VERSION 5.8 ;
BUSBITCHARS "[]" ;
DIVIDERCHAR "/" ;
UNITS
    DATABASE MICRONS 1000 ;
END UNITS

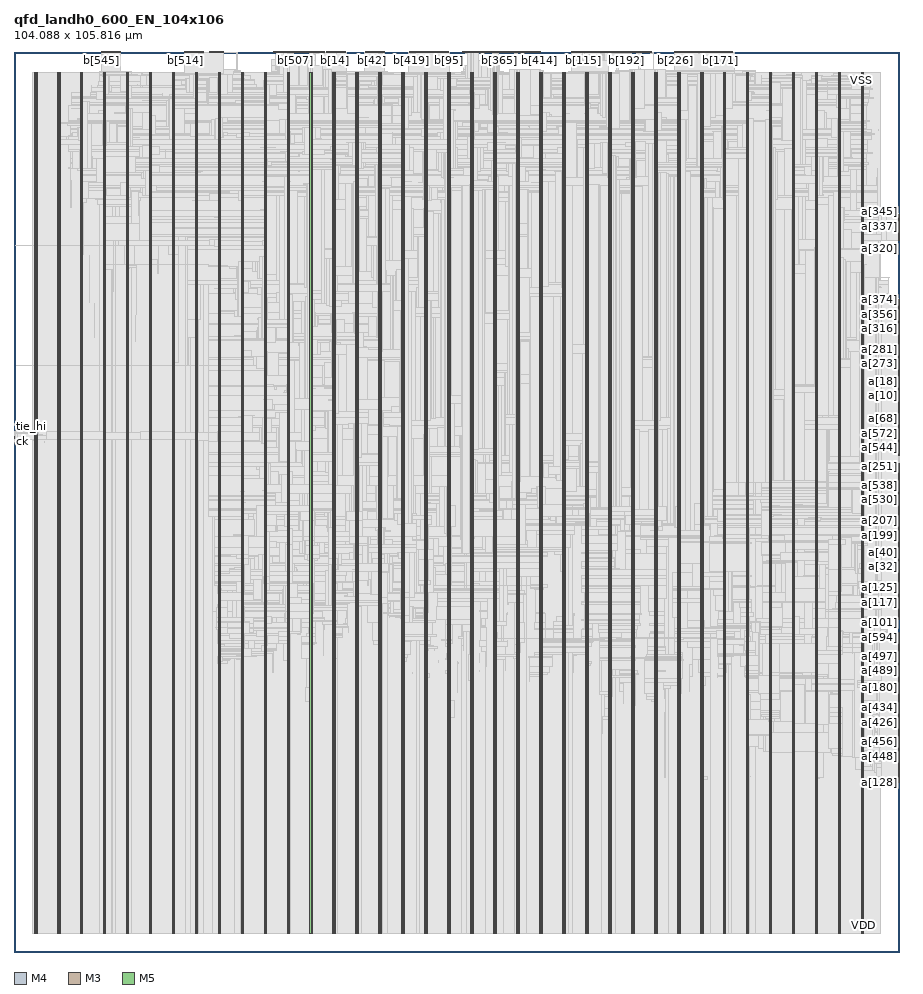
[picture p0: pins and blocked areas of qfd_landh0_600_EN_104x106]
MACRO qfd_landh0_600_EN_104x106
  FOREIGN qfd_landh0_600_EN_104x106 0 0 ;
  CLASS BLOCK ;
  SIZE 104.088 BY 105.816 ;
  PIN a[0]
    DIRECTION INPUT ;
    USE SIGNAL ;
    PORT
      LAYER M4 ;
        RECT  104.004 64.464 104.088 64.488 ;
    END
  END a[0]
  PIN a[100]
    DIRECTION INPUT ;
    USE SIGNAL ;
    PORT
      LAYER M4 ;
        RECT  104.004 39.504 104.088 39.528 ;
    END
  END a[100]
  PIN a[101]
    DIRECTION INPUT ;
    USE SIGNAL ;
    PORT
      LAYER M4 ;
        RECT  104.004 39.6 104.088 39.624 ;
    END
  END a[101]
  PIN a[102]
    DIRECTION INPUT ;
    USE SIGNAL ;
    PORT
      LAYER M4 ;
        RECT  104.004 39.696 104.088 39.72 ;
    END
  END a[102]
  PIN a[103]
    DIRECTION INPUT ;
    USE SIGNAL ;
    PORT
      LAYER M4 ;
        RECT  104.004 39.792 104.088 39.816 ;
    END
  END a[103]
  PIN a[104]
    DIRECTION INPUT ;
    USE SIGNAL ;
    PORT
      LAYER M4 ;
        RECT  104.004 39.888 104.088 39.912 ;
    END
  END a[104]
  PIN a[105]
    DIRECTION INPUT ;
    USE SIGNAL ;
    PORT
      LAYER M4 ;
        RECT  104.004 39.984 104.088 40.008 ;
    END
  END a[105]
  PIN a[106]
    DIRECTION INPUT ;
    USE SIGNAL ;
    PORT
      LAYER M4 ;
        RECT  104.004 40.08 104.088 40.104 ;
    END
  END a[106]
  PIN a[107]
    DIRECTION INPUT ;
    USE SIGNAL ;
    PORT
      LAYER M4 ;
        RECT  104.004 40.176 104.088 40.2 ;
    END
  END a[107]
  PIN a[108]
    DIRECTION INPUT ;
    USE SIGNAL ;
    PORT
      LAYER M4 ;
        RECT  104.004 40.272 104.088 40.296 ;
    END
  END a[108]
  PIN a[109]
    DIRECTION INPUT ;
    USE SIGNAL ;
    PORT
      LAYER M4 ;
        RECT  104.004 40.368 104.088 40.392 ;
    END
  END a[109]
  PIN a[10]
    DIRECTION INPUT ;
    USE SIGNAL ;
    PORT
      LAYER M4 ;
        RECT  104.004 65.424 104.088 65.448 ;
    END
  END a[10]
  PIN a[110]
    DIRECTION INPUT ;
    USE SIGNAL ;
    PORT
      LAYER M4 ;
        RECT  104.004 40.464 104.088 40.488 ;
    END
  END a[110]
  PIN a[111]
    DIRECTION INPUT ;
    USE SIGNAL ;
    PORT
      LAYER M4 ;
        RECT  104.004 40.56 104.088 40.584 ;
    END
  END a[111]
  PIN a[112]
    DIRECTION INPUT ;
    USE SIGNAL ;
    PORT
      LAYER M4 ;
        RECT  104.004 40.656 104.088 40.68 ;
    END
  END a[112]
  PIN a[113]
    DIRECTION INPUT ;
    USE SIGNAL ;
    PORT
      LAYER M4 ;
        RECT  104.004 40.752 104.088 40.776 ;
    END
  END a[113]
  PIN a[114]
    DIRECTION INPUT ;
    USE SIGNAL ;
    PORT
      LAYER M4 ;
        RECT  104.004 40.848 104.088 40.872 ;
    END
  END a[114]
  PIN a[115]
    DIRECTION INPUT ;
    USE SIGNAL ;
    PORT
      LAYER M4 ;
        RECT  104.004 40.944 104.088 40.968 ;
    END
  END a[115]
  PIN a[116]
    DIRECTION INPUT ;
    USE SIGNAL ;
    PORT
      LAYER M4 ;
        RECT  104.004 41.04 104.088 41.064 ;
    END
  END a[116]
  PIN a[117]
    DIRECTION INPUT ;
    USE SIGNAL ;
    PORT
      LAYER M4 ;
        RECT  104.004 41.136 104.088 41.16 ;
    END
  END a[117]
  PIN a[118]
    DIRECTION INPUT ;
    USE SIGNAL ;
    PORT
      LAYER M4 ;
        RECT  104.004 41.232 104.088 41.256 ;
    END
  END a[118]
  PIN a[119]
    DIRECTION INPUT ;
    USE SIGNAL ;
    PORT
      LAYER M4 ;
        RECT  104.004 41.328 104.088 41.352 ;
    END
  END a[119]
  PIN a[11]
    DIRECTION INPUT ;
    USE SIGNAL ;
    PORT
      LAYER M4 ;
        RECT  104.004 65.52 104.088 65.544 ;
    END
  END a[11]
  PIN a[120]
    DIRECTION INPUT ;
    USE SIGNAL ;
    PORT
      LAYER M4 ;
        RECT  104.004 41.424 104.088 41.448 ;
    END
  END a[120]
  PIN a[121]
    DIRECTION INPUT ;
    USE SIGNAL ;
    PORT
      LAYER M4 ;
        RECT  104.004 41.52 104.088 41.544 ;
    END
  END a[121]
  PIN a[122]
    DIRECTION INPUT ;
    USE SIGNAL ;
    PORT
      LAYER M4 ;
        RECT  104.004 41.616 104.088 41.64 ;
    END
  END a[122]
  PIN a[123]
    DIRECTION INPUT ;
    USE SIGNAL ;
    PORT
      LAYER M4 ;
        RECT  104.004 41.712 104.088 41.736 ;
    END
  END a[123]
  PIN a[124]
    DIRECTION INPUT ;
    USE SIGNAL ;
    PORT
      LAYER M4 ;
        RECT  104.004 41.808 104.088 41.832 ;
    END
  END a[124]
  PIN a[125]
    DIRECTION INPUT ;
    USE SIGNAL ;
    PORT
      LAYER M4 ;
        RECT  104.004 41.904 104.088 41.928 ;
    END
  END a[125]
  PIN a[126]
    DIRECTION INPUT ;
    USE SIGNAL ;
    PORT
      LAYER M4 ;
        RECT  104.004 42 104.088 42.024 ;
    END
  END a[126]
  PIN a[127]
    DIRECTION INPUT ;
    USE SIGNAL ;
    PORT
      LAYER M4 ;
        RECT  104.004 42.096 104.088 42.12 ;
    END
  END a[127]
  PIN a[128]
    DIRECTION INPUT ;
    USE SIGNAL ;
    PORT
      LAYER M4 ;
        RECT  104.004 19.92 104.088 19.944 ;
    END
  END a[128]
  PIN a[129]
    DIRECTION INPUT ;
    USE SIGNAL ;
    PORT
      LAYER M4 ;
        RECT  104.004 20.016 104.088 20.04 ;
    END
  END a[129]
  PIN a[12]
    DIRECTION INPUT ;
    USE SIGNAL ;
    PORT
      LAYER M4 ;
        RECT  104.004 65.616 104.088 65.64 ;
    END
  END a[12]
  PIN a[130]
    DIRECTION INPUT ;
    USE SIGNAL ;
    PORT
      LAYER M4 ;
        RECT  104.004 20.112 104.088 20.136 ;
    END
  END a[130]
  PIN a[131]
    DIRECTION INPUT ;
    USE SIGNAL ;
    PORT
      LAYER M4 ;
        RECT  104.004 20.208 104.088 20.232 ;
    END
  END a[131]
  PIN a[132]
    DIRECTION INPUT ;
    USE SIGNAL ;
    PORT
      LAYER M4 ;
        RECT  104.004 20.304 104.088 20.328 ;
    END
  END a[132]
  PIN a[133]
    DIRECTION INPUT ;
    USE SIGNAL ;
    PORT
      LAYER M4 ;
        RECT  104.004 20.4 104.088 20.424 ;
    END
  END a[133]
  PIN a[134]
    DIRECTION INPUT ;
    USE SIGNAL ;
    PORT
      LAYER M4 ;
        RECT  104.004 20.496 104.088 20.52 ;
    END
  END a[134]
  PIN a[135]
    DIRECTION INPUT ;
    USE SIGNAL ;
    PORT
      LAYER M4 ;
        RECT  104.004 20.592 104.088 20.616 ;
    END
  END a[135]
  PIN a[136]
    DIRECTION INPUT ;
    USE SIGNAL ;
    PORT
      LAYER M4 ;
        RECT  104.004 20.688 104.088 20.712 ;
    END
  END a[136]
  PIN a[137]
    DIRECTION INPUT ;
    USE SIGNAL ;
    PORT
      LAYER M4 ;
        RECT  104.004 20.784 104.088 20.808 ;
    END
  END a[137]
  PIN a[138]
    DIRECTION INPUT ;
    USE SIGNAL ;
    PORT
      LAYER M4 ;
        RECT  104.004 20.88 104.088 20.904 ;
    END
  END a[138]
  PIN a[139]
    DIRECTION INPUT ;
    USE SIGNAL ;
    PORT
      LAYER M4 ;
        RECT  104.004 20.976 104.088 21 ;
    END
  END a[139]
  PIN a[13]
    DIRECTION INPUT ;
    USE SIGNAL ;
    PORT
      LAYER M4 ;
        RECT  104.004 65.712 104.088 65.736 ;
    END
  END a[13]
  PIN a[140]
    DIRECTION INPUT ;
    USE SIGNAL ;
    PORT
      LAYER M4 ;
        RECT  104.004 21.072 104.088 21.096 ;
    END
  END a[140]
  PIN a[141]
    DIRECTION INPUT ;
    USE SIGNAL ;
    PORT
      LAYER M4 ;
        RECT  104.004 21.168 104.088 21.192 ;
    END
  END a[141]
  PIN a[142]
    DIRECTION INPUT ;
    USE SIGNAL ;
    PORT
      LAYER M4 ;
        RECT  104.004 21.264 104.088 21.288 ;
    END
  END a[142]
  PIN a[143]
    DIRECTION INPUT ;
    USE SIGNAL ;
    PORT
      LAYER M4 ;
        RECT  104.004 21.36 104.088 21.384 ;
    END
  END a[143]
  PIN a[144]
    DIRECTION INPUT ;
    USE SIGNAL ;
    PORT
      LAYER M4 ;
        RECT  104.004 21.456 104.088 21.48 ;
    END
  END a[144]
  PIN a[145]
    DIRECTION INPUT ;
    USE SIGNAL ;
    PORT
      LAYER M4 ;
        RECT  104.004 21.552 104.088 21.576 ;
    END
  END a[145]
  PIN a[146]
    DIRECTION INPUT ;
    USE SIGNAL ;
    PORT
      LAYER M4 ;
        RECT  104.004 21.648 104.088 21.672 ;
    END
  END a[146]
  PIN a[147]
    DIRECTION INPUT ;
    USE SIGNAL ;
    PORT
      LAYER M4 ;
        RECT  104.004 21.744 104.088 21.768 ;
    END
  END a[147]
  PIN a[148]
    DIRECTION INPUT ;
    USE SIGNAL ;
    PORT
      LAYER M4 ;
        RECT  104.004 21.84 104.088 21.864 ;
    END
  END a[148]
  PIN a[149]
    DIRECTION INPUT ;
    USE SIGNAL ;
    PORT
      LAYER M4 ;
        RECT  104.004 21.936 104.088 21.96 ;
    END
  END a[149]
  PIN a[14]
    DIRECTION INPUT ;
    USE SIGNAL ;
    PORT
      LAYER M4 ;
        RECT  104.004 65.808 104.088 65.832 ;
    END
  END a[14]
  PIN a[150]
    DIRECTION INPUT ;
    USE SIGNAL ;
    PORT
      LAYER M4 ;
        RECT  104.004 22.032 104.088 22.056 ;
    END
  END a[150]
  PIN a[151]
    DIRECTION INPUT ;
    USE SIGNAL ;
    PORT
      LAYER M4 ;
        RECT  104.004 22.128 104.088 22.152 ;
    END
  END a[151]
  PIN a[152]
    DIRECTION INPUT ;
    USE SIGNAL ;
    PORT
      LAYER M4 ;
        RECT  104.004 22.224 104.088 22.248 ;
    END
  END a[152]
  PIN a[153]
    DIRECTION INPUT ;
    USE SIGNAL ;
    PORT
      LAYER M4 ;
        RECT  104.004 22.32 104.088 22.344 ;
    END
  END a[153]
  PIN a[154]
    DIRECTION INPUT ;
    USE SIGNAL ;
    PORT
      LAYER M4 ;
        RECT  104.004 22.416 104.088 22.44 ;
    END
  END a[154]
  PIN a[155]
    DIRECTION INPUT ;
    USE SIGNAL ;
    PORT
      LAYER M4 ;
        RECT  104.004 22.512 104.088 22.536 ;
    END
  END a[155]
  PIN a[156]
    DIRECTION INPUT ;
    USE SIGNAL ;
    PORT
      LAYER M4 ;
        RECT  104.004 22.608 104.088 22.632 ;
    END
  END a[156]
  PIN a[157]
    DIRECTION INPUT ;
    USE SIGNAL ;
    PORT
      LAYER M4 ;
        RECT  104.004 22.704 104.088 22.728 ;
    END
  END a[157]
  PIN a[158]
    DIRECTION INPUT ;
    USE SIGNAL ;
    PORT
      LAYER M4 ;
        RECT  104.004 22.8 104.088 22.824 ;
    END
  END a[158]
  PIN a[159]
    DIRECTION INPUT ;
    USE SIGNAL ;
    PORT
      LAYER M4 ;
        RECT  104.004 22.896 104.088 22.92 ;
    END
  END a[159]
  PIN a[15]
    DIRECTION INPUT ;
    USE SIGNAL ;
    PORT
      LAYER M4 ;
        RECT  104.004 65.904 104.088 65.928 ;
    END
  END a[15]
  PIN a[160]
    DIRECTION INPUT ;
    USE SIGNAL ;
    PORT
      LAYER M4 ;
        RECT  104.004 29.136 104.088 29.16 ;
    END
  END a[160]
  PIN a[161]
    DIRECTION INPUT ;
    USE SIGNAL ;
    PORT
      LAYER M4 ;
        RECT  104.004 29.232 104.088 29.256 ;
    END
  END a[161]
  PIN a[162]
    DIRECTION INPUT ;
    USE SIGNAL ;
    PORT
      LAYER M4 ;
        RECT  104.004 29.328 104.088 29.352 ;
    END
  END a[162]
  PIN a[163]
    DIRECTION INPUT ;
    USE SIGNAL ;
    PORT
      LAYER M4 ;
        RECT  104.004 29.424 104.088 29.448 ;
    END
  END a[163]
  PIN a[164]
    DIRECTION INPUT ;
    USE SIGNAL ;
    PORT
      LAYER M4 ;
        RECT  104.004 29.52 104.088 29.544 ;
    END
  END a[164]
  PIN a[165]
    DIRECTION INPUT ;
    USE SIGNAL ;
    PORT
      LAYER M4 ;
        RECT  104.004 29.616 104.088 29.64 ;
    END
  END a[165]
  PIN a[166]
    DIRECTION INPUT ;
    USE SIGNAL ;
    PORT
      LAYER M4 ;
        RECT  104.004 29.712 104.088 29.736 ;
    END
  END a[166]
  PIN a[167]
    DIRECTION INPUT ;
    USE SIGNAL ;
    PORT
      LAYER M4 ;
        RECT  104.004 29.808 104.088 29.832 ;
    END
  END a[167]
  PIN a[168]
    DIRECTION INPUT ;
    USE SIGNAL ;
    PORT
      LAYER M4 ;
        RECT  104.004 29.904 104.088 29.928 ;
    END
  END a[168]
  PIN a[169]
    DIRECTION INPUT ;
    USE SIGNAL ;
    PORT
      LAYER M4 ;
        RECT  104.004 30 104.088 30.024 ;
    END
  END a[169]
  PIN a[16]
    DIRECTION INPUT ;
    USE SIGNAL ;
    PORT
      LAYER M4 ;
        RECT  104.004 66 104.088 66.024 ;
    END
  END a[16]
  PIN a[170]
    DIRECTION INPUT ;
    USE SIGNAL ;
    PORT
      LAYER M4 ;
        RECT  104.004 30.096 104.088 30.12 ;
    END
  END a[170]
  PIN a[171]
    DIRECTION INPUT ;
    USE SIGNAL ;
    PORT
      LAYER M4 ;
        RECT  104.004 30.192 104.088 30.216 ;
    END
  END a[171]
  PIN a[172]
    DIRECTION INPUT ;
    USE SIGNAL ;
    PORT
      LAYER M4 ;
        RECT  104.004 30.288 104.088 30.312 ;
    END
  END a[172]
  PIN a[173]
    DIRECTION INPUT ;
    USE SIGNAL ;
    PORT
      LAYER M4 ;
        RECT  104.004 30.384 104.088 30.408 ;
    END
  END a[173]
  PIN a[174]
    DIRECTION INPUT ;
    USE SIGNAL ;
    PORT
      LAYER M4 ;
        RECT  104.004 30.48 104.088 30.504 ;
    END
  END a[174]
  PIN a[175]
    DIRECTION INPUT ;
    USE SIGNAL ;
    PORT
      LAYER M4 ;
        RECT  104.004 30.576 104.088 30.6 ;
    END
  END a[175]
  PIN a[176]
    DIRECTION INPUT ;
    USE SIGNAL ;
    PORT
      LAYER M4 ;
        RECT  104.004 30.672 104.088 30.696 ;
    END
  END a[176]
  PIN a[177]
    DIRECTION INPUT ;
    USE SIGNAL ;
    PORT
      LAYER M4 ;
        RECT  104.004 30.768 104.088 30.792 ;
    END
  END a[177]
  PIN a[178]
    DIRECTION INPUT ;
    USE SIGNAL ;
    PORT
      LAYER M4 ;
        RECT  104.004 30.864 104.088 30.888 ;
    END
  END a[178]
  PIN a[179]
    DIRECTION INPUT ;
    USE SIGNAL ;
    PORT
      LAYER M4 ;
        RECT  104.004 30.96 104.088 30.984 ;
    END
  END a[179]
  PIN a[17]
    DIRECTION INPUT ;
    USE SIGNAL ;
    PORT
      LAYER M4 ;
        RECT  104.004 66.096 104.088 66.12 ;
    END
  END a[17]
  PIN a[180]
    DIRECTION INPUT ;
    USE SIGNAL ;
    PORT
      LAYER M4 ;
        RECT  104.004 31.056 104.088 31.08 ;
    END
  END a[180]
  PIN a[181]
    DIRECTION INPUT ;
    USE SIGNAL ;
    PORT
      LAYER M4 ;
        RECT  104.004 31.152 104.088 31.176 ;
    END
  END a[181]
  PIN a[182]
    DIRECTION INPUT ;
    USE SIGNAL ;
    PORT
      LAYER M4 ;
        RECT  104.004 31.248 104.088 31.272 ;
    END
  END a[182]
  PIN a[183]
    DIRECTION INPUT ;
    USE SIGNAL ;
    PORT
      LAYER M4 ;
        RECT  104.004 31.344 104.088 31.368 ;
    END
  END a[183]
  PIN a[184]
    DIRECTION INPUT ;
    USE SIGNAL ;
    PORT
      LAYER M4 ;
        RECT  104.004 31.44 104.088 31.464 ;
    END
  END a[184]
  PIN a[185]
    DIRECTION INPUT ;
    USE SIGNAL ;
    PORT
      LAYER M4 ;
        RECT  104.004 31.536 104.088 31.56 ;
    END
  END a[185]
  PIN a[186]
    DIRECTION INPUT ;
    USE SIGNAL ;
    PORT
      LAYER M4 ;
        RECT  104.004 31.632 104.088 31.656 ;
    END
  END a[186]
  PIN a[187]
    DIRECTION INPUT ;
    USE SIGNAL ;
    PORT
      LAYER M4 ;
        RECT  104.004 31.728 104.088 31.752 ;
    END
  END a[187]
  PIN a[188]
    DIRECTION INPUT ;
    USE SIGNAL ;
    PORT
      LAYER M4 ;
        RECT  104.004 31.824 104.088 31.848 ;
    END
  END a[188]
  PIN a[189]
    DIRECTION INPUT ;
    USE SIGNAL ;
    PORT
      LAYER M4 ;
        RECT  104.004 31.92 104.088 31.944 ;
    END
  END a[189]
  PIN a[18]
    DIRECTION INPUT ;
    USE SIGNAL ;
    PORT
      LAYER M4 ;
        RECT  104.004 66.192 104.088 66.216 ;
    END
  END a[18]
  PIN a[190]
    DIRECTION INPUT ;
    USE SIGNAL ;
    PORT
      LAYER M4 ;
        RECT  104.004 32.016 104.088 32.04 ;
    END
  END a[190]
  PIN a[191]
    DIRECTION INPUT ;
    USE SIGNAL ;
    PORT
      LAYER M4 ;
        RECT  104.004 32.112 104.088 32.136 ;
    END
  END a[191]
  PIN a[192]
    DIRECTION INPUT ;
    USE SIGNAL ;
    PORT
      LAYER M4 ;
        RECT  104.004 48.336 104.088 48.36 ;
    END
  END a[192]
  PIN a[193]
    DIRECTION INPUT ;
    USE SIGNAL ;
    PORT
      LAYER M4 ;
        RECT  104.004 48.432 104.088 48.456 ;
    END
  END a[193]
  PIN a[194]
    DIRECTION INPUT ;
    USE SIGNAL ;
    PORT
      LAYER M4 ;
        RECT  104.004 48.528 104.088 48.552 ;
    END
  END a[194]
  PIN a[195]
    DIRECTION INPUT ;
    USE SIGNAL ;
    PORT
      LAYER M4 ;
        RECT  104.004 48.624 104.088 48.648 ;
    END
  END a[195]
  PIN a[196]
    DIRECTION INPUT ;
    USE SIGNAL ;
    PORT
      LAYER M4 ;
        RECT  104.004 48.72 104.088 48.744 ;
    END
  END a[196]
  PIN a[197]
    DIRECTION INPUT ;
    USE SIGNAL ;
    PORT
      LAYER M4 ;
        RECT  104.004 48.816 104.088 48.84 ;
    END
  END a[197]
  PIN a[198]
    DIRECTION INPUT ;
    USE SIGNAL ;
    PORT
      LAYER M4 ;
        RECT  104.004 48.912 104.088 48.936 ;
    END
  END a[198]
  PIN a[199]
    DIRECTION INPUT ;
    USE SIGNAL ;
    PORT
      LAYER M4 ;
        RECT  104.004 49.008 104.088 49.032 ;
    END
  END a[199]
  PIN a[19]
    DIRECTION INPUT ;
    USE SIGNAL ;
    PORT
      LAYER M4 ;
        RECT  104.004 66.288 104.088 66.312 ;
    END
  END a[19]
  PIN a[1]
    DIRECTION INPUT ;
    USE SIGNAL ;
    PORT
      LAYER M4 ;
        RECT  104.004 64.56 104.088 64.584 ;
    END
  END a[1]
  PIN a[200]
    DIRECTION INPUT ;
    USE SIGNAL ;
    PORT
      LAYER M4 ;
        RECT  104.004 49.104 104.088 49.128 ;
    END
  END a[200]
  PIN a[201]
    DIRECTION INPUT ;
    USE SIGNAL ;
    PORT
      LAYER M4 ;
        RECT  104.004 49.2 104.088 49.224 ;
    END
  END a[201]
  PIN a[202]
    DIRECTION INPUT ;
    USE SIGNAL ;
    PORT
      LAYER M4 ;
        RECT  104.004 49.296 104.088 49.32 ;
    END
  END a[202]
  PIN a[203]
    DIRECTION INPUT ;
    USE SIGNAL ;
    PORT
      LAYER M4 ;
        RECT  104.004 49.392 104.088 49.416 ;
    END
  END a[203]
  PIN a[204]
    DIRECTION INPUT ;
    USE SIGNAL ;
    PORT
      LAYER M4 ;
        RECT  104.004 49.488 104.088 49.512 ;
    END
  END a[204]
  PIN a[205]
    DIRECTION INPUT ;
    USE SIGNAL ;
    PORT
      LAYER M4 ;
        RECT  104.004 49.584 104.088 49.608 ;
    END
  END a[205]
  PIN a[206]
    DIRECTION INPUT ;
    USE SIGNAL ;
    PORT
      LAYER M4 ;
        RECT  104.004 49.68 104.088 49.704 ;
    END
  END a[206]
  PIN a[207]
    DIRECTION INPUT ;
    USE SIGNAL ;
    PORT
      LAYER M4 ;
        RECT  104.004 49.776 104.088 49.8 ;
    END
  END a[207]
  PIN a[208]
    DIRECTION INPUT ;
    USE SIGNAL ;
    PORT
      LAYER M4 ;
        RECT  104.004 49.872 104.088 49.896 ;
    END
  END a[208]
  PIN a[209]
    DIRECTION INPUT ;
    USE SIGNAL ;
    PORT
      LAYER M4 ;
        RECT  104.004 49.968 104.088 49.992 ;
    END
  END a[209]
  PIN a[20]
    DIRECTION INPUT ;
    USE SIGNAL ;
    PORT
      LAYER M4 ;
        RECT  104.004 66.384 104.088 66.408 ;
    END
  END a[20]
  PIN a[210]
    DIRECTION INPUT ;
    USE SIGNAL ;
    PORT
      LAYER M4 ;
        RECT  104.004 50.064 104.088 50.088 ;
    END
  END a[210]
  PIN a[211]
    DIRECTION INPUT ;
    USE SIGNAL ;
    PORT
      LAYER M4 ;
        RECT  104.004 50.16 104.088 50.184 ;
    END
  END a[211]
  PIN a[212]
    DIRECTION INPUT ;
    USE SIGNAL ;
    PORT
      LAYER M4 ;
        RECT  104.004 50.256 104.088 50.28 ;
    END
  END a[212]
  PIN a[213]
    DIRECTION INPUT ;
    USE SIGNAL ;
    PORT
      LAYER M4 ;
        RECT  104.004 50.352 104.088 50.376 ;
    END
  END a[213]
  PIN a[214]
    DIRECTION INPUT ;
    USE SIGNAL ;
    PORT
      LAYER M4 ;
        RECT  104.004 50.448 104.088 50.472 ;
    END
  END a[214]
  PIN a[215]
    DIRECTION INPUT ;
    USE SIGNAL ;
    PORT
      LAYER M4 ;
        RECT  104.004 50.544 104.088 50.568 ;
    END
  END a[215]
  PIN a[216]
    DIRECTION INPUT ;
    USE SIGNAL ;
    PORT
      LAYER M4 ;
        RECT  104.004 50.64 104.088 50.664 ;
    END
  END a[216]
  PIN a[217]
    DIRECTION INPUT ;
    USE SIGNAL ;
    PORT
      LAYER M4 ;
        RECT  104.004 50.736 104.088 50.76 ;
    END
  END a[217]
  PIN a[218]
    DIRECTION INPUT ;
    USE SIGNAL ;
    PORT
      LAYER M4 ;
        RECT  104.004 50.832 104.088 50.856 ;
    END
  END a[218]
  PIN a[219]
    DIRECTION INPUT ;
    USE SIGNAL ;
    PORT
      LAYER M4 ;
        RECT  104.004 50.928 104.088 50.952 ;
    END
  END a[219]
  PIN a[21]
    DIRECTION INPUT ;
    USE SIGNAL ;
    PORT
      LAYER M4 ;
        RECT  104.004 66.48 104.088 66.504 ;
    END
  END a[21]
  PIN a[220]
    DIRECTION INPUT ;
    USE SIGNAL ;
    PORT
      LAYER M4 ;
        RECT  104.004 51.024 104.088 51.048 ;
    END
  END a[220]
  PIN a[221]
    DIRECTION INPUT ;
    USE SIGNAL ;
    PORT
      LAYER M4 ;
        RECT  104.004 51.12 104.088 51.144 ;
    END
  END a[221]
  PIN a[222]
    DIRECTION INPUT ;
    USE SIGNAL ;
    PORT
      LAYER M4 ;
        RECT  104.004 51.216 104.088 51.24 ;
    END
  END a[222]
  PIN a[223]
    DIRECTION INPUT ;
    USE SIGNAL ;
    PORT
      LAYER M4 ;
        RECT  104.004 51.312 104.088 51.336 ;
    END
  END a[223]
  PIN a[224]
    DIRECTION INPUT ;
    USE SIGNAL ;
    PORT
      LAYER M4 ;
        RECT  104.004 54.48 104.088 54.504 ;
    END
  END a[224]
  PIN a[225]
    DIRECTION INPUT ;
    USE SIGNAL ;
    PORT
      LAYER M4 ;
        RECT  104.004 54.576 104.088 54.6 ;
    END
  END a[225]
  PIN a[226]
    DIRECTION INPUT ;
    USE SIGNAL ;
    PORT
      LAYER M4 ;
        RECT  104.004 54.672 104.088 54.696 ;
    END
  END a[226]
  PIN a[227]
    DIRECTION INPUT ;
    USE SIGNAL ;
    PORT
      LAYER M4 ;
        RECT  104.004 54.768 104.088 54.792 ;
    END
  END a[227]
  PIN a[228]
    DIRECTION INPUT ;
    USE SIGNAL ;
    PORT
      LAYER M4 ;
        RECT  104.004 54.864 104.088 54.888 ;
    END
  END a[228]
  PIN a[229]
    DIRECTION INPUT ;
    USE SIGNAL ;
    PORT
      LAYER M4 ;
        RECT  104.004 54.96 104.088 54.984 ;
    END
  END a[229]
  PIN a[22]
    DIRECTION INPUT ;
    USE SIGNAL ;
    PORT
      LAYER M4 ;
        RECT  104.004 66.576 104.088 66.6 ;
    END
  END a[22]
  PIN a[230]
    DIRECTION INPUT ;
    USE SIGNAL ;
    PORT
      LAYER M4 ;
        RECT  104.004 55.056 104.088 55.08 ;
    END
  END a[230]
  PIN a[231]
    DIRECTION INPUT ;
    USE SIGNAL ;
    PORT
      LAYER M4 ;
        RECT  104.004 55.152 104.088 55.176 ;
    END
  END a[231]
  PIN a[232]
    DIRECTION INPUT ;
    USE SIGNAL ;
    PORT
      LAYER M4 ;
        RECT  104.004 55.248 104.088 55.272 ;
    END
  END a[232]
  PIN a[233]
    DIRECTION INPUT ;
    USE SIGNAL ;
    PORT
      LAYER M4 ;
        RECT  104.004 55.344 104.088 55.368 ;
    END
  END a[233]
  PIN a[234]
    DIRECTION INPUT ;
    USE SIGNAL ;
    PORT
      LAYER M4 ;
        RECT  104.004 55.44 104.088 55.464 ;
    END
  END a[234]
  PIN a[235]
    DIRECTION INPUT ;
    USE SIGNAL ;
    PORT
      LAYER M4 ;
        RECT  104.004 55.536 104.088 55.56 ;
    END
  END a[235]
  PIN a[236]
    DIRECTION INPUT ;
    USE SIGNAL ;
    PORT
      LAYER M4 ;
        RECT  104.004 55.632 104.088 55.656 ;
    END
  END a[236]
  PIN a[237]
    DIRECTION INPUT ;
    USE SIGNAL ;
    PORT
      LAYER M4 ;
        RECT  104.004 55.728 104.088 55.752 ;
    END
  END a[237]
  PIN a[238]
    DIRECTION INPUT ;
    USE SIGNAL ;
    PORT
      LAYER M4 ;
        RECT  104.004 55.824 104.088 55.848 ;
    END
  END a[238]
  PIN a[239]
    DIRECTION INPUT ;
    USE SIGNAL ;
    PORT
      LAYER M4 ;
        RECT  104.004 55.92 104.088 55.944 ;
    END
  END a[239]
  PIN a[23]
    DIRECTION INPUT ;
    USE SIGNAL ;
    PORT
      LAYER M4 ;
        RECT  104.004 66.672 104.088 66.696 ;
    END
  END a[23]
  PIN a[240]
    DIRECTION INPUT ;
    USE SIGNAL ;
    PORT
      LAYER M4 ;
        RECT  104.004 56.016 104.088 56.04 ;
    END
  END a[240]
  PIN a[241]
    DIRECTION INPUT ;
    USE SIGNAL ;
    PORT
      LAYER M4 ;
        RECT  104.004 56.112 104.088 56.136 ;
    END
  END a[241]
  PIN a[242]
    DIRECTION INPUT ;
    USE SIGNAL ;
    PORT
      LAYER M4 ;
        RECT  104.004 56.208 104.088 56.232 ;
    END
  END a[242]
  PIN a[243]
    DIRECTION INPUT ;
    USE SIGNAL ;
    PORT
      LAYER M4 ;
        RECT  104.004 56.304 104.088 56.328 ;
    END
  END a[243]
  PIN a[244]
    DIRECTION INPUT ;
    USE SIGNAL ;
    PORT
      LAYER M4 ;
        RECT  104.004 56.4 104.088 56.424 ;
    END
  END a[244]
  PIN a[245]
    DIRECTION INPUT ;
    USE SIGNAL ;
    PORT
      LAYER M4 ;
        RECT  104.004 56.496 104.088 56.52 ;
    END
  END a[245]
  PIN a[246]
    DIRECTION INPUT ;
    USE SIGNAL ;
    PORT
      LAYER M4 ;
        RECT  104.004 56.592 104.088 56.616 ;
    END
  END a[246]
  PIN a[247]
    DIRECTION INPUT ;
    USE SIGNAL ;
    PORT
      LAYER M4 ;
        RECT  104.004 56.688 104.088 56.712 ;
    END
  END a[247]
  PIN a[248]
    DIRECTION INPUT ;
    USE SIGNAL ;
    PORT
      LAYER M4 ;
        RECT  104.004 56.784 104.088 56.808 ;
    END
  END a[248]
  PIN a[249]
    DIRECTION INPUT ;
    USE SIGNAL ;
    PORT
      LAYER M4 ;
        RECT  104.004 56.88 104.088 56.904 ;
    END
  END a[249]
  PIN a[24]
    DIRECTION INPUT ;
    USE SIGNAL ;
    PORT
      LAYER M4 ;
        RECT  104.004 66.768 104.088 66.792 ;
    END
  END a[24]
  PIN a[250]
    DIRECTION INPUT ;
    USE SIGNAL ;
    PORT
      LAYER M4 ;
        RECT  104.004 56.976 104.088 57 ;
    END
  END a[250]
  PIN a[251]
    DIRECTION INPUT ;
    USE SIGNAL ;
    PORT
      LAYER M4 ;
        RECT  104.004 57.072 104.088 57.096 ;
    END
  END a[251]
  PIN a[252]
    DIRECTION INPUT ;
    USE SIGNAL ;
    PORT
      LAYER M4 ;
        RECT  104.004 57.168 104.088 57.192 ;
    END
  END a[252]
  PIN a[253]
    DIRECTION INPUT ;
    USE SIGNAL ;
    PORT
      LAYER M4 ;
        RECT  104.004 57.264 104.088 57.288 ;
    END
  END a[253]
  PIN a[254]
    DIRECTION INPUT ;
    USE SIGNAL ;
    PORT
      LAYER M4 ;
        RECT  104.004 57.36 104.088 57.384 ;
    END
  END a[254]
  PIN a[255]
    DIRECTION INPUT ;
    USE SIGNAL ;
    PORT
      LAYER M4 ;
        RECT  104.004 57.456 104.088 57.48 ;
    END
  END a[255]
  PIN a[256]
    DIRECTION INPUT ;
    USE SIGNAL ;
    PORT
      LAYER M4 ;
        RECT  104.004 67.536 104.088 67.56 ;
    END
  END a[256]
  PIN a[257]
    DIRECTION INPUT ;
    USE SIGNAL ;
    PORT
      LAYER M4 ;
        RECT  104.004 67.632 104.088 67.656 ;
    END
  END a[257]
  PIN a[258]
    DIRECTION INPUT ;
    USE SIGNAL ;
    PORT
      LAYER M4 ;
        RECT  104.004 67.728 104.088 67.752 ;
    END
  END a[258]
  PIN a[259]
    DIRECTION INPUT ;
    USE SIGNAL ;
    PORT
      LAYER M4 ;
        RECT  104.004 67.824 104.088 67.848 ;
    END
  END a[259]
  PIN a[25]
    DIRECTION INPUT ;
    USE SIGNAL ;
    PORT
      LAYER M4 ;
        RECT  104.004 66.864 104.088 66.888 ;
    END
  END a[25]
  PIN a[260]
    DIRECTION INPUT ;
    USE SIGNAL ;
    PORT
      LAYER M4 ;
        RECT  104.004 67.92 104.088 67.944 ;
    END
  END a[260]
  PIN a[261]
    DIRECTION INPUT ;
    USE SIGNAL ;
    PORT
      LAYER M4 ;
        RECT  104.004 68.016 104.088 68.04 ;
    END
  END a[261]
  PIN a[262]
    DIRECTION INPUT ;
    USE SIGNAL ;
    PORT
      LAYER M4 ;
        RECT  104.004 68.112 104.088 68.136 ;
    END
  END a[262]
  PIN a[263]
    DIRECTION INPUT ;
    USE SIGNAL ;
    PORT
      LAYER M4 ;
        RECT  104.004 68.208 104.088 68.232 ;
    END
  END a[263]
  PIN a[264]
    DIRECTION INPUT ;
    USE SIGNAL ;
    PORT
      LAYER M4 ;
        RECT  104.004 68.304 104.088 68.328 ;
    END
  END a[264]
  PIN a[265]
    DIRECTION INPUT ;
    USE SIGNAL ;
    PORT
      LAYER M4 ;
        RECT  104.004 68.4 104.088 68.424 ;
    END
  END a[265]
  PIN a[266]
    DIRECTION INPUT ;
    USE SIGNAL ;
    PORT
      LAYER M4 ;
        RECT  104.004 68.496 104.088 68.52 ;
    END
  END a[266]
  PIN a[267]
    DIRECTION INPUT ;
    USE SIGNAL ;
    PORT
      LAYER M4 ;
        RECT  104.004 68.592 104.088 68.616 ;
    END
  END a[267]
  PIN a[268]
    DIRECTION INPUT ;
    USE SIGNAL ;
    PORT
      LAYER M4 ;
        RECT  104.004 68.688 104.088 68.712 ;
    END
  END a[268]
  PIN a[269]
    DIRECTION INPUT ;
    USE SIGNAL ;
    PORT
      LAYER M4 ;
        RECT  104.004 68.784 104.088 68.808 ;
    END
  END a[269]
  PIN a[26]
    DIRECTION INPUT ;
    USE SIGNAL ;
    PORT
      LAYER M4 ;
        RECT  104.004 66.96 104.088 66.984 ;
    END
  END a[26]
  PIN a[270]
    DIRECTION INPUT ;
    USE SIGNAL ;
    PORT
      LAYER M4 ;
        RECT  104.004 68.88 104.088 68.904 ;
    END
  END a[270]
  PIN a[271]
    DIRECTION INPUT ;
    USE SIGNAL ;
    PORT
      LAYER M4 ;
        RECT  104.004 68.976 104.088 69 ;
    END
  END a[271]
  PIN a[272]
    DIRECTION INPUT ;
    USE SIGNAL ;
    PORT
      LAYER M4 ;
        RECT  104.004 69.072 104.088 69.096 ;
    END
  END a[272]
  PIN a[273]
    DIRECTION INPUT ;
    USE SIGNAL ;
    PORT
      LAYER M4 ;
        RECT  104.004 69.168 104.088 69.192 ;
    END
  END a[273]
  PIN a[274]
    DIRECTION INPUT ;
    USE SIGNAL ;
    PORT
      LAYER M4 ;
        RECT  104.004 69.264 104.088 69.288 ;
    END
  END a[274]
  PIN a[275]
    DIRECTION INPUT ;
    USE SIGNAL ;
    PORT
      LAYER M4 ;
        RECT  104.004 69.36 104.088 69.384 ;
    END
  END a[275]
  PIN a[276]
    DIRECTION INPUT ;
    USE SIGNAL ;
    PORT
      LAYER M4 ;
        RECT  104.004 69.456 104.088 69.48 ;
    END
  END a[276]
  PIN a[277]
    DIRECTION INPUT ;
    USE SIGNAL ;
    PORT
      LAYER M4 ;
        RECT  104.004 69.552 104.088 69.576 ;
    END
  END a[277]
  PIN a[278]
    DIRECTION INPUT ;
    USE SIGNAL ;
    PORT
      LAYER M4 ;
        RECT  104.004 69.648 104.088 69.672 ;
    END
  END a[278]
  PIN a[279]
    DIRECTION INPUT ;
    USE SIGNAL ;
    PORT
      LAYER M4 ;
        RECT  104.004 69.744 104.088 69.768 ;
    END
  END a[279]
  PIN a[27]
    DIRECTION INPUT ;
    USE SIGNAL ;
    PORT
      LAYER M4 ;
        RECT  104.004 67.056 104.088 67.08 ;
    END
  END a[27]
  PIN a[280]
    DIRECTION INPUT ;
    USE SIGNAL ;
    PORT
      LAYER M4 ;
        RECT  104.004 69.84 104.088 69.864 ;
    END
  END a[280]
  PIN a[281]
    DIRECTION INPUT ;
    USE SIGNAL ;
    PORT
      LAYER M4 ;
        RECT  104.004 69.936 104.088 69.96 ;
    END
  END a[281]
  PIN a[282]
    DIRECTION INPUT ;
    USE SIGNAL ;
    PORT
      LAYER M4 ;
        RECT  104.004 70.032 104.088 70.056 ;
    END
  END a[282]
  PIN a[283]
    DIRECTION INPUT ;
    USE SIGNAL ;
    PORT
      LAYER M4 ;
        RECT  104.004 70.128 104.088 70.152 ;
    END
  END a[283]
  PIN a[284]
    DIRECTION INPUT ;
    USE SIGNAL ;
    PORT
      LAYER M4 ;
        RECT  104.004 70.224 104.088 70.248 ;
    END
  END a[284]
  PIN a[285]
    DIRECTION INPUT ;
    USE SIGNAL ;
    PORT
      LAYER M4 ;
        RECT  104.004 70.32 104.088 70.344 ;
    END
  END a[285]
  PIN a[286]
    DIRECTION INPUT ;
    USE SIGNAL ;
    PORT
      LAYER M4 ;
        RECT  104.004 70.416 104.088 70.44 ;
    END
  END a[286]
  PIN a[287]
    DIRECTION INPUT ;
    USE SIGNAL ;
    PORT
      LAYER M4 ;
        RECT  104.004 70.512 104.088 70.536 ;
    END
  END a[287]
  PIN a[288]
    DIRECTION INPUT ;
    USE SIGNAL ;
    PORT
      LAYER M4 ;
        RECT  104.004 70.608 104.088 70.632 ;
    END
  END a[288]
  PIN a[289]
    DIRECTION INPUT ;
    USE SIGNAL ;
    PORT
      LAYER M4 ;
        RECT  104.004 70.704 104.088 70.728 ;
    END
  END a[289]
  PIN a[28]
    DIRECTION INPUT ;
    USE SIGNAL ;
    PORT
      LAYER M4 ;
        RECT  104.004 67.152 104.088 67.176 ;
    END
  END a[28]
  PIN a[290]
    DIRECTION INPUT ;
    USE SIGNAL ;
    PORT
      LAYER M4 ;
        RECT  104.004 70.8 104.088 70.824 ;
    END
  END a[290]
  PIN a[291]
    DIRECTION INPUT ;
    USE SIGNAL ;
    PORT
      LAYER M4 ;
        RECT  104.004 70.896 104.088 70.92 ;
    END
  END a[291]
  PIN a[292]
    DIRECTION INPUT ;
    USE SIGNAL ;
    PORT
      LAYER M4 ;
        RECT  104.004 70.992 104.088 71.016 ;
    END
  END a[292]
  PIN a[293]
    DIRECTION INPUT ;
    USE SIGNAL ;
    PORT
      LAYER M4 ;
        RECT  104.004 71.088 104.088 71.112 ;
    END
  END a[293]
  PIN a[294]
    DIRECTION INPUT ;
    USE SIGNAL ;
    PORT
      LAYER M4 ;
        RECT  104.004 71.184 104.088 71.208 ;
    END
  END a[294]
  PIN a[295]
    DIRECTION INPUT ;
    USE SIGNAL ;
    PORT
      LAYER M4 ;
        RECT  104.004 71.28 104.088 71.304 ;
    END
  END a[295]
  PIN a[296]
    DIRECTION INPUT ;
    USE SIGNAL ;
    PORT
      LAYER M4 ;
        RECT  104.004 71.376 104.088 71.4 ;
    END
  END a[296]
  PIN a[297]
    DIRECTION INPUT ;
    USE SIGNAL ;
    PORT
      LAYER M4 ;
        RECT  104.004 71.472 104.088 71.496 ;
    END
  END a[297]
  PIN a[298]
    DIRECTION INPUT ;
    USE SIGNAL ;
    PORT
      LAYER M4 ;
        RECT  104.004 71.568 104.088 71.592 ;
    END
  END a[298]
  PIN a[299]
    DIRECTION INPUT ;
    USE SIGNAL ;
    PORT
      LAYER M4 ;
        RECT  104.004 71.664 104.088 71.688 ;
    END
  END a[299]
  PIN a[29]
    DIRECTION INPUT ;
    USE SIGNAL ;
    PORT
      LAYER M4 ;
        RECT  104.004 67.248 104.088 67.272 ;
    END
  END a[29]
  PIN a[2]
    DIRECTION INPUT ;
    USE SIGNAL ;
    PORT
      LAYER M4 ;
        RECT  104.004 64.656 104.088 64.68 ;
    END
  END a[2]
  PIN a[300]
    DIRECTION INPUT ;
    USE SIGNAL ;
    PORT
      LAYER M4 ;
        RECT  104.004 71.76 104.088 71.784 ;
    END
  END a[300]
  PIN a[301]
    DIRECTION INPUT ;
    USE SIGNAL ;
    PORT
      LAYER M4 ;
        RECT  104.004 71.856 104.088 71.88 ;
    END
  END a[301]
  PIN a[302]
    DIRECTION INPUT ;
    USE SIGNAL ;
    PORT
      LAYER M4 ;
        RECT  104.004 71.952 104.088 71.976 ;
    END
  END a[302]
  PIN a[303]
    DIRECTION INPUT ;
    USE SIGNAL ;
    PORT
      LAYER M4 ;
        RECT  104.004 72.048 104.088 72.072 ;
    END
  END a[303]
  PIN a[304]
    DIRECTION INPUT ;
    USE SIGNAL ;
    PORT
      LAYER M4 ;
        RECT  104.004 72.144 104.088 72.168 ;
    END
  END a[304]
  PIN a[305]
    DIRECTION INPUT ;
    USE SIGNAL ;
    PORT
      LAYER M4 ;
        RECT  104.004 72.24 104.088 72.264 ;
    END
  END a[305]
  PIN a[306]
    DIRECTION INPUT ;
    USE SIGNAL ;
    PORT
      LAYER M4 ;
        RECT  104.004 72.336 104.088 72.36 ;
    END
  END a[306]
  PIN a[307]
    DIRECTION INPUT ;
    USE SIGNAL ;
    PORT
      LAYER M4 ;
        RECT  104.004 72.432 104.088 72.456 ;
    END
  END a[307]
  PIN a[308]
    DIRECTION INPUT ;
    USE SIGNAL ;
    PORT
      LAYER M4 ;
        RECT  104.004 72.528 104.088 72.552 ;
    END
  END a[308]
  PIN a[309]
    DIRECTION INPUT ;
    USE SIGNAL ;
    PORT
      LAYER M4 ;
        RECT  104.004 72.624 104.088 72.648 ;
    END
  END a[309]
  PIN a[30]
    DIRECTION INPUT ;
    USE SIGNAL ;
    PORT
      LAYER M4 ;
        RECT  104.004 67.344 104.088 67.368 ;
    END
  END a[30]
  PIN a[310]
    DIRECTION INPUT ;
    USE SIGNAL ;
    PORT
      LAYER M4 ;
        RECT  104.004 72.72 104.088 72.744 ;
    END
  END a[310]
  PIN a[311]
    DIRECTION INPUT ;
    USE SIGNAL ;
    PORT
      LAYER M4 ;
        RECT  104.004 72.816 104.088 72.84 ;
    END
  END a[311]
  PIN a[312]
    DIRECTION INPUT ;
    USE SIGNAL ;
    PORT
      LAYER M4 ;
        RECT  104.004 72.912 104.088 72.936 ;
    END
  END a[312]
  PIN a[313]
    DIRECTION INPUT ;
    USE SIGNAL ;
    PORT
      LAYER M4 ;
        RECT  104.004 73.008 104.088 73.032 ;
    END
  END a[313]
  PIN a[314]
    DIRECTION INPUT ;
    USE SIGNAL ;
    PORT
      LAYER M4 ;
        RECT  104.004 73.104 104.088 73.128 ;
    END
  END a[314]
  PIN a[315]
    DIRECTION INPUT ;
    USE SIGNAL ;
    PORT
      LAYER M4 ;
        RECT  104.004 73.2 104.088 73.224 ;
    END
  END a[315]
  PIN a[316]
    DIRECTION INPUT ;
    USE SIGNAL ;
    PORT
      LAYER M4 ;
        RECT  104.004 73.296 104.088 73.32 ;
    END
  END a[316]
  PIN a[317]
    DIRECTION INPUT ;
    USE SIGNAL ;
    PORT
      LAYER M4 ;
        RECT  104.004 73.392 104.088 73.416 ;
    END
  END a[317]
  PIN a[318]
    DIRECTION INPUT ;
    USE SIGNAL ;
    PORT
      LAYER M4 ;
        RECT  104.004 73.488 104.088 73.512 ;
    END
  END a[318]
  PIN a[319]
    DIRECTION INPUT ;
    USE SIGNAL ;
    PORT
      LAYER M4 ;
        RECT  104.004 73.584 104.088 73.608 ;
    END
  END a[319]
  PIN a[31]
    DIRECTION INPUT ;
    USE SIGNAL ;
    PORT
      LAYER M4 ;
        RECT  104.004 67.44 104.088 67.464 ;
    END
  END a[31]
  PIN a[320]
    DIRECTION INPUT ;
    USE SIGNAL ;
    PORT
      LAYER M4 ;
        RECT  104.004 83.664 104.088 83.688 ;
    END
  END a[320]
  PIN a[321]
    DIRECTION INPUT ;
    USE SIGNAL ;
    PORT
      LAYER M4 ;
        RECT  104.004 83.76 104.088 83.784 ;
    END
  END a[321]
  PIN a[322]
    DIRECTION INPUT ;
    USE SIGNAL ;
    PORT
      LAYER M4 ;
        RECT  104.004 83.856 104.088 83.88 ;
    END
  END a[322]
  PIN a[323]
    DIRECTION INPUT ;
    USE SIGNAL ;
    PORT
      LAYER M4 ;
        RECT  104.004 83.952 104.088 83.976 ;
    END
  END a[323]
  PIN a[324]
    DIRECTION INPUT ;
    USE SIGNAL ;
    PORT
      LAYER M4 ;
        RECT  104.004 84.048 104.088 84.072 ;
    END
  END a[324]
  PIN a[325]
    DIRECTION INPUT ;
    USE SIGNAL ;
    PORT
      LAYER M4 ;
        RECT  104.004 84.144 104.088 84.168 ;
    END
  END a[325]
  PIN a[326]
    DIRECTION INPUT ;
    USE SIGNAL ;
    PORT
      LAYER M4 ;
        RECT  104.004 84.24 104.088 84.264 ;
    END
  END a[326]
  PIN a[327]
    DIRECTION INPUT ;
    USE SIGNAL ;
    PORT
      LAYER M4 ;
        RECT  104.004 84.336 104.088 84.36 ;
    END
  END a[327]
  PIN a[328]
    DIRECTION INPUT ;
    USE SIGNAL ;
    PORT
      LAYER M4 ;
        RECT  104.004 84.432 104.088 84.456 ;
    END
  END a[328]
  PIN a[329]
    DIRECTION INPUT ;
    USE SIGNAL ;
    PORT
      LAYER M4 ;
        RECT  104.004 84.528 104.088 84.552 ;
    END
  END a[329]
  PIN a[32]
    DIRECTION INPUT ;
    USE SIGNAL ;
    PORT
      LAYER M4 ;
        RECT  104.004 45.264 104.088 45.288 ;
    END
  END a[32]
  PIN a[330]
    DIRECTION INPUT ;
    USE SIGNAL ;
    PORT
      LAYER M4 ;
        RECT  104.004 84.624 104.088 84.648 ;
    END
  END a[330]
  PIN a[331]
    DIRECTION INPUT ;
    USE SIGNAL ;
    PORT
      LAYER M4 ;
        RECT  104.004 84.72 104.088 84.744 ;
    END
  END a[331]
  PIN a[332]
    DIRECTION INPUT ;
    USE SIGNAL ;
    PORT
      LAYER M4 ;
        RECT  104.004 84.816 104.088 84.84 ;
    END
  END a[332]
  PIN a[333]
    DIRECTION INPUT ;
    USE SIGNAL ;
    PORT
      LAYER M4 ;
        RECT  104.004 84.912 104.088 84.936 ;
    END
  END a[333]
  PIN a[334]
    DIRECTION INPUT ;
    USE SIGNAL ;
    PORT
      LAYER M4 ;
        RECT  104.004 85.008 104.088 85.032 ;
    END
  END a[334]
  PIN a[335]
    DIRECTION INPUT ;
    USE SIGNAL ;
    PORT
      LAYER M4 ;
        RECT  104.004 85.104 104.088 85.128 ;
    END
  END a[335]
  PIN a[336]
    DIRECTION INPUT ;
    USE SIGNAL ;
    PORT
      LAYER M4 ;
        RECT  104.004 85.2 104.088 85.224 ;
    END
  END a[336]
  PIN a[337]
    DIRECTION INPUT ;
    USE SIGNAL ;
    PORT
      LAYER M4 ;
        RECT  104.004 85.296 104.088 85.32 ;
    END
  END a[337]
  PIN a[338]
    DIRECTION INPUT ;
    USE SIGNAL ;
    PORT
      LAYER M4 ;
        RECT  104.004 85.392 104.088 85.416 ;
    END
  END a[338]
  PIN a[339]
    DIRECTION INPUT ;
    USE SIGNAL ;
    PORT
      LAYER M4 ;
        RECT  104.004 85.488 104.088 85.512 ;
    END
  END a[339]
  PIN a[33]
    DIRECTION INPUT ;
    USE SIGNAL ;
    PORT
      LAYER M4 ;
        RECT  104.004 45.36 104.088 45.384 ;
    END
  END a[33]
  PIN a[340]
    DIRECTION INPUT ;
    USE SIGNAL ;
    PORT
      LAYER M4 ;
        RECT  104.004 85.584 104.088 85.608 ;
    END
  END a[340]
  PIN a[341]
    DIRECTION INPUT ;
    USE SIGNAL ;
    PORT
      LAYER M4 ;
        RECT  104.004 85.68 104.088 85.704 ;
    END
  END a[341]
  PIN a[342]
    DIRECTION INPUT ;
    USE SIGNAL ;
    PORT
      LAYER M4 ;
        RECT  104.004 85.776 104.088 85.8 ;
    END
  END a[342]
  PIN a[343]
    DIRECTION INPUT ;
    USE SIGNAL ;
    PORT
      LAYER M4 ;
        RECT  104.004 85.872 104.088 85.896 ;
    END
  END a[343]
  PIN a[344]
    DIRECTION INPUT ;
    USE SIGNAL ;
    PORT
      LAYER M4 ;
        RECT  104.004 85.968 104.088 85.992 ;
    END
  END a[344]
  PIN a[345]
    DIRECTION INPUT ;
    USE SIGNAL ;
    PORT
      LAYER M4 ;
        RECT  104.004 86.064 104.088 86.088 ;
    END
  END a[345]
  PIN a[346]
    DIRECTION INPUT ;
    USE SIGNAL ;
    PORT
      LAYER M4 ;
        RECT  104.004 86.16 104.088 86.184 ;
    END
  END a[346]
  PIN a[347]
    DIRECTION INPUT ;
    USE SIGNAL ;
    PORT
      LAYER M4 ;
        RECT  104.004 86.256 104.088 86.28 ;
    END
  END a[347]
  PIN a[348]
    DIRECTION INPUT ;
    USE SIGNAL ;
    PORT
      LAYER M4 ;
        RECT  104.004 86.352 104.088 86.376 ;
    END
  END a[348]
  PIN a[349]
    DIRECTION INPUT ;
    USE SIGNAL ;
    PORT
      LAYER M4 ;
        RECT  104.004 86.448 104.088 86.472 ;
    END
  END a[349]
  PIN a[34]
    DIRECTION INPUT ;
    USE SIGNAL ;
    PORT
      LAYER M4 ;
        RECT  104.004 45.456 104.088 45.48 ;
    END
  END a[34]
  PIN a[350]
    DIRECTION INPUT ;
    USE SIGNAL ;
    PORT
      LAYER M4 ;
        RECT  104.004 86.544 104.088 86.568 ;
    END
  END a[350]
  PIN a[351]
    DIRECTION INPUT ;
    USE SIGNAL ;
    PORT
      LAYER M4 ;
        RECT  104.004 86.64 104.088 86.664 ;
    END
  END a[351]
  PIN a[352]
    DIRECTION INPUT ;
    USE SIGNAL ;
    PORT
      LAYER M4 ;
        RECT  104.004 73.68 104.088 73.704 ;
    END
  END a[352]
  PIN a[353]
    DIRECTION INPUT ;
    USE SIGNAL ;
    PORT
      LAYER M4 ;
        RECT  104.004 73.776 104.088 73.8 ;
    END
  END a[353]
  PIN a[354]
    DIRECTION INPUT ;
    USE SIGNAL ;
    PORT
      LAYER M4 ;
        RECT  104.004 73.872 104.088 73.896 ;
    END
  END a[354]
  PIN a[355]
    DIRECTION INPUT ;
    USE SIGNAL ;
    PORT
      LAYER M4 ;
        RECT  104.004 73.968 104.088 73.992 ;
    END
  END a[355]
  PIN a[356]
    DIRECTION INPUT ;
    USE SIGNAL ;
    PORT
      LAYER M4 ;
        RECT  104.004 74.064 104.088 74.088 ;
    END
  END a[356]
  PIN a[357]
    DIRECTION INPUT ;
    USE SIGNAL ;
    PORT
      LAYER M4 ;
        RECT  104.004 74.16 104.088 74.184 ;
    END
  END a[357]
  PIN a[358]
    DIRECTION INPUT ;
    USE SIGNAL ;
    PORT
      LAYER M4 ;
        RECT  104.004 74.256 104.088 74.28 ;
    END
  END a[358]
  PIN a[359]
    DIRECTION INPUT ;
    USE SIGNAL ;
    PORT
      LAYER M4 ;
        RECT  104.004 74.352 104.088 74.376 ;
    END
  END a[359]
  PIN a[35]
    DIRECTION INPUT ;
    USE SIGNAL ;
    PORT
      LAYER M4 ;
        RECT  104.004 45.552 104.088 45.576 ;
    END
  END a[35]
  PIN a[360]
    DIRECTION INPUT ;
    USE SIGNAL ;
    PORT
      LAYER M4 ;
        RECT  104.004 74.448 104.088 74.472 ;
    END
  END a[360]
  PIN a[361]
    DIRECTION INPUT ;
    USE SIGNAL ;
    PORT
      LAYER M4 ;
        RECT  104.004 74.544 104.088 74.568 ;
    END
  END a[361]
  PIN a[362]
    DIRECTION INPUT ;
    USE SIGNAL ;
    PORT
      LAYER M4 ;
        RECT  104.004 74.64 104.088 74.664 ;
    END
  END a[362]
  PIN a[363]
    DIRECTION INPUT ;
    USE SIGNAL ;
    PORT
      LAYER M4 ;
        RECT  104.004 74.736 104.088 74.76 ;
    END
  END a[363]
  PIN a[364]
    DIRECTION INPUT ;
    USE SIGNAL ;
    PORT
      LAYER M4 ;
        RECT  104.004 74.832 104.088 74.856 ;
    END
  END a[364]
  PIN a[365]
    DIRECTION INPUT ;
    USE SIGNAL ;
    PORT
      LAYER M4 ;
        RECT  104.004 74.928 104.088 74.952 ;
    END
  END a[365]
  PIN a[366]
    DIRECTION INPUT ;
    USE SIGNAL ;
    PORT
      LAYER M4 ;
        RECT  104.004 75.024 104.088 75.048 ;
    END
  END a[366]
  PIN a[367]
    DIRECTION INPUT ;
    USE SIGNAL ;
    PORT
      LAYER M4 ;
        RECT  104.004 75.12 104.088 75.144 ;
    END
  END a[367]
  PIN a[368]
    DIRECTION INPUT ;
    USE SIGNAL ;
    PORT
      LAYER M4 ;
        RECT  104.004 75.216 104.088 75.24 ;
    END
  END a[368]
  PIN a[369]
    DIRECTION INPUT ;
    USE SIGNAL ;
    PORT
      LAYER M4 ;
        RECT  104.004 75.312 104.088 75.336 ;
    END
  END a[369]
  PIN a[36]
    DIRECTION INPUT ;
    USE SIGNAL ;
    PORT
      LAYER M4 ;
        RECT  104.004 45.648 104.088 45.672 ;
    END
  END a[36]
  PIN a[370]
    DIRECTION INPUT ;
    USE SIGNAL ;
    PORT
      LAYER M4 ;
        RECT  104.004 75.408 104.088 75.432 ;
    END
  END a[370]
  PIN a[371]
    DIRECTION INPUT ;
    USE SIGNAL ;
    PORT
      LAYER M4 ;
        RECT  104.004 75.504 104.088 75.528 ;
    END
  END a[371]
  PIN a[372]
    DIRECTION INPUT ;
    USE SIGNAL ;
    PORT
      LAYER M4 ;
        RECT  104.004 75.6 104.088 75.624 ;
    END
  END a[372]
  PIN a[373]
    DIRECTION INPUT ;
    USE SIGNAL ;
    PORT
      LAYER M4 ;
        RECT  104.004 75.696 104.088 75.72 ;
    END
  END a[373]
  PIN a[374]
    DIRECTION INPUT ;
    USE SIGNAL ;
    PORT
      LAYER M4 ;
        RECT  104.004 75.792 104.088 75.816 ;
    END
  END a[374]
  PIN a[375]
    DIRECTION INPUT ;
    USE SIGNAL ;
    PORT
      LAYER M4 ;
        RECT  104.004 75.888 104.088 75.912 ;
    END
  END a[375]
  PIN a[376]
    DIRECTION INPUT ;
    USE SIGNAL ;
    PORT
      LAYER M4 ;
        RECT  104.004 75.984 104.088 76.008 ;
    END
  END a[376]
  PIN a[377]
    DIRECTION INPUT ;
    USE SIGNAL ;
    PORT
      LAYER M4 ;
        RECT  104.004 76.08 104.088 76.104 ;
    END
  END a[377]
  PIN a[378]
    DIRECTION INPUT ;
    USE SIGNAL ;
    PORT
      LAYER M4 ;
        RECT  104.004 76.176 104.088 76.2 ;
    END
  END a[378]
  PIN a[379]
    DIRECTION INPUT ;
    USE SIGNAL ;
    PORT
      LAYER M4 ;
        RECT  104.004 76.272 104.088 76.296 ;
    END
  END a[379]
  PIN a[37]
    DIRECTION INPUT ;
    USE SIGNAL ;
    PORT
      LAYER M4 ;
        RECT  104.004 45.744 104.088 45.768 ;
    END
  END a[37]
  PIN a[380]
    DIRECTION INPUT ;
    USE SIGNAL ;
    PORT
      LAYER M4 ;
        RECT  104.004 76.368 104.088 76.392 ;
    END
  END a[380]
  PIN a[381]
    DIRECTION INPUT ;
    USE SIGNAL ;
    PORT
      LAYER M4 ;
        RECT  104.004 76.464 104.088 76.488 ;
    END
  END a[381]
  PIN a[382]
    DIRECTION INPUT ;
    USE SIGNAL ;
    PORT
      LAYER M4 ;
        RECT  104.004 76.56 104.088 76.584 ;
    END
  END a[382]
  PIN a[383]
    DIRECTION INPUT ;
    USE SIGNAL ;
    PORT
      LAYER M4 ;
        RECT  104.004 76.656 104.088 76.68 ;
    END
  END a[383]
  PIN a[384]
    DIRECTION INPUT ;
    USE SIGNAL ;
    PORT
      LAYER M4 ;
        RECT  104.004 42.192 104.088 42.216 ;
    END
  END a[384]
  PIN a[385]
    DIRECTION INPUT ;
    USE SIGNAL ;
    PORT
      LAYER M4 ;
        RECT  104.004 42.288 104.088 42.312 ;
    END
  END a[385]
  PIN a[386]
    DIRECTION INPUT ;
    USE SIGNAL ;
    PORT
      LAYER M4 ;
        RECT  104.004 42.384 104.088 42.408 ;
    END
  END a[386]
  PIN a[387]
    DIRECTION INPUT ;
    USE SIGNAL ;
    PORT
      LAYER M4 ;
        RECT  104.004 42.48 104.088 42.504 ;
    END
  END a[387]
  PIN a[388]
    DIRECTION INPUT ;
    USE SIGNAL ;
    PORT
      LAYER M4 ;
        RECT  104.004 42.576 104.088 42.6 ;
    END
  END a[388]
  PIN a[389]
    DIRECTION INPUT ;
    USE SIGNAL ;
    PORT
      LAYER M4 ;
        RECT  104.004 42.672 104.088 42.696 ;
    END
  END a[389]
  PIN a[38]
    DIRECTION INPUT ;
    USE SIGNAL ;
    PORT
      LAYER M4 ;
        RECT  104.004 45.84 104.088 45.864 ;
    END
  END a[38]
  PIN a[390]
    DIRECTION INPUT ;
    USE SIGNAL ;
    PORT
      LAYER M4 ;
        RECT  104.004 42.768 104.088 42.792 ;
    END
  END a[390]
  PIN a[391]
    DIRECTION INPUT ;
    USE SIGNAL ;
    PORT
      LAYER M4 ;
        RECT  104.004 42.864 104.088 42.888 ;
    END
  END a[391]
  PIN a[392]
    DIRECTION INPUT ;
    USE SIGNAL ;
    PORT
      LAYER M4 ;
        RECT  104.004 42.96 104.088 42.984 ;
    END
  END a[392]
  PIN a[393]
    DIRECTION INPUT ;
    USE SIGNAL ;
    PORT
      LAYER M4 ;
        RECT  104.004 43.056 104.088 43.08 ;
    END
  END a[393]
  PIN a[394]
    DIRECTION INPUT ;
    USE SIGNAL ;
    PORT
      LAYER M4 ;
        RECT  104.004 43.152 104.088 43.176 ;
    END
  END a[394]
  PIN a[395]
    DIRECTION INPUT ;
    USE SIGNAL ;
    PORT
      LAYER M4 ;
        RECT  104.004 43.248 104.088 43.272 ;
    END
  END a[395]
  PIN a[396]
    DIRECTION INPUT ;
    USE SIGNAL ;
    PORT
      LAYER M4 ;
        RECT  104.004 43.344 104.088 43.368 ;
    END
  END a[396]
  PIN a[397]
    DIRECTION INPUT ;
    USE SIGNAL ;
    PORT
      LAYER M4 ;
        RECT  104.004 43.44 104.088 43.464 ;
    END
  END a[397]
  PIN a[398]
    DIRECTION INPUT ;
    USE SIGNAL ;
    PORT
      LAYER M4 ;
        RECT  104.004 43.536 104.088 43.56 ;
    END
  END a[398]
  PIN a[399]
    DIRECTION INPUT ;
    USE SIGNAL ;
    PORT
      LAYER M4 ;
        RECT  104.004 43.632 104.088 43.656 ;
    END
  END a[399]
  PIN a[39]
    DIRECTION INPUT ;
    USE SIGNAL ;
    PORT
      LAYER M4 ;
        RECT  104.004 45.936 104.088 45.96 ;
    END
  END a[39]
  PIN a[3]
    DIRECTION INPUT ;
    USE SIGNAL ;
    PORT
      LAYER M4 ;
        RECT  104.004 64.752 104.088 64.776 ;
    END
  END a[3]
  PIN a[400]
    DIRECTION INPUT ;
    USE SIGNAL ;
    PORT
      LAYER M4 ;
        RECT  104.004 43.728 104.088 43.752 ;
    END
  END a[400]
  PIN a[401]
    DIRECTION INPUT ;
    USE SIGNAL ;
    PORT
      LAYER M4 ;
        RECT  104.004 43.824 104.088 43.848 ;
    END
  END a[401]
  PIN a[402]
    DIRECTION INPUT ;
    USE SIGNAL ;
    PORT
      LAYER M4 ;
        RECT  104.004 43.92 104.088 43.944 ;
    END
  END a[402]
  PIN a[403]
    DIRECTION INPUT ;
    USE SIGNAL ;
    PORT
      LAYER M4 ;
        RECT  104.004 44.016 104.088 44.04 ;
    END
  END a[403]
  PIN a[404]
    DIRECTION INPUT ;
    USE SIGNAL ;
    PORT
      LAYER M4 ;
        RECT  104.004 44.112 104.088 44.136 ;
    END
  END a[404]
  PIN a[405]
    DIRECTION INPUT ;
    USE SIGNAL ;
    PORT
      LAYER M4 ;
        RECT  104.004 44.208 104.088 44.232 ;
    END
  END a[405]
  PIN a[406]
    DIRECTION INPUT ;
    USE SIGNAL ;
    PORT
      LAYER M4 ;
        RECT  104.004 44.304 104.088 44.328 ;
    END
  END a[406]
  PIN a[407]
    DIRECTION INPUT ;
    USE SIGNAL ;
    PORT
      LAYER M4 ;
        RECT  104.004 44.4 104.088 44.424 ;
    END
  END a[407]
  PIN a[408]
    DIRECTION INPUT ;
    USE SIGNAL ;
    PORT
      LAYER M4 ;
        RECT  104.004 44.496 104.088 44.52 ;
    END
  END a[408]
  PIN a[409]
    DIRECTION INPUT ;
    USE SIGNAL ;
    PORT
      LAYER M4 ;
        RECT  104.004 44.592 104.088 44.616 ;
    END
  END a[409]
  PIN a[40]
    DIRECTION INPUT ;
    USE SIGNAL ;
    PORT
      LAYER M4 ;
        RECT  104.004 46.032 104.088 46.056 ;
    END
  END a[40]
  PIN a[410]
    DIRECTION INPUT ;
    USE SIGNAL ;
    PORT
      LAYER M4 ;
        RECT  104.004 44.688 104.088 44.712 ;
    END
  END a[410]
  PIN a[411]
    DIRECTION INPUT ;
    USE SIGNAL ;
    PORT
      LAYER M4 ;
        RECT  104.004 44.784 104.088 44.808 ;
    END
  END a[411]
  PIN a[412]
    DIRECTION INPUT ;
    USE SIGNAL ;
    PORT
      LAYER M4 ;
        RECT  104.004 44.88 104.088 44.904 ;
    END
  END a[412]
  PIN a[413]
    DIRECTION INPUT ;
    USE SIGNAL ;
    PORT
      LAYER M4 ;
        RECT  104.004 44.976 104.088 45 ;
    END
  END a[413]
  PIN a[414]
    DIRECTION INPUT ;
    USE SIGNAL ;
    PORT
      LAYER M4 ;
        RECT  104.004 45.072 104.088 45.096 ;
    END
  END a[414]
  PIN a[415]
    DIRECTION INPUT ;
    USE SIGNAL ;
    PORT
      LAYER M4 ;
        RECT  104.004 45.168 104.088 45.192 ;
    END
  END a[415]
  PIN a[416]
    DIRECTION INPUT ;
    USE SIGNAL ;
    PORT
      LAYER M4 ;
        RECT  104.004 26.064 104.088 26.088 ;
    END
  END a[416]
  PIN a[417]
    DIRECTION INPUT ;
    USE SIGNAL ;
    PORT
      LAYER M4 ;
        RECT  104.004 26.16 104.088 26.184 ;
    END
  END a[417]
  PIN a[418]
    DIRECTION INPUT ;
    USE SIGNAL ;
    PORT
      LAYER M4 ;
        RECT  104.004 26.256 104.088 26.28 ;
    END
  END a[418]
  PIN a[419]
    DIRECTION INPUT ;
    USE SIGNAL ;
    PORT
      LAYER M4 ;
        RECT  104.004 26.352 104.088 26.376 ;
    END
  END a[419]
  PIN a[41]
    DIRECTION INPUT ;
    USE SIGNAL ;
    PORT
      LAYER M4 ;
        RECT  104.004 46.128 104.088 46.152 ;
    END
  END a[41]
  PIN a[420]
    DIRECTION INPUT ;
    USE SIGNAL ;
    PORT
      LAYER M4 ;
        RECT  104.004 26.448 104.088 26.472 ;
    END
  END a[420]
  PIN a[421]
    DIRECTION INPUT ;
    USE SIGNAL ;
    PORT
      LAYER M4 ;
        RECT  104.004 26.544 104.088 26.568 ;
    END
  END a[421]
  PIN a[422]
    DIRECTION INPUT ;
    USE SIGNAL ;
    PORT
      LAYER M4 ;
        RECT  104.004 26.64 104.088 26.664 ;
    END
  END a[422]
  PIN a[423]
    DIRECTION INPUT ;
    USE SIGNAL ;
    PORT
      LAYER M4 ;
        RECT  104.004 26.736 104.088 26.76 ;
    END
  END a[423]
  PIN a[424]
    DIRECTION INPUT ;
    USE SIGNAL ;
    PORT
      LAYER M4 ;
        RECT  104.004 26.832 104.088 26.856 ;
    END
  END a[424]
  PIN a[425]
    DIRECTION INPUT ;
    USE SIGNAL ;
    PORT
      LAYER M4 ;
        RECT  104.004 26.928 104.088 26.952 ;
    END
  END a[425]
  PIN a[426]
    DIRECTION INPUT ;
    USE SIGNAL ;
    PORT
      LAYER M4 ;
        RECT  104.004 27.024 104.088 27.048 ;
    END
  END a[426]
  PIN a[427]
    DIRECTION INPUT ;
    USE SIGNAL ;
    PORT
      LAYER M4 ;
        RECT  104.004 27.12 104.088 27.144 ;
    END
  END a[427]
  PIN a[428]
    DIRECTION INPUT ;
    USE SIGNAL ;
    PORT
      LAYER M4 ;
        RECT  104.004 27.216 104.088 27.24 ;
    END
  END a[428]
  PIN a[429]
    DIRECTION INPUT ;
    USE SIGNAL ;
    PORT
      LAYER M4 ;
        RECT  104.004 27.312 104.088 27.336 ;
    END
  END a[429]
  PIN a[42]
    DIRECTION INPUT ;
    USE SIGNAL ;
    PORT
      LAYER M4 ;
        RECT  104.004 46.224 104.088 46.248 ;
    END
  END a[42]
  PIN a[430]
    DIRECTION INPUT ;
    USE SIGNAL ;
    PORT
      LAYER M4 ;
        RECT  104.004 27.408 104.088 27.432 ;
    END
  END a[430]
  PIN a[431]
    DIRECTION INPUT ;
    USE SIGNAL ;
    PORT
      LAYER M4 ;
        RECT  104.004 27.504 104.088 27.528 ;
    END
  END a[431]
  PIN a[432]
    DIRECTION INPUT ;
    USE SIGNAL ;
    PORT
      LAYER M4 ;
        RECT  104.004 27.6 104.088 27.624 ;
    END
  END a[432]
  PIN a[433]
    DIRECTION INPUT ;
    USE SIGNAL ;
    PORT
      LAYER M4 ;
        RECT  104.004 27.696 104.088 27.72 ;
    END
  END a[433]
  PIN a[434]
    DIRECTION INPUT ;
    USE SIGNAL ;
    PORT
      LAYER M4 ;
        RECT  104.004 27.792 104.088 27.816 ;
    END
  END a[434]
  PIN a[435]
    DIRECTION INPUT ;
    USE SIGNAL ;
    PORT
      LAYER M4 ;
        RECT  104.004 27.888 104.088 27.912 ;
    END
  END a[435]
  PIN a[436]
    DIRECTION INPUT ;
    USE SIGNAL ;
    PORT
      LAYER M4 ;
        RECT  104.004 27.984 104.088 28.008 ;
    END
  END a[436]
  PIN a[437]
    DIRECTION INPUT ;
    USE SIGNAL ;
    PORT
      LAYER M4 ;
        RECT  104.004 28.08 104.088 28.104 ;
    END
  END a[437]
  PIN a[438]
    DIRECTION INPUT ;
    USE SIGNAL ;
    PORT
      LAYER M4 ;
        RECT  104.004 28.176 104.088 28.2 ;
    END
  END a[438]
  PIN a[439]
    DIRECTION INPUT ;
    USE SIGNAL ;
    PORT
      LAYER M4 ;
        RECT  104.004 28.272 104.088 28.296 ;
    END
  END a[439]
  PIN a[43]
    DIRECTION INPUT ;
    USE SIGNAL ;
    PORT
      LAYER M4 ;
        RECT  104.004 46.32 104.088 46.344 ;
    END
  END a[43]
  PIN a[440]
    DIRECTION INPUT ;
    USE SIGNAL ;
    PORT
      LAYER M4 ;
        RECT  104.004 28.368 104.088 28.392 ;
    END
  END a[440]
  PIN a[441]
    DIRECTION INPUT ;
    USE SIGNAL ;
    PORT
      LAYER M4 ;
        RECT  104.004 28.464 104.088 28.488 ;
    END
  END a[441]
  PIN a[442]
    DIRECTION INPUT ;
    USE SIGNAL ;
    PORT
      LAYER M4 ;
        RECT  104.004 28.56 104.088 28.584 ;
    END
  END a[442]
  PIN a[443]
    DIRECTION INPUT ;
    USE SIGNAL ;
    PORT
      LAYER M4 ;
        RECT  104.004 28.656 104.088 28.68 ;
    END
  END a[443]
  PIN a[444]
    DIRECTION INPUT ;
    USE SIGNAL ;
    PORT
      LAYER M4 ;
        RECT  104.004 28.752 104.088 28.776 ;
    END
  END a[444]
  PIN a[445]
    DIRECTION INPUT ;
    USE SIGNAL ;
    PORT
      LAYER M4 ;
        RECT  104.004 28.848 104.088 28.872 ;
    END
  END a[445]
  PIN a[446]
    DIRECTION INPUT ;
    USE SIGNAL ;
    PORT
      LAYER M4 ;
        RECT  104.004 28.944 104.088 28.968 ;
    END
  END a[446]
  PIN a[447]
    DIRECTION INPUT ;
    USE SIGNAL ;
    PORT
      LAYER M4 ;
        RECT  104.004 29.04 104.088 29.064 ;
    END
  END a[447]
  PIN a[448]
    DIRECTION INPUT ;
    USE SIGNAL ;
    PORT
      LAYER M4 ;
        RECT  104.004 22.992 104.088 23.016 ;
    END
  END a[448]
  PIN a[449]
    DIRECTION INPUT ;
    USE SIGNAL ;
    PORT
      LAYER M4 ;
        RECT  104.004 23.088 104.088 23.112 ;
    END
  END a[449]
  PIN a[44]
    DIRECTION INPUT ;
    USE SIGNAL ;
    PORT
      LAYER M4 ;
        RECT  104.004 46.416 104.088 46.44 ;
    END
  END a[44]
  PIN a[450]
    DIRECTION INPUT ;
    USE SIGNAL ;
    PORT
      LAYER M4 ;
        RECT  104.004 23.184 104.088 23.208 ;
    END
  END a[450]
  PIN a[451]
    DIRECTION INPUT ;
    USE SIGNAL ;
    PORT
      LAYER M4 ;
        RECT  104.004 23.28 104.088 23.304 ;
    END
  END a[451]
  PIN a[452]
    DIRECTION INPUT ;
    USE SIGNAL ;
    PORT
      LAYER M4 ;
        RECT  104.004 23.376 104.088 23.4 ;
    END
  END a[452]
  PIN a[453]
    DIRECTION INPUT ;
    USE SIGNAL ;
    PORT
      LAYER M4 ;
        RECT  104.004 23.472 104.088 23.496 ;
    END
  END a[453]
  PIN a[454]
    DIRECTION INPUT ;
    USE SIGNAL ;
    PORT
      LAYER M4 ;
        RECT  104.004 23.568 104.088 23.592 ;
    END
  END a[454]
  PIN a[455]
    DIRECTION INPUT ;
    USE SIGNAL ;
    PORT
      LAYER M4 ;
        RECT  104.004 23.664 104.088 23.688 ;
    END
  END a[455]
  PIN a[456]
    DIRECTION INPUT ;
    USE SIGNAL ;
    PORT
      LAYER M4 ;
        RECT  104.004 23.76 104.088 23.784 ;
    END
  END a[456]
  PIN a[457]
    DIRECTION INPUT ;
    USE SIGNAL ;
    PORT
      LAYER M4 ;
        RECT  104.004 23.856 104.088 23.88 ;
    END
  END a[457]
  PIN a[458]
    DIRECTION INPUT ;
    USE SIGNAL ;
    PORT
      LAYER M4 ;
        RECT  104.004 23.952 104.088 23.976 ;
    END
  END a[458]
  PIN a[459]
    DIRECTION INPUT ;
    USE SIGNAL ;
    PORT
      LAYER M4 ;
        RECT  104.004 24.048 104.088 24.072 ;
    END
  END a[459]
  PIN a[45]
    DIRECTION INPUT ;
    USE SIGNAL ;
    PORT
      LAYER M4 ;
        RECT  104.004 46.512 104.088 46.536 ;
    END
  END a[45]
  PIN a[460]
    DIRECTION INPUT ;
    USE SIGNAL ;
    PORT
      LAYER M4 ;
        RECT  104.004 24.144 104.088 24.168 ;
    END
  END a[460]
  PIN a[461]
    DIRECTION INPUT ;
    USE SIGNAL ;
    PORT
      LAYER M4 ;
        RECT  104.004 24.24 104.088 24.264 ;
    END
  END a[461]
  PIN a[462]
    DIRECTION INPUT ;
    USE SIGNAL ;
    PORT
      LAYER M4 ;
        RECT  104.004 24.336 104.088 24.36 ;
    END
  END a[462]
  PIN a[463]
    DIRECTION INPUT ;
    USE SIGNAL ;
    PORT
      LAYER M4 ;
        RECT  104.004 24.432 104.088 24.456 ;
    END
  END a[463]
  PIN a[464]
    DIRECTION INPUT ;
    USE SIGNAL ;
    PORT
      LAYER M4 ;
        RECT  104.004 24.528 104.088 24.552 ;
    END
  END a[464]
  PIN a[465]
    DIRECTION INPUT ;
    USE SIGNAL ;
    PORT
      LAYER M4 ;
        RECT  104.004 24.624 104.088 24.648 ;
    END
  END a[465]
  PIN a[466]
    DIRECTION INPUT ;
    USE SIGNAL ;
    PORT
      LAYER M4 ;
        RECT  104.004 24.72 104.088 24.744 ;
    END
  END a[466]
  PIN a[467]
    DIRECTION INPUT ;
    USE SIGNAL ;
    PORT
      LAYER M4 ;
        RECT  104.004 24.816 104.088 24.84 ;
    END
  END a[467]
  PIN a[468]
    DIRECTION INPUT ;
    USE SIGNAL ;
    PORT
      LAYER M4 ;
        RECT  104.004 24.912 104.088 24.936 ;
    END
  END a[468]
  PIN a[469]
    DIRECTION INPUT ;
    USE SIGNAL ;
    PORT
      LAYER M4 ;
        RECT  104.004 25.008 104.088 25.032 ;
    END
  END a[469]
  PIN a[46]
    DIRECTION INPUT ;
    USE SIGNAL ;
    PORT
      LAYER M4 ;
        RECT  104.004 46.608 104.088 46.632 ;
    END
  END a[46]
  PIN a[470]
    DIRECTION INPUT ;
    USE SIGNAL ;
    PORT
      LAYER M4 ;
        RECT  104.004 25.104 104.088 25.128 ;
    END
  END a[470]
  PIN a[471]
    DIRECTION INPUT ;
    USE SIGNAL ;
    PORT
      LAYER M4 ;
        RECT  104.004 25.2 104.088 25.224 ;
    END
  END a[471]
  PIN a[472]
    DIRECTION INPUT ;
    USE SIGNAL ;
    PORT
      LAYER M4 ;
        RECT  104.004 25.296 104.088 25.32 ;
    END
  END a[472]
  PIN a[473]
    DIRECTION INPUT ;
    USE SIGNAL ;
    PORT
      LAYER M4 ;
        RECT  104.004 25.392 104.088 25.416 ;
    END
  END a[473]
  PIN a[474]
    DIRECTION INPUT ;
    USE SIGNAL ;
    PORT
      LAYER M4 ;
        RECT  104.004 25.488 104.088 25.512 ;
    END
  END a[474]
  PIN a[475]
    DIRECTION INPUT ;
    USE SIGNAL ;
    PORT
      LAYER M4 ;
        RECT  104.004 25.584 104.088 25.608 ;
    END
  END a[475]
  PIN a[476]
    DIRECTION INPUT ;
    USE SIGNAL ;
    PORT
      LAYER M4 ;
        RECT  104.004 25.68 104.088 25.704 ;
    END
  END a[476]
  PIN a[477]
    DIRECTION INPUT ;
    USE SIGNAL ;
    PORT
      LAYER M4 ;
        RECT  104.004 25.776 104.088 25.8 ;
    END
  END a[477]
  PIN a[478]
    DIRECTION INPUT ;
    USE SIGNAL ;
    PORT
      LAYER M4 ;
        RECT  104.004 25.872 104.088 25.896 ;
    END
  END a[478]
  PIN a[479]
    DIRECTION INPUT ;
    USE SIGNAL ;
    PORT
      LAYER M4 ;
        RECT  104.004 25.968 104.088 25.992 ;
    END
  END a[479]
  PIN a[47]
    DIRECTION INPUT ;
    USE SIGNAL ;
    PORT
      LAYER M4 ;
        RECT  104.004 46.704 104.088 46.728 ;
    END
  END a[47]
  PIN a[480]
    DIRECTION INPUT ;
    USE SIGNAL ;
    PORT
      LAYER M4 ;
        RECT  104.004 32.208 104.088 32.232 ;
    END
  END a[480]
  PIN a[481]
    DIRECTION INPUT ;
    USE SIGNAL ;
    PORT
      LAYER M4 ;
        RECT  104.004 32.304 104.088 32.328 ;
    END
  END a[481]
  PIN a[482]
    DIRECTION INPUT ;
    USE SIGNAL ;
    PORT
      LAYER M4 ;
        RECT  104.004 32.4 104.088 32.424 ;
    END
  END a[482]
  PIN a[483]
    DIRECTION INPUT ;
    USE SIGNAL ;
    PORT
      LAYER M4 ;
        RECT  104.004 32.496 104.088 32.52 ;
    END
  END a[483]
  PIN a[484]
    DIRECTION INPUT ;
    USE SIGNAL ;
    PORT
      LAYER M4 ;
        RECT  104.004 32.592 104.088 32.616 ;
    END
  END a[484]
  PIN a[485]
    DIRECTION INPUT ;
    USE SIGNAL ;
    PORT
      LAYER M4 ;
        RECT  104.004 32.688 104.088 32.712 ;
    END
  END a[485]
  PIN a[486]
    DIRECTION INPUT ;
    USE SIGNAL ;
    PORT
      LAYER M4 ;
        RECT  104.004 32.784 104.088 32.808 ;
    END
  END a[486]
  PIN a[487]
    DIRECTION INPUT ;
    USE SIGNAL ;
    PORT
      LAYER M4 ;
        RECT  104.004 32.88 104.088 32.904 ;
    END
  END a[487]
  PIN a[488]
    DIRECTION INPUT ;
    USE SIGNAL ;
    PORT
      LAYER M4 ;
        RECT  104.004 32.976 104.088 33 ;
    END
  END a[488]
  PIN a[489]
    DIRECTION INPUT ;
    USE SIGNAL ;
    PORT
      LAYER M4 ;
        RECT  104.004 33.072 104.088 33.096 ;
    END
  END a[489]
  PIN a[48]
    DIRECTION INPUT ;
    USE SIGNAL ;
    PORT
      LAYER M4 ;
        RECT  104.004 46.8 104.088 46.824 ;
    END
  END a[48]
  PIN a[490]
    DIRECTION INPUT ;
    USE SIGNAL ;
    PORT
      LAYER M4 ;
        RECT  104.004 33.168 104.088 33.192 ;
    END
  END a[490]
  PIN a[491]
    DIRECTION INPUT ;
    USE SIGNAL ;
    PORT
      LAYER M4 ;
        RECT  104.004 33.264 104.088 33.288 ;
    END
  END a[491]
  PIN a[492]
    DIRECTION INPUT ;
    USE SIGNAL ;
    PORT
      LAYER M4 ;
        RECT  104.004 33.36 104.088 33.384 ;
    END
  END a[492]
  PIN a[493]
    DIRECTION INPUT ;
    USE SIGNAL ;
    PORT
      LAYER M4 ;
        RECT  104.004 33.456 104.088 33.48 ;
    END
  END a[493]
  PIN a[494]
    DIRECTION INPUT ;
    USE SIGNAL ;
    PORT
      LAYER M4 ;
        RECT  104.004 33.552 104.088 33.576 ;
    END
  END a[494]
  PIN a[495]
    DIRECTION INPUT ;
    USE SIGNAL ;
    PORT
      LAYER M4 ;
        RECT  104.004 33.648 104.088 33.672 ;
    END
  END a[495]
  PIN a[496]
    DIRECTION INPUT ;
    USE SIGNAL ;
    PORT
      LAYER M4 ;
        RECT  104.004 33.744 104.088 33.768 ;
    END
  END a[496]
  PIN a[497]
    DIRECTION INPUT ;
    USE SIGNAL ;
    PORT
      LAYER M4 ;
        RECT  104.004 33.84 104.088 33.864 ;
    END
  END a[497]
  PIN a[498]
    DIRECTION INPUT ;
    USE SIGNAL ;
    PORT
      LAYER M4 ;
        RECT  104.004 33.936 104.088 33.96 ;
    END
  END a[498]
  PIN a[499]
    DIRECTION INPUT ;
    USE SIGNAL ;
    PORT
      LAYER M4 ;
        RECT  104.004 34.032 104.088 34.056 ;
    END
  END a[499]
  PIN a[49]
    DIRECTION INPUT ;
    USE SIGNAL ;
    PORT
      LAYER M4 ;
        RECT  104.004 46.896 104.088 46.92 ;
    END
  END a[49]
  PIN a[4]
    DIRECTION INPUT ;
    USE SIGNAL ;
    PORT
      LAYER M4 ;
        RECT  104.004 64.848 104.088 64.872 ;
    END
  END a[4]
  PIN a[500]
    DIRECTION INPUT ;
    USE SIGNAL ;
    PORT
      LAYER M4 ;
        RECT  104.004 34.128 104.088 34.152 ;
    END
  END a[500]
  PIN a[501]
    DIRECTION INPUT ;
    USE SIGNAL ;
    PORT
      LAYER M4 ;
        RECT  104.004 34.224 104.088 34.248 ;
    END
  END a[501]
  PIN a[502]
    DIRECTION INPUT ;
    USE SIGNAL ;
    PORT
      LAYER M4 ;
        RECT  104.004 34.32 104.088 34.344 ;
    END
  END a[502]
  PIN a[503]
    DIRECTION INPUT ;
    USE SIGNAL ;
    PORT
      LAYER M4 ;
        RECT  104.004 34.416 104.088 34.44 ;
    END
  END a[503]
  PIN a[504]
    DIRECTION INPUT ;
    USE SIGNAL ;
    PORT
      LAYER M4 ;
        RECT  104.004 34.512 104.088 34.536 ;
    END
  END a[504]
  PIN a[505]
    DIRECTION INPUT ;
    USE SIGNAL ;
    PORT
      LAYER M4 ;
        RECT  104.004 34.608 104.088 34.632 ;
    END
  END a[505]
  PIN a[506]
    DIRECTION INPUT ;
    USE SIGNAL ;
    PORT
      LAYER M4 ;
        RECT  104.004 34.704 104.088 34.728 ;
    END
  END a[506]
  PIN a[507]
    DIRECTION INPUT ;
    USE SIGNAL ;
    PORT
      LAYER M4 ;
        RECT  104.004 34.8 104.088 34.824 ;
    END
  END a[507]
  PIN a[508]
    DIRECTION INPUT ;
    USE SIGNAL ;
    PORT
      LAYER M4 ;
        RECT  104.004 34.896 104.088 34.92 ;
    END
  END a[508]
  PIN a[509]
    DIRECTION INPUT ;
    USE SIGNAL ;
    PORT
      LAYER M4 ;
        RECT  104.004 34.992 104.088 35.016 ;
    END
  END a[509]
  PIN a[50]
    DIRECTION INPUT ;
    USE SIGNAL ;
    PORT
      LAYER M4 ;
        RECT  104.004 46.992 104.088 47.016 ;
    END
  END a[50]
  PIN a[510]
    DIRECTION INPUT ;
    USE SIGNAL ;
    PORT
      LAYER M4 ;
        RECT  104.004 35.088 104.088 35.112 ;
    END
  END a[510]
  PIN a[511]
    DIRECTION INPUT ;
    USE SIGNAL ;
    PORT
      LAYER M4 ;
        RECT  104.004 35.184 104.088 35.208 ;
    END
  END a[511]
  PIN a[512]
    DIRECTION INPUT ;
    USE SIGNAL ;
    PORT
      LAYER M4 ;
        RECT  104.004 51.408 104.088 51.432 ;
    END
  END a[512]
  PIN a[513]
    DIRECTION INPUT ;
    USE SIGNAL ;
    PORT
      LAYER M4 ;
        RECT  104.004 51.504 104.088 51.528 ;
    END
  END a[513]
  PIN a[514]
    DIRECTION INPUT ;
    USE SIGNAL ;
    PORT
      LAYER M4 ;
        RECT  104.004 51.6 104.088 51.624 ;
    END
  END a[514]
  PIN a[515]
    DIRECTION INPUT ;
    USE SIGNAL ;
    PORT
      LAYER M4 ;
        RECT  104.004 51.696 104.088 51.72 ;
    END
  END a[515]
  PIN a[516]
    DIRECTION INPUT ;
    USE SIGNAL ;
    PORT
      LAYER M4 ;
        RECT  104.004 51.792 104.088 51.816 ;
    END
  END a[516]
  PIN a[517]
    DIRECTION INPUT ;
    USE SIGNAL ;
    PORT
      LAYER M4 ;
        RECT  104.004 51.888 104.088 51.912 ;
    END
  END a[517]
  PIN a[518]
    DIRECTION INPUT ;
    USE SIGNAL ;
    PORT
      LAYER M4 ;
        RECT  104.004 51.984 104.088 52.008 ;
    END
  END a[518]
  PIN a[519]
    DIRECTION INPUT ;
    USE SIGNAL ;
    PORT
      LAYER M4 ;
        RECT  104.004 52.08 104.088 52.104 ;
    END
  END a[519]
  PIN a[51]
    DIRECTION INPUT ;
    USE SIGNAL ;
    PORT
      LAYER M4 ;
        RECT  104.004 47.088 104.088 47.112 ;
    END
  END a[51]
  PIN a[520]
    DIRECTION INPUT ;
    USE SIGNAL ;
    PORT
      LAYER M4 ;
        RECT  104.004 52.176 104.088 52.2 ;
    END
  END a[520]
  PIN a[521]
    DIRECTION INPUT ;
    USE SIGNAL ;
    PORT
      LAYER M4 ;
        RECT  104.004 52.272 104.088 52.296 ;
    END
  END a[521]
  PIN a[522]
    DIRECTION INPUT ;
    USE SIGNAL ;
    PORT
      LAYER M4 ;
        RECT  104.004 52.368 104.088 52.392 ;
    END
  END a[522]
  PIN a[523]
    DIRECTION INPUT ;
    USE SIGNAL ;
    PORT
      LAYER M4 ;
        RECT  104.004 52.464 104.088 52.488 ;
    END
  END a[523]
  PIN a[524]
    DIRECTION INPUT ;
    USE SIGNAL ;
    PORT
      LAYER M4 ;
        RECT  104.004 52.56 104.088 52.584 ;
    END
  END a[524]
  PIN a[525]
    DIRECTION INPUT ;
    USE SIGNAL ;
    PORT
      LAYER M4 ;
        RECT  104.004 52.656 104.088 52.68 ;
    END
  END a[525]
  PIN a[526]
    DIRECTION INPUT ;
    USE SIGNAL ;
    PORT
      LAYER M4 ;
        RECT  104.004 52.752 104.088 52.776 ;
    END
  END a[526]
  PIN a[527]
    DIRECTION INPUT ;
    USE SIGNAL ;
    PORT
      LAYER M4 ;
        RECT  104.004 52.848 104.088 52.872 ;
    END
  END a[527]
  PIN a[528]
    DIRECTION INPUT ;
    USE SIGNAL ;
    PORT
      LAYER M4 ;
        RECT  104.004 52.944 104.088 52.968 ;
    END
  END a[528]
  PIN a[529]
    DIRECTION INPUT ;
    USE SIGNAL ;
    PORT
      LAYER M4 ;
        RECT  104.004 53.04 104.088 53.064 ;
    END
  END a[529]
  PIN a[52]
    DIRECTION INPUT ;
    USE SIGNAL ;
    PORT
      LAYER M4 ;
        RECT  104.004 47.184 104.088 47.208 ;
    END
  END a[52]
  PIN a[530]
    DIRECTION INPUT ;
    USE SIGNAL ;
    PORT
      LAYER M4 ;
        RECT  104.004 53.136 104.088 53.16 ;
    END
  END a[530]
  PIN a[531]
    DIRECTION INPUT ;
    USE SIGNAL ;
    PORT
      LAYER M4 ;
        RECT  104.004 53.232 104.088 53.256 ;
    END
  END a[531]
  PIN a[532]
    DIRECTION INPUT ;
    USE SIGNAL ;
    PORT
      LAYER M4 ;
        RECT  104.004 53.328 104.088 53.352 ;
    END
  END a[532]
  PIN a[533]
    DIRECTION INPUT ;
    USE SIGNAL ;
    PORT
      LAYER M4 ;
        RECT  104.004 53.424 104.088 53.448 ;
    END
  END a[533]
  PIN a[534]
    DIRECTION INPUT ;
    USE SIGNAL ;
    PORT
      LAYER M4 ;
        RECT  104.004 53.52 104.088 53.544 ;
    END
  END a[534]
  PIN a[535]
    DIRECTION INPUT ;
    USE SIGNAL ;
    PORT
      LAYER M4 ;
        RECT  104.004 53.616 104.088 53.64 ;
    END
  END a[535]
  PIN a[536]
    DIRECTION INPUT ;
    USE SIGNAL ;
    PORT
      LAYER M4 ;
        RECT  104.004 53.712 104.088 53.736 ;
    END
  END a[536]
  PIN a[537]
    DIRECTION INPUT ;
    USE SIGNAL ;
    PORT
      LAYER M4 ;
        RECT  104.004 53.808 104.088 53.832 ;
    END
  END a[537]
  PIN a[538]
    DIRECTION INPUT ;
    USE SIGNAL ;
    PORT
      LAYER M4 ;
        RECT  104.004 53.904 104.088 53.928 ;
    END
  END a[538]
  PIN a[539]
    DIRECTION INPUT ;
    USE SIGNAL ;
    PORT
      LAYER M4 ;
        RECT  104.004 54 104.088 54.024 ;
    END
  END a[539]
  PIN a[53]
    DIRECTION INPUT ;
    USE SIGNAL ;
    PORT
      LAYER M4 ;
        RECT  104.004 47.28 104.088 47.304 ;
    END
  END a[53]
  PIN a[540]
    DIRECTION INPUT ;
    USE SIGNAL ;
    PORT
      LAYER M4 ;
        RECT  104.004 54.096 104.088 54.12 ;
    END
  END a[540]
  PIN a[541]
    DIRECTION INPUT ;
    USE SIGNAL ;
    PORT
      LAYER M4 ;
        RECT  104.004 54.192 104.088 54.216 ;
    END
  END a[541]
  PIN a[542]
    DIRECTION INPUT ;
    USE SIGNAL ;
    PORT
      LAYER M4 ;
        RECT  104.004 54.288 104.088 54.312 ;
    END
  END a[542]
  PIN a[543]
    DIRECTION INPUT ;
    USE SIGNAL ;
    PORT
      LAYER M4 ;
        RECT  104.004 54.384 104.088 54.408 ;
    END
  END a[543]
  PIN a[544]
    DIRECTION INPUT ;
    USE SIGNAL ;
    PORT
      LAYER M4 ;
        RECT  104.004 58.32 104.088 58.344 ;
    END
  END a[544]
  PIN a[545]
    DIRECTION INPUT ;
    USE SIGNAL ;
    PORT
      LAYER M4 ;
        RECT  104.004 58.416 104.088 58.44 ;
    END
  END a[545]
  PIN a[546]
    DIRECTION INPUT ;
    USE SIGNAL ;
    PORT
      LAYER M4 ;
        RECT  104.004 58.512 104.088 58.536 ;
    END
  END a[546]
  PIN a[547]
    DIRECTION INPUT ;
    USE SIGNAL ;
    PORT
      LAYER M4 ;
        RECT  104.004 58.608 104.088 58.632 ;
    END
  END a[547]
  PIN a[548]
    DIRECTION INPUT ;
    USE SIGNAL ;
    PORT
      LAYER M4 ;
        RECT  104.004 58.704 104.088 58.728 ;
    END
  END a[548]
  PIN a[549]
    DIRECTION INPUT ;
    USE SIGNAL ;
    PORT
      LAYER M4 ;
        RECT  104.004 58.8 104.088 58.824 ;
    END
  END a[549]
  PIN a[54]
    DIRECTION INPUT ;
    USE SIGNAL ;
    PORT
      LAYER M4 ;
        RECT  104.004 47.376 104.088 47.4 ;
    END
  END a[54]
  PIN a[550]
    DIRECTION INPUT ;
    USE SIGNAL ;
    PORT
      LAYER M4 ;
        RECT  104.004 58.896 104.088 58.92 ;
    END
  END a[550]
  PIN a[551]
    DIRECTION INPUT ;
    USE SIGNAL ;
    PORT
      LAYER M4 ;
        RECT  104.004 58.992 104.088 59.016 ;
    END
  END a[551]
  PIN a[552]
    DIRECTION INPUT ;
    USE SIGNAL ;
    PORT
      LAYER M4 ;
        RECT  104.004 59.088 104.088 59.112 ;
    END
  END a[552]
  PIN a[553]
    DIRECTION INPUT ;
    USE SIGNAL ;
    PORT
      LAYER M4 ;
        RECT  104.004 59.184 104.088 59.208 ;
    END
  END a[553]
  PIN a[554]
    DIRECTION INPUT ;
    USE SIGNAL ;
    PORT
      LAYER M4 ;
        RECT  104.004 59.28 104.088 59.304 ;
    END
  END a[554]
  PIN a[555]
    DIRECTION INPUT ;
    USE SIGNAL ;
    PORT
      LAYER M4 ;
        RECT  104.004 59.376 104.088 59.4 ;
    END
  END a[555]
  PIN a[556]
    DIRECTION INPUT ;
    USE SIGNAL ;
    PORT
      LAYER M4 ;
        RECT  104.004 59.472 104.088 59.496 ;
    END
  END a[556]
  PIN a[557]
    DIRECTION INPUT ;
    USE SIGNAL ;
    PORT
      LAYER M4 ;
        RECT  104.004 59.568 104.088 59.592 ;
    END
  END a[557]
  PIN a[558]
    DIRECTION INPUT ;
    USE SIGNAL ;
    PORT
      LAYER M4 ;
        RECT  104.004 59.664 104.088 59.688 ;
    END
  END a[558]
  PIN a[559]
    DIRECTION INPUT ;
    USE SIGNAL ;
    PORT
      LAYER M4 ;
        RECT  104.004 59.76 104.088 59.784 ;
    END
  END a[559]
  PIN a[55]
    DIRECTION INPUT ;
    USE SIGNAL ;
    PORT
      LAYER M4 ;
        RECT  104.004 47.472 104.088 47.496 ;
    END
  END a[55]
  PIN a[560]
    DIRECTION INPUT ;
    USE SIGNAL ;
    PORT
      LAYER M4 ;
        RECT  104.004 59.856 104.088 59.88 ;
    END
  END a[560]
  PIN a[561]
    DIRECTION INPUT ;
    USE SIGNAL ;
    PORT
      LAYER M4 ;
        RECT  104.004 59.952 104.088 59.976 ;
    END
  END a[561]
  PIN a[562]
    DIRECTION INPUT ;
    USE SIGNAL ;
    PORT
      LAYER M4 ;
        RECT  104.004 60.048 104.088 60.072 ;
    END
  END a[562]
  PIN a[563]
    DIRECTION INPUT ;
    USE SIGNAL ;
    PORT
      LAYER M4 ;
        RECT  104.004 60.144 104.088 60.168 ;
    END
  END a[563]
  PIN a[564]
    DIRECTION INPUT ;
    USE SIGNAL ;
    PORT
      LAYER M4 ;
        RECT  104.004 60.24 104.088 60.264 ;
    END
  END a[564]
  PIN a[565]
    DIRECTION INPUT ;
    USE SIGNAL ;
    PORT
      LAYER M4 ;
        RECT  104.004 60.336 104.088 60.36 ;
    END
  END a[565]
  PIN a[566]
    DIRECTION INPUT ;
    USE SIGNAL ;
    PORT
      LAYER M4 ;
        RECT  104.004 60.432 104.088 60.456 ;
    END
  END a[566]
  PIN a[567]
    DIRECTION INPUT ;
    USE SIGNAL ;
    PORT
      LAYER M4 ;
        RECT  104.004 60.528 104.088 60.552 ;
    END
  END a[567]
  PIN a[568]
    DIRECTION INPUT ;
    USE SIGNAL ;
    PORT
      LAYER M4 ;
        RECT  104.004 60.624 104.088 60.648 ;
    END
  END a[568]
  PIN a[569]
    DIRECTION INPUT ;
    USE SIGNAL ;
    PORT
      LAYER M4 ;
        RECT  104.004 60.72 104.088 60.744 ;
    END
  END a[569]
  PIN a[56]
    DIRECTION INPUT ;
    USE SIGNAL ;
    PORT
      LAYER M4 ;
        RECT  104.004 47.568 104.088 47.592 ;
    END
  END a[56]
  PIN a[570]
    DIRECTION INPUT ;
    USE SIGNAL ;
    PORT
      LAYER M4 ;
        RECT  104.004 60.816 104.088 60.84 ;
    END
  END a[570]
  PIN a[571]
    DIRECTION INPUT ;
    USE SIGNAL ;
    PORT
      LAYER M4 ;
        RECT  104.004 60.912 104.088 60.936 ;
    END
  END a[571]
  PIN a[572]
    DIRECTION INPUT ;
    USE SIGNAL ;
    PORT
      LAYER M4 ;
        RECT  104.004 61.008 104.088 61.032 ;
    END
  END a[572]
  PIN a[573]
    DIRECTION INPUT ;
    USE SIGNAL ;
    PORT
      LAYER M4 ;
        RECT  104.004 61.104 104.088 61.128 ;
    END
  END a[573]
  PIN a[574]
    DIRECTION INPUT ;
    USE SIGNAL ;
    PORT
      LAYER M4 ;
        RECT  104.004 61.2 104.088 61.224 ;
    END
  END a[574]
  PIN a[575]
    DIRECTION INPUT ;
    USE SIGNAL ;
    PORT
      LAYER M4 ;
        RECT  104.004 61.296 104.088 61.32 ;
    END
  END a[575]
  PIN a[576]
    DIRECTION INPUT ;
    USE SIGNAL ;
    PORT
      LAYER M4 ;
        RECT  104.004 35.28 104.088 35.304 ;
    END
  END a[576]
  PIN a[577]
    DIRECTION INPUT ;
    USE SIGNAL ;
    PORT
      LAYER M4 ;
        RECT  104.004 35.376 104.088 35.4 ;
    END
  END a[577]
  PIN a[578]
    DIRECTION INPUT ;
    USE SIGNAL ;
    PORT
      LAYER M4 ;
        RECT  104.004 35.472 104.088 35.496 ;
    END
  END a[578]
  PIN a[579]
    DIRECTION INPUT ;
    USE SIGNAL ;
    PORT
      LAYER M4 ;
        RECT  104.004 35.568 104.088 35.592 ;
    END
  END a[579]
  PIN a[57]
    DIRECTION INPUT ;
    USE SIGNAL ;
    PORT
      LAYER M4 ;
        RECT  104.004 47.664 104.088 47.688 ;
    END
  END a[57]
  PIN a[580]
    DIRECTION INPUT ;
    USE SIGNAL ;
    PORT
      LAYER M4 ;
        RECT  104.004 35.664 104.088 35.688 ;
    END
  END a[580]
  PIN a[581]
    DIRECTION INPUT ;
    USE SIGNAL ;
    PORT
      LAYER M4 ;
        RECT  104.004 35.76 104.088 35.784 ;
    END
  END a[581]
  PIN a[582]
    DIRECTION INPUT ;
    USE SIGNAL ;
    PORT
      LAYER M4 ;
        RECT  104.004 35.856 104.088 35.88 ;
    END
  END a[582]
  PIN a[583]
    DIRECTION INPUT ;
    USE SIGNAL ;
    PORT
      LAYER M4 ;
        RECT  104.004 35.952 104.088 35.976 ;
    END
  END a[583]
  PIN a[584]
    DIRECTION INPUT ;
    USE SIGNAL ;
    PORT
      LAYER M4 ;
        RECT  104.004 36.048 104.088 36.072 ;
    END
  END a[584]
  PIN a[585]
    DIRECTION INPUT ;
    USE SIGNAL ;
    PORT
      LAYER M4 ;
        RECT  104.004 36.144 104.088 36.168 ;
    END
  END a[585]
  PIN a[586]
    DIRECTION INPUT ;
    USE SIGNAL ;
    PORT
      LAYER M4 ;
        RECT  104.004 36.24 104.088 36.264 ;
    END
  END a[586]
  PIN a[587]
    DIRECTION INPUT ;
    USE SIGNAL ;
    PORT
      LAYER M4 ;
        RECT  104.004 36.336 104.088 36.36 ;
    END
  END a[587]
  PIN a[588]
    DIRECTION INPUT ;
    USE SIGNAL ;
    PORT
      LAYER M4 ;
        RECT  104.004 36.432 104.088 36.456 ;
    END
  END a[588]
  PIN a[589]
    DIRECTION INPUT ;
    USE SIGNAL ;
    PORT
      LAYER M4 ;
        RECT  104.004 36.528 104.088 36.552 ;
    END
  END a[589]
  PIN a[58]
    DIRECTION INPUT ;
    USE SIGNAL ;
    PORT
      LAYER M4 ;
        RECT  104.004 47.76 104.088 47.784 ;
    END
  END a[58]
  PIN a[590]
    DIRECTION INPUT ;
    USE SIGNAL ;
    PORT
      LAYER M4 ;
        RECT  104.004 36.624 104.088 36.648 ;
    END
  END a[590]
  PIN a[591]
    DIRECTION INPUT ;
    USE SIGNAL ;
    PORT
      LAYER M4 ;
        RECT  104.004 36.72 104.088 36.744 ;
    END
  END a[591]
  PIN a[592]
    DIRECTION INPUT ;
    USE SIGNAL ;
    PORT
      LAYER M4 ;
        RECT  104.004 36.816 104.088 36.84 ;
    END
  END a[592]
  PIN a[593]
    DIRECTION INPUT ;
    USE SIGNAL ;
    PORT
      LAYER M4 ;
        RECT  104.004 36.912 104.088 36.936 ;
    END
  END a[593]
  PIN a[594]
    DIRECTION INPUT ;
    USE SIGNAL ;
    PORT
      LAYER M4 ;
        RECT  104.004 37.008 104.088 37.032 ;
    END
  END a[594]
  PIN a[595]
    DIRECTION INPUT ;
    USE SIGNAL ;
    PORT
      LAYER M4 ;
        RECT  104.004 37.104 104.088 37.128 ;
    END
  END a[595]
  PIN a[596]
    DIRECTION INPUT ;
    USE SIGNAL ;
    PORT
      LAYER M4 ;
        RECT  104.004 37.2 104.088 37.224 ;
    END
  END a[596]
  PIN a[597]
    DIRECTION INPUT ;
    USE SIGNAL ;
    PORT
      LAYER M4 ;
        RECT  104.004 37.296 104.088 37.32 ;
    END
  END a[597]
  PIN a[598]
    DIRECTION INPUT ;
    USE SIGNAL ;
    PORT
      LAYER M4 ;
        RECT  104.004 37.392 104.088 37.416 ;
    END
  END a[598]
  PIN a[599]
    DIRECTION INPUT ;
    USE SIGNAL ;
    PORT
      LAYER M4 ;
        RECT  104.004 37.488 104.088 37.512 ;
    END
  END a[599]
  PIN a[59]
    DIRECTION INPUT ;
    USE SIGNAL ;
    PORT
      LAYER M4 ;
        RECT  104.004 47.856 104.088 47.88 ;
    END
  END a[59]
  PIN a[5]
    DIRECTION INPUT ;
    USE SIGNAL ;
    PORT
      LAYER M4 ;
        RECT  104.004 64.944 104.088 64.968 ;
    END
  END a[5]
  PIN a[60]
    DIRECTION INPUT ;
    USE SIGNAL ;
    PORT
      LAYER M4 ;
        RECT  104.004 47.952 104.088 47.976 ;
    END
  END a[60]
  PIN a[61]
    DIRECTION INPUT ;
    USE SIGNAL ;
    PORT
      LAYER M4 ;
        RECT  104.004 48.048 104.088 48.072 ;
    END
  END a[61]
  PIN a[62]
    DIRECTION INPUT ;
    USE SIGNAL ;
    PORT
      LAYER M4 ;
        RECT  104.004 48.144 104.088 48.168 ;
    END
  END a[62]
  PIN a[63]
    DIRECTION INPUT ;
    USE SIGNAL ;
    PORT
      LAYER M4 ;
        RECT  104.004 48.24 104.088 48.264 ;
    END
  END a[63]
  PIN a[64]
    DIRECTION INPUT ;
    USE SIGNAL ;
    PORT
      LAYER M4 ;
        RECT  104.004 61.392 104.088 61.416 ;
    END
  END a[64]
  PIN a[65]
    DIRECTION INPUT ;
    USE SIGNAL ;
    PORT
      LAYER M4 ;
        RECT  104.004 61.488 104.088 61.512 ;
    END
  END a[65]
  PIN a[66]
    DIRECTION INPUT ;
    USE SIGNAL ;
    PORT
      LAYER M4 ;
        RECT  104.004 61.584 104.088 61.608 ;
    END
  END a[66]
  PIN a[67]
    DIRECTION INPUT ;
    USE SIGNAL ;
    PORT
      LAYER M4 ;
        RECT  104.004 61.68 104.088 61.704 ;
    END
  END a[67]
  PIN a[68]
    DIRECTION INPUT ;
    USE SIGNAL ;
    PORT
      LAYER M4 ;
        RECT  104.004 61.776 104.088 61.8 ;
    END
  END a[68]
  PIN a[69]
    DIRECTION INPUT ;
    USE SIGNAL ;
    PORT
      LAYER M4 ;
        RECT  104.004 61.872 104.088 61.896 ;
    END
  END a[69]
  PIN a[6]
    DIRECTION INPUT ;
    USE SIGNAL ;
    PORT
      LAYER M4 ;
        RECT  104.004 65.04 104.088 65.064 ;
    END
  END a[6]
  PIN a[70]
    DIRECTION INPUT ;
    USE SIGNAL ;
    PORT
      LAYER M4 ;
        RECT  104.004 61.968 104.088 61.992 ;
    END
  END a[70]
  PIN a[71]
    DIRECTION INPUT ;
    USE SIGNAL ;
    PORT
      LAYER M4 ;
        RECT  104.004 62.064 104.088 62.088 ;
    END
  END a[71]
  PIN a[72]
    DIRECTION INPUT ;
    USE SIGNAL ;
    PORT
      LAYER M4 ;
        RECT  104.004 62.16 104.088 62.184 ;
    END
  END a[72]
  PIN a[73]
    DIRECTION INPUT ;
    USE SIGNAL ;
    PORT
      LAYER M4 ;
        RECT  104.004 62.256 104.088 62.28 ;
    END
  END a[73]
  PIN a[74]
    DIRECTION INPUT ;
    USE SIGNAL ;
    PORT
      LAYER M4 ;
        RECT  104.004 62.352 104.088 62.376 ;
    END
  END a[74]
  PIN a[75]
    DIRECTION INPUT ;
    USE SIGNAL ;
    PORT
      LAYER M4 ;
        RECT  104.004 62.448 104.088 62.472 ;
    END
  END a[75]
  PIN a[76]
    DIRECTION INPUT ;
    USE SIGNAL ;
    PORT
      LAYER M4 ;
        RECT  104.004 62.544 104.088 62.568 ;
    END
  END a[76]
  PIN a[77]
    DIRECTION INPUT ;
    USE SIGNAL ;
    PORT
      LAYER M4 ;
        RECT  104.004 62.64 104.088 62.664 ;
    END
  END a[77]
  PIN a[78]
    DIRECTION INPUT ;
    USE SIGNAL ;
    PORT
      LAYER M4 ;
        RECT  104.004 62.736 104.088 62.76 ;
    END
  END a[78]
  PIN a[79]
    DIRECTION INPUT ;
    USE SIGNAL ;
    PORT
      LAYER M4 ;
        RECT  104.004 62.832 104.088 62.856 ;
    END
  END a[79]
  PIN a[7]
    DIRECTION INPUT ;
    USE SIGNAL ;
    PORT
      LAYER M4 ;
        RECT  104.004 65.136 104.088 65.16 ;
    END
  END a[7]
  PIN a[80]
    DIRECTION INPUT ;
    USE SIGNAL ;
    PORT
      LAYER M4 ;
        RECT  104.004 62.928 104.088 62.952 ;
    END
  END a[80]
  PIN a[81]
    DIRECTION INPUT ;
    USE SIGNAL ;
    PORT
      LAYER M4 ;
        RECT  104.004 63.024 104.088 63.048 ;
    END
  END a[81]
  PIN a[82]
    DIRECTION INPUT ;
    USE SIGNAL ;
    PORT
      LAYER M4 ;
        RECT  104.004 63.12 104.088 63.144 ;
    END
  END a[82]
  PIN a[83]
    DIRECTION INPUT ;
    USE SIGNAL ;
    PORT
      LAYER M4 ;
        RECT  104.004 63.216 104.088 63.24 ;
    END
  END a[83]
  PIN a[84]
    DIRECTION INPUT ;
    USE SIGNAL ;
    PORT
      LAYER M4 ;
        RECT  104.004 63.312 104.088 63.336 ;
    END
  END a[84]
  PIN a[85]
    DIRECTION INPUT ;
    USE SIGNAL ;
    PORT
      LAYER M4 ;
        RECT  104.004 63.408 104.088 63.432 ;
    END
  END a[85]
  PIN a[86]
    DIRECTION INPUT ;
    USE SIGNAL ;
    PORT
      LAYER M4 ;
        RECT  104.004 63.504 104.088 63.528 ;
    END
  END a[86]
  PIN a[87]
    DIRECTION INPUT ;
    USE SIGNAL ;
    PORT
      LAYER M4 ;
        RECT  104.004 63.6 104.088 63.624 ;
    END
  END a[87]
  PIN a[88]
    DIRECTION INPUT ;
    USE SIGNAL ;
    PORT
      LAYER M4 ;
        RECT  104.004 63.696 104.088 63.72 ;
    END
  END a[88]
  PIN a[89]
    DIRECTION INPUT ;
    USE SIGNAL ;
    PORT
      LAYER M4 ;
        RECT  104.004 63.792 104.088 63.816 ;
    END
  END a[89]
  PIN a[8]
    DIRECTION INPUT ;
    USE SIGNAL ;
    PORT
      LAYER M4 ;
        RECT  104.004 65.232 104.088 65.256 ;
    END
  END a[8]
  PIN a[90]
    DIRECTION INPUT ;
    USE SIGNAL ;
    PORT
      LAYER M4 ;
        RECT  104.004 63.888 104.088 63.912 ;
    END
  END a[90]
  PIN a[91]
    DIRECTION INPUT ;
    USE SIGNAL ;
    PORT
      LAYER M4 ;
        RECT  104.004 63.984 104.088 64.008 ;
    END
  END a[91]
  PIN a[92]
    DIRECTION INPUT ;
    USE SIGNAL ;
    PORT
      LAYER M4 ;
        RECT  104.004 64.08 104.088 64.104 ;
    END
  END a[92]
  PIN a[93]
    DIRECTION INPUT ;
    USE SIGNAL ;
    PORT
      LAYER M4 ;
        RECT  104.004 64.176 104.088 64.2 ;
    END
  END a[93]
  PIN a[94]
    DIRECTION INPUT ;
    USE SIGNAL ;
    PORT
      LAYER M4 ;
        RECT  104.004 64.272 104.088 64.296 ;
    END
  END a[94]
  PIN a[95]
    DIRECTION INPUT ;
    USE SIGNAL ;
    PORT
      LAYER M4 ;
        RECT  104.004 64.368 104.088 64.392 ;
    END
  END a[95]
  PIN a[96]
    DIRECTION INPUT ;
    USE SIGNAL ;
    PORT
      LAYER M4 ;
        RECT  104.004 39.12 104.088 39.144 ;
    END
  END a[96]
  PIN a[97]
    DIRECTION INPUT ;
    USE SIGNAL ;
    PORT
      LAYER M4 ;
        RECT  104.004 39.216 104.088 39.24 ;
    END
  END a[97]
  PIN a[98]
    DIRECTION INPUT ;
    USE SIGNAL ;
    PORT
      LAYER M4 ;
        RECT  104.004 39.312 104.088 39.336 ;
    END
  END a[98]
  PIN a[99]
    DIRECTION INPUT ;
    USE SIGNAL ;
    PORT
      LAYER M4 ;
        RECT  104.004 39.408 104.088 39.432 ;
    END
  END a[99]
  PIN a[9]
    DIRECTION INPUT ;
    USE SIGNAL ;
    PORT
      LAYER M4 ;
        RECT  104.004 65.328 104.088 65.352 ;
    END
  END a[9]
  PIN b[0]
    DIRECTION OUTPUT ;
    USE SIGNAL ;
    PORT
      LAYER M3 ;
        RECT  36.756 105.779 36.774 105.816 ;
    END
  END b[0]
  PIN b[100]
    DIRECTION OUTPUT ;
    USE SIGNAL ;
    PORT
      LAYER M3 ;
        RECT  65.844 105.779 65.862 105.816 ;
    END
  END b[100]
  PIN b[101]
    DIRECTION OUTPUT ;
    USE SIGNAL ;
    PORT
      LAYER M3 ;
        RECT  65.916 105.779 65.934 105.816 ;
    END
  END b[101]
  PIN b[102]
    DIRECTION OUTPUT ;
    USE SIGNAL ;
    PORT
      LAYER M3 ;
        RECT  65.988 105.779 66.006 105.816 ;
    END
  END b[102]
  PIN b[103]
    DIRECTION OUTPUT ;
    USE SIGNAL ;
    PORT
      LAYER M3 ;
        RECT  66.06 105.779 66.078 105.816 ;
    END
  END b[103]
  PIN b[104]
    DIRECTION OUTPUT ;
    USE SIGNAL ;
    PORT
      LAYER M3 ;
        RECT  66.132 105.779 66.15 105.816 ;
    END
  END b[104]
  PIN b[105]
    DIRECTION OUTPUT ;
    USE SIGNAL ;
    PORT
      LAYER M3 ;
        RECT  66.204 105.779 66.222 105.816 ;
    END
  END b[105]
  PIN b[106]
    DIRECTION OUTPUT ;
    USE SIGNAL ;
    PORT
      LAYER M3 ;
        RECT  66.276 105.779 66.294 105.816 ;
    END
  END b[106]
  PIN b[107]
    DIRECTION OUTPUT ;
    USE SIGNAL ;
    PORT
      LAYER M3 ;
        RECT  66.348 105.779 66.366 105.816 ;
    END
  END b[107]
  PIN b[108]
    DIRECTION OUTPUT ;
    USE SIGNAL ;
    PORT
      LAYER M3 ;
        RECT  66.42 105.779 66.438 105.816 ;
    END
  END b[108]
  PIN b[109]
    DIRECTION OUTPUT ;
    USE SIGNAL ;
    PORT
      LAYER M3 ;
        RECT  66.492 105.779 66.51 105.816 ;
    END
  END b[109]
  PIN b[10]
    DIRECTION OUTPUT ;
    USE SIGNAL ;
    PORT
      LAYER M3 ;
        RECT  37.476 105.779 37.494 105.816 ;
    END
  END b[10]
  PIN b[110]
    DIRECTION OUTPUT ;
    USE SIGNAL ;
    PORT
      LAYER M3 ;
        RECT  66.564 105.779 66.582 105.816 ;
    END
  END b[110]
  PIN b[111]
    DIRECTION OUTPUT ;
    USE SIGNAL ;
    PORT
      LAYER M3 ;
        RECT  66.636 105.779 66.654 105.816 ;
    END
  END b[111]
  PIN b[112]
    DIRECTION OUTPUT ;
    USE SIGNAL ;
    PORT
      LAYER M3 ;
        RECT  66.708 105.779 66.726 105.816 ;
    END
  END b[112]
  PIN b[113]
    DIRECTION OUTPUT ;
    USE SIGNAL ;
    PORT
      LAYER M3 ;
        RECT  66.78 105.779 66.798 105.816 ;
    END
  END b[113]
  PIN b[114]
    DIRECTION OUTPUT ;
    USE SIGNAL ;
    PORT
      LAYER M3 ;
        RECT  66.852 105.779 66.87 105.816 ;
    END
  END b[114]
  PIN b[115]
    DIRECTION OUTPUT ;
    USE SIGNAL ;
    PORT
      LAYER M3 ;
        RECT  66.924 105.779 66.942 105.816 ;
    END
  END b[115]
  PIN b[116]
    DIRECTION OUTPUT ;
    USE SIGNAL ;
    PORT
      LAYER M3 ;
        RECT  66.996 105.779 67.014 105.816 ;
    END
  END b[116]
  PIN b[117]
    DIRECTION OUTPUT ;
    USE SIGNAL ;
    PORT
      LAYER M3 ;
        RECT  67.068 105.779 67.086 105.816 ;
    END
  END b[117]
  PIN b[118]
    DIRECTION OUTPUT ;
    USE SIGNAL ;
    PORT
      LAYER M3 ;
        RECT  67.14 105.779 67.158 105.816 ;
    END
  END b[118]
  PIN b[119]
    DIRECTION OUTPUT ;
    USE SIGNAL ;
    PORT
      LAYER M3 ;
        RECT  67.212 105.779 67.23 105.816 ;
    END
  END b[119]
  PIN b[11]
    DIRECTION OUTPUT ;
    USE SIGNAL ;
    PORT
      LAYER M3 ;
        RECT  37.548 105.779 37.566 105.816 ;
    END
  END b[11]
  PIN b[120]
    DIRECTION OUTPUT ;
    USE SIGNAL ;
    PORT
      LAYER M3 ;
        RECT  67.284 105.779 67.302 105.816 ;
    END
  END b[120]
  PIN b[121]
    DIRECTION OUTPUT ;
    USE SIGNAL ;
    PORT
      LAYER M3 ;
        RECT  67.356 105.779 67.374 105.816 ;
    END
  END b[121]
  PIN b[122]
    DIRECTION OUTPUT ;
    USE SIGNAL ;
    PORT
      LAYER M3 ;
        RECT  67.428 105.779 67.446 105.816 ;
    END
  END b[122]
  PIN b[123]
    DIRECTION OUTPUT ;
    USE SIGNAL ;
    PORT
      LAYER M3 ;
        RECT  67.5 105.779 67.518 105.816 ;
    END
  END b[123]
  PIN b[124]
    DIRECTION OUTPUT ;
    USE SIGNAL ;
    PORT
      LAYER M3 ;
        RECT  67.572 105.779 67.59 105.816 ;
    END
  END b[124]
  PIN b[125]
    DIRECTION OUTPUT ;
    USE SIGNAL ;
    PORT
      LAYER M3 ;
        RECT  67.644 105.779 67.662 105.816 ;
    END
  END b[125]
  PIN b[126]
    DIRECTION OUTPUT ;
    USE SIGNAL ;
    PORT
      LAYER M3 ;
        RECT  67.716 105.779 67.734 105.816 ;
    END
  END b[126]
  PIN b[127]
    DIRECTION OUTPUT ;
    USE SIGNAL ;
    PORT
      LAYER M3 ;
        RECT  67.788 105.779 67.806 105.816 ;
    END
  END b[127]
  PIN b[128]
    DIRECTION OUTPUT ;
    USE SIGNAL ;
    PORT
      LAYER M3 ;
        RECT  67.86 105.779 67.878 105.816 ;
    END
  END b[128]
  PIN b[129]
    DIRECTION OUTPUT ;
    USE SIGNAL ;
    PORT
      LAYER M3 ;
        RECT  67.932 105.779 67.95 105.816 ;
    END
  END b[129]
  PIN b[12]
    DIRECTION OUTPUT ;
    USE SIGNAL ;
    PORT
      LAYER M3 ;
        RECT  37.62 105.779 37.638 105.816 ;
    END
  END b[12]
  PIN b[130]
    DIRECTION OUTPUT ;
    USE SIGNAL ;
    PORT
      LAYER M3 ;
        RECT  68.004 105.779 68.022 105.816 ;
    END
  END b[130]
  PIN b[131]
    DIRECTION OUTPUT ;
    USE SIGNAL ;
    PORT
      LAYER M3 ;
        RECT  68.076 105.779 68.094 105.816 ;
    END
  END b[131]
  PIN b[132]
    DIRECTION OUTPUT ;
    USE SIGNAL ;
    PORT
      LAYER M3 ;
        RECT  68.148 105.779 68.166 105.816 ;
    END
  END b[132]
  PIN b[133]
    DIRECTION OUTPUT ;
    USE SIGNAL ;
    PORT
      LAYER M3 ;
        RECT  68.22 105.779 68.238 105.816 ;
    END
  END b[133]
  PIN b[134]
    DIRECTION OUTPUT ;
    USE SIGNAL ;
    PORT
      LAYER M3 ;
        RECT  68.292 105.779 68.31 105.816 ;
    END
  END b[134]
  PIN b[135]
    DIRECTION OUTPUT ;
    USE SIGNAL ;
    PORT
      LAYER M3 ;
        RECT  68.364 105.779 68.382 105.816 ;
    END
  END b[135]
  PIN b[136]
    DIRECTION OUTPUT ;
    USE SIGNAL ;
    PORT
      LAYER M3 ;
        RECT  68.436 105.779 68.454 105.816 ;
    END
  END b[136]
  PIN b[137]
    DIRECTION OUTPUT ;
    USE SIGNAL ;
    PORT
      LAYER M3 ;
        RECT  68.508 105.779 68.526 105.816 ;
    END
  END b[137]
  PIN b[138]
    DIRECTION OUTPUT ;
    USE SIGNAL ;
    PORT
      LAYER M3 ;
        RECT  68.58 105.779 68.598 105.816 ;
    END
  END b[138]
  PIN b[139]
    DIRECTION OUTPUT ;
    USE SIGNAL ;
    PORT
      LAYER M3 ;
        RECT  68.652 105.779 68.67 105.816 ;
    END
  END b[139]
  PIN b[13]
    DIRECTION OUTPUT ;
    USE SIGNAL ;
    PORT
      LAYER M3 ;
        RECT  37.692 105.779 37.71 105.816 ;
    END
  END b[13]
  PIN b[140]
    DIRECTION OUTPUT ;
    USE SIGNAL ;
    PORT
      LAYER M3 ;
        RECT  68.724 105.779 68.742 105.816 ;
    END
  END b[140]
  PIN b[141]
    DIRECTION OUTPUT ;
    USE SIGNAL ;
    PORT
      LAYER M3 ;
        RECT  68.796 105.779 68.814 105.816 ;
    END
  END b[141]
  PIN b[142]
    DIRECTION OUTPUT ;
    USE SIGNAL ;
    PORT
      LAYER M3 ;
        RECT  68.868 105.779 68.886 105.816 ;
    END
  END b[142]
  PIN b[143]
    DIRECTION OUTPUT ;
    USE SIGNAL ;
    PORT
      LAYER M3 ;
        RECT  68.94 105.779 68.958 105.816 ;
    END
  END b[143]
  PIN b[144]
    DIRECTION OUTPUT ;
    USE SIGNAL ;
    PORT
      LAYER M3 ;
        RECT  69.012 105.779 69.03 105.816 ;
    END
  END b[144]
  PIN b[145]
    DIRECTION OUTPUT ;
    USE SIGNAL ;
    PORT
      LAYER M3 ;
        RECT  69.084 105.779 69.102 105.816 ;
    END
  END b[145]
  PIN b[146]
    DIRECTION OUTPUT ;
    USE SIGNAL ;
    PORT
      LAYER M3 ;
        RECT  69.156 105.779 69.174 105.816 ;
    END
  END b[146]
  PIN b[147]
    DIRECTION OUTPUT ;
    USE SIGNAL ;
    PORT
      LAYER M3 ;
        RECT  69.228 105.779 69.246 105.816 ;
    END
  END b[147]
  PIN b[148]
    DIRECTION OUTPUT ;
    USE SIGNAL ;
    PORT
      LAYER M3 ;
        RECT  69.3 105.779 69.318 105.816 ;
    END
  END b[148]
  PIN b[149]
    DIRECTION OUTPUT ;
    USE SIGNAL ;
    PORT
      LAYER M3 ;
        RECT  69.372 105.779 69.39 105.816 ;
    END
  END b[149]
  PIN b[14]
    DIRECTION OUTPUT ;
    USE SIGNAL ;
    PORT
      LAYER M3 ;
        RECT  37.764 105.779 37.782 105.816 ;
    END
  END b[14]
  PIN b[150]
    DIRECTION OUTPUT ;
    USE SIGNAL ;
    PORT
      LAYER M3 ;
        RECT  69.444 105.779 69.462 105.816 ;
    END
  END b[150]
  PIN b[151]
    DIRECTION OUTPUT ;
    USE SIGNAL ;
    PORT
      LAYER M3 ;
        RECT  69.516 105.779 69.534 105.816 ;
    END
  END b[151]
  PIN b[152]
    DIRECTION OUTPUT ;
    USE SIGNAL ;
    PORT
      LAYER M3 ;
        RECT  69.588 105.779 69.606 105.816 ;
    END
  END b[152]
  PIN b[153]
    DIRECTION OUTPUT ;
    USE SIGNAL ;
    PORT
      LAYER M3 ;
        RECT  69.66 105.779 69.678 105.816 ;
    END
  END b[153]
  PIN b[154]
    DIRECTION OUTPUT ;
    USE SIGNAL ;
    PORT
      LAYER M3 ;
        RECT  69.732 105.779 69.75 105.816 ;
    END
  END b[154]
  PIN b[155]
    DIRECTION OUTPUT ;
    USE SIGNAL ;
    PORT
      LAYER M3 ;
        RECT  69.804 105.779 69.822 105.816 ;
    END
  END b[155]
  PIN b[156]
    DIRECTION OUTPUT ;
    USE SIGNAL ;
    PORT
      LAYER M3 ;
        RECT  69.876 105.779 69.894 105.816 ;
    END
  END b[156]
  PIN b[157]
    DIRECTION OUTPUT ;
    USE SIGNAL ;
    PORT
      LAYER M3 ;
        RECT  69.948 105.779 69.966 105.816 ;
    END
  END b[157]
  PIN b[158]
    DIRECTION OUTPUT ;
    USE SIGNAL ;
    PORT
      LAYER M3 ;
        RECT  70.02 105.779 70.038 105.816 ;
    END
  END b[158]
  PIN b[159]
    DIRECTION OUTPUT ;
    USE SIGNAL ;
    PORT
      LAYER M3 ;
        RECT  70.092 105.779 70.11 105.816 ;
    END
  END b[159]
  PIN b[15]
    DIRECTION OUTPUT ;
    USE SIGNAL ;
    PORT
      LAYER M3 ;
        RECT  37.836 105.779 37.854 105.816 ;
    END
  END b[15]
  PIN b[160]
    DIRECTION OUTPUT ;
    USE SIGNAL ;
    PORT
      LAYER M3 ;
        RECT  82.26 105.779 82.278 105.816 ;
    END
  END b[160]
  PIN b[161]
    DIRECTION OUTPUT ;
    USE SIGNAL ;
    PORT
      LAYER M3 ;
        RECT  82.332 105.779 82.35 105.816 ;
    END
  END b[161]
  PIN b[162]
    DIRECTION OUTPUT ;
    USE SIGNAL ;
    PORT
      LAYER M3 ;
        RECT  82.404 105.779 82.422 105.816 ;
    END
  END b[162]
  PIN b[163]
    DIRECTION OUTPUT ;
    USE SIGNAL ;
    PORT
      LAYER M3 ;
        RECT  82.476 105.779 82.494 105.816 ;
    END
  END b[163]
  PIN b[164]
    DIRECTION OUTPUT ;
    USE SIGNAL ;
    PORT
      LAYER M3 ;
        RECT  82.548 105.779 82.566 105.816 ;
    END
  END b[164]
  PIN b[165]
    DIRECTION OUTPUT ;
    USE SIGNAL ;
    PORT
      LAYER M3 ;
        RECT  82.62 105.779 82.638 105.816 ;
    END
  END b[165]
  PIN b[166]
    DIRECTION OUTPUT ;
    USE SIGNAL ;
    PORT
      LAYER M3 ;
        RECT  82.692 105.779 82.71 105.816 ;
    END
  END b[166]
  PIN b[167]
    DIRECTION OUTPUT ;
    USE SIGNAL ;
    PORT
      LAYER M3 ;
        RECT  82.764 105.779 82.782 105.816 ;
    END
  END b[167]
  PIN b[168]
    DIRECTION OUTPUT ;
    USE SIGNAL ;
    PORT
      LAYER M3 ;
        RECT  82.836 105.779 82.854 105.816 ;
    END
  END b[168]
  PIN b[169]
    DIRECTION OUTPUT ;
    USE SIGNAL ;
    PORT
      LAYER M3 ;
        RECT  82.908 105.779 82.926 105.816 ;
    END
  END b[169]
  PIN b[16]
    DIRECTION OUTPUT ;
    USE SIGNAL ;
    PORT
      LAYER M3 ;
        RECT  37.908 105.779 37.926 105.816 ;
    END
  END b[16]
  PIN b[170]
    DIRECTION OUTPUT ;
    USE SIGNAL ;
    PORT
      LAYER M3 ;
        RECT  82.98 105.779 82.998 105.816 ;
    END
  END b[170]
  PIN b[171]
    DIRECTION OUTPUT ;
    USE SIGNAL ;
    PORT
      LAYER M3 ;
        RECT  83.052 105.779 83.07 105.816 ;
    END
  END b[171]
  PIN b[172]
    DIRECTION OUTPUT ;
    USE SIGNAL ;
    PORT
      LAYER M3 ;
        RECT  83.124 105.779 83.142 105.816 ;
    END
  END b[172]
  PIN b[173]
    DIRECTION OUTPUT ;
    USE SIGNAL ;
    PORT
      LAYER M3 ;
        RECT  83.196 105.779 83.214 105.816 ;
    END
  END b[173]
  PIN b[174]
    DIRECTION OUTPUT ;
    USE SIGNAL ;
    PORT
      LAYER M3 ;
        RECT  83.268 105.779 83.286 105.816 ;
    END
  END b[174]
  PIN b[175]
    DIRECTION OUTPUT ;
    USE SIGNAL ;
    PORT
      LAYER M3 ;
        RECT  83.34 105.779 83.358 105.816 ;
    END
  END b[175]
  PIN b[176]
    DIRECTION OUTPUT ;
    USE SIGNAL ;
    PORT
      LAYER M3 ;
        RECT  83.412 105.779 83.43 105.816 ;
    END
  END b[176]
  PIN b[177]
    DIRECTION OUTPUT ;
    USE SIGNAL ;
    PORT
      LAYER M3 ;
        RECT  83.484 105.779 83.502 105.816 ;
    END
  END b[177]
  PIN b[178]
    DIRECTION OUTPUT ;
    USE SIGNAL ;
    PORT
      LAYER M3 ;
        RECT  83.556 105.779 83.574 105.816 ;
    END
  END b[178]
  PIN b[179]
    DIRECTION OUTPUT ;
    USE SIGNAL ;
    PORT
      LAYER M3 ;
        RECT  83.628 105.779 83.646 105.816 ;
    END
  END b[179]
  PIN b[17]
    DIRECTION OUTPUT ;
    USE SIGNAL ;
    PORT
      LAYER M3 ;
        RECT  37.98 105.779 37.998 105.816 ;
    END
  END b[17]
  PIN b[180]
    DIRECTION OUTPUT ;
    USE SIGNAL ;
    PORT
      LAYER M3 ;
        RECT  83.7 105.779 83.718 105.816 ;
    END
  END b[180]
  PIN b[181]
    DIRECTION OUTPUT ;
    USE SIGNAL ;
    PORT
      LAYER M3 ;
        RECT  83.772 105.779 83.79 105.816 ;
    END
  END b[181]
  PIN b[182]
    DIRECTION OUTPUT ;
    USE SIGNAL ;
    PORT
      LAYER M3 ;
        RECT  83.844 105.779 83.862 105.816 ;
    END
  END b[182]
  PIN b[183]
    DIRECTION OUTPUT ;
    USE SIGNAL ;
    PORT
      LAYER M3 ;
        RECT  83.916 105.779 83.934 105.816 ;
    END
  END b[183]
  PIN b[184]
    DIRECTION OUTPUT ;
    USE SIGNAL ;
    PORT
      LAYER M3 ;
        RECT  83.988 105.779 84.006 105.816 ;
    END
  END b[184]
  PIN b[185]
    DIRECTION OUTPUT ;
    USE SIGNAL ;
    PORT
      LAYER M3 ;
        RECT  84.06 105.779 84.078 105.816 ;
    END
  END b[185]
  PIN b[186]
    DIRECTION OUTPUT ;
    USE SIGNAL ;
    PORT
      LAYER M3 ;
        RECT  84.132 105.779 84.15 105.816 ;
    END
  END b[186]
  PIN b[187]
    DIRECTION OUTPUT ;
    USE SIGNAL ;
    PORT
      LAYER M3 ;
        RECT  84.204 105.779 84.222 105.816 ;
    END
  END b[187]
  PIN b[188]
    DIRECTION OUTPUT ;
    USE SIGNAL ;
    PORT
      LAYER M3 ;
        RECT  84.276 105.779 84.294 105.816 ;
    END
  END b[188]
  PIN b[189]
    DIRECTION OUTPUT ;
    USE SIGNAL ;
    PORT
      LAYER M3 ;
        RECT  84.348 105.779 84.366 105.816 ;
    END
  END b[189]
  PIN b[18]
    DIRECTION OUTPUT ;
    USE SIGNAL ;
    PORT
      LAYER M3 ;
        RECT  38.052 105.779 38.07 105.816 ;
    END
  END b[18]
  PIN b[190]
    DIRECTION OUTPUT ;
    USE SIGNAL ;
    PORT
      LAYER M3 ;
        RECT  84.42 105.779 84.438 105.816 ;
    END
  END b[190]
  PIN b[191]
    DIRECTION OUTPUT ;
    USE SIGNAL ;
    PORT
      LAYER M3 ;
        RECT  84.492 105.779 84.51 105.816 ;
    END
  END b[191]
  PIN b[192]
    DIRECTION OUTPUT ;
    USE SIGNAL ;
    PORT
      LAYER M5 ;
        RECT  71.952 105.732 71.976 105.816 ;
    END
  END b[192]
  PIN b[193]
    DIRECTION OUTPUT ;
    USE SIGNAL ;
    PORT
      LAYER M5 ;
        RECT  72.048 105.732 72.072 105.816 ;
    END
  END b[193]
  PIN b[194]
    DIRECTION OUTPUT ;
    USE SIGNAL ;
    PORT
      LAYER M5 ;
        RECT  72.144 105.732 72.168 105.816 ;
    END
  END b[194]
  PIN b[195]
    DIRECTION OUTPUT ;
    USE SIGNAL ;
    PORT
      LAYER M5 ;
        RECT  72.24 105.732 72.264 105.816 ;
    END
  END b[195]
  PIN b[196]
    DIRECTION OUTPUT ;
    USE SIGNAL ;
    PORT
      LAYER M5 ;
        RECT  72.336 105.732 72.36 105.816 ;
    END
  END b[196]
  PIN b[197]
    DIRECTION OUTPUT ;
    USE SIGNAL ;
    PORT
      LAYER M5 ;
        RECT  72.432 105.732 72.456 105.816 ;
    END
  END b[197]
  PIN b[198]
    DIRECTION OUTPUT ;
    USE SIGNAL ;
    PORT
      LAYER M5 ;
        RECT  72.528 105.732 72.552 105.816 ;
    END
  END b[198]
  PIN b[199]
    DIRECTION OUTPUT ;
    USE SIGNAL ;
    PORT
      LAYER M5 ;
        RECT  72.624 105.732 72.648 105.816 ;
    END
  END b[199]
  PIN b[19]
    DIRECTION OUTPUT ;
    USE SIGNAL ;
    PORT
      LAYER M3 ;
        RECT  38.124 105.779 38.142 105.816 ;
    END
  END b[19]
  PIN b[1]
    DIRECTION OUTPUT ;
    USE SIGNAL ;
    PORT
      LAYER M3 ;
        RECT  36.828 105.779 36.846 105.816 ;
    END
  END b[1]
  PIN b[200]
    DIRECTION OUTPUT ;
    USE SIGNAL ;
    PORT
      LAYER M5 ;
        RECT  72.72 105.732 72.744 105.816 ;
    END
  END b[200]
  PIN b[201]
    DIRECTION OUTPUT ;
    USE SIGNAL ;
    PORT
      LAYER M5 ;
        RECT  72.816 105.732 72.84 105.816 ;
    END
  END b[201]
  PIN b[202]
    DIRECTION OUTPUT ;
    USE SIGNAL ;
    PORT
      LAYER M5 ;
        RECT  72.912 105.732 72.936 105.816 ;
    END
  END b[202]
  PIN b[203]
    DIRECTION OUTPUT ;
    USE SIGNAL ;
    PORT
      LAYER M5 ;
        RECT  73.008 105.732 73.032 105.816 ;
    END
  END b[203]
  PIN b[204]
    DIRECTION OUTPUT ;
    USE SIGNAL ;
    PORT
      LAYER M5 ;
        RECT  73.104 105.732 73.128 105.816 ;
    END
  END b[204]
  PIN b[205]
    DIRECTION OUTPUT ;
    USE SIGNAL ;
    PORT
      LAYER M5 ;
        RECT  73.2 105.732 73.224 105.816 ;
    END
  END b[205]
  PIN b[206]
    DIRECTION OUTPUT ;
    USE SIGNAL ;
    PORT
      LAYER M5 ;
        RECT  73.296 105.732 73.32 105.816 ;
    END
  END b[206]
  PIN b[207]
    DIRECTION OUTPUT ;
    USE SIGNAL ;
    PORT
      LAYER M5 ;
        RECT  73.392 105.732 73.416 105.816 ;
    END
  END b[207]
  PIN b[208]
    DIRECTION OUTPUT ;
    USE SIGNAL ;
    PORT
      LAYER M5 ;
        RECT  73.488 105.732 73.512 105.816 ;
    END
  END b[208]
  PIN b[209]
    DIRECTION OUTPUT ;
    USE SIGNAL ;
    PORT
      LAYER M5 ;
        RECT  73.584 105.732 73.608 105.816 ;
    END
  END b[209]
  PIN b[20]
    DIRECTION OUTPUT ;
    USE SIGNAL ;
    PORT
      LAYER M3 ;
        RECT  38.196 105.779 38.214 105.816 ;
    END
  END b[20]
  PIN b[210]
    DIRECTION OUTPUT ;
    USE SIGNAL ;
    PORT
      LAYER M5 ;
        RECT  73.68 105.732 73.704 105.816 ;
    END
  END b[210]
  PIN b[211]
    DIRECTION OUTPUT ;
    USE SIGNAL ;
    PORT
      LAYER M5 ;
        RECT  73.776 105.732 73.8 105.816 ;
    END
  END b[211]
  PIN b[212]
    DIRECTION OUTPUT ;
    USE SIGNAL ;
    PORT
      LAYER M5 ;
        RECT  73.872 105.732 73.896 105.816 ;
    END
  END b[212]
  PIN b[213]
    DIRECTION OUTPUT ;
    USE SIGNAL ;
    PORT
      LAYER M5 ;
        RECT  73.968 105.732 73.992 105.816 ;
    END
  END b[213]
  PIN b[214]
    DIRECTION OUTPUT ;
    USE SIGNAL ;
    PORT
      LAYER M5 ;
        RECT  74.064 105.732 74.088 105.816 ;
    END
  END b[214]
  PIN b[215]
    DIRECTION OUTPUT ;
    USE SIGNAL ;
    PORT
      LAYER M5 ;
        RECT  74.16 105.732 74.184 105.816 ;
    END
  END b[215]
  PIN b[216]
    DIRECTION OUTPUT ;
    USE SIGNAL ;
    PORT
      LAYER M5 ;
        RECT  74.256 105.732 74.28 105.816 ;
    END
  END b[216]
  PIN b[217]
    DIRECTION OUTPUT ;
    USE SIGNAL ;
    PORT
      LAYER M5 ;
        RECT  74.352 105.732 74.376 105.816 ;
    END
  END b[217]
  PIN b[218]
    DIRECTION OUTPUT ;
    USE SIGNAL ;
    PORT
      LAYER M5 ;
        RECT  74.448 105.732 74.472 105.816 ;
    END
  END b[218]
  PIN b[219]
    DIRECTION OUTPUT ;
    USE SIGNAL ;
    PORT
      LAYER M5 ;
        RECT  74.544 105.732 74.568 105.816 ;
    END
  END b[219]
  PIN b[21]
    DIRECTION OUTPUT ;
    USE SIGNAL ;
    PORT
      LAYER M3 ;
        RECT  38.268 105.779 38.286 105.816 ;
    END
  END b[21]
  PIN b[220]
    DIRECTION OUTPUT ;
    USE SIGNAL ;
    PORT
      LAYER M5 ;
        RECT  74.64 105.732 74.664 105.816 ;
    END
  END b[220]
  PIN b[221]
    DIRECTION OUTPUT ;
    USE SIGNAL ;
    PORT
      LAYER M5 ;
        RECT  74.736 105.732 74.76 105.816 ;
    END
  END b[221]
  PIN b[222]
    DIRECTION OUTPUT ;
    USE SIGNAL ;
    PORT
      LAYER M5 ;
        RECT  74.832 105.732 74.856 105.816 ;
    END
  END b[222]
  PIN b[223]
    DIRECTION OUTPUT ;
    USE SIGNAL ;
    PORT
      LAYER M5 ;
        RECT  74.928 105.732 74.952 105.816 ;
    END
  END b[223]
  PIN b[224]
    DIRECTION OUTPUT ;
    USE SIGNAL ;
    PORT
      LAYER M3 ;
        RECT  77.652 105.779 77.67 105.816 ;
    END
  END b[224]
  PIN b[225]
    DIRECTION OUTPUT ;
    USE SIGNAL ;
    PORT
      LAYER M3 ;
        RECT  77.724 105.779 77.742 105.816 ;
    END
  END b[225]
  PIN b[226]
    DIRECTION OUTPUT ;
    USE SIGNAL ;
    PORT
      LAYER M3 ;
        RECT  77.796 105.779 77.814 105.816 ;
    END
  END b[226]
  PIN b[227]
    DIRECTION OUTPUT ;
    USE SIGNAL ;
    PORT
      LAYER M3 ;
        RECT  77.868 105.779 77.886 105.816 ;
    END
  END b[227]
  PIN b[228]
    DIRECTION OUTPUT ;
    USE SIGNAL ;
    PORT
      LAYER M3 ;
        RECT  77.94 105.779 77.958 105.816 ;
    END
  END b[228]
  PIN b[229]
    DIRECTION OUTPUT ;
    USE SIGNAL ;
    PORT
      LAYER M3 ;
        RECT  78.012 105.779 78.03 105.816 ;
    END
  END b[229]
  PIN b[22]
    DIRECTION OUTPUT ;
    USE SIGNAL ;
    PORT
      LAYER M3 ;
        RECT  38.34 105.779 38.358 105.816 ;
    END
  END b[22]
  PIN b[230]
    DIRECTION OUTPUT ;
    USE SIGNAL ;
    PORT
      LAYER M3 ;
        RECT  78.084 105.779 78.102 105.816 ;
    END
  END b[230]
  PIN b[231]
    DIRECTION OUTPUT ;
    USE SIGNAL ;
    PORT
      LAYER M3 ;
        RECT  78.156 105.779 78.174 105.816 ;
    END
  END b[231]
  PIN b[232]
    DIRECTION OUTPUT ;
    USE SIGNAL ;
    PORT
      LAYER M3 ;
        RECT  78.228 105.779 78.246 105.816 ;
    END
  END b[232]
  PIN b[233]
    DIRECTION OUTPUT ;
    USE SIGNAL ;
    PORT
      LAYER M3 ;
        RECT  78.3 105.779 78.318 105.816 ;
    END
  END b[233]
  PIN b[234]
    DIRECTION OUTPUT ;
    USE SIGNAL ;
    PORT
      LAYER M3 ;
        RECT  78.372 105.779 78.39 105.816 ;
    END
  END b[234]
  PIN b[235]
    DIRECTION OUTPUT ;
    USE SIGNAL ;
    PORT
      LAYER M3 ;
        RECT  78.444 105.779 78.462 105.816 ;
    END
  END b[235]
  PIN b[236]
    DIRECTION OUTPUT ;
    USE SIGNAL ;
    PORT
      LAYER M3 ;
        RECT  78.516 105.779 78.534 105.816 ;
    END
  END b[236]
  PIN b[237]
    DIRECTION OUTPUT ;
    USE SIGNAL ;
    PORT
      LAYER M3 ;
        RECT  78.588 105.779 78.606 105.816 ;
    END
  END b[237]
  PIN b[238]
    DIRECTION OUTPUT ;
    USE SIGNAL ;
    PORT
      LAYER M3 ;
        RECT  78.66 105.779 78.678 105.816 ;
    END
  END b[238]
  PIN b[239]
    DIRECTION OUTPUT ;
    USE SIGNAL ;
    PORT
      LAYER M3 ;
        RECT  78.732 105.779 78.75 105.816 ;
    END
  END b[239]
  PIN b[23]
    DIRECTION OUTPUT ;
    USE SIGNAL ;
    PORT
      LAYER M3 ;
        RECT  38.412 105.779 38.43 105.816 ;
    END
  END b[23]
  PIN b[240]
    DIRECTION OUTPUT ;
    USE SIGNAL ;
    PORT
      LAYER M3 ;
        RECT  78.804 105.779 78.822 105.816 ;
    END
  END b[240]
  PIN b[241]
    DIRECTION OUTPUT ;
    USE SIGNAL ;
    PORT
      LAYER M3 ;
        RECT  78.876 105.779 78.894 105.816 ;
    END
  END b[241]
  PIN b[242]
    DIRECTION OUTPUT ;
    USE SIGNAL ;
    PORT
      LAYER M3 ;
        RECT  78.948 105.779 78.966 105.816 ;
    END
  END b[242]
  PIN b[243]
    DIRECTION OUTPUT ;
    USE SIGNAL ;
    PORT
      LAYER M3 ;
        RECT  79.02 105.779 79.038 105.816 ;
    END
  END b[243]
  PIN b[244]
    DIRECTION OUTPUT ;
    USE SIGNAL ;
    PORT
      LAYER M3 ;
        RECT  79.092 105.779 79.11 105.816 ;
    END
  END b[244]
  PIN b[245]
    DIRECTION OUTPUT ;
    USE SIGNAL ;
    PORT
      LAYER M3 ;
        RECT  79.164 105.779 79.182 105.816 ;
    END
  END b[245]
  PIN b[246]
    DIRECTION OUTPUT ;
    USE SIGNAL ;
    PORT
      LAYER M3 ;
        RECT  79.236 105.779 79.254 105.816 ;
    END
  END b[246]
  PIN b[247]
    DIRECTION OUTPUT ;
    USE SIGNAL ;
    PORT
      LAYER M3 ;
        RECT  79.308 105.779 79.326 105.816 ;
    END
  END b[247]
  PIN b[248]
    DIRECTION OUTPUT ;
    USE SIGNAL ;
    PORT
      LAYER M3 ;
        RECT  79.38 105.779 79.398 105.816 ;
    END
  END b[248]
  PIN b[249]
    DIRECTION OUTPUT ;
    USE SIGNAL ;
    PORT
      LAYER M3 ;
        RECT  79.452 105.779 79.47 105.816 ;
    END
  END b[249]
  PIN b[24]
    DIRECTION OUTPUT ;
    USE SIGNAL ;
    PORT
      LAYER M3 ;
        RECT  38.484 105.779 38.502 105.816 ;
    END
  END b[24]
  PIN b[250]
    DIRECTION OUTPUT ;
    USE SIGNAL ;
    PORT
      LAYER M3 ;
        RECT  79.524 105.779 79.542 105.816 ;
    END
  END b[250]
  PIN b[251]
    DIRECTION OUTPUT ;
    USE SIGNAL ;
    PORT
      LAYER M3 ;
        RECT  79.596 105.779 79.614 105.816 ;
    END
  END b[251]
  PIN b[252]
    DIRECTION OUTPUT ;
    USE SIGNAL ;
    PORT
      LAYER M3 ;
        RECT  79.668 105.779 79.686 105.816 ;
    END
  END b[252]
  PIN b[253]
    DIRECTION OUTPUT ;
    USE SIGNAL ;
    PORT
      LAYER M3 ;
        RECT  79.74 105.779 79.758 105.816 ;
    END
  END b[253]
  PIN b[254]
    DIRECTION OUTPUT ;
    USE SIGNAL ;
    PORT
      LAYER M3 ;
        RECT  79.812 105.779 79.83 105.816 ;
    END
  END b[254]
  PIN b[255]
    DIRECTION OUTPUT ;
    USE SIGNAL ;
    PORT
      LAYER M3 ;
        RECT  79.884 105.779 79.902 105.816 ;
    END
  END b[255]
  PIN b[256]
    DIRECTION OUTPUT ;
    USE SIGNAL ;
    PORT
      LAYER M3 ;
        RECT  79.956 105.779 79.974 105.816 ;
    END
  END b[256]
  PIN b[257]
    DIRECTION OUTPUT ;
    USE SIGNAL ;
    PORT
      LAYER M3 ;
        RECT  80.028 105.779 80.046 105.816 ;
    END
  END b[257]
  PIN b[258]
    DIRECTION OUTPUT ;
    USE SIGNAL ;
    PORT
      LAYER M3 ;
        RECT  80.1 105.779 80.118 105.816 ;
    END
  END b[258]
  PIN b[259]
    DIRECTION OUTPUT ;
    USE SIGNAL ;
    PORT
      LAYER M3 ;
        RECT  80.172 105.779 80.19 105.816 ;
    END
  END b[259]
  PIN b[25]
    DIRECTION OUTPUT ;
    USE SIGNAL ;
    PORT
      LAYER M3 ;
        RECT  38.556 105.779 38.574 105.816 ;
    END
  END b[25]
  PIN b[260]
    DIRECTION OUTPUT ;
    USE SIGNAL ;
    PORT
      LAYER M3 ;
        RECT  80.244 105.779 80.262 105.816 ;
    END
  END b[260]
  PIN b[261]
    DIRECTION OUTPUT ;
    USE SIGNAL ;
    PORT
      LAYER M3 ;
        RECT  80.316 105.779 80.334 105.816 ;
    END
  END b[261]
  PIN b[262]
    DIRECTION OUTPUT ;
    USE SIGNAL ;
    PORT
      LAYER M3 ;
        RECT  80.388 105.779 80.406 105.816 ;
    END
  END b[262]
  PIN b[263]
    DIRECTION OUTPUT ;
    USE SIGNAL ;
    PORT
      LAYER M3 ;
        RECT  80.46 105.779 80.478 105.816 ;
    END
  END b[263]
  PIN b[264]
    DIRECTION OUTPUT ;
    USE SIGNAL ;
    PORT
      LAYER M3 ;
        RECT  80.532 105.779 80.55 105.816 ;
    END
  END b[264]
  PIN b[265]
    DIRECTION OUTPUT ;
    USE SIGNAL ;
    PORT
      LAYER M3 ;
        RECT  80.604 105.779 80.622 105.816 ;
    END
  END b[265]
  PIN b[266]
    DIRECTION OUTPUT ;
    USE SIGNAL ;
    PORT
      LAYER M3 ;
        RECT  80.676 105.779 80.694 105.816 ;
    END
  END b[266]
  PIN b[267]
    DIRECTION OUTPUT ;
    USE SIGNAL ;
    PORT
      LAYER M3 ;
        RECT  80.748 105.779 80.766 105.816 ;
    END
  END b[267]
  PIN b[268]
    DIRECTION OUTPUT ;
    USE SIGNAL ;
    PORT
      LAYER M3 ;
        RECT  80.82 105.779 80.838 105.816 ;
    END
  END b[268]
  PIN b[269]
    DIRECTION OUTPUT ;
    USE SIGNAL ;
    PORT
      LAYER M3 ;
        RECT  80.892 105.779 80.91 105.816 ;
    END
  END b[269]
  PIN b[26]
    DIRECTION OUTPUT ;
    USE SIGNAL ;
    PORT
      LAYER M3 ;
        RECT  38.628 105.779 38.646 105.816 ;
    END
  END b[26]
  PIN b[270]
    DIRECTION OUTPUT ;
    USE SIGNAL ;
    PORT
      LAYER M3 ;
        RECT  80.964 105.779 80.982 105.816 ;
    END
  END b[270]
  PIN b[271]
    DIRECTION OUTPUT ;
    USE SIGNAL ;
    PORT
      LAYER M3 ;
        RECT  81.036 105.779 81.054 105.816 ;
    END
  END b[271]
  PIN b[272]
    DIRECTION OUTPUT ;
    USE SIGNAL ;
    PORT
      LAYER M3 ;
        RECT  81.108 105.779 81.126 105.816 ;
    END
  END b[272]
  PIN b[273]
    DIRECTION OUTPUT ;
    USE SIGNAL ;
    PORT
      LAYER M3 ;
        RECT  81.18 105.779 81.198 105.816 ;
    END
  END b[273]
  PIN b[274]
    DIRECTION OUTPUT ;
    USE SIGNAL ;
    PORT
      LAYER M3 ;
        RECT  81.252 105.779 81.27 105.816 ;
    END
  END b[274]
  PIN b[275]
    DIRECTION OUTPUT ;
    USE SIGNAL ;
    PORT
      LAYER M3 ;
        RECT  81.324 105.779 81.342 105.816 ;
    END
  END b[275]
  PIN b[276]
    DIRECTION OUTPUT ;
    USE SIGNAL ;
    PORT
      LAYER M3 ;
        RECT  81.396 105.779 81.414 105.816 ;
    END
  END b[276]
  PIN b[277]
    DIRECTION OUTPUT ;
    USE SIGNAL ;
    PORT
      LAYER M3 ;
        RECT  81.468 105.779 81.486 105.816 ;
    END
  END b[277]
  PIN b[278]
    DIRECTION OUTPUT ;
    USE SIGNAL ;
    PORT
      LAYER M3 ;
        RECT  81.54 105.779 81.558 105.816 ;
    END
  END b[278]
  PIN b[279]
    DIRECTION OUTPUT ;
    USE SIGNAL ;
    PORT
      LAYER M3 ;
        RECT  81.612 105.779 81.63 105.816 ;
    END
  END b[279]
  PIN b[27]
    DIRECTION OUTPUT ;
    USE SIGNAL ;
    PORT
      LAYER M3 ;
        RECT  38.7 105.779 38.718 105.816 ;
    END
  END b[27]
  PIN b[280]
    DIRECTION OUTPUT ;
    USE SIGNAL ;
    PORT
      LAYER M3 ;
        RECT  81.684 105.779 81.702 105.816 ;
    END
  END b[280]
  PIN b[281]
    DIRECTION OUTPUT ;
    USE SIGNAL ;
    PORT
      LAYER M3 ;
        RECT  81.756 105.779 81.774 105.816 ;
    END
  END b[281]
  PIN b[282]
    DIRECTION OUTPUT ;
    USE SIGNAL ;
    PORT
      LAYER M3 ;
        RECT  81.828 105.779 81.846 105.816 ;
    END
  END b[282]
  PIN b[283]
    DIRECTION OUTPUT ;
    USE SIGNAL ;
    PORT
      LAYER M3 ;
        RECT  81.9 105.779 81.918 105.816 ;
    END
  END b[283]
  PIN b[284]
    DIRECTION OUTPUT ;
    USE SIGNAL ;
    PORT
      LAYER M3 ;
        RECT  81.972 105.779 81.99 105.816 ;
    END
  END b[284]
  PIN b[285]
    DIRECTION OUTPUT ;
    USE SIGNAL ;
    PORT
      LAYER M3 ;
        RECT  82.044 105.779 82.062 105.816 ;
    END
  END b[285]
  PIN b[286]
    DIRECTION OUTPUT ;
    USE SIGNAL ;
    PORT
      LAYER M3 ;
        RECT  82.116 105.779 82.134 105.816 ;
    END
  END b[286]
  PIN b[287]
    DIRECTION OUTPUT ;
    USE SIGNAL ;
    PORT
      LAYER M3 ;
        RECT  82.188 105.779 82.206 105.816 ;
    END
  END b[287]
  PIN b[288]
    DIRECTION OUTPUT ;
    USE SIGNAL ;
    PORT
      LAYER M5 ;
        RECT  68.88 105.732 68.904 105.816 ;
    END
  END b[288]
  PIN b[289]
    DIRECTION OUTPUT ;
    USE SIGNAL ;
    PORT
      LAYER M5 ;
        RECT  68.976 105.732 69 105.816 ;
    END
  END b[289]
  PIN b[28]
    DIRECTION OUTPUT ;
    USE SIGNAL ;
    PORT
      LAYER M3 ;
        RECT  38.772 105.779 38.79 105.816 ;
    END
  END b[28]
  PIN b[290]
    DIRECTION OUTPUT ;
    USE SIGNAL ;
    PORT
      LAYER M5 ;
        RECT  69.072 105.732 69.096 105.816 ;
    END
  END b[290]
  PIN b[291]
    DIRECTION OUTPUT ;
    USE SIGNAL ;
    PORT
      LAYER M5 ;
        RECT  69.168 105.732 69.192 105.816 ;
    END
  END b[291]
  PIN b[292]
    DIRECTION OUTPUT ;
    USE SIGNAL ;
    PORT
      LAYER M5 ;
        RECT  69.264 105.732 69.288 105.816 ;
    END
  END b[292]
  PIN b[293]
    DIRECTION OUTPUT ;
    USE SIGNAL ;
    PORT
      LAYER M5 ;
        RECT  69.36 105.732 69.384 105.816 ;
    END
  END b[293]
  PIN b[294]
    DIRECTION OUTPUT ;
    USE SIGNAL ;
    PORT
      LAYER M5 ;
        RECT  69.456 105.732 69.48 105.816 ;
    END
  END b[294]
  PIN b[295]
    DIRECTION OUTPUT ;
    USE SIGNAL ;
    PORT
      LAYER M5 ;
        RECT  69.552 105.732 69.576 105.816 ;
    END
  END b[295]
  PIN b[296]
    DIRECTION OUTPUT ;
    USE SIGNAL ;
    PORT
      LAYER M5 ;
        RECT  69.648 105.732 69.672 105.816 ;
    END
  END b[296]
  PIN b[297]
    DIRECTION OUTPUT ;
    USE SIGNAL ;
    PORT
      LAYER M5 ;
        RECT  69.744 105.732 69.768 105.816 ;
    END
  END b[297]
  PIN b[298]
    DIRECTION OUTPUT ;
    USE SIGNAL ;
    PORT
      LAYER M5 ;
        RECT  69.84 105.732 69.864 105.816 ;
    END
  END b[298]
  PIN b[299]
    DIRECTION OUTPUT ;
    USE SIGNAL ;
    PORT
      LAYER M5 ;
        RECT  69.936 105.732 69.96 105.816 ;
    END
  END b[299]
  PIN b[29]
    DIRECTION OUTPUT ;
    USE SIGNAL ;
    PORT
      LAYER M3 ;
        RECT  38.844 105.779 38.862 105.816 ;
    END
  END b[29]
  PIN b[2]
    DIRECTION OUTPUT ;
    USE SIGNAL ;
    PORT
      LAYER M3 ;
        RECT  36.9 105.779 36.918 105.816 ;
    END
  END b[2]
  PIN b[300]
    DIRECTION OUTPUT ;
    USE SIGNAL ;
    PORT
      LAYER M5 ;
        RECT  70.032 105.732 70.056 105.816 ;
    END
  END b[300]
  PIN b[301]
    DIRECTION OUTPUT ;
    USE SIGNAL ;
    PORT
      LAYER M5 ;
        RECT  70.128 105.732 70.152 105.816 ;
    END
  END b[301]
  PIN b[302]
    DIRECTION OUTPUT ;
    USE SIGNAL ;
    PORT
      LAYER M5 ;
        RECT  70.224 105.732 70.248 105.816 ;
    END
  END b[302]
  PIN b[303]
    DIRECTION OUTPUT ;
    USE SIGNAL ;
    PORT
      LAYER M5 ;
        RECT  70.32 105.732 70.344 105.816 ;
    END
  END b[303]
  PIN b[304]
    DIRECTION OUTPUT ;
    USE SIGNAL ;
    PORT
      LAYER M5 ;
        RECT  70.416 105.732 70.44 105.816 ;
    END
  END b[304]
  PIN b[305]
    DIRECTION OUTPUT ;
    USE SIGNAL ;
    PORT
      LAYER M5 ;
        RECT  70.512 105.732 70.536 105.816 ;
    END
  END b[305]
  PIN b[306]
    DIRECTION OUTPUT ;
    USE SIGNAL ;
    PORT
      LAYER M5 ;
        RECT  70.608 105.732 70.632 105.816 ;
    END
  END b[306]
  PIN b[307]
    DIRECTION OUTPUT ;
    USE SIGNAL ;
    PORT
      LAYER M5 ;
        RECT  70.704 105.732 70.728 105.816 ;
    END
  END b[307]
  PIN b[308]
    DIRECTION OUTPUT ;
    USE SIGNAL ;
    PORT
      LAYER M5 ;
        RECT  70.8 105.732 70.824 105.816 ;
    END
  END b[308]
  PIN b[309]
    DIRECTION OUTPUT ;
    USE SIGNAL ;
    PORT
      LAYER M5 ;
        RECT  70.896 105.732 70.92 105.816 ;
    END
  END b[309]
  PIN b[30]
    DIRECTION OUTPUT ;
    USE SIGNAL ;
    PORT
      LAYER M3 ;
        RECT  38.916 105.779 38.934 105.816 ;
    END
  END b[30]
  PIN b[310]
    DIRECTION OUTPUT ;
    USE SIGNAL ;
    PORT
      LAYER M5 ;
        RECT  70.992 105.732 71.016 105.816 ;
    END
  END b[310]
  PIN b[311]
    DIRECTION OUTPUT ;
    USE SIGNAL ;
    PORT
      LAYER M5 ;
        RECT  71.088 105.732 71.112 105.816 ;
    END
  END b[311]
  PIN b[312]
    DIRECTION OUTPUT ;
    USE SIGNAL ;
    PORT
      LAYER M5 ;
        RECT  71.184 105.732 71.208 105.816 ;
    END
  END b[312]
  PIN b[313]
    DIRECTION OUTPUT ;
    USE SIGNAL ;
    PORT
      LAYER M5 ;
        RECT  71.28 105.732 71.304 105.816 ;
    END
  END b[313]
  PIN b[314]
    DIRECTION OUTPUT ;
    USE SIGNAL ;
    PORT
      LAYER M5 ;
        RECT  71.376 105.732 71.4 105.816 ;
    END
  END b[314]
  PIN b[315]
    DIRECTION OUTPUT ;
    USE SIGNAL ;
    PORT
      LAYER M5 ;
        RECT  71.472 105.732 71.496 105.816 ;
    END
  END b[315]
  PIN b[316]
    DIRECTION OUTPUT ;
    USE SIGNAL ;
    PORT
      LAYER M5 ;
        RECT  71.568 105.732 71.592 105.816 ;
    END
  END b[316]
  PIN b[317]
    DIRECTION OUTPUT ;
    USE SIGNAL ;
    PORT
      LAYER M5 ;
        RECT  71.664 105.732 71.688 105.816 ;
    END
  END b[317]
  PIN b[318]
    DIRECTION OUTPUT ;
    USE SIGNAL ;
    PORT
      LAYER M5 ;
        RECT  71.76 105.732 71.784 105.816 ;
    END
  END b[318]
  PIN b[319]
    DIRECTION OUTPUT ;
    USE SIGNAL ;
    PORT
      LAYER M5 ;
        RECT  71.856 105.732 71.88 105.816 ;
    END
  END b[319]
  PIN b[31]
    DIRECTION OUTPUT ;
    USE SIGNAL ;
    PORT
      LAYER M3 ;
        RECT  38.988 105.779 39.006 105.816 ;
    END
  END b[31]
  PIN b[320]
    DIRECTION OUTPUT ;
    USE SIGNAL ;
    PORT
      LAYER M5 ;
        RECT  52.752 105.732 52.776 105.816 ;
    END
  END b[320]
  PIN b[321]
    DIRECTION OUTPUT ;
    USE SIGNAL ;
    PORT
      LAYER M5 ;
        RECT  52.848 105.732 52.872 105.816 ;
    END
  END b[321]
  PIN b[322]
    DIRECTION OUTPUT ;
    USE SIGNAL ;
    PORT
      LAYER M5 ;
        RECT  52.944 105.732 52.968 105.816 ;
    END
  END b[322]
  PIN b[323]
    DIRECTION OUTPUT ;
    USE SIGNAL ;
    PORT
      LAYER M5 ;
        RECT  53.04 105.732 53.064 105.816 ;
    END
  END b[323]
  PIN b[324]
    DIRECTION OUTPUT ;
    USE SIGNAL ;
    PORT
      LAYER M5 ;
        RECT  53.136 105.732 53.16 105.816 ;
    END
  END b[324]
  PIN b[325]
    DIRECTION OUTPUT ;
    USE SIGNAL ;
    PORT
      LAYER M5 ;
        RECT  53.232 105.732 53.256 105.816 ;
    END
  END b[325]
  PIN b[326]
    DIRECTION OUTPUT ;
    USE SIGNAL ;
    PORT
      LAYER M5 ;
        RECT  53.328 105.732 53.352 105.816 ;
    END
  END b[326]
  PIN b[327]
    DIRECTION OUTPUT ;
    USE SIGNAL ;
    PORT
      LAYER M5 ;
        RECT  53.424 105.732 53.448 105.816 ;
    END
  END b[327]
  PIN b[328]
    DIRECTION OUTPUT ;
    USE SIGNAL ;
    PORT
      LAYER M5 ;
        RECT  53.52 105.732 53.544 105.816 ;
    END
  END b[328]
  PIN b[329]
    DIRECTION OUTPUT ;
    USE SIGNAL ;
    PORT
      LAYER M5 ;
        RECT  53.616 105.732 53.64 105.816 ;
    END
  END b[329]
  PIN b[32]
    DIRECTION OUTPUT ;
    USE SIGNAL ;
    PORT
      LAYER M3 ;
        RECT  41.364 105.779 41.382 105.816 ;
    END
  END b[32]
  PIN b[330]
    DIRECTION OUTPUT ;
    USE SIGNAL ;
    PORT
      LAYER M5 ;
        RECT  53.712 105.732 53.736 105.816 ;
    END
  END b[330]
  PIN b[331]
    DIRECTION OUTPUT ;
    USE SIGNAL ;
    PORT
      LAYER M5 ;
        RECT  53.808 105.732 53.832 105.816 ;
    END
  END b[331]
  PIN b[332]
    DIRECTION OUTPUT ;
    USE SIGNAL ;
    PORT
      LAYER M5 ;
        RECT  53.904 105.732 53.928 105.816 ;
    END
  END b[332]
  PIN b[333]
    DIRECTION OUTPUT ;
    USE SIGNAL ;
    PORT
      LAYER M5 ;
        RECT  54 105.732 54.024 105.816 ;
    END
  END b[333]
  PIN b[334]
    DIRECTION OUTPUT ;
    USE SIGNAL ;
    PORT
      LAYER M5 ;
        RECT  54.096 105.732 54.12 105.816 ;
    END
  END b[334]
  PIN b[335]
    DIRECTION OUTPUT ;
    USE SIGNAL ;
    PORT
      LAYER M5 ;
        RECT  54.192 105.732 54.216 105.816 ;
    END
  END b[335]
  PIN b[336]
    DIRECTION OUTPUT ;
    USE SIGNAL ;
    PORT
      LAYER M5 ;
        RECT  54.288 105.732 54.312 105.816 ;
    END
  END b[336]
  PIN b[337]
    DIRECTION OUTPUT ;
    USE SIGNAL ;
    PORT
      LAYER M5 ;
        RECT  54.384 105.732 54.408 105.816 ;
    END
  END b[337]
  PIN b[338]
    DIRECTION OUTPUT ;
    USE SIGNAL ;
    PORT
      LAYER M5 ;
        RECT  54.48 105.732 54.504 105.816 ;
    END
  END b[338]
  PIN b[339]
    DIRECTION OUTPUT ;
    USE SIGNAL ;
    PORT
      LAYER M5 ;
        RECT  54.576 105.732 54.6 105.816 ;
    END
  END b[339]
  PIN b[33]
    DIRECTION OUTPUT ;
    USE SIGNAL ;
    PORT
      LAYER M3 ;
        RECT  41.436 105.779 41.454 105.816 ;
    END
  END b[33]
  PIN b[340]
    DIRECTION OUTPUT ;
    USE SIGNAL ;
    PORT
      LAYER M5 ;
        RECT  54.672 105.732 54.696 105.816 ;
    END
  END b[340]
  PIN b[341]
    DIRECTION OUTPUT ;
    USE SIGNAL ;
    PORT
      LAYER M5 ;
        RECT  54.768 105.732 54.792 105.816 ;
    END
  END b[341]
  PIN b[342]
    DIRECTION OUTPUT ;
    USE SIGNAL ;
    PORT
      LAYER M5 ;
        RECT  54.864 105.732 54.888 105.816 ;
    END
  END b[342]
  PIN b[343]
    DIRECTION OUTPUT ;
    USE SIGNAL ;
    PORT
      LAYER M5 ;
        RECT  54.96 105.732 54.984 105.816 ;
    END
  END b[343]
  PIN b[344]
    DIRECTION OUTPUT ;
    USE SIGNAL ;
    PORT
      LAYER M5 ;
        RECT  55.056 105.732 55.08 105.816 ;
    END
  END b[344]
  PIN b[345]
    DIRECTION OUTPUT ;
    USE SIGNAL ;
    PORT
      LAYER M5 ;
        RECT  55.152 105.732 55.176 105.816 ;
    END
  END b[345]
  PIN b[346]
    DIRECTION OUTPUT ;
    USE SIGNAL ;
    PORT
      LAYER M5 ;
        RECT  55.248 105.732 55.272 105.816 ;
    END
  END b[346]
  PIN b[347]
    DIRECTION OUTPUT ;
    USE SIGNAL ;
    PORT
      LAYER M5 ;
        RECT  55.344 105.732 55.368 105.816 ;
    END
  END b[347]
  PIN b[348]
    DIRECTION OUTPUT ;
    USE SIGNAL ;
    PORT
      LAYER M5 ;
        RECT  55.44 105.732 55.464 105.816 ;
    END
  END b[348]
  PIN b[349]
    DIRECTION OUTPUT ;
    USE SIGNAL ;
    PORT
      LAYER M5 ;
        RECT  55.536 105.732 55.56 105.816 ;
    END
  END b[349]
  PIN b[34]
    DIRECTION OUTPUT ;
    USE SIGNAL ;
    PORT
      LAYER M3 ;
        RECT  41.508 105.779 41.526 105.816 ;
    END
  END b[34]
  PIN b[350]
    DIRECTION OUTPUT ;
    USE SIGNAL ;
    PORT
      LAYER M5 ;
        RECT  55.632 105.732 55.656 105.816 ;
    END
  END b[350]
  PIN b[351]
    DIRECTION OUTPUT ;
    USE SIGNAL ;
    PORT
      LAYER M5 ;
        RECT  55.728 105.732 55.752 105.816 ;
    END
  END b[351]
  PIN b[352]
    DIRECTION OUTPUT ;
    USE SIGNAL ;
    PORT
      LAYER M5 ;
        RECT  55.824 105.732 55.848 105.816 ;
    END
  END b[352]
  PIN b[353]
    DIRECTION OUTPUT ;
    USE SIGNAL ;
    PORT
      LAYER M5 ;
        RECT  55.92 105.732 55.944 105.816 ;
    END
  END b[353]
  PIN b[354]
    DIRECTION OUTPUT ;
    USE SIGNAL ;
    PORT
      LAYER M5 ;
        RECT  56.016 105.732 56.04 105.816 ;
    END
  END b[354]
  PIN b[355]
    DIRECTION OUTPUT ;
    USE SIGNAL ;
    PORT
      LAYER M5 ;
        RECT  56.112 105.732 56.136 105.816 ;
    END
  END b[355]
  PIN b[356]
    DIRECTION OUTPUT ;
    USE SIGNAL ;
    PORT
      LAYER M5 ;
        RECT  56.208 105.732 56.232 105.816 ;
    END
  END b[356]
  PIN b[357]
    DIRECTION OUTPUT ;
    USE SIGNAL ;
    PORT
      LAYER M5 ;
        RECT  56.304 105.732 56.328 105.816 ;
    END
  END b[357]
  PIN b[358]
    DIRECTION OUTPUT ;
    USE SIGNAL ;
    PORT
      LAYER M5 ;
        RECT  56.4 105.732 56.424 105.816 ;
    END
  END b[358]
  PIN b[359]
    DIRECTION OUTPUT ;
    USE SIGNAL ;
    PORT
      LAYER M5 ;
        RECT  56.496 105.732 56.52 105.816 ;
    END
  END b[359]
  PIN b[35]
    DIRECTION OUTPUT ;
    USE SIGNAL ;
    PORT
      LAYER M3 ;
        RECT  41.58 105.779 41.598 105.816 ;
    END
  END b[35]
  PIN b[360]
    DIRECTION OUTPUT ;
    USE SIGNAL ;
    PORT
      LAYER M5 ;
        RECT  56.592 105.732 56.616 105.816 ;
    END
  END b[360]
  PIN b[361]
    DIRECTION OUTPUT ;
    USE SIGNAL ;
    PORT
      LAYER M5 ;
        RECT  56.688 105.732 56.712 105.816 ;
    END
  END b[361]
  PIN b[362]
    DIRECTION OUTPUT ;
    USE SIGNAL ;
    PORT
      LAYER M5 ;
        RECT  56.784 105.732 56.808 105.816 ;
    END
  END b[362]
  PIN b[363]
    DIRECTION OUTPUT ;
    USE SIGNAL ;
    PORT
      LAYER M5 ;
        RECT  56.88 105.732 56.904 105.816 ;
    END
  END b[363]
  PIN b[364]
    DIRECTION OUTPUT ;
    USE SIGNAL ;
    PORT
      LAYER M5 ;
        RECT  56.976 105.732 57 105.816 ;
    END
  END b[364]
  PIN b[365]
    DIRECTION OUTPUT ;
    USE SIGNAL ;
    PORT
      LAYER M5 ;
        RECT  57.072 105.732 57.096 105.816 ;
    END
  END b[365]
  PIN b[366]
    DIRECTION OUTPUT ;
    USE SIGNAL ;
    PORT
      LAYER M5 ;
        RECT  57.168 105.732 57.192 105.816 ;
    END
  END b[366]
  PIN b[367]
    DIRECTION OUTPUT ;
    USE SIGNAL ;
    PORT
      LAYER M5 ;
        RECT  57.264 105.732 57.288 105.816 ;
    END
  END b[367]
  PIN b[368]
    DIRECTION OUTPUT ;
    USE SIGNAL ;
    PORT
      LAYER M5 ;
        RECT  57.36 105.732 57.384 105.816 ;
    END
  END b[368]
  PIN b[369]
    DIRECTION OUTPUT ;
    USE SIGNAL ;
    PORT
      LAYER M5 ;
        RECT  57.456 105.732 57.48 105.816 ;
    END
  END b[369]
  PIN b[36]
    DIRECTION OUTPUT ;
    USE SIGNAL ;
    PORT
      LAYER M3 ;
        RECT  41.652 105.779 41.67 105.816 ;
    END
  END b[36]
  PIN b[370]
    DIRECTION OUTPUT ;
    USE SIGNAL ;
    PORT
      LAYER M5 ;
        RECT  57.552 105.732 57.576 105.816 ;
    END
  END b[370]
  PIN b[371]
    DIRECTION OUTPUT ;
    USE SIGNAL ;
    PORT
      LAYER M5 ;
        RECT  57.648 105.732 57.672 105.816 ;
    END
  END b[371]
  PIN b[372]
    DIRECTION OUTPUT ;
    USE SIGNAL ;
    PORT
      LAYER M5 ;
        RECT  57.744 105.732 57.768 105.816 ;
    END
  END b[372]
  PIN b[373]
    DIRECTION OUTPUT ;
    USE SIGNAL ;
    PORT
      LAYER M5 ;
        RECT  57.84 105.732 57.864 105.816 ;
    END
  END b[373]
  PIN b[374]
    DIRECTION OUTPUT ;
    USE SIGNAL ;
    PORT
      LAYER M5 ;
        RECT  57.936 105.732 57.96 105.816 ;
    END
  END b[374]
  PIN b[375]
    DIRECTION OUTPUT ;
    USE SIGNAL ;
    PORT
      LAYER M5 ;
        RECT  58.032 105.732 58.056 105.816 ;
    END
  END b[375]
  PIN b[376]
    DIRECTION OUTPUT ;
    USE SIGNAL ;
    PORT
      LAYER M5 ;
        RECT  58.128 105.732 58.152 105.816 ;
    END
  END b[376]
  PIN b[377]
    DIRECTION OUTPUT ;
    USE SIGNAL ;
    PORT
      LAYER M5 ;
        RECT  58.224 105.732 58.248 105.816 ;
    END
  END b[377]
  PIN b[378]
    DIRECTION OUTPUT ;
    USE SIGNAL ;
    PORT
      LAYER M5 ;
        RECT  58.32 105.732 58.344 105.816 ;
    END
  END b[378]
  PIN b[379]
    DIRECTION OUTPUT ;
    USE SIGNAL ;
    PORT
      LAYER M5 ;
        RECT  58.416 105.732 58.44 105.816 ;
    END
  END b[379]
  PIN b[37]
    DIRECTION OUTPUT ;
    USE SIGNAL ;
    PORT
      LAYER M3 ;
        RECT  41.724 105.779 41.742 105.816 ;
    END
  END b[37]
  PIN b[380]
    DIRECTION OUTPUT ;
    USE SIGNAL ;
    PORT
      LAYER M5 ;
        RECT  58.512 105.732 58.536 105.816 ;
    END
  END b[380]
  PIN b[381]
    DIRECTION OUTPUT ;
    USE SIGNAL ;
    PORT
      LAYER M5 ;
        RECT  58.608 105.732 58.632 105.816 ;
    END
  END b[381]
  PIN b[382]
    DIRECTION OUTPUT ;
    USE SIGNAL ;
    PORT
      LAYER M5 ;
        RECT  58.704 105.732 58.728 105.816 ;
    END
  END b[382]
  PIN b[383]
    DIRECTION OUTPUT ;
    USE SIGNAL ;
    PORT
      LAYER M5 ;
        RECT  58.8 105.732 58.824 105.816 ;
    END
  END b[383]
  PIN b[384]
    DIRECTION OUTPUT ;
    USE SIGNAL ;
    PORT
      LAYER M5 ;
        RECT  58.896 105.732 58.92 105.816 ;
    END
  END b[384]
  PIN b[385]
    DIRECTION OUTPUT ;
    USE SIGNAL ;
    PORT
      LAYER M5 ;
        RECT  58.992 105.732 59.016 105.816 ;
    END
  END b[385]
  PIN b[386]
    DIRECTION OUTPUT ;
    USE SIGNAL ;
    PORT
      LAYER M5 ;
        RECT  59.088 105.732 59.112 105.816 ;
    END
  END b[386]
  PIN b[387]
    DIRECTION OUTPUT ;
    USE SIGNAL ;
    PORT
      LAYER M5 ;
        RECT  59.184 105.732 59.208 105.816 ;
    END
  END b[387]
  PIN b[388]
    DIRECTION OUTPUT ;
    USE SIGNAL ;
    PORT
      LAYER M5 ;
        RECT  59.28 105.732 59.304 105.816 ;
    END
  END b[388]
  PIN b[389]
    DIRECTION OUTPUT ;
    USE SIGNAL ;
    PORT
      LAYER M5 ;
        RECT  59.376 105.732 59.4 105.816 ;
    END
  END b[389]
  PIN b[38]
    DIRECTION OUTPUT ;
    USE SIGNAL ;
    PORT
      LAYER M3 ;
        RECT  41.796 105.779 41.814 105.816 ;
    END
  END b[38]
  PIN b[390]
    DIRECTION OUTPUT ;
    USE SIGNAL ;
    PORT
      LAYER M5 ;
        RECT  59.472 105.732 59.496 105.816 ;
    END
  END b[390]
  PIN b[391]
    DIRECTION OUTPUT ;
    USE SIGNAL ;
    PORT
      LAYER M5 ;
        RECT  59.568 105.732 59.592 105.816 ;
    END
  END b[391]
  PIN b[392]
    DIRECTION OUTPUT ;
    USE SIGNAL ;
    PORT
      LAYER M5 ;
        RECT  59.664 105.732 59.688 105.816 ;
    END
  END b[392]
  PIN b[393]
    DIRECTION OUTPUT ;
    USE SIGNAL ;
    PORT
      LAYER M5 ;
        RECT  59.76 105.732 59.784 105.816 ;
    END
  END b[393]
  PIN b[394]
    DIRECTION OUTPUT ;
    USE SIGNAL ;
    PORT
      LAYER M5 ;
        RECT  59.856 105.732 59.88 105.816 ;
    END
  END b[394]
  PIN b[395]
    DIRECTION OUTPUT ;
    USE SIGNAL ;
    PORT
      LAYER M5 ;
        RECT  59.952 105.732 59.976 105.816 ;
    END
  END b[395]
  PIN b[396]
    DIRECTION OUTPUT ;
    USE SIGNAL ;
    PORT
      LAYER M5 ;
        RECT  60.048 105.732 60.072 105.816 ;
    END
  END b[396]
  PIN b[397]
    DIRECTION OUTPUT ;
    USE SIGNAL ;
    PORT
      LAYER M5 ;
        RECT  60.144 105.732 60.168 105.816 ;
    END
  END b[397]
  PIN b[398]
    DIRECTION OUTPUT ;
    USE SIGNAL ;
    PORT
      LAYER M5 ;
        RECT  60.24 105.732 60.264 105.816 ;
    END
  END b[398]
  PIN b[399]
    DIRECTION OUTPUT ;
    USE SIGNAL ;
    PORT
      LAYER M5 ;
        RECT  60.336 105.732 60.36 105.816 ;
    END
  END b[399]
  PIN b[39]
    DIRECTION OUTPUT ;
    USE SIGNAL ;
    PORT
      LAYER M3 ;
        RECT  41.868 105.779 41.886 105.816 ;
    END
  END b[39]
  PIN b[3]
    DIRECTION OUTPUT ;
    USE SIGNAL ;
    PORT
      LAYER M3 ;
        RECT  36.972 105.779 36.99 105.816 ;
    END
  END b[3]
  PIN b[400]
    DIRECTION OUTPUT ;
    USE SIGNAL ;
    PORT
      LAYER M5 ;
        RECT  60.432 105.732 60.456 105.816 ;
    END
  END b[400]
  PIN b[401]
    DIRECTION OUTPUT ;
    USE SIGNAL ;
    PORT
      LAYER M5 ;
        RECT  60.528 105.732 60.552 105.816 ;
    END
  END b[401]
  PIN b[402]
    DIRECTION OUTPUT ;
    USE SIGNAL ;
    PORT
      LAYER M5 ;
        RECT  60.624 105.732 60.648 105.816 ;
    END
  END b[402]
  PIN b[403]
    DIRECTION OUTPUT ;
    USE SIGNAL ;
    PORT
      LAYER M5 ;
        RECT  60.72 105.732 60.744 105.816 ;
    END
  END b[403]
  PIN b[404]
    DIRECTION OUTPUT ;
    USE SIGNAL ;
    PORT
      LAYER M5 ;
        RECT  60.816 105.732 60.84 105.816 ;
    END
  END b[404]
  PIN b[405]
    DIRECTION OUTPUT ;
    USE SIGNAL ;
    PORT
      LAYER M5 ;
        RECT  60.912 105.732 60.936 105.816 ;
    END
  END b[405]
  PIN b[406]
    DIRECTION OUTPUT ;
    USE SIGNAL ;
    PORT
      LAYER M5 ;
        RECT  61.008 105.732 61.032 105.816 ;
    END
  END b[406]
  PIN b[407]
    DIRECTION OUTPUT ;
    USE SIGNAL ;
    PORT
      LAYER M5 ;
        RECT  61.104 105.732 61.128 105.816 ;
    END
  END b[407]
  PIN b[408]
    DIRECTION OUTPUT ;
    USE SIGNAL ;
    PORT
      LAYER M5 ;
        RECT  61.2 105.732 61.224 105.816 ;
    END
  END b[408]
  PIN b[409]
    DIRECTION OUTPUT ;
    USE SIGNAL ;
    PORT
      LAYER M5 ;
        RECT  61.296 105.732 61.32 105.816 ;
    END
  END b[409]
  PIN b[40]
    DIRECTION OUTPUT ;
    USE SIGNAL ;
    PORT
      LAYER M3 ;
        RECT  41.94 105.779 41.958 105.816 ;
    END
  END b[40]
  PIN b[410]
    DIRECTION OUTPUT ;
    USE SIGNAL ;
    PORT
      LAYER M5 ;
        RECT  61.392 105.732 61.416 105.816 ;
    END
  END b[410]
  PIN b[411]
    DIRECTION OUTPUT ;
    USE SIGNAL ;
    PORT
      LAYER M5 ;
        RECT  61.488 105.732 61.512 105.816 ;
    END
  END b[411]
  PIN b[412]
    DIRECTION OUTPUT ;
    USE SIGNAL ;
    PORT
      LAYER M5 ;
        RECT  61.584 105.732 61.608 105.816 ;
    END
  END b[412]
  PIN b[413]
    DIRECTION OUTPUT ;
    USE SIGNAL ;
    PORT
      LAYER M5 ;
        RECT  61.68 105.732 61.704 105.816 ;
    END
  END b[413]
  PIN b[414]
    DIRECTION OUTPUT ;
    USE SIGNAL ;
    PORT
      LAYER M5 ;
        RECT  61.776 105.732 61.8 105.816 ;
    END
  END b[414]
  PIN b[415]
    DIRECTION OUTPUT ;
    USE SIGNAL ;
    PORT
      LAYER M5 ;
        RECT  61.872 105.732 61.896 105.816 ;
    END
  END b[415]
  PIN b[416]
    DIRECTION OUTPUT ;
    USE SIGNAL ;
    PORT
      LAYER M3 ;
        RECT  46.548 105.779 46.566 105.816 ;
    END
  END b[416]
  PIN b[417]
    DIRECTION OUTPUT ;
    USE SIGNAL ;
    PORT
      LAYER M3 ;
        RECT  46.62 105.779 46.638 105.816 ;
    END
  END b[417]
  PIN b[418]
    DIRECTION OUTPUT ;
    USE SIGNAL ;
    PORT
      LAYER M3 ;
        RECT  46.692 105.779 46.71 105.816 ;
    END
  END b[418]
  PIN b[419]
    DIRECTION OUTPUT ;
    USE SIGNAL ;
    PORT
      LAYER M3 ;
        RECT  46.764 105.779 46.782 105.816 ;
    END
  END b[419]
  PIN b[41]
    DIRECTION OUTPUT ;
    USE SIGNAL ;
    PORT
      LAYER M3 ;
        RECT  42.012 105.779 42.03 105.816 ;
    END
  END b[41]
  PIN b[420]
    DIRECTION OUTPUT ;
    USE SIGNAL ;
    PORT
      LAYER M3 ;
        RECT  46.836 105.779 46.854 105.816 ;
    END
  END b[420]
  PIN b[421]
    DIRECTION OUTPUT ;
    USE SIGNAL ;
    PORT
      LAYER M3 ;
        RECT  46.908 105.779 46.926 105.816 ;
    END
  END b[421]
  PIN b[422]
    DIRECTION OUTPUT ;
    USE SIGNAL ;
    PORT
      LAYER M3 ;
        RECT  46.98 105.779 46.998 105.816 ;
    END
  END b[422]
  PIN b[423]
    DIRECTION OUTPUT ;
    USE SIGNAL ;
    PORT
      LAYER M3 ;
        RECT  47.052 105.779 47.07 105.816 ;
    END
  END b[423]
  PIN b[424]
    DIRECTION OUTPUT ;
    USE SIGNAL ;
    PORT
      LAYER M3 ;
        RECT  47.124 105.779 47.142 105.816 ;
    END
  END b[424]
  PIN b[425]
    DIRECTION OUTPUT ;
    USE SIGNAL ;
    PORT
      LAYER M3 ;
        RECT  47.196 105.779 47.214 105.816 ;
    END
  END b[425]
  PIN b[426]
    DIRECTION OUTPUT ;
    USE SIGNAL ;
    PORT
      LAYER M3 ;
        RECT  47.268 105.779 47.286 105.816 ;
    END
  END b[426]
  PIN b[427]
    DIRECTION OUTPUT ;
    USE SIGNAL ;
    PORT
      LAYER M3 ;
        RECT  47.34 105.779 47.358 105.816 ;
    END
  END b[427]
  PIN b[428]
    DIRECTION OUTPUT ;
    USE SIGNAL ;
    PORT
      LAYER M3 ;
        RECT  47.412 105.779 47.43 105.816 ;
    END
  END b[428]
  PIN b[429]
    DIRECTION OUTPUT ;
    USE SIGNAL ;
    PORT
      LAYER M3 ;
        RECT  47.484 105.779 47.502 105.816 ;
    END
  END b[429]
  PIN b[42]
    DIRECTION OUTPUT ;
    USE SIGNAL ;
    PORT
      LAYER M3 ;
        RECT  42.084 105.779 42.102 105.816 ;
    END
  END b[42]
  PIN b[430]
    DIRECTION OUTPUT ;
    USE SIGNAL ;
    PORT
      LAYER M3 ;
        RECT  47.556 105.779 47.574 105.816 ;
    END
  END b[430]
  PIN b[431]
    DIRECTION OUTPUT ;
    USE SIGNAL ;
    PORT
      LAYER M3 ;
        RECT  47.628 105.779 47.646 105.816 ;
    END
  END b[431]
  PIN b[432]
    DIRECTION OUTPUT ;
    USE SIGNAL ;
    PORT
      LAYER M3 ;
        RECT  47.7 105.779 47.718 105.816 ;
    END
  END b[432]
  PIN b[433]
    DIRECTION OUTPUT ;
    USE SIGNAL ;
    PORT
      LAYER M3 ;
        RECT  47.772 105.779 47.79 105.816 ;
    END
  END b[433]
  PIN b[434]
    DIRECTION OUTPUT ;
    USE SIGNAL ;
    PORT
      LAYER M3 ;
        RECT  47.844 105.779 47.862 105.816 ;
    END
  END b[434]
  PIN b[435]
    DIRECTION OUTPUT ;
    USE SIGNAL ;
    PORT
      LAYER M3 ;
        RECT  47.916 105.779 47.934 105.816 ;
    END
  END b[435]
  PIN b[436]
    DIRECTION OUTPUT ;
    USE SIGNAL ;
    PORT
      LAYER M3 ;
        RECT  47.988 105.779 48.006 105.816 ;
    END
  END b[436]
  PIN b[437]
    DIRECTION OUTPUT ;
    USE SIGNAL ;
    PORT
      LAYER M3 ;
        RECT  48.06 105.779 48.078 105.816 ;
    END
  END b[437]
  PIN b[438]
    DIRECTION OUTPUT ;
    USE SIGNAL ;
    PORT
      LAYER M3 ;
        RECT  48.132 105.779 48.15 105.816 ;
    END
  END b[438]
  PIN b[439]
    DIRECTION OUTPUT ;
    USE SIGNAL ;
    PORT
      LAYER M3 ;
        RECT  48.204 105.779 48.222 105.816 ;
    END
  END b[439]
  PIN b[43]
    DIRECTION OUTPUT ;
    USE SIGNAL ;
    PORT
      LAYER M3 ;
        RECT  42.156 105.779 42.174 105.816 ;
    END
  END b[43]
  PIN b[440]
    DIRECTION OUTPUT ;
    USE SIGNAL ;
    PORT
      LAYER M3 ;
        RECT  48.276 105.779 48.294 105.816 ;
    END
  END b[440]
  PIN b[441]
    DIRECTION OUTPUT ;
    USE SIGNAL ;
    PORT
      LAYER M3 ;
        RECT  48.348 105.779 48.366 105.816 ;
    END
  END b[441]
  PIN b[442]
    DIRECTION OUTPUT ;
    USE SIGNAL ;
    PORT
      LAYER M3 ;
        RECT  48.42 105.779 48.438 105.816 ;
    END
  END b[442]
  PIN b[443]
    DIRECTION OUTPUT ;
    USE SIGNAL ;
    PORT
      LAYER M3 ;
        RECT  48.492 105.779 48.51 105.816 ;
    END
  END b[443]
  PIN b[444]
    DIRECTION OUTPUT ;
    USE SIGNAL ;
    PORT
      LAYER M3 ;
        RECT  48.564 105.779 48.582 105.816 ;
    END
  END b[444]
  PIN b[445]
    DIRECTION OUTPUT ;
    USE SIGNAL ;
    PORT
      LAYER M3 ;
        RECT  48.636 105.779 48.654 105.816 ;
    END
  END b[445]
  PIN b[446]
    DIRECTION OUTPUT ;
    USE SIGNAL ;
    PORT
      LAYER M3 ;
        RECT  48.708 105.779 48.726 105.816 ;
    END
  END b[446]
  PIN b[447]
    DIRECTION OUTPUT ;
    USE SIGNAL ;
    PORT
      LAYER M3 ;
        RECT  48.78 105.779 48.798 105.816 ;
    END
  END b[447]
  PIN b[448]
    DIRECTION OUTPUT ;
    USE SIGNAL ;
    PORT
      LAYER M5 ;
        RECT  33.552 105.732 33.576 105.816 ;
    END
  END b[448]
  PIN b[449]
    DIRECTION OUTPUT ;
    USE SIGNAL ;
    PORT
      LAYER M5 ;
        RECT  33.648 105.732 33.672 105.816 ;
    END
  END b[449]
  PIN b[44]
    DIRECTION OUTPUT ;
    USE SIGNAL ;
    PORT
      LAYER M3 ;
        RECT  42.228 105.779 42.246 105.816 ;
    END
  END b[44]
  PIN b[450]
    DIRECTION OUTPUT ;
    USE SIGNAL ;
    PORT
      LAYER M5 ;
        RECT  33.744 105.732 33.768 105.816 ;
    END
  END b[450]
  PIN b[451]
    DIRECTION OUTPUT ;
    USE SIGNAL ;
    PORT
      LAYER M5 ;
        RECT  33.84 105.732 33.864 105.816 ;
    END
  END b[451]
  PIN b[452]
    DIRECTION OUTPUT ;
    USE SIGNAL ;
    PORT
      LAYER M5 ;
        RECT  33.936 105.732 33.96 105.816 ;
    END
  END b[452]
  PIN b[453]
    DIRECTION OUTPUT ;
    USE SIGNAL ;
    PORT
      LAYER M5 ;
        RECT  34.032 105.732 34.056 105.816 ;
    END
  END b[453]
  PIN b[454]
    DIRECTION OUTPUT ;
    USE SIGNAL ;
    PORT
      LAYER M5 ;
        RECT  34.128 105.732 34.152 105.816 ;
    END
  END b[454]
  PIN b[455]
    DIRECTION OUTPUT ;
    USE SIGNAL ;
    PORT
      LAYER M5 ;
        RECT  34.224 105.732 34.248 105.816 ;
    END
  END b[455]
  PIN b[456]
    DIRECTION OUTPUT ;
    USE SIGNAL ;
    PORT
      LAYER M5 ;
        RECT  34.32 105.732 34.344 105.816 ;
    END
  END b[456]
  PIN b[457]
    DIRECTION OUTPUT ;
    USE SIGNAL ;
    PORT
      LAYER M5 ;
        RECT  34.416 105.732 34.44 105.816 ;
    END
  END b[457]
  PIN b[458]
    DIRECTION OUTPUT ;
    USE SIGNAL ;
    PORT
      LAYER M5 ;
        RECT  34.512 105.732 34.536 105.816 ;
    END
  END b[458]
  PIN b[459]
    DIRECTION OUTPUT ;
    USE SIGNAL ;
    PORT
      LAYER M5 ;
        RECT  34.608 105.732 34.632 105.816 ;
    END
  END b[459]
  PIN b[45]
    DIRECTION OUTPUT ;
    USE SIGNAL ;
    PORT
      LAYER M3 ;
        RECT  42.3 105.779 42.318 105.816 ;
    END
  END b[45]
  PIN b[460]
    DIRECTION OUTPUT ;
    USE SIGNAL ;
    PORT
      LAYER M5 ;
        RECT  34.704 105.732 34.728 105.816 ;
    END
  END b[460]
  PIN b[461]
    DIRECTION OUTPUT ;
    USE SIGNAL ;
    PORT
      LAYER M5 ;
        RECT  34.8 105.732 34.824 105.816 ;
    END
  END b[461]
  PIN b[462]
    DIRECTION OUTPUT ;
    USE SIGNAL ;
    PORT
      LAYER M5 ;
        RECT  34.896 105.732 34.92 105.816 ;
    END
  END b[462]
  PIN b[463]
    DIRECTION OUTPUT ;
    USE SIGNAL ;
    PORT
      LAYER M5 ;
        RECT  34.992 105.732 35.016 105.816 ;
    END
  END b[463]
  PIN b[464]
    DIRECTION OUTPUT ;
    USE SIGNAL ;
    PORT
      LAYER M5 ;
        RECT  35.088 105.732 35.112 105.816 ;
    END
  END b[464]
  PIN b[465]
    DIRECTION OUTPUT ;
    USE SIGNAL ;
    PORT
      LAYER M5 ;
        RECT  35.184 105.732 35.208 105.816 ;
    END
  END b[465]
  PIN b[466]
    DIRECTION OUTPUT ;
    USE SIGNAL ;
    PORT
      LAYER M5 ;
        RECT  35.28 105.732 35.304 105.816 ;
    END
  END b[466]
  PIN b[467]
    DIRECTION OUTPUT ;
    USE SIGNAL ;
    PORT
      LAYER M5 ;
        RECT  35.376 105.732 35.4 105.816 ;
    END
  END b[467]
  PIN b[468]
    DIRECTION OUTPUT ;
    USE SIGNAL ;
    PORT
      LAYER M5 ;
        RECT  35.472 105.732 35.496 105.816 ;
    END
  END b[468]
  PIN b[469]
    DIRECTION OUTPUT ;
    USE SIGNAL ;
    PORT
      LAYER M5 ;
        RECT  35.568 105.732 35.592 105.816 ;
    END
  END b[469]
  PIN b[46]
    DIRECTION OUTPUT ;
    USE SIGNAL ;
    PORT
      LAYER M3 ;
        RECT  42.372 105.779 42.39 105.816 ;
    END
  END b[46]
  PIN b[470]
    DIRECTION OUTPUT ;
    USE SIGNAL ;
    PORT
      LAYER M5 ;
        RECT  35.664 105.732 35.688 105.816 ;
    END
  END b[470]
  PIN b[471]
    DIRECTION OUTPUT ;
    USE SIGNAL ;
    PORT
      LAYER M5 ;
        RECT  35.76 105.732 35.784 105.816 ;
    END
  END b[471]
  PIN b[472]
    DIRECTION OUTPUT ;
    USE SIGNAL ;
    PORT
      LAYER M5 ;
        RECT  35.856 105.732 35.88 105.816 ;
    END
  END b[472]
  PIN b[473]
    DIRECTION OUTPUT ;
    USE SIGNAL ;
    PORT
      LAYER M5 ;
        RECT  35.952 105.732 35.976 105.816 ;
    END
  END b[473]
  PIN b[474]
    DIRECTION OUTPUT ;
    USE SIGNAL ;
    PORT
      LAYER M5 ;
        RECT  36.048 105.732 36.072 105.816 ;
    END
  END b[474]
  PIN b[475]
    DIRECTION OUTPUT ;
    USE SIGNAL ;
    PORT
      LAYER M5 ;
        RECT  36.144 105.732 36.168 105.816 ;
    END
  END b[475]
  PIN b[476]
    DIRECTION OUTPUT ;
    USE SIGNAL ;
    PORT
      LAYER M5 ;
        RECT  36.24 105.732 36.264 105.816 ;
    END
  END b[476]
  PIN b[477]
    DIRECTION OUTPUT ;
    USE SIGNAL ;
    PORT
      LAYER M5 ;
        RECT  36.336 105.732 36.36 105.816 ;
    END
  END b[477]
  PIN b[478]
    DIRECTION OUTPUT ;
    USE SIGNAL ;
    PORT
      LAYER M5 ;
        RECT  36.432 105.732 36.456 105.816 ;
    END
  END b[478]
  PIN b[479]
    DIRECTION OUTPUT ;
    USE SIGNAL ;
    PORT
      LAYER M5 ;
        RECT  36.528 105.732 36.552 105.816 ;
    END
  END b[479]
  PIN b[47]
    DIRECTION OUTPUT ;
    USE SIGNAL ;
    PORT
      LAYER M3 ;
        RECT  42.444 105.779 42.462 105.816 ;
    END
  END b[47]
  PIN b[480]
    DIRECTION OUTPUT ;
    USE SIGNAL ;
    PORT
      LAYER M5 ;
        RECT  30.48 105.732 30.504 105.816 ;
    END
  END b[480]
  PIN b[481]
    DIRECTION OUTPUT ;
    USE SIGNAL ;
    PORT
      LAYER M5 ;
        RECT  30.576 105.732 30.6 105.816 ;
    END
  END b[481]
  PIN b[482]
    DIRECTION OUTPUT ;
    USE SIGNAL ;
    PORT
      LAYER M5 ;
        RECT  30.672 105.732 30.696 105.816 ;
    END
  END b[482]
  PIN b[483]
    DIRECTION OUTPUT ;
    USE SIGNAL ;
    PORT
      LAYER M5 ;
        RECT  30.768 105.732 30.792 105.816 ;
    END
  END b[483]
  PIN b[484]
    DIRECTION OUTPUT ;
    USE SIGNAL ;
    PORT
      LAYER M5 ;
        RECT  30.864 105.732 30.888 105.816 ;
    END
  END b[484]
  PIN b[485]
    DIRECTION OUTPUT ;
    USE SIGNAL ;
    PORT
      LAYER M5 ;
        RECT  30.96 105.732 30.984 105.816 ;
    END
  END b[485]
  PIN b[486]
    DIRECTION OUTPUT ;
    USE SIGNAL ;
    PORT
      LAYER M5 ;
        RECT  31.056 105.732 31.08 105.816 ;
    END
  END b[486]
  PIN b[487]
    DIRECTION OUTPUT ;
    USE SIGNAL ;
    PORT
      LAYER M5 ;
        RECT  31.152 105.732 31.176 105.816 ;
    END
  END b[487]
  PIN b[488]
    DIRECTION OUTPUT ;
    USE SIGNAL ;
    PORT
      LAYER M5 ;
        RECT  31.248 105.732 31.272 105.816 ;
    END
  END b[488]
  PIN b[489]
    DIRECTION OUTPUT ;
    USE SIGNAL ;
    PORT
      LAYER M5 ;
        RECT  31.344 105.732 31.368 105.816 ;
    END
  END b[489]
  PIN b[48]
    DIRECTION OUTPUT ;
    USE SIGNAL ;
    PORT
      LAYER M3 ;
        RECT  42.516 105.779 42.534 105.816 ;
    END
  END b[48]
  PIN b[490]
    DIRECTION OUTPUT ;
    USE SIGNAL ;
    PORT
      LAYER M5 ;
        RECT  31.44 105.732 31.464 105.816 ;
    END
  END b[490]
  PIN b[491]
    DIRECTION OUTPUT ;
    USE SIGNAL ;
    PORT
      LAYER M5 ;
        RECT  31.536 105.732 31.56 105.816 ;
    END
  END b[491]
  PIN b[492]
    DIRECTION OUTPUT ;
    USE SIGNAL ;
    PORT
      LAYER M5 ;
        RECT  31.632 105.732 31.656 105.816 ;
    END
  END b[492]
  PIN b[493]
    DIRECTION OUTPUT ;
    USE SIGNAL ;
    PORT
      LAYER M5 ;
        RECT  31.728 105.732 31.752 105.816 ;
    END
  END b[493]
  PIN b[494]
    DIRECTION OUTPUT ;
    USE SIGNAL ;
    PORT
      LAYER M5 ;
        RECT  31.824 105.732 31.848 105.816 ;
    END
  END b[494]
  PIN b[495]
    DIRECTION OUTPUT ;
    USE SIGNAL ;
    PORT
      LAYER M5 ;
        RECT  31.92 105.732 31.944 105.816 ;
    END
  END b[495]
  PIN b[496]
    DIRECTION OUTPUT ;
    USE SIGNAL ;
    PORT
      LAYER M5 ;
        RECT  32.016 105.732 32.04 105.816 ;
    END
  END b[496]
  PIN b[497]
    DIRECTION OUTPUT ;
    USE SIGNAL ;
    PORT
      LAYER M5 ;
        RECT  32.112 105.732 32.136 105.816 ;
    END
  END b[497]
  PIN b[498]
    DIRECTION OUTPUT ;
    USE SIGNAL ;
    PORT
      LAYER M5 ;
        RECT  32.208 105.732 32.232 105.816 ;
    END
  END b[498]
  PIN b[499]
    DIRECTION OUTPUT ;
    USE SIGNAL ;
    PORT
      LAYER M5 ;
        RECT  32.304 105.732 32.328 105.816 ;
    END
  END b[499]
  PIN b[49]
    DIRECTION OUTPUT ;
    USE SIGNAL ;
    PORT
      LAYER M3 ;
        RECT  42.588 105.779 42.606 105.816 ;
    END
  END b[49]
  PIN b[4]
    DIRECTION OUTPUT ;
    USE SIGNAL ;
    PORT
      LAYER M3 ;
        RECT  37.044 105.779 37.062 105.816 ;
    END
  END b[4]
  PIN b[500]
    DIRECTION OUTPUT ;
    USE SIGNAL ;
    PORT
      LAYER M5 ;
        RECT  32.4 105.732 32.424 105.816 ;
    END
  END b[500]
  PIN b[501]
    DIRECTION OUTPUT ;
    USE SIGNAL ;
    PORT
      LAYER M5 ;
        RECT  32.496 105.732 32.52 105.816 ;
    END
  END b[501]
  PIN b[502]
    DIRECTION OUTPUT ;
    USE SIGNAL ;
    PORT
      LAYER M5 ;
        RECT  32.592 105.732 32.616 105.816 ;
    END
  END b[502]
  PIN b[503]
    DIRECTION OUTPUT ;
    USE SIGNAL ;
    PORT
      LAYER M5 ;
        RECT  32.688 105.732 32.712 105.816 ;
    END
  END b[503]
  PIN b[504]
    DIRECTION OUTPUT ;
    USE SIGNAL ;
    PORT
      LAYER M5 ;
        RECT  32.784 105.732 32.808 105.816 ;
    END
  END b[504]
  PIN b[505]
    DIRECTION OUTPUT ;
    USE SIGNAL ;
    PORT
      LAYER M5 ;
        RECT  32.88 105.732 32.904 105.816 ;
    END
  END b[505]
  PIN b[506]
    DIRECTION OUTPUT ;
    USE SIGNAL ;
    PORT
      LAYER M5 ;
        RECT  32.976 105.732 33 105.816 ;
    END
  END b[506]
  PIN b[507]
    DIRECTION OUTPUT ;
    USE SIGNAL ;
    PORT
      LAYER M5 ;
        RECT  33.072 105.732 33.096 105.816 ;
    END
  END b[507]
  PIN b[508]
    DIRECTION OUTPUT ;
    USE SIGNAL ;
    PORT
      LAYER M5 ;
        RECT  33.168 105.732 33.192 105.816 ;
    END
  END b[508]
  PIN b[509]
    DIRECTION OUTPUT ;
    USE SIGNAL ;
    PORT
      LAYER M5 ;
        RECT  33.264 105.732 33.288 105.816 ;
    END
  END b[509]
  PIN b[50]
    DIRECTION OUTPUT ;
    USE SIGNAL ;
    PORT
      LAYER M3 ;
        RECT  42.66 105.779 42.678 105.816 ;
    END
  END b[50]
  PIN b[510]
    DIRECTION OUTPUT ;
    USE SIGNAL ;
    PORT
      LAYER M5 ;
        RECT  33.36 105.732 33.384 105.816 ;
    END
  END b[510]
  PIN b[511]
    DIRECTION OUTPUT ;
    USE SIGNAL ;
    PORT
      LAYER M5 ;
        RECT  33.456 105.732 33.48 105.816 ;
    END
  END b[511]
  PIN b[512]
    DIRECTION OUTPUT ;
    USE SIGNAL ;
    PORT
      LAYER M3 ;
        RECT  20.052 105.779 20.07 105.816 ;
    END
  END b[512]
  PIN b[513]
    DIRECTION OUTPUT ;
    USE SIGNAL ;
    PORT
      LAYER M3 ;
        RECT  20.124 105.779 20.142 105.816 ;
    END
  END b[513]
  PIN b[514]
    DIRECTION OUTPUT ;
    USE SIGNAL ;
    PORT
      LAYER M3 ;
        RECT  20.196 105.779 20.214 105.816 ;
    END
  END b[514]
  PIN b[515]
    DIRECTION OUTPUT ;
    USE SIGNAL ;
    PORT
      LAYER M3 ;
        RECT  20.268 105.779 20.286 105.816 ;
    END
  END b[515]
  PIN b[516]
    DIRECTION OUTPUT ;
    USE SIGNAL ;
    PORT
      LAYER M3 ;
        RECT  20.34 105.779 20.358 105.816 ;
    END
  END b[516]
  PIN b[517]
    DIRECTION OUTPUT ;
    USE SIGNAL ;
    PORT
      LAYER M3 ;
        RECT  20.412 105.779 20.43 105.816 ;
    END
  END b[517]
  PIN b[518]
    DIRECTION OUTPUT ;
    USE SIGNAL ;
    PORT
      LAYER M3 ;
        RECT  20.484 105.779 20.502 105.816 ;
    END
  END b[518]
  PIN b[519]
    DIRECTION OUTPUT ;
    USE SIGNAL ;
    PORT
      LAYER M3 ;
        RECT  20.556 105.779 20.574 105.816 ;
    END
  END b[519]
  PIN b[51]
    DIRECTION OUTPUT ;
    USE SIGNAL ;
    PORT
      LAYER M3 ;
        RECT  42.732 105.779 42.75 105.816 ;
    END
  END b[51]
  PIN b[520]
    DIRECTION OUTPUT ;
    USE SIGNAL ;
    PORT
      LAYER M3 ;
        RECT  20.628 105.779 20.646 105.816 ;
    END
  END b[520]
  PIN b[521]
    DIRECTION OUTPUT ;
    USE SIGNAL ;
    PORT
      LAYER M3 ;
        RECT  20.7 105.779 20.718 105.816 ;
    END
  END b[521]
  PIN b[522]
    DIRECTION OUTPUT ;
    USE SIGNAL ;
    PORT
      LAYER M3 ;
        RECT  20.772 105.779 20.79 105.816 ;
    END
  END b[522]
  PIN b[523]
    DIRECTION OUTPUT ;
    USE SIGNAL ;
    PORT
      LAYER M3 ;
        RECT  20.844 105.779 20.862 105.816 ;
    END
  END b[523]
  PIN b[524]
    DIRECTION OUTPUT ;
    USE SIGNAL ;
    PORT
      LAYER M3 ;
        RECT  20.916 105.779 20.934 105.816 ;
    END
  END b[524]
  PIN b[525]
    DIRECTION OUTPUT ;
    USE SIGNAL ;
    PORT
      LAYER M3 ;
        RECT  20.988 105.779 21.006 105.816 ;
    END
  END b[525]
  PIN b[526]
    DIRECTION OUTPUT ;
    USE SIGNAL ;
    PORT
      LAYER M3 ;
        RECT  21.06 105.779 21.078 105.816 ;
    END
  END b[526]
  PIN b[527]
    DIRECTION OUTPUT ;
    USE SIGNAL ;
    PORT
      LAYER M3 ;
        RECT  21.132 105.779 21.15 105.816 ;
    END
  END b[527]
  PIN b[528]
    DIRECTION OUTPUT ;
    USE SIGNAL ;
    PORT
      LAYER M3 ;
        RECT  21.204 105.779 21.222 105.816 ;
    END
  END b[528]
  PIN b[529]
    DIRECTION OUTPUT ;
    USE SIGNAL ;
    PORT
      LAYER M3 ;
        RECT  21.276 105.779 21.294 105.816 ;
    END
  END b[529]
  PIN b[52]
    DIRECTION OUTPUT ;
    USE SIGNAL ;
    PORT
      LAYER M3 ;
        RECT  42.804 105.779 42.822 105.816 ;
    END
  END b[52]
  PIN b[530]
    DIRECTION OUTPUT ;
    USE SIGNAL ;
    PORT
      LAYER M3 ;
        RECT  21.348 105.779 21.366 105.816 ;
    END
  END b[530]
  PIN b[531]
    DIRECTION OUTPUT ;
    USE SIGNAL ;
    PORT
      LAYER M3 ;
        RECT  21.42 105.779 21.438 105.816 ;
    END
  END b[531]
  PIN b[532]
    DIRECTION OUTPUT ;
    USE SIGNAL ;
    PORT
      LAYER M3 ;
        RECT  21.492 105.779 21.51 105.816 ;
    END
  END b[532]
  PIN b[533]
    DIRECTION OUTPUT ;
    USE SIGNAL ;
    PORT
      LAYER M3 ;
        RECT  21.564 105.779 21.582 105.816 ;
    END
  END b[533]
  PIN b[534]
    DIRECTION OUTPUT ;
    USE SIGNAL ;
    PORT
      LAYER M3 ;
        RECT  21.636 105.779 21.654 105.816 ;
    END
  END b[534]
  PIN b[535]
    DIRECTION OUTPUT ;
    USE SIGNAL ;
    PORT
      LAYER M3 ;
        RECT  21.708 105.779 21.726 105.816 ;
    END
  END b[535]
  PIN b[536]
    DIRECTION OUTPUT ;
    USE SIGNAL ;
    PORT
      LAYER M3 ;
        RECT  21.78 105.779 21.798 105.816 ;
    END
  END b[536]
  PIN b[537]
    DIRECTION OUTPUT ;
    USE SIGNAL ;
    PORT
      LAYER M3 ;
        RECT  21.852 105.779 21.87 105.816 ;
    END
  END b[537]
  PIN b[538]
    DIRECTION OUTPUT ;
    USE SIGNAL ;
    PORT
      LAYER M3 ;
        RECT  21.924 105.779 21.942 105.816 ;
    END
  END b[538]
  PIN b[539]
    DIRECTION OUTPUT ;
    USE SIGNAL ;
    PORT
      LAYER M3 ;
        RECT  21.996 105.779 22.014 105.816 ;
    END
  END b[539]
  PIN b[53]
    DIRECTION OUTPUT ;
    USE SIGNAL ;
    PORT
      LAYER M3 ;
        RECT  42.876 105.779 42.894 105.816 ;
    END
  END b[53]
  PIN b[540]
    DIRECTION OUTPUT ;
    USE SIGNAL ;
    PORT
      LAYER M3 ;
        RECT  22.068 105.779 22.086 105.816 ;
    END
  END b[540]
  PIN b[541]
    DIRECTION OUTPUT ;
    USE SIGNAL ;
    PORT
      LAYER M3 ;
        RECT  22.14 105.779 22.158 105.816 ;
    END
  END b[541]
  PIN b[542]
    DIRECTION OUTPUT ;
    USE SIGNAL ;
    PORT
      LAYER M3 ;
        RECT  22.212 105.779 22.23 105.816 ;
    END
  END b[542]
  PIN b[543]
    DIRECTION OUTPUT ;
    USE SIGNAL ;
    PORT
      LAYER M3 ;
        RECT  22.284 105.779 22.302 105.816 ;
    END
  END b[543]
  PIN b[544]
    DIRECTION OUTPUT ;
    USE SIGNAL ;
    PORT
      LAYER M3 ;
        RECT  10.26 105.779 10.278 105.816 ;
    END
  END b[544]
  PIN b[545]
    DIRECTION OUTPUT ;
    USE SIGNAL ;
    PORT
      LAYER M3 ;
        RECT  10.332 105.779 10.35 105.816 ;
    END
  END b[545]
  PIN b[546]
    DIRECTION OUTPUT ;
    USE SIGNAL ;
    PORT
      LAYER M3 ;
        RECT  10.404 105.779 10.422 105.816 ;
    END
  END b[546]
  PIN b[547]
    DIRECTION OUTPUT ;
    USE SIGNAL ;
    PORT
      LAYER M3 ;
        RECT  10.476 105.779 10.494 105.816 ;
    END
  END b[547]
  PIN b[548]
    DIRECTION OUTPUT ;
    USE SIGNAL ;
    PORT
      LAYER M3 ;
        RECT  10.548 105.779 10.566 105.816 ;
    END
  END b[548]
  PIN b[549]
    DIRECTION OUTPUT ;
    USE SIGNAL ;
    PORT
      LAYER M3 ;
        RECT  10.62 105.779 10.638 105.816 ;
    END
  END b[549]
  PIN b[54]
    DIRECTION OUTPUT ;
    USE SIGNAL ;
    PORT
      LAYER M3 ;
        RECT  42.948 105.779 42.966 105.816 ;
    END
  END b[54]
  PIN b[550]
    DIRECTION OUTPUT ;
    USE SIGNAL ;
    PORT
      LAYER M3 ;
        RECT  10.692 105.779 10.71 105.816 ;
    END
  END b[550]
  PIN b[551]
    DIRECTION OUTPUT ;
    USE SIGNAL ;
    PORT
      LAYER M3 ;
        RECT  10.764 105.779 10.782 105.816 ;
    END
  END b[551]
  PIN b[552]
    DIRECTION OUTPUT ;
    USE SIGNAL ;
    PORT
      LAYER M3 ;
        RECT  10.836 105.779 10.854 105.816 ;
    END
  END b[552]
  PIN b[553]
    DIRECTION OUTPUT ;
    USE SIGNAL ;
    PORT
      LAYER M3 ;
        RECT  10.908 105.779 10.926 105.816 ;
    END
  END b[553]
  PIN b[554]
    DIRECTION OUTPUT ;
    USE SIGNAL ;
    PORT
      LAYER M3 ;
        RECT  10.98 105.779 10.998 105.816 ;
    END
  END b[554]
  PIN b[555]
    DIRECTION OUTPUT ;
    USE SIGNAL ;
    PORT
      LAYER M3 ;
        RECT  11.052 105.779 11.07 105.816 ;
    END
  END b[555]
  PIN b[556]
    DIRECTION OUTPUT ;
    USE SIGNAL ;
    PORT
      LAYER M3 ;
        RECT  11.124 105.779 11.142 105.816 ;
    END
  END b[556]
  PIN b[557]
    DIRECTION OUTPUT ;
    USE SIGNAL ;
    PORT
      LAYER M3 ;
        RECT  11.196 105.779 11.214 105.816 ;
    END
  END b[557]
  PIN b[558]
    DIRECTION OUTPUT ;
    USE SIGNAL ;
    PORT
      LAYER M3 ;
        RECT  11.268 105.779 11.286 105.816 ;
    END
  END b[558]
  PIN b[559]
    DIRECTION OUTPUT ;
    USE SIGNAL ;
    PORT
      LAYER M3 ;
        RECT  11.34 105.779 11.358 105.816 ;
    END
  END b[559]
  PIN b[55]
    DIRECTION OUTPUT ;
    USE SIGNAL ;
    PORT
      LAYER M3 ;
        RECT  43.02 105.779 43.038 105.816 ;
    END
  END b[55]
  PIN b[560]
    DIRECTION OUTPUT ;
    USE SIGNAL ;
    PORT
      LAYER M3 ;
        RECT  11.412 105.779 11.43 105.816 ;
    END
  END b[560]
  PIN b[561]
    DIRECTION OUTPUT ;
    USE SIGNAL ;
    PORT
      LAYER M3 ;
        RECT  11.484 105.779 11.502 105.816 ;
    END
  END b[561]
  PIN b[562]
    DIRECTION OUTPUT ;
    USE SIGNAL ;
    PORT
      LAYER M3 ;
        RECT  11.556 105.779 11.574 105.816 ;
    END
  END b[562]
  PIN b[563]
    DIRECTION OUTPUT ;
    USE SIGNAL ;
    PORT
      LAYER M3 ;
        RECT  11.628 105.779 11.646 105.816 ;
    END
  END b[563]
  PIN b[564]
    DIRECTION OUTPUT ;
    USE SIGNAL ;
    PORT
      LAYER M3 ;
        RECT  11.7 105.779 11.718 105.816 ;
    END
  END b[564]
  PIN b[565]
    DIRECTION OUTPUT ;
    USE SIGNAL ;
    PORT
      LAYER M3 ;
        RECT  11.772 105.779 11.79 105.816 ;
    END
  END b[565]
  PIN b[566]
    DIRECTION OUTPUT ;
    USE SIGNAL ;
    PORT
      LAYER M3 ;
        RECT  11.844 105.779 11.862 105.816 ;
    END
  END b[566]
  PIN b[567]
    DIRECTION OUTPUT ;
    USE SIGNAL ;
    PORT
      LAYER M3 ;
        RECT  11.916 105.779 11.934 105.816 ;
    END
  END b[567]
  PIN b[568]
    DIRECTION OUTPUT ;
    USE SIGNAL ;
    PORT
      LAYER M3 ;
        RECT  11.988 105.779 12.006 105.816 ;
    END
  END b[568]
  PIN b[569]
    DIRECTION OUTPUT ;
    USE SIGNAL ;
    PORT
      LAYER M3 ;
        RECT  12.06 105.779 12.078 105.816 ;
    END
  END b[569]
  PIN b[56]
    DIRECTION OUTPUT ;
    USE SIGNAL ;
    PORT
      LAYER M3 ;
        RECT  43.092 105.779 43.11 105.816 ;
    END
  END b[56]
  PIN b[570]
    DIRECTION OUTPUT ;
    USE SIGNAL ;
    PORT
      LAYER M3 ;
        RECT  12.132 105.779 12.15 105.816 ;
    END
  END b[570]
  PIN b[571]
    DIRECTION OUTPUT ;
    USE SIGNAL ;
    PORT
      LAYER M3 ;
        RECT  12.204 105.779 12.222 105.816 ;
    END
  END b[571]
  PIN b[572]
    DIRECTION OUTPUT ;
    USE SIGNAL ;
    PORT
      LAYER M3 ;
        RECT  12.276 105.779 12.294 105.816 ;
    END
  END b[572]
  PIN b[573]
    DIRECTION OUTPUT ;
    USE SIGNAL ;
    PORT
      LAYER M3 ;
        RECT  12.348 105.779 12.366 105.816 ;
    END
  END b[573]
  PIN b[574]
    DIRECTION OUTPUT ;
    USE SIGNAL ;
    PORT
      LAYER M3 ;
        RECT  12.42 105.779 12.438 105.816 ;
    END
  END b[574]
  PIN b[575]
    DIRECTION OUTPUT ;
    USE SIGNAL ;
    PORT
      LAYER M3 ;
        RECT  12.492 105.779 12.51 105.816 ;
    END
  END b[575]
  PIN b[576]
    DIRECTION OUTPUT ;
    USE SIGNAL ;
    PORT
      LAYER M3 ;
        RECT  22.932 105.779 22.95 105.816 ;
    END
  END b[576]
  PIN b[577]
    DIRECTION OUTPUT ;
    USE SIGNAL ;
    PORT
      LAYER M3 ;
        RECT  23.004 105.779 23.022 105.816 ;
    END
  END b[577]
  PIN b[578]
    DIRECTION OUTPUT ;
    USE SIGNAL ;
    PORT
      LAYER M3 ;
        RECT  23.076 105.779 23.094 105.816 ;
    END
  END b[578]
  PIN b[579]
    DIRECTION OUTPUT ;
    USE SIGNAL ;
    PORT
      LAYER M3 ;
        RECT  23.148 105.779 23.166 105.816 ;
    END
  END b[579]
  PIN b[57]
    DIRECTION OUTPUT ;
    USE SIGNAL ;
    PORT
      LAYER M3 ;
        RECT  43.164 105.779 43.182 105.816 ;
    END
  END b[57]
  PIN b[580]
    DIRECTION OUTPUT ;
    USE SIGNAL ;
    PORT
      LAYER M3 ;
        RECT  23.22 105.779 23.238 105.816 ;
    END
  END b[580]
  PIN b[581]
    DIRECTION OUTPUT ;
    USE SIGNAL ;
    PORT
      LAYER M3 ;
        RECT  23.292 105.779 23.31 105.816 ;
    END
  END b[581]
  PIN b[582]
    DIRECTION OUTPUT ;
    USE SIGNAL ;
    PORT
      LAYER M3 ;
        RECT  23.364 105.779 23.382 105.816 ;
    END
  END b[582]
  PIN b[583]
    DIRECTION OUTPUT ;
    USE SIGNAL ;
    PORT
      LAYER M3 ;
        RECT  23.436 105.779 23.454 105.816 ;
    END
  END b[583]
  PIN b[584]
    DIRECTION OUTPUT ;
    USE SIGNAL ;
    PORT
      LAYER M3 ;
        RECT  23.508 105.779 23.526 105.816 ;
    END
  END b[584]
  PIN b[585]
    DIRECTION OUTPUT ;
    USE SIGNAL ;
    PORT
      LAYER M3 ;
        RECT  23.58 105.779 23.598 105.816 ;
    END
  END b[585]
  PIN b[586]
    DIRECTION OUTPUT ;
    USE SIGNAL ;
    PORT
      LAYER M3 ;
        RECT  23.652 105.779 23.67 105.816 ;
    END
  END b[586]
  PIN b[587]
    DIRECTION OUTPUT ;
    USE SIGNAL ;
    PORT
      LAYER M3 ;
        RECT  23.724 105.779 23.742 105.816 ;
    END
  END b[587]
  PIN b[588]
    DIRECTION OUTPUT ;
    USE SIGNAL ;
    PORT
      LAYER M3 ;
        RECT  23.796 105.779 23.814 105.816 ;
    END
  END b[588]
  PIN b[589]
    DIRECTION OUTPUT ;
    USE SIGNAL ;
    PORT
      LAYER M3 ;
        RECT  23.868 105.779 23.886 105.816 ;
    END
  END b[589]
  PIN b[58]
    DIRECTION OUTPUT ;
    USE SIGNAL ;
    PORT
      LAYER M3 ;
        RECT  43.236 105.779 43.254 105.816 ;
    END
  END b[58]
  PIN b[590]
    DIRECTION OUTPUT ;
    USE SIGNAL ;
    PORT
      LAYER M3 ;
        RECT  23.94 105.779 23.958 105.816 ;
    END
  END b[590]
  PIN b[591]
    DIRECTION OUTPUT ;
    USE SIGNAL ;
    PORT
      LAYER M3 ;
        RECT  24.012 105.779 24.03 105.816 ;
    END
  END b[591]
  PIN b[592]
    DIRECTION OUTPUT ;
    USE SIGNAL ;
    PORT
      LAYER M3 ;
        RECT  24.084 105.779 24.102 105.816 ;
    END
  END b[592]
  PIN b[593]
    DIRECTION OUTPUT ;
    USE SIGNAL ;
    PORT
      LAYER M3 ;
        RECT  24.156 105.779 24.174 105.816 ;
    END
  END b[593]
  PIN b[594]
    DIRECTION OUTPUT ;
    USE SIGNAL ;
    PORT
      LAYER M3 ;
        RECT  24.228 105.779 24.246 105.816 ;
    END
  END b[594]
  PIN b[595]
    DIRECTION OUTPUT ;
    USE SIGNAL ;
    PORT
      LAYER M3 ;
        RECT  24.3 105.779 24.318 105.816 ;
    END
  END b[595]
  PIN b[596]
    DIRECTION OUTPUT ;
    USE SIGNAL ;
    PORT
      LAYER M3 ;
        RECT  24.372 105.779 24.39 105.816 ;
    END
  END b[596]
  PIN b[597]
    DIRECTION OUTPUT ;
    USE SIGNAL ;
    PORT
      LAYER M3 ;
        RECT  24.444 105.779 24.462 105.816 ;
    END
  END b[597]
  PIN b[598]
    DIRECTION OUTPUT ;
    USE SIGNAL ;
    PORT
      LAYER M3 ;
        RECT  24.516 105.779 24.534 105.816 ;
    END
  END b[598]
  PIN b[599]
    DIRECTION OUTPUT ;
    USE SIGNAL ;
    PORT
      LAYER M3 ;
        RECT  24.588 105.779 24.606 105.816 ;
    END
  END b[599]
  PIN b[59]
    DIRECTION OUTPUT ;
    USE SIGNAL ;
    PORT
      LAYER M3 ;
        RECT  43.308 105.779 43.326 105.816 ;
    END
  END b[59]
  PIN b[5]
    DIRECTION OUTPUT ;
    USE SIGNAL ;
    PORT
      LAYER M3 ;
        RECT  37.116 105.779 37.134 105.816 ;
    END
  END b[5]
  PIN b[60]
    DIRECTION OUTPUT ;
    USE SIGNAL ;
    PORT
      LAYER M3 ;
        RECT  43.38 105.779 43.398 105.816 ;
    END
  END b[60]
  PIN b[61]
    DIRECTION OUTPUT ;
    USE SIGNAL ;
    PORT
      LAYER M3 ;
        RECT  43.452 105.779 43.47 105.816 ;
    END
  END b[61]
  PIN b[62]
    DIRECTION OUTPUT ;
    USE SIGNAL ;
    PORT
      LAYER M3 ;
        RECT  43.524 105.779 43.542 105.816 ;
    END
  END b[62]
  PIN b[63]
    DIRECTION OUTPUT ;
    USE SIGNAL ;
    PORT
      LAYER M3 ;
        RECT  43.596 105.779 43.614 105.816 ;
    END
  END b[63]
  PIN b[64]
    DIRECTION OUTPUT ;
    USE SIGNAL ;
    PORT
      LAYER M3 ;
        RECT  48.852 105.779 48.87 105.816 ;
    END
  END b[64]
  PIN b[65]
    DIRECTION OUTPUT ;
    USE SIGNAL ;
    PORT
      LAYER M3 ;
        RECT  48.924 105.779 48.942 105.816 ;
    END
  END b[65]
  PIN b[66]
    DIRECTION OUTPUT ;
    USE SIGNAL ;
    PORT
      LAYER M3 ;
        RECT  48.996 105.779 49.014 105.816 ;
    END
  END b[66]
  PIN b[67]
    DIRECTION OUTPUT ;
    USE SIGNAL ;
    PORT
      LAYER M3 ;
        RECT  49.068 105.779 49.086 105.816 ;
    END
  END b[67]
  PIN b[68]
    DIRECTION OUTPUT ;
    USE SIGNAL ;
    PORT
      LAYER M3 ;
        RECT  49.14 105.779 49.158 105.816 ;
    END
  END b[68]
  PIN b[69]
    DIRECTION OUTPUT ;
    USE SIGNAL ;
    PORT
      LAYER M3 ;
        RECT  49.212 105.779 49.23 105.816 ;
    END
  END b[69]
  PIN b[6]
    DIRECTION OUTPUT ;
    USE SIGNAL ;
    PORT
      LAYER M3 ;
        RECT  37.188 105.779 37.206 105.816 ;
    END
  END b[6]
  PIN b[70]
    DIRECTION OUTPUT ;
    USE SIGNAL ;
    PORT
      LAYER M3 ;
        RECT  49.284 105.779 49.302 105.816 ;
    END
  END b[70]
  PIN b[71]
    DIRECTION OUTPUT ;
    USE SIGNAL ;
    PORT
      LAYER M3 ;
        RECT  49.356 105.779 49.374 105.816 ;
    END
  END b[71]
  PIN b[72]
    DIRECTION OUTPUT ;
    USE SIGNAL ;
    PORT
      LAYER M3 ;
        RECT  49.428 105.779 49.446 105.816 ;
    END
  END b[72]
  PIN b[73]
    DIRECTION OUTPUT ;
    USE SIGNAL ;
    PORT
      LAYER M3 ;
        RECT  49.5 105.779 49.518 105.816 ;
    END
  END b[73]
  PIN b[74]
    DIRECTION OUTPUT ;
    USE SIGNAL ;
    PORT
      LAYER M3 ;
        RECT  49.572 105.779 49.59 105.816 ;
    END
  END b[74]
  PIN b[75]
    DIRECTION OUTPUT ;
    USE SIGNAL ;
    PORT
      LAYER M3 ;
        RECT  49.644 105.779 49.662 105.816 ;
    END
  END b[75]
  PIN b[76]
    DIRECTION OUTPUT ;
    USE SIGNAL ;
    PORT
      LAYER M3 ;
        RECT  49.716 105.779 49.734 105.816 ;
    END
  END b[76]
  PIN b[77]
    DIRECTION OUTPUT ;
    USE SIGNAL ;
    PORT
      LAYER M3 ;
        RECT  49.788 105.779 49.806 105.816 ;
    END
  END b[77]
  PIN b[78]
    DIRECTION OUTPUT ;
    USE SIGNAL ;
    PORT
      LAYER M3 ;
        RECT  49.86 105.779 49.878 105.816 ;
    END
  END b[78]
  PIN b[79]
    DIRECTION OUTPUT ;
    USE SIGNAL ;
    PORT
      LAYER M3 ;
        RECT  49.932 105.779 49.95 105.816 ;
    END
  END b[79]
  PIN b[7]
    DIRECTION OUTPUT ;
    USE SIGNAL ;
    PORT
      LAYER M3 ;
        RECT  37.26 105.779 37.278 105.816 ;
    END
  END b[7]
  PIN b[80]
    DIRECTION OUTPUT ;
    USE SIGNAL ;
    PORT
      LAYER M3 ;
        RECT  50.004 105.779 50.022 105.816 ;
    END
  END b[80]
  PIN b[81]
    DIRECTION OUTPUT ;
    USE SIGNAL ;
    PORT
      LAYER M3 ;
        RECT  50.076 105.779 50.094 105.816 ;
    END
  END b[81]
  PIN b[82]
    DIRECTION OUTPUT ;
    USE SIGNAL ;
    PORT
      LAYER M3 ;
        RECT  50.148 105.779 50.166 105.816 ;
    END
  END b[82]
  PIN b[83]
    DIRECTION OUTPUT ;
    USE SIGNAL ;
    PORT
      LAYER M3 ;
        RECT  50.22 105.779 50.238 105.816 ;
    END
  END b[83]
  PIN b[84]
    DIRECTION OUTPUT ;
    USE SIGNAL ;
    PORT
      LAYER M3 ;
        RECT  50.292 105.779 50.31 105.816 ;
    END
  END b[84]
  PIN b[85]
    DIRECTION OUTPUT ;
    USE SIGNAL ;
    PORT
      LAYER M3 ;
        RECT  50.364 105.779 50.382 105.816 ;
    END
  END b[85]
  PIN b[86]
    DIRECTION OUTPUT ;
    USE SIGNAL ;
    PORT
      LAYER M3 ;
        RECT  50.436 105.779 50.454 105.816 ;
    END
  END b[86]
  PIN b[87]
    DIRECTION OUTPUT ;
    USE SIGNAL ;
    PORT
      LAYER M3 ;
        RECT  50.508 105.779 50.526 105.816 ;
    END
  END b[87]
  PIN b[88]
    DIRECTION OUTPUT ;
    USE SIGNAL ;
    PORT
      LAYER M3 ;
        RECT  50.58 105.779 50.598 105.816 ;
    END
  END b[88]
  PIN b[89]
    DIRECTION OUTPUT ;
    USE SIGNAL ;
    PORT
      LAYER M3 ;
        RECT  50.652 105.779 50.67 105.816 ;
    END
  END b[89]
  PIN b[8]
    DIRECTION OUTPUT ;
    USE SIGNAL ;
    PORT
      LAYER M3 ;
        RECT  37.332 105.779 37.35 105.816 ;
    END
  END b[8]
  PIN b[90]
    DIRECTION OUTPUT ;
    USE SIGNAL ;
    PORT
      LAYER M3 ;
        RECT  50.724 105.779 50.742 105.816 ;
    END
  END b[90]
  PIN b[91]
    DIRECTION OUTPUT ;
    USE SIGNAL ;
    PORT
      LAYER M3 ;
        RECT  50.796 105.779 50.814 105.816 ;
    END
  END b[91]
  PIN b[92]
    DIRECTION OUTPUT ;
    USE SIGNAL ;
    PORT
      LAYER M3 ;
        RECT  50.868 105.779 50.886 105.816 ;
    END
  END b[92]
  PIN b[93]
    DIRECTION OUTPUT ;
    USE SIGNAL ;
    PORT
      LAYER M3 ;
        RECT  50.94 105.779 50.958 105.816 ;
    END
  END b[93]
  PIN b[94]
    DIRECTION OUTPUT ;
    USE SIGNAL ;
    PORT
      LAYER M3 ;
        RECT  51.012 105.779 51.03 105.816 ;
    END
  END b[94]
  PIN b[95]
    DIRECTION OUTPUT ;
    USE SIGNAL ;
    PORT
      LAYER M3 ;
        RECT  51.084 105.779 51.102 105.816 ;
    END
  END b[95]
  PIN b[96]
    DIRECTION OUTPUT ;
    USE SIGNAL ;
    PORT
      LAYER M3 ;
        RECT  65.556 105.779 65.574 105.816 ;
    END
  END b[96]
  PIN b[97]
    DIRECTION OUTPUT ;
    USE SIGNAL ;
    PORT
      LAYER M3 ;
        RECT  65.628 105.779 65.646 105.816 ;
    END
  END b[97]
  PIN b[98]
    DIRECTION OUTPUT ;
    USE SIGNAL ;
    PORT
      LAYER M3 ;
        RECT  65.7 105.779 65.718 105.816 ;
    END
  END b[98]
  PIN b[99]
    DIRECTION OUTPUT ;
    USE SIGNAL ;
    PORT
      LAYER M3 ;
        RECT  65.772 105.779 65.79 105.816 ;
    END
  END b[99]
  PIN b[9]
    DIRECTION OUTPUT ;
    USE SIGNAL ;
    PORT
      LAYER M3 ;
        RECT  37.404 105.779 37.422 105.816 ;
    END
  END b[9]
  PIN ck
    DIRECTION INPUT ;
    USE SIGNAL ;
    PORT
      LAYER M4 ;
        RECT  0 60.048 0.084 60.072 ;
    END
  END ck
  PIN ck_s
    DIRECTION INPUT ;
    USE SIGNAL ;
    PORT
      LAYER M4 ;
        RECT  0 60.144 0.084 60.168 ;
    END
  END ck_s
  PIN en
    DIRECTION INPUT ;
    USE SIGNAL ;
    PORT
      LAYER M4 ;
        RECT  0 60.24 0.084 60.264 ;
    END
  END en
  PIN fault
    DIRECTION OUTPUT ;
    USE SIGNAL ;
    PORT
      LAYER M4 ;
        RECT  0 60.336 0.084 60.36 ;
    END
  END fault
  PIN k0
    DIRECTION INPUT ;
    USE SIGNAL ;
    PORT
      LAYER M4 ;
        RECT  0 60.432 0.084 60.456 ;
    END
  END k0
  PIN k1
    DIRECTION INPUT ;
    USE SIGNAL ;
    PORT
      LAYER M4 ;
        RECT  0 60.528 0.084 60.552 ;
    END
  END k1
  PIN k2
    DIRECTION INPUT ;
    USE SIGNAL ;
    PORT
      LAYER M4 ;
        RECT  0 60.624 0.084 60.648 ;
    END
  END k2
  PIN rs
    DIRECTION INPUT ;
    USE SIGNAL ;
    PORT
      LAYER M4 ;
        RECT  0 60.72 0.084 60.744 ;
    END
  END rs
  PIN tie_hi
    DIRECTION OUTPUT ;
    USE SIGNAL ;
    PORT
      LAYER M4 ;
        RECT  0 60.816 0.084 60.84 ;
    END
  END tie_hi
  PIN tie_lo
    DIRECTION OUTPUT ;
    USE SIGNAL ;
    PORT
      LAYER M4 ;
        RECT  0 60.912 0.084 60.936 ;
    END
  END tie_lo
  PIN VDD
    DIRECTION INOUT ;
    USE POWER ;
    PORT
      LAYER M5 ;
        RECT  99.792 2.151 99.912 103.433 ;
        RECT  97.092 2.151 97.212 103.433 ;
        RECT  94.392 2.151 94.512 103.433 ;
        RECT  91.692 2.151 91.812 103.433 ;
        RECT  88.992 2.151 89.112 103.433 ;
        RECT  86.292 2.151 86.412 103.433 ;
        RECT  83.592 2.151 83.712 103.433 ;
        RECT  80.892 2.151 81.012 103.433 ;
        RECT  78.192 2.151 78.312 103.433 ;
        RECT  75.492 2.151 75.612 103.433 ;
        RECT  72.792 2.151 72.912 103.433 ;
        RECT  70.092 2.151 70.212 103.433 ;
        RECT  67.392 2.151 67.512 103.433 ;
        RECT  64.692 2.151 64.812 103.433 ;
        RECT  61.992 2.151 62.112 103.433 ;
        RECT  59.292 2.151 59.412 103.433 ;
        RECT  56.592 2.151 56.712 103.433 ;
        RECT  53.892 2.151 54.012 103.433 ;
        RECT  51.192 2.151 51.312 103.433 ;
        RECT  48.492 2.151 48.612 103.433 ;
        RECT  45.792 2.151 45.912 103.433 ;
        RECT  43.092 2.151 43.212 103.433 ;
        RECT  40.392 2.151 40.512 103.433 ;
        RECT  37.692 2.151 37.812 103.433 ;
        RECT  34.992 2.151 35.112 103.433 ;
        RECT  32.292 2.151 32.412 103.433 ;
        RECT  29.592 2.151 29.712 103.433 ;
        RECT  26.892 2.151 27.012 103.433 ;
        RECT  24.192 2.151 24.312 103.433 ;
        RECT  21.492 2.151 21.612 103.433 ;
        RECT  18.792 2.151 18.912 103.433 ;
        RECT  16.092 2.151 16.212 103.433 ;
        RECT  13.392 2.151 13.512 103.433 ;
        RECT  10.692 2.151 10.812 103.433 ;
        RECT  7.992 2.151 8.112 103.433 ;
        RECT  5.292 2.151 5.412 103.433 ;
        RECT  2.592 2.151 2.712 103.433 ;
    END
  END VDD
  PIN VSS
    DIRECTION INOUT ;
    USE GROUND ;
    PORT
      LAYER M5 ;
        RECT  99.6 2.137 99.72 103.419 ;
        RECT  96.9 2.137 97.02 103.419 ;
        RECT  94.2 2.137 94.32 103.419 ;
        RECT  91.5 2.137 91.62 103.419 ;
        RECT  88.8 2.137 88.92 103.419 ;
        RECT  86.1 2.137 86.22 103.419 ;
        RECT  83.4 2.137 83.52 103.419 ;
        RECT  80.7 2.137 80.82 103.419 ;
        RECT  78 2.137 78.12 103.419 ;
        RECT  75.3 2.137 75.42 103.419 ;
        RECT  72.6 2.137 72.72 103.419 ;
        RECT  69.9 2.137 70.02 103.419 ;
        RECT  67.2 2.137 67.32 103.419 ;
        RECT  64.5 2.137 64.62 103.419 ;
        RECT  61.8 2.137 61.92 103.419 ;
        RECT  59.1 2.137 59.22 103.419 ;
        RECT  56.4 2.137 56.52 103.419 ;
        RECT  53.7 2.137 53.82 103.419 ;
        RECT  51 2.137 51.12 103.419 ;
        RECT  48.3 2.137 48.42 103.419 ;
        RECT  45.6 2.137 45.72 103.419 ;
        RECT  42.9 2.137 43.02 103.419 ;
        RECT  40.2 2.137 40.32 103.419 ;
        RECT  37.5 2.137 37.62 103.419 ;
        RECT  34.8 2.137 34.92 103.419 ;
        RECT  32.1 2.137 32.22 103.419 ;
        RECT  29.4 2.137 29.52 103.419 ;
        RECT  26.7 2.137 26.82 103.419 ;
        RECT  24 2.137 24.12 103.419 ;
        RECT  21.3 2.137 21.42 103.419 ;
        RECT  18.6 2.137 18.72 103.419 ;
        RECT  15.9 2.137 16.02 103.419 ;
        RECT  13.2 2.137 13.32 103.419 ;
        RECT  10.5 2.137 10.62 103.419 ;
        RECT  7.8 2.137 7.92 103.419 ;
        RECT  5.1 2.137 5.22 103.419 ;
        RECT  2.4 2.137 2.52 103.419 ;
    END
  END VSS
  OBS
    LAYER RVTN ;
     RECT  2.16 2.16 101.898 2.295 ;
     RECT  2.16 2.565 101.898 2.835 ;
     RECT  2.16 3.105 101.898 3.375 ;
     RECT  2.16 3.645 101.898 3.915 ;
     RECT  2.16 4.185 101.898 4.455 ;
     RECT  2.16 4.725 101.898 4.995 ;
     RECT  2.16 5.265 101.898 5.535 ;
     RECT  2.16 5.805 101.898 6.075 ;
     RECT  2.16 6.345 101.898 6.615 ;
     RECT  2.16 6.885 101.898 7.155 ;
     RECT  2.16 7.425 101.898 7.695 ;
     RECT  2.16 7.965 101.898 8.235 ;
     RECT  2.16 8.505 101.898 8.775 ;
     RECT  2.16 9.045 101.898 9.315 ;
     RECT  2.16 9.585 101.898 9.855 ;
     RECT  2.16 10.125 101.898 10.395 ;
     RECT  2.16 10.665 101.898 10.935 ;
     RECT  2.16 11.205 101.898 11.475 ;
     RECT  2.16 11.745 101.898 12.015 ;
     RECT  2.16 12.285 101.898 12.555 ;
     RECT  2.16 12.825 101.898 13.095 ;
     RECT  2.16 13.365 101.898 13.635 ;
     RECT  2.16 13.905 101.898 14.175 ;
     RECT  2.16 14.445 101.898 14.715 ;
     RECT  2.16 14.985 101.898 15.255 ;
     RECT  2.16 15.525 101.898 15.795 ;
     RECT  2.16 16.065 101.898 16.335 ;
     RECT  2.16 16.605 101.898 16.875 ;
     RECT  2.16 17.145 101.898 17.415 ;
     RECT  2.16 17.685 101.898 17.955 ;
     RECT  2.16 18.225 101.898 18.495 ;
     RECT  2.16 18.765 101.898 19.035 ;
     RECT  2.16 19.305 101.898 19.575 ;
     RECT  2.16 19.845 101.898 20.115 ;
     RECT  2.16 20.385 101.898 20.655 ;
     RECT  2.16 20.925 101.898 21.195 ;
     RECT  2.16 21.465 101.898 21.735 ;
     RECT  2.16 22.005 101.898 22.275 ;
     RECT  2.16 22.545 101.898 22.815 ;
     RECT  2.16 23.085 101.898 23.355 ;
     RECT  2.16 23.625 101.898 23.895 ;
     RECT  2.16 24.165 101.898 24.435 ;
     RECT  2.16 24.705 101.898 24.975 ;
     RECT  2.16 25.245 101.898 25.515 ;
     RECT  2.16 25.785 101.898 26.055 ;
     RECT  2.16 26.325 101.898 26.595 ;
     RECT  2.16 26.865 101.898 27.135 ;
     RECT  2.16 27.405 101.898 27.675 ;
     RECT  2.16 27.945 101.898 28.215 ;
     RECT  2.16 28.485 101.898 28.755 ;
     RECT  2.16 29.025 101.898 29.295 ;
     RECT  2.16 29.565 101.898 29.835 ;
     RECT  2.16 30.105 101.898 30.375 ;
     RECT  2.16 30.645 101.898 30.915 ;
     RECT  2.16 31.185 101.898 31.455 ;
     RECT  2.16 31.725 101.898 31.995 ;
     RECT  2.16 32.265 101.898 32.535 ;
     RECT  2.16 32.805 101.898 33.075 ;
     RECT  2.16 33.345 101.898 33.615 ;
     RECT  2.16 33.885 101.898 34.155 ;
     RECT  2.16 34.425 101.898 34.695 ;
     RECT  2.16 34.965 101.898 35.235 ;
     RECT  2.16 35.505 101.898 35.775 ;
     RECT  2.16 36.045 101.898 36.315 ;
     RECT  2.16 36.585 101.898 36.855 ;
     RECT  2.16 37.125 101.898 37.395 ;
     RECT  2.16 37.665 101.898 37.935 ;
     RECT  2.16 38.205 101.898 38.475 ;
     RECT  2.16 38.745 101.898 39.015 ;
     RECT  2.16 39.285 101.898 39.555 ;
     RECT  2.16 39.825 101.898 40.095 ;
     RECT  2.16 40.365 101.898 40.635 ;
     RECT  2.16 40.905 101.898 41.175 ;
     RECT  2.16 41.445 101.898 41.715 ;
     RECT  2.16 41.985 101.898 42.255 ;
     RECT  2.16 42.525 101.898 42.795 ;
     RECT  2.16 43.065 101.898 43.335 ;
     RECT  2.16 43.605 101.898 43.875 ;
     RECT  2.16 44.145 101.898 44.415 ;
     RECT  2.16 44.685 101.898 44.955 ;
     RECT  2.16 45.225 101.898 45.495 ;
     RECT  2.16 45.765 101.898 46.035 ;
     RECT  2.16 46.305 101.898 46.575 ;
     RECT  2.16 46.845 101.898 47.115 ;
     RECT  2.16 47.385 101.898 47.655 ;
     RECT  2.16 47.925 101.898 48.195 ;
     RECT  2.16 48.465 101.898 48.735 ;
     RECT  2.16 49.005 101.898 49.275 ;
     RECT  2.16 49.545 101.898 49.815 ;
     RECT  2.16 50.085 101.898 50.355 ;
     RECT  2.16 50.625 101.898 50.895 ;
     RECT  2.16 51.165 101.898 51.435 ;
     RECT  2.16 51.705 101.898 51.975 ;
     RECT  2.16 52.245 101.898 52.515 ;
     RECT  2.16 52.785 101.898 53.055 ;
     RECT  2.16 53.325 101.898 53.595 ;
     RECT  2.16 53.865 101.898 54.135 ;
     RECT  2.16 54.405 101.898 54.675 ;
     RECT  2.16 54.945 101.898 55.215 ;
     RECT  2.16 55.485 101.898 55.755 ;
     RECT  2.16 56.025 101.898 56.295 ;
     RECT  2.16 56.565 101.898 56.835 ;
     RECT  2.16 57.105 101.898 57.375 ;
     RECT  2.16 57.645 101.898 57.915 ;
     RECT  2.16 58.185 101.898 58.455 ;
     RECT  2.16 58.725 101.898 58.995 ;
     RECT  2.16 59.265 101.898 59.535 ;
     RECT  2.16 59.805 101.898 60.075 ;
     RECT  2.16 60.345 101.898 60.615 ;
     RECT  2.16 60.885 101.898 61.155 ;
     RECT  2.16 61.425 101.898 61.695 ;
     RECT  2.16 61.965 101.898 62.235 ;
     RECT  2.16 62.505 101.898 62.775 ;
     RECT  2.16 63.045 101.898 63.315 ;
     RECT  2.16 63.585 101.898 63.855 ;
     RECT  2.16 64.125 101.898 64.395 ;
     RECT  2.16 64.665 101.898 64.935 ;
     RECT  2.16 65.205 101.898 65.475 ;
     RECT  2.16 65.745 101.898 66.015 ;
     RECT  2.16 66.285 101.898 66.555 ;
     RECT  2.16 66.825 101.898 67.095 ;
     RECT  2.16 67.365 101.898 67.635 ;
     RECT  2.16 67.905 101.898 68.175 ;
     RECT  2.16 68.445 101.898 68.715 ;
     RECT  2.16 68.985 101.898 69.255 ;
     RECT  2.16 69.525 101.898 69.795 ;
     RECT  2.16 70.065 101.898 70.335 ;
     RECT  2.16 70.605 101.898 70.875 ;
     RECT  2.16 71.145 101.898 71.415 ;
     RECT  2.16 71.685 101.898 71.955 ;
     RECT  2.16 72.225 101.898 72.495 ;
     RECT  2.16 72.765 101.898 73.035 ;
     RECT  2.16 73.305 101.898 73.575 ;
     RECT  2.16 73.845 101.898 74.115 ;
     RECT  2.16 74.385 101.898 74.655 ;
     RECT  2.16 74.925 101.898 75.195 ;
     RECT  2.16 75.465 101.898 75.735 ;
     RECT  2.16 76.005 101.898 76.275 ;
     RECT  2.16 76.545 101.898 76.815 ;
     RECT  2.16 77.085 101.898 77.355 ;
     RECT  2.16 77.625 101.898 77.895 ;
     RECT  2.16 78.165 101.898 78.435 ;
     RECT  2.16 78.705 101.898 78.975 ;
     RECT  2.16 79.245 101.898 79.515 ;
     RECT  2.16 79.785 101.898 80.055 ;
     RECT  2.16 80.325 101.898 80.595 ;
     RECT  2.16 80.865 101.898 81.135 ;
     RECT  2.16 81.405 101.898 81.675 ;
     RECT  2.16 81.945 101.898 82.215 ;
     RECT  2.16 82.485 101.898 82.755 ;
     RECT  2.16 83.025 101.898 83.295 ;
     RECT  2.16 83.565 101.898 83.835 ;
     RECT  2.16 84.105 101.898 84.375 ;
     RECT  2.16 84.645 101.898 84.915 ;
     RECT  2.16 85.185 101.898 85.455 ;
     RECT  2.16 85.725 101.898 85.995 ;
     RECT  2.16 86.265 101.898 86.535 ;
     RECT  2.16 86.805 101.898 87.075 ;
     RECT  2.16 87.345 101.898 87.615 ;
     RECT  2.16 87.885 101.898 88.155 ;
     RECT  2.16 88.425 101.898 88.695 ;
     RECT  2.16 88.965 101.898 89.235 ;
     RECT  2.16 89.505 101.898 89.775 ;
     RECT  2.16 90.045 101.898 90.315 ;
     RECT  2.16 90.585 101.898 90.855 ;
     RECT  2.16 91.125 101.898 91.395 ;
     RECT  2.16 91.665 101.898 91.935 ;
     RECT  2.16 92.205 101.898 92.475 ;
     RECT  2.16 92.745 101.898 93.015 ;
     RECT  2.16 93.285 101.898 93.555 ;
     RECT  2.16 93.825 101.898 94.095 ;
     RECT  2.16 94.365 101.898 94.635 ;
     RECT  2.16 94.905 101.898 95.175 ;
     RECT  2.16 95.445 101.898 95.715 ;
     RECT  2.16 95.985 101.898 96.255 ;
     RECT  2.16 96.525 101.898 96.795 ;
     RECT  2.16 97.065 101.898 97.335 ;
     RECT  2.16 97.605 101.898 97.875 ;
     RECT  2.16 98.145 101.898 98.415 ;
     RECT  2.16 98.685 101.898 98.955 ;
     RECT  2.16 99.225 101.898 99.495 ;
     RECT  2.16 99.765 101.898 100.035 ;
     RECT  2.16 100.305 101.898 100.575 ;
     RECT  2.16 100.845 101.898 101.115 ;
     RECT  2.16 101.385 101.898 101.655 ;
     RECT  2.16 101.925 101.898 102.195 ;
     RECT  2.16 102.465 101.898 102.735 ;
     RECT  2.16 103.005 101.898 103.275 ;
    LAYER RVTP ;
     RECT  2.16 2.295 101.898 2.565 ;
     RECT  2.16 2.835 101.898 3.105 ;
     RECT  2.16 3.375 101.898 3.645 ;
     RECT  2.16 3.915 101.898 4.185 ;
     RECT  2.16 4.455 101.898 4.725 ;
     RECT  2.16 4.995 101.898 5.265 ;
     RECT  2.16 5.535 101.898 5.805 ;
     RECT  2.16 6.075 101.898 6.345 ;
     RECT  2.16 6.615 101.898 6.885 ;
     RECT  2.16 7.155 101.898 7.425 ;
     RECT  2.16 7.695 101.898 7.965 ;
     RECT  2.16 8.235 101.898 8.505 ;
     RECT  2.16 8.775 101.898 9.045 ;
     RECT  2.16 9.315 101.898 9.585 ;
     RECT  2.16 9.855 101.898 10.125 ;
     RECT  2.16 10.395 101.898 10.665 ;
     RECT  2.16 10.935 101.898 11.205 ;
     RECT  2.16 11.475 101.898 11.745 ;
     RECT  2.16 12.015 101.898 12.285 ;
     RECT  2.16 12.555 101.898 12.825 ;
     RECT  2.16 13.095 101.898 13.365 ;
     RECT  2.16 13.635 101.898 13.905 ;
     RECT  2.16 14.175 101.898 14.445 ;
     RECT  2.16 14.715 101.898 14.985 ;
     RECT  2.16 15.255 101.898 15.525 ;
     RECT  2.16 15.795 101.898 16.065 ;
     RECT  2.16 16.335 101.898 16.605 ;
     RECT  2.16 16.875 101.898 17.145 ;
     RECT  2.16 17.415 101.898 17.685 ;
     RECT  2.16 17.955 101.898 18.225 ;
     RECT  2.16 18.495 101.898 18.765 ;
     RECT  2.16 19.035 101.898 19.305 ;
     RECT  2.16 19.575 101.898 19.845 ;
     RECT  2.16 20.115 101.898 20.385 ;
     RECT  2.16 20.655 101.898 20.925 ;
     RECT  2.16 21.195 101.898 21.465 ;
     RECT  2.16 21.735 101.898 22.005 ;
     RECT  2.16 22.275 101.898 22.545 ;
     RECT  2.16 22.815 101.898 23.085 ;
     RECT  2.16 23.355 101.898 23.625 ;
     RECT  2.16 23.895 101.898 24.165 ;
     RECT  2.16 24.435 101.898 24.705 ;
     RECT  2.16 24.975 101.898 25.245 ;
     RECT  2.16 25.515 101.898 25.785 ;
     RECT  2.16 26.055 101.898 26.325 ;
     RECT  2.16 26.595 101.898 26.865 ;
     RECT  2.16 27.135 101.898 27.405 ;
     RECT  2.16 27.675 101.898 27.945 ;
     RECT  2.16 28.215 101.898 28.485 ;
     RECT  2.16 28.755 101.898 29.025 ;
     RECT  2.16 29.295 101.898 29.565 ;
     RECT  2.16 29.835 101.898 30.105 ;
     RECT  2.16 30.375 101.898 30.645 ;
     RECT  2.16 30.915 101.898 31.185 ;
     RECT  2.16 31.455 101.898 31.725 ;
     RECT  2.16 31.995 101.898 32.265 ;
     RECT  2.16 32.535 101.898 32.805 ;
     RECT  2.16 33.075 101.898 33.345 ;
     RECT  2.16 33.615 101.898 33.885 ;
     RECT  2.16 34.155 101.898 34.425 ;
     RECT  2.16 34.695 101.898 34.965 ;
     RECT  2.16 35.235 101.898 35.505 ;
     RECT  2.16 35.775 101.898 36.045 ;
     RECT  2.16 36.315 101.898 36.585 ;
     RECT  2.16 36.855 101.898 37.125 ;
     RECT  2.16 37.395 101.898 37.665 ;
     RECT  2.16 37.935 101.898 38.205 ;
     RECT  2.16 38.475 101.898 38.745 ;
     RECT  2.16 39.015 101.898 39.285 ;
     RECT  2.16 39.555 101.898 39.825 ;
     RECT  2.16 40.095 101.898 40.365 ;
     RECT  2.16 40.635 101.898 40.905 ;
     RECT  2.16 41.175 101.898 41.445 ;
     RECT  2.16 41.715 101.898 41.985 ;
     RECT  2.16 42.255 101.898 42.525 ;
     RECT  2.16 42.795 101.898 43.065 ;
     RECT  2.16 43.335 101.898 43.605 ;
     RECT  2.16 43.875 101.898 44.145 ;
     RECT  2.16 44.415 101.898 44.685 ;
     RECT  2.16 44.955 101.898 45.225 ;
     RECT  2.16 45.495 101.898 45.765 ;
     RECT  2.16 46.035 101.898 46.305 ;
     RECT  2.16 46.575 101.898 46.845 ;
     RECT  2.16 47.115 101.898 47.385 ;
     RECT  2.16 47.655 101.898 47.925 ;
     RECT  2.16 48.195 101.898 48.465 ;
     RECT  2.16 48.735 101.898 49.005 ;
     RECT  2.16 49.275 101.898 49.545 ;
     RECT  2.16 49.815 101.898 50.085 ;
     RECT  2.16 50.355 101.898 50.625 ;
     RECT  2.16 50.895 101.898 51.165 ;
     RECT  2.16 51.435 101.898 51.705 ;
     RECT  2.16 51.975 101.898 52.245 ;
     RECT  2.16 52.515 101.898 52.785 ;
     RECT  2.16 53.055 101.898 53.325 ;
     RECT  2.16 53.595 101.898 53.865 ;
     RECT  2.16 54.135 101.898 54.405 ;
     RECT  2.16 54.675 101.898 54.945 ;
     RECT  2.16 55.215 101.898 55.485 ;
     RECT  2.16 55.755 101.898 56.025 ;
     RECT  2.16 56.295 101.898 56.565 ;
     RECT  2.16 56.835 101.898 57.105 ;
     RECT  2.16 57.375 101.898 57.645 ;
     RECT  2.16 57.915 101.898 58.185 ;
     RECT  2.16 58.455 101.898 58.725 ;
     RECT  2.16 58.995 101.898 59.265 ;
     RECT  2.16 59.535 101.898 59.805 ;
     RECT  2.16 60.075 101.898 60.345 ;
     RECT  2.16 60.615 101.898 60.885 ;
     RECT  2.16 61.155 101.898 61.425 ;
     RECT  2.16 61.695 101.898 61.965 ;
     RECT  2.16 62.235 101.898 62.505 ;
     RECT  2.16 62.775 101.898 63.045 ;
     RECT  2.16 63.315 101.898 63.585 ;
     RECT  2.16 63.855 101.898 64.125 ;
     RECT  2.16 64.395 101.898 64.665 ;
     RECT  2.16 64.935 101.898 65.205 ;
     RECT  2.16 65.475 101.898 65.745 ;
     RECT  2.16 66.015 101.898 66.285 ;
     RECT  2.16 66.555 101.898 66.825 ;
     RECT  2.16 67.095 101.898 67.365 ;
     RECT  2.16 67.635 101.898 67.905 ;
     RECT  2.16 68.175 101.898 68.445 ;
     RECT  2.16 68.715 101.898 68.985 ;
     RECT  2.16 69.255 101.898 69.525 ;
     RECT  2.16 69.795 101.898 70.065 ;
     RECT  2.16 70.335 101.898 70.605 ;
     RECT  2.16 70.875 101.898 71.145 ;
     RECT  2.16 71.415 101.898 71.685 ;
     RECT  2.16 71.955 101.898 72.225 ;
     RECT  2.16 72.495 101.898 72.765 ;
     RECT  2.16 73.035 101.898 73.305 ;
     RECT  2.16 73.575 101.898 73.845 ;
     RECT  2.16 74.115 101.898 74.385 ;
     RECT  2.16 74.655 101.898 74.925 ;
     RECT  2.16 75.195 101.898 75.465 ;
     RECT  2.16 75.735 101.898 76.005 ;
     RECT  2.16 76.275 101.898 76.545 ;
     RECT  2.16 76.815 101.898 77.085 ;
     RECT  2.16 77.355 101.898 77.625 ;
     RECT  2.16 77.895 101.898 78.165 ;
     RECT  2.16 78.435 101.898 78.705 ;
     RECT  2.16 78.975 101.898 79.245 ;
     RECT  2.16 79.515 101.898 79.785 ;
     RECT  2.16 80.055 101.898 80.325 ;
     RECT  2.16 80.595 101.898 80.865 ;
     RECT  2.16 81.135 101.898 81.405 ;
     RECT  2.16 81.675 101.898 81.945 ;
     RECT  2.16 82.215 101.898 82.485 ;
     RECT  2.16 82.755 101.898 83.025 ;
     RECT  2.16 83.295 101.898 83.565 ;
     RECT  2.16 83.835 101.898 84.105 ;
     RECT  2.16 84.375 101.898 84.645 ;
     RECT  2.16 84.915 101.898 85.185 ;
     RECT  2.16 85.455 101.898 85.725 ;
     RECT  2.16 85.995 101.898 86.265 ;
     RECT  2.16 86.535 101.898 86.805 ;
     RECT  2.16 87.075 101.898 87.345 ;
     RECT  2.16 87.615 101.898 87.885 ;
     RECT  2.16 88.155 101.898 88.425 ;
     RECT  2.16 88.695 101.898 88.965 ;
     RECT  2.16 89.235 101.898 89.505 ;
     RECT  2.16 89.775 101.898 90.045 ;
     RECT  2.16 90.315 101.898 90.585 ;
     RECT  2.16 90.855 101.898 91.125 ;
     RECT  2.16 91.395 101.898 91.665 ;
     RECT  2.16 91.935 101.898 92.205 ;
     RECT  2.16 92.475 101.898 92.745 ;
     RECT  2.16 93.015 101.898 93.285 ;
     RECT  2.16 93.555 101.898 93.825 ;
     RECT  2.16 94.095 101.898 94.365 ;
     RECT  2.16 94.635 101.898 94.905 ;
     RECT  2.16 95.175 101.898 95.445 ;
     RECT  2.16 95.715 101.898 95.985 ;
     RECT  2.16 96.255 101.898 96.525 ;
     RECT  2.16 96.795 101.898 97.065 ;
     RECT  2.16 97.335 101.898 97.605 ;
     RECT  2.16 97.875 101.898 98.145 ;
     RECT  2.16 98.415 101.898 98.685 ;
     RECT  2.16 98.955 101.898 99.225 ;
     RECT  2.16 99.495 101.898 99.765 ;
     RECT  2.16 100.035 101.898 100.305 ;
     RECT  2.16 100.575 101.898 100.845 ;
     RECT  2.16 101.115 101.898 101.385 ;
     RECT  2.16 101.655 101.898 101.925 ;
     RECT  2.16 102.195 101.898 102.465 ;
     RECT  2.16 102.735 101.898 103.005 ;
     RECT  2.16 103.275 101.898 103.41 ;
    LAYER M1 ;
     RECT  2.16 2.151 101.898 103.419 ;
    LAYER M2 ;
     RECT  0.103 61.128 0.139 61.146 ;
     RECT  0.139 60.696 0.239 61.146 ;
     RECT  0.239 61.128 2.16 61.146 ;
     RECT  2.16 2.151 10.003 103.419 ;
     RECT  10.255 105.561 10.291 105.579 ;
     RECT  10.291 105.561 10.327 105.624 ;
     RECT  10.327 105.561 10.355 105.768 ;
     RECT  10.355 105.606 10.463 105.768 ;
     RECT  10.003 2.151 10.579 103.464 ;
     RECT  10.579 2.151 10.715 103.5 ;
     RECT  10.463 105.606 11.191 105.696 ;
     RECT  10.715 2.151 11.479 103.419 ;
     RECT  11.479 2.151 11.551 103.464 ;
     RECT  11.695 104.796 11.767 104.814 ;
     RECT  11.191 105.606 11.767 105.768 ;
     RECT  11.767 104.796 11.831 105.768 ;
     RECT  11.831 104.796 11.903 105.696 ;
     RECT  11.903 104.796 11.939 105.624 ;
     RECT  11.551 2.151 11.983 103.536 ;
     RECT  11.939 104.796 12.299 104.886 ;
     RECT  12.299 104.868 12.407 104.886 ;
     RECT  11.983 2.151 13.235 103.572 ;
     RECT  13.235 2.151 13.847 103.536 ;
     RECT  13.847 2.151 20.191 103.419 ;
     RECT  20.083 105.75 20.227 105.768 ;
     RECT  20.191 2.151 20.803 103.464 ;
     RECT  20.227 105.678 20.911 105.768 ;
     RECT  20.911 105.606 20.983 105.768 ;
     RECT  20.983 105.516 21.299 105.768 ;
     RECT  20.803 2.151 21.451 103.5 ;
     RECT  21.451 2.151 21.659 103.572 ;
     RECT  21.299 105.516 21.775 105.696 ;
     RECT  21.775 104.796 21.875 105.696 ;
     RECT  21.875 104.868 22.055 105.696 ;
     RECT  22.055 105.561 22.063 105.696 ;
     RECT  21.659 2.151 22.235 103.464 ;
     RECT  22.063 105.561 22.235 105.768 ;
     RECT  22.235 105.75 23.143 105.768 ;
     RECT  22.235 2.151 23.287 103.419 ;
     RECT  24.259 104.706 24.295 104.724 ;
     RECT  23.143 105.606 24.295 105.768 ;
     RECT  24.295 104.706 24.395 105.768 ;
     RECT  24.395 104.706 24.467 104.814 ;
     RECT  24.395 105.606 24.467 105.768 ;
     RECT  24.467 105.642 24.503 105.768 ;
     RECT  23.287 2.151 25.907 103.77 ;
     RECT  24.503 105.75 26.231 105.768 ;
     RECT  25.907 2.151 26.591 103.608 ;
     RECT  26.591 2.151 32.467 103.419 ;
     RECT  37.075 105.75 37.111 105.768 ;
     RECT  37.075 104.868 37.255 104.886 ;
     RECT  37.111 105.714 37.255 105.768 ;
     RECT  37.255 104.796 37.355 104.886 ;
     RECT  37.355 104.868 37.615 104.886 ;
     RECT  37.255 105.678 37.615 105.768 ;
     RECT  32.467 2.151 37.687 103.464 ;
     RECT  37.687 2.151 38.011 103.5 ;
     RECT  37.615 104.868 38.543 105.768 ;
     RECT  38.543 105.606 38.723 105.768 ;
     RECT  38.723 105.714 39.047 105.768 ;
     RECT  39.047 105.75 39.083 105.768 ;
     RECT  38.011 2.151 40.883 103.536 ;
     RECT  41.251 105.75 41.395 105.768 ;
     RECT  41.395 105.678 41.611 105.768 ;
     RECT  41.611 105.606 41.755 105.768 ;
     RECT  41.755 105.561 41.791 105.768 ;
     RECT  41.791 105.516 41.891 105.768 ;
     RECT  41.891 105.561 42.871 105.768 ;
     RECT  42.871 105.444 43.151 105.768 ;
     RECT  43.151 105.516 43.187 105.768 ;
     RECT  43.187 105.642 43.259 105.768 ;
     RECT  43.259 105.642 43.295 105.66 ;
     RECT  40.883 2.151 43.375 103.419 ;
     RECT  43.375 2.151 43.871 103.464 ;
     RECT  46.363 105.75 46.687 105.768 ;
     RECT  46.687 105.678 46.795 105.768 ;
     RECT  46.795 105.606 46.939 105.768 ;
     RECT  43.871 2.151 47.371 103.419 ;
     RECT  47.371 2.151 47.723 103.734 ;
     RECT  46.939 105.561 48.091 105.768 ;
     RECT  47.723 2.151 48.451 103.464 ;
     RECT  48.451 2.151 48.587 103.5 ;
     RECT  48.091 105.516 48.947 105.768 ;
     RECT  48.947 105.561 49.019 105.768 ;
     RECT  49.019 105.606 49.891 105.768 ;
     RECT  49.891 105.516 50.099 105.768 ;
     RECT  50.099 105.561 50.135 105.768 ;
     RECT  50.135 105.606 50.819 105.768 ;
     RECT  50.819 105.642 51.107 105.768 ;
     RECT  51.107 105.75 51.179 105.768 ;
     RECT  48.587 2.151 52.627 103.464 ;
     RECT  52.627 2.151 53.231 103.536 ;
     RECT  53.231 2.151 55.471 103.419 ;
     RECT  55.471 2.151 57.551 103.464 ;
     RECT  57.551 2.151 58.819 103.419 ;
     RECT  58.819 2.151 60.251 103.464 ;
     RECT  60.251 2.151 65.155 103.419 ;
     RECT  65.155 2.151 65.623 103.464 ;
     RECT  65.623 105.75 65.695 105.768 ;
     RECT  65.695 105.606 66.271 105.768 ;
     RECT  66.271 105.561 66.559 105.768 ;
     RECT  66.559 104.868 66.739 105.768 ;
     RECT  66.739 104.751 66.983 105.768 ;
     RECT  66.983 104.868 67.055 105.768 ;
     RECT  67.055 105.372 67.235 105.768 ;
     RECT  67.235 105.606 68.503 105.768 ;
     RECT  68.503 105.516 68.575 105.768 ;
     RECT  68.575 104.868 68.711 105.768 ;
     RECT  68.711 105.48 68.783 105.768 ;
     RECT  65.623 2.151 69.107 103.536 ;
     RECT  68.783 105.48 69.619 105.696 ;
     RECT  69.619 105.444 69.755 105.768 ;
     RECT  69.755 105.444 69.979 105.696 ;
     RECT  69.979 104.868 70.007 105.696 ;
     RECT  70.007 104.868 70.043 105.579 ;
     RECT  70.043 104.868 70.115 105.534 ;
     RECT  69.107 2.151 70.699 103.464 ;
     RECT  70.115 104.868 71.123 104.886 ;
     RECT  70.699 2.151 76.999 103.608 ;
     RECT  77.611 104.796 77.647 104.886 ;
     RECT  77.647 104.796 77.683 105.579 ;
     RECT  77.683 104.751 77.755 105.579 ;
     RECT  77.755 104.751 77.855 105.768 ;
     RECT  77.855 104.868 77.927 105.768 ;
     RECT  78.691 104.706 78.763 104.724 ;
     RECT  77.927 105.561 78.763 105.768 ;
     RECT  78.763 104.706 79.187 105.768 ;
     RECT  79.187 104.796 79.223 105.768 ;
     RECT  79.223 104.796 79.951 104.814 ;
     RECT  79.223 105.561 79.951 105.768 ;
     RECT  79.951 104.796 80.051 105.768 ;
     RECT  80.051 105.516 80.267 105.768 ;
     RECT  80.267 105.561 80.843 105.768 ;
     RECT  76.999 2.151 80.887 103.644 ;
     RECT  80.843 105.606 81.347 105.768 ;
     RECT  80.887 2.151 81.887 103.689 ;
     RECT  81.347 105.714 82.075 105.768 ;
     RECT  82.075 105.606 82.255 105.768 ;
     RECT  82.255 105.561 82.939 105.768 ;
     RECT  82.939 104.751 83.219 105.768 ;
     RECT  81.887 2.151 83.659 103.536 ;
     RECT  83.219 104.796 84.011 105.768 ;
     RECT  83.659 2.151 84.055 103.572 ;
     RECT  84.055 2.151 84.343 103.644 ;
     RECT  84.011 104.796 84.343 104.886 ;
     RECT  84.343 104.751 84.443 104.886 ;
     RECT  84.011 105.678 84.587 105.768 ;
     RECT  84.587 105.678 84.659 105.696 ;
     RECT  84.343 2.151 86.459 103.689 ;
     RECT  86.459 2.151 87.143 103.644 ;
     RECT  87.143 2.151 101.898 103.419 ;
     RECT  101.898 70.65 102.011 78.966 ;
     RECT  101.898 24.678 102.047 34.524 ;
     RECT  101.898 41.22 102.047 41.238 ;
     RECT  101.898 42.264 102.047 52.038 ;
     RECT  102.011 70.65 102.047 77.958 ;
     RECT  102.047 42.336 102.083 52.038 ;
     RECT  101.898 65.376 102.083 65.394 ;
     RECT  102.047 76.05 102.083 77.958 ;
     RECT  102.083 46.701 102.119 52.038 ;
     RECT  101.898 53.1 102.227 57.438 ;
     RECT  102.011 78.948 102.299 78.966 ;
     RECT  102.047 24.678 102.371 29.052 ;
     RECT  101.898 66.564 102.371 69.354 ;
     RECT  102.083 42.336 102.407 45.828 ;
     RECT  102.047 29.808 102.551 34.524 ;
     RECT  102.083 76.554 102.551 77.958 ;
     RECT  102.371 24.75 102.587 29.052 ;
     RECT  102.551 29.808 102.587 32.904 ;
     RECT  102.551 33.696 102.587 34.524 ;
     RECT  102.227 53.676 102.587 57.438 ;
     RECT  101.898 23.706 102.623 23.724 ;
     RECT  102.587 29.808 102.623 32.094 ;
     RECT  102.587 32.886 102.623 32.904 ;
     RECT  101.898 35.856 102.623 37.962 ;
     RECT  102.407 42.336 102.623 43.434 ;
     RECT  102.047 70.65 102.623 75.024 ;
     RECT  102.551 76.554 102.623 77.724 ;
     RECT  101.898 83.61 102.623 86.904 ;
     RECT  102.587 24.75 102.659 28.854 ;
     RECT  102.623 37.098 102.659 37.962 ;
     RECT  102.119 47.466 102.659 52.038 ;
     RECT  101.898 62.478 102.659 64.188 ;
     RECT  102.371 66.564 102.659 68.238 ;
     RECT  102.407 44.226 102.695 45.828 ;
     RECT  102.623 76.554 102.695 77.688 ;
     RECT  102.119 46.701 102.731 46.719 ;
     RECT  102.623 70.65 102.731 73.908 ;
     RECT  102.695 76.554 102.731 77.382 ;
     RECT  102.623 84.006 102.731 86.796 ;
     RECT  102.731 70.956 102.803 73.908 ;
     RECT  102.659 24.75 102.875 25.776 ;
     RECT  102.623 35.856 102.875 36.27 ;
     RECT  101.898 59.004 102.875 61.488 ;
     RECT  102.623 29.808 102.911 31.554 ;
     RECT  102.659 26.838 102.947 28.854 ;
     RECT  102.587 53.91 102.947 57.438 ;
     RECT  102.947 54.216 102.983 57.438 ;
     RECT  102.659 47.898 103.019 52.038 ;
     RECT  102.875 59.004 103.019 61.452 ;
     RECT  102.623 42.498 103.055 43.434 ;
     RECT  103.055 42.498 103.127 43.164 ;
     RECT  102.659 66.834 103.163 68.238 ;
     RECT  102.803 70.956 103.163 71.208 ;
     RECT  102.947 27.918 103.199 28.854 ;
     RECT  102.911 30.15 103.199 31.554 ;
     RECT  102.587 33.966 103.199 33.984 ;
     RECT  102.875 35.856 103.199 35.874 ;
     RECT  103.019 47.898 103.199 51.498 ;
     RECT  102.983 54.216 103.199 56.592 ;
     RECT  102.983 57.42 103.199 57.438 ;
     RECT  103.019 59.076 103.199 61.452 ;
     RECT  102.659 62.478 103.199 63.414 ;
     RECT  103.163 66.834 103.199 68.202 ;
     RECT  103.163 70.956 103.199 71.172 ;
     RECT  102.803 72.126 103.199 73.908 ;
     RECT  102.731 76.86 103.199 77.382 ;
     RECT  102.731 86.742 103.199 86.796 ;
     RECT  103.199 30.456 103.235 31.554 ;
     RECT  102.659 37.098 103.235 37.458 ;
     RECT  103.127 42.498 103.235 42.624 ;
     RECT  102.695 44.496 103.235 45.828 ;
     RECT  103.199 47.898 103.235 49.914 ;
     RECT  103.199 56.574 103.235 56.592 ;
     RECT  103.199 59.076 103.235 60.138 ;
     RECT  103.199 63.396 103.235 63.414 ;
     RECT  103.199 67.104 103.235 68.004 ;
     RECT  103.199 71.154 103.235 71.172 ;
     RECT  103.199 72.234 103.235 73.134 ;
     RECT  102.731 84.006 103.235 85.986 ;
     RECT  103.199 28.296 103.271 28.854 ;
     RECT  103.235 37.098 103.271 37.116 ;
     RECT  103.235 42.606 103.271 42.624 ;
     RECT  103.235 45 103.271 45.828 ;
     RECT  103.199 50.706 103.271 51.156 ;
     RECT  103.199 54.216 103.271 55.548 ;
     RECT  102.659 64.17 103.271 64.188 ;
     RECT  103.235 67.608 103.271 67.626 ;
     RECT  103.199 73.89 103.271 73.908 ;
     RECT  103.235 84.15 103.271 84.474 ;
     RECT  103.235 85.464 103.271 85.482 ;
     RECT  103.271 54.216 103.307 54.936 ;
     RECT  103.235 72.306 103.307 72.324 ;
     RECT  103.307 54.216 103.343 54.234 ;
     RECT  103.271 45.198 103.739 45.828 ;
     RECT  103.235 47.898 103.775 49.302 ;
     RECT  103.775 48.744 103.811 49.302 ;
     RECT  103.811 48.78 103.847 49.302 ;
     RECT  102.875 25.02 103.883 25.776 ;
     RECT  103.847 48.78 103.883 49.068 ;
     RECT  102.371 69.066 103.883 69.354 ;
     RECT  103.271 28.296 103.919 28.314 ;
     RECT  103.739 45.198 103.919 45.792 ;
     RECT  103.775 47.898 103.919 47.916 ;
     RECT  103.271 51.138 103.919 51.156 ;
     RECT  103.199 62.478 103.919 62.568 ;
     RECT  103.883 69.264 103.919 69.354 ;
     RECT  103.883 49.05 103.955 49.068 ;
     RECT  103.235 59.076 103.955 59.832 ;
     RECT  103.199 86.778 103.955 86.796 ;
     RECT  103.927 22.824 103.963 22.842 ;
     RECT  103.235 30.888 103.963 31.554 ;
     RECT  103.963 30.69 103.991 31.554 ;
     RECT  103.955 59.076 103.991 59.094 ;
     RECT  103.919 69.264 103.991 69.282 ;
     RECT  103.199 76.86 103.991 76.878 ;
     RECT  103.963 22.752 104.027 22.842 ;
     RECT  102.947 26.838 104.027 26.856 ;
     RECT  103.891 56.691 104.027 56.709 ;
     RECT  103.199 61.434 104.027 61.452 ;
     RECT  104.027 22.752 104.063 22.77 ;
     RECT  103.883 25.02 104.063 25.038 ;
     RECT  103.991 30.69 104.063 30.708 ;
     RECT  103.991 31.536 104.063 31.554 ;
     RECT  103.963 42.732 104.063 42.75 ;
     RECT  103.919 45.198 104.063 45.414 ;
     RECT  103.963 52.371 104.063 52.389 ;
     RECT  103.919 62.55 104.063 62.568 ;
    LAYER M3 ;
     RECT  2.415 2.143 2.505 2.413 ;
     RECT  5.115 2.143 5.205 2.413 ;
     RECT  7.815 2.143 7.905 2.413 ;
     RECT  10.515 2.143 10.605 2.413 ;
     RECT  13.215 2.143 13.305 2.413 ;
     RECT  15.915 2.143 16.005 2.413 ;
     RECT  18.615 2.143 18.705 2.413 ;
     RECT  21.315 2.143 21.405 2.413 ;
     RECT  24.015 2.143 24.105 2.413 ;
     RECT  26.715 2.143 26.805 2.413 ;
     RECT  29.415 2.143 29.505 2.413 ;
     RECT  32.115 2.143 32.205 2.413 ;
     RECT  34.815 2.143 34.905 2.413 ;
     RECT  37.515 2.143 37.605 2.413 ;
     RECT  40.215 2.143 40.305 2.413 ;
     RECT  42.915 2.143 43.005 2.413 ;
     RECT  45.615 2.143 45.705 2.413 ;
     RECT  48.315 2.143 48.405 2.413 ;
     RECT  51.015 2.143 51.105 2.413 ;
     RECT  53.715 2.143 53.805 2.413 ;
     RECT  56.415 2.143 56.505 2.413 ;
     RECT  59.115 2.143 59.205 2.413 ;
     RECT  61.815 2.143 61.905 2.413 ;
     RECT  64.515 2.143 64.605 2.413 ;
     RECT  67.215 2.143 67.305 2.413 ;
     RECT  69.915 2.143 70.005 2.413 ;
     RECT  72.615 2.143 72.705 2.413 ;
     RECT  75.315 2.143 75.405 2.413 ;
     RECT  78.015 2.143 78.105 2.413 ;
     RECT  80.715 2.143 80.805 2.413 ;
     RECT  83.415 2.143 83.505 2.413 ;
     RECT  86.115 2.143 86.205 2.413 ;
     RECT  88.815 2.143 88.905 2.413 ;
     RECT  91.515 2.143 91.605 2.413 ;
     RECT  94.215 2.143 94.305 2.413 ;
     RECT  96.915 2.143 97.005 2.413 ;
     RECT  99.615 2.143 99.705 2.413 ;
     RECT  101.736 20.011 101.754 20.203 ;
     RECT  80.715 2.413 80.997 20.317 ;
     RECT  94.215 2.413 94.497 20.353 ;
     RECT  102.6 20.107 102.618 20.395 ;
     RECT  94.215 20.353 94.662 20.551 ;
     RECT  80.715 20.317 81.522 20.579 ;
     RECT  86.115 2.413 86.397 20.587 ;
     RECT  86.115 20.587 86.634 20.687 ;
     RECT  101.484 20.203 101.754 20.779 ;
     RECT  102.6 20.395 102.906 20.779 ;
     RECT  101.484 20.779 102.906 21.067 ;
     RECT  99.615 2.413 99.897 21.355 ;
     RECT  99.615 21.355 99.99 21.451 ;
     RECT  101.16 21.067 102.906 21.451 ;
     RECT  98.928 21.451 99.99 21.485 ;
     RECT  103.968 19.915 103.986 21.643 ;
     RECT  101.16 21.451 102.978 21.835 ;
     RECT  103.932 21.643 103.986 22.027 ;
     RECT  103.86 22.027 103.986 22.747 ;
     RECT  98.928 21.485 99.897 22.843 ;
     RECT  96.915 2.413 97.197 22.987 ;
     RECT  96.915 22.987 97.29 23.117 ;
     RECT  98.604 22.843 99.897 23.275 ;
     RECT  88.815 2.413 89.097 23.419 ;
     RECT  88.815 23.419 89.19 23.563 ;
     RECT  100.728 21.835 102.978 23.563 ;
     RECT  88.164 23.563 89.19 23.597 ;
     RECT  90.648 23.419 90.666 23.597 ;
     RECT  88.164 23.597 89.097 23.899 ;
     RECT  98.316 23.275 99.897 23.947 ;
     RECT  100.62 23.563 102.978 23.947 ;
     RECT  87.552 23.899 89.097 24.139 ;
     RECT  86.115 20.687 86.397 24.187 ;
     RECT  87.228 24.139 89.097 24.187 ;
     RECT  96.915 23.117 97.197 24.232 ;
     RECT  96.804 24.232 97.197 24.331 ;
     RECT  96.804 24.331 97.47 24.809 ;
     RECT  103.86 22.747 104.058 25.043 ;
     RECT  98.316 23.947 102.978 25.313 ;
     RECT  86.115 24.187 89.097 25.435 ;
     RECT  86.115 25.435 89.19 25.531 ;
     RECT  90.648 25.435 90.666 25.613 ;
     RECT  92.916 25.051 92.934 25.745 ;
     RECT  103.86 25.043 104.022 25.781 ;
     RECT  96.915 24.809 97.47 26.023 ;
     RECT  98.316 25.313 102.942 26.023 ;
     RECT  94.215 20.551 95.13 26.779 ;
     RECT  96.156 25.411 96.174 26.779 ;
     RECT  96.915 26.023 102.942 26.779 ;
     RECT  96.156 26.779 102.942 26.827 ;
     RECT  103.896 25.781 104.022 26.827 ;
     RECT  96.156 26.827 104.022 26.861 ;
     RECT  91.515 2.413 91.797 26.875 ;
     RECT  92.952 26.827 92.97 26.875 ;
     RECT  96.156 26.861 103.914 27.101 ;
     RECT  94.215 26.779 95.31 27.103 ;
     RECT  96.156 27.101 101.934 27.103 ;
     RECT  91.515 26.875 92.97 27.175 ;
     RECT  94.215 27.103 101.934 27.175 ;
     RECT  69.156 25.681 69.174 27.301 ;
     RECT  69.915 2.413 70.197 27.301 ;
     RECT  90.648 27.163 90.666 27.341 ;
     RECT  51.015 2.413 51.297 27.571 ;
     RECT  69.156 27.301 70.197 27.635 ;
     RECT  102.852 27.101 103.914 27.691 ;
     RECT  91.515 27.175 101.934 28.075 ;
     RECT  102.852 27.691 103.986 28.075 ;
     RECT  76.536 20.461 76.554 28.175 ;
     RECT  86.115 25.531 89.298 28.489 ;
     RECT  69.372 27.635 70.197 28.651 ;
     RECT  91.515 28.075 103.986 28.759 ;
     RECT  91.404 28.759 103.986 28.859 ;
     RECT  72.615 2.413 72.897 28.993 ;
     RECT  34.815 2.413 35.097 29.461 ;
     RECT  75.315 2.413 75.597 29.461 ;
     RECT  86.115 28.489 89.622 29.467 ;
     RECT  90.648 29.227 90.666 29.467 ;
     RECT  86.115 29.467 90.666 29.497 ;
     RECT  91.404 28.859 103.23 29.497 ;
     RECT  51.015 27.571 51.822 29.525 ;
     RECT  74.988 29.461 75.597 29.731 ;
     RECT  76.608 28.291 76.626 29.803 ;
     RECT  69.372 28.651 70.254 30.001 ;
     RECT  74.34 29.731 75.597 30.073 ;
     RECT  72.615 28.993 73.098 30.109 ;
     RECT  69.372 30.001 70.362 30.271 ;
     RECT  74.34 30.073 75.654 30.343 ;
     RECT  78.015 2.413 78.297 30.451 ;
     RECT  86.115 29.497 103.23 30.479 ;
     RECT  68.868 30.271 70.362 30.605 ;
     RECT  71.64 29.191 71.658 30.613 ;
     RECT  103.968 28.859 103.986 30.667 ;
     RECT  103.932 30.667 103.986 30.685 ;
     RECT  86.115 30.479 103.194 30.713 ;
     RECT  78.015 30.451 78.498 30.811 ;
     RECT  76.536 29.803 76.626 30.847 ;
     RECT  103.932 30.685 104.058 30.911 ;
     RECT  76.392 30.847 76.626 30.955 ;
     RECT  34.272 29.461 35.097 31.145 ;
     RECT  103.968 30.911 104.058 31.217 ;
     RECT  76.392 30.955 77.202 31.351 ;
     RECT  78.015 30.811 78.534 31.351 ;
     RECT  80.715 20.579 80.997 31.387 ;
     RECT  93.744 30.713 103.194 31.487 ;
     RECT  93.744 31.487 102.726 31.523 ;
     RECT  104.04 31.217 104.058 31.559 ;
     RECT  71.244 30.613 71.658 31.621 ;
     RECT  71.244 31.621 71.694 31.729 ;
     RECT  72.576 30.109 73.098 31.729 ;
     RECT  74.124 30.343 75.654 31.729 ;
     RECT  76.392 31.351 78.534 31.729 ;
     RECT  53.715 2.413 53.997 31.891 ;
     RECT  74.124 31.729 78.534 32.161 ;
     RECT  86.115 30.713 93.006 32.161 ;
     RECT  93.744 31.523 102.618 32.161 ;
     RECT  86.115 32.161 102.618 32.269 ;
     RECT  48.315 2.413 48.597 32.305 ;
     RECT  69.915 30.605 70.362 32.305 ;
     RECT  71.244 31.729 73.098 32.305 ;
     RECT  60.552 31.801 60.57 32.341 ;
     RECT  80.715 31.387 81.27 32.341 ;
     RECT  82.656 32.269 82.674 32.341 ;
     RECT  83.415 2.413 83.697 32.341 ;
     RECT  85.968 32.269 102.618 32.341 ;
     RECT  60.552 32.341 60.858 32.431 ;
     RECT  61.815 2.413 62.097 32.431 ;
     RECT  79.452 30.577 79.47 32.431 ;
     RECT  82.656 32.341 83.697 32.459 ;
     RECT  85.896 32.341 102.618 32.459 ;
     RECT  69.915 32.305 73.098 32.495 ;
     RECT  85.896 32.459 92.97 32.495 ;
     RECT  60.552 32.431 62.097 32.575 ;
     RECT  60.552 32.575 62.622 32.611 ;
     RECT  67.215 2.413 67.497 32.611 ;
     RECT  71.244 32.495 73.098 32.611 ;
     RECT  67.215 32.611 67.554 32.729 ;
     RECT  82.656 32.459 82.674 32.729 ;
     RECT  85.896 32.495 92.718 32.729 ;
     RECT  51.015 29.525 51.297 32.737 ;
     RECT  48.315 32.305 48.798 32.765 ;
     RECT  71.244 32.611 73.386 32.801 ;
     RECT  46.872 32.773 46.89 32.809 ;
     RECT  60.552 32.611 62.73 32.845 ;
     RECT  80.715 32.341 81.846 32.845 ;
     RECT  46.8 32.809 46.89 32.873 ;
     RECT  83.415 32.459 83.697 32.881 ;
     RECT  46.8 32.873 46.818 32.909 ;
     RECT  102.528 32.459 102.618 33.067 ;
     RECT  50.724 32.737 51.297 33.071 ;
     RECT  54.72 32.971 54.738 33.071 ;
     RECT  71.244 32.801 73.314 33.071 ;
     RECT  69.915 32.495 70.362 33.241 ;
     RECT  71.244 33.071 72.897 33.241 ;
     RECT  93.744 32.459 101.754 33.305 ;
     RECT  93.744 33.305 95.634 33.313 ;
     RECT  83.415 32.881 83.754 33.349 ;
     RECT  85.932 32.729 92.718 33.385 ;
     RECT  93.528 33.313 95.634 33.413 ;
     RECT  85.932 33.385 92.754 33.547 ;
     RECT  60.552 32.845 62.91 33.583 ;
     RECT  67.215 32.729 67.497 33.691 ;
     RECT  82.8 33.349 83.754 33.781 ;
     RECT  96.66 33.305 101.754 33.835 ;
     RECT  102.528 33.067 103.194 33.835 ;
     RECT  79.452 32.431 79.794 33.845 ;
     RECT  24.015 2.413 24.297 33.889 ;
     RECT  67.215 33.691 67.806 33.889 ;
     RECT  82.8 33.781 84.366 33.953 ;
     RECT  23.976 33.889 24.297 33.961 ;
     RECT  25.056 33.889 25.074 33.961 ;
     RECT  52.092 30.541 52.11 33.961 ;
     RECT  67.176 33.889 67.806 33.961 ;
     RECT  96.66 33.835 103.194 33.989 ;
     RECT  52.092 33.961 52.218 34.079 ;
     RECT  52.092 34.079 52.11 34.115 ;
     RECT  45.615 2.413 45.897 34.159 ;
     RECT  67.176 33.961 67.95 34.187 ;
     RECT  23.976 33.961 25.074 34.231 ;
     RECT  32.115 2.413 32.397 34.231 ;
     RECT  69.915 33.241 72.897 34.231 ;
     RECT  74.124 32.161 78.642 34.231 ;
     RECT  49.932 34.087 49.95 34.259 ;
     RECT  68.868 30.605 68.886 34.321 ;
     RECT  69.915 34.231 73.026 34.321 ;
     RECT  74.124 34.231 78.678 34.349 ;
     RECT  23.976 34.231 25.362 34.357 ;
     RECT  26.715 2.413 26.997 34.393 ;
     RECT  51.015 33.071 51.297 34.393 ;
     RECT  56.415 2.413 56.697 34.393 ;
     RECT  57.744 33.043 57.762 34.393 ;
     RECT  79.776 33.845 79.794 34.393 ;
     RECT  80.532 32.845 81.846 34.393 ;
     RECT  93.744 33.413 95.634 34.411 ;
     RECT  23.976 34.357 25.398 34.465 ;
     RECT  26.208 34.393 26.997 34.465 ;
     RECT  68.868 34.321 73.026 34.465 ;
     RECT  74.124 34.349 78.642 34.465 ;
     RECT  50.724 34.393 51.297 34.493 ;
     RECT  34.38 31.145 35.097 34.501 ;
     RECT  37.515 2.413 37.797 34.501 ;
     RECT  59.115 2.413 59.397 34.501 ;
     RECT  65.736 32.881 65.754 34.501 ;
     RECT  68.868 34.465 78.642 34.619 ;
     RECT  65.7 34.501 65.754 34.627 ;
     RECT  93.744 34.411 95.742 34.651 ;
     RECT  96.66 33.989 102.87 34.651 ;
     RECT  74.124 34.619 78.642 34.655 ;
     RECT  45.615 34.159 46.098 34.663 ;
     RECT  60.552 33.583 63.27 34.663 ;
     RECT  56.415 34.393 57.762 34.699 ;
     RECT  58.716 34.501 59.397 34.699 ;
     RECT  82.8 33.953 84.33 34.699 ;
     RECT  23.976 34.465 26.997 34.735 ;
     RECT  74.232 34.655 78.642 34.763 ;
     RECT  27.9 34.735 27.918 34.771 ;
     RECT  82.8 34.699 84.582 34.771 ;
     RECT  23.904 34.735 26.997 34.781 ;
     RECT  60.48 34.663 63.27 34.799 ;
     RECT  65.7 34.627 65.79 34.861 ;
     RECT  27.9 34.771 28.53 34.897 ;
     RECT  29.415 2.413 29.697 34.897 ;
     RECT  82.656 34.771 84.582 34.897 ;
     RECT  85.464 33.547 92.754 34.897 ;
     RECT  53.388 31.891 53.997 34.925 ;
     RECT  56.415 34.699 59.397 34.925 ;
     RECT  61.164 34.799 63.27 34.925 ;
     RECT  74.34 34.763 78.642 34.925 ;
     RECT  45.615 34.663 46.278 34.969 ;
     RECT  61.2 34.925 63.27 34.969 ;
     RECT  64.515 2.413 64.797 34.969 ;
     RECT  93.744 34.651 102.87 34.973 ;
     RECT  24.015 34.781 26.997 35.005 ;
     RECT  65.7 34.861 66.186 35.005 ;
     RECT  67.176 34.187 67.497 35.005 ;
     RECT  82.656 34.897 92.754 35.033 ;
     RECT  24.015 35.005 27.054 35.041 ;
     RECT  42.915 2.413 43.197 35.041 ;
     RECT  50.796 34.493 51.297 35.069 ;
     RECT  54.72 34.051 54.738 35.069 ;
     RECT  82.728 35.033 92.754 35.069 ;
     RECT  27.9 34.897 29.697 35.131 ;
     RECT  30.42 32.881 30.546 35.131 ;
     RECT  61.2 34.969 64.797 35.195 ;
     RECT  77.688 34.925 78.642 35.195 ;
     RECT  61.344 35.195 64.797 35.203 ;
     RECT  65.7 35.005 67.497 35.203 ;
     RECT  58.788 34.925 59.397 35.239 ;
     RECT  61.344 35.203 67.497 35.267 ;
     RECT  24.015 35.041 27.162 35.275 ;
     RECT  27.9 35.131 30.546 35.275 ;
     RECT  55.548 33.511 55.566 35.275 ;
     RECT  48.315 32.765 48.597 35.401 ;
     RECT  74.448 34.925 76.626 35.465 ;
     RECT  24.015 35.275 30.546 35.473 ;
     RECT  24.015 35.473 30.834 35.509 ;
     RECT  48.315 35.401 48.69 35.671 ;
     RECT  49.464 35.437 49.482 35.671 ;
     RECT  48.315 35.671 49.482 35.707 ;
     RECT  24.015 35.509 30.87 35.735 ;
     RECT  61.815 35.267 67.497 35.743 ;
     RECT  68.868 34.619 72.954 35.743 ;
     RECT  93.744 34.973 101.466 35.771 ;
     RECT  79.776 34.393 81.846 35.779 ;
     RECT  79.74 35.779 81.846 35.815 ;
     RECT  102.276 34.973 102.87 35.851 ;
     RECT  74.448 35.465 76.554 35.888 ;
     RECT  51.015 35.069 51.297 35.941 ;
     RECT  61.815 35.743 67.554 35.941 ;
     RECT  48.315 35.707 49.806 35.969 ;
     RECT  54.972 35.275 55.566 35.977 ;
     RECT  56.415 34.925 57.762 35.977 ;
     RECT  48.315 35.969 49.338 36.005 ;
     RECT  68.868 35.743 73.098 36.005 ;
     RECT  52.848 35.473 52.866 36.049 ;
     RECT  85.788 35.069 92.754 36.085 ;
     RECT  58.788 35.239 59.562 36.113 ;
     RECT  33.768 34.501 35.097 36.121 ;
     RECT  42.876 35.041 43.197 36.211 ;
     RECT  48.315 36.005 49.014 36.211 ;
     RECT  82.728 35.069 84.582 36.211 ;
     RECT  85.356 36.085 92.754 36.211 ;
     RECT  28.296 35.735 30.87 36.235 ;
     RECT  31.68 34.231 32.397 36.235 ;
     RECT  24.015 35.735 27.522 36.247 ;
     RECT  102.276 35.851 103.194 36.283 ;
     RECT  33.768 36.121 35.37 36.319 ;
     RECT  50.724 35.941 51.297 36.319 ;
     RECT  59.115 36.113 59.562 36.355 ;
     RECT  102.024 36.283 103.194 36.365 ;
     RECT  61.815 35.941 67.878 36.391 ;
     RECT  33.768 36.319 35.55 36.419 ;
     RECT  61.815 36.391 68.022 36.481 ;
     RECT  45.615 34.969 46.674 36.517 ;
     RECT  56.415 35.977 57.978 36.517 ;
     RECT  56.415 36.517 58.05 36.545 ;
     RECT  68.868 36.005 72.954 36.553 ;
     RECT  77.688 35.195 78.297 36.553 ;
     RECT  79.236 35.815 81.846 36.553 ;
     RECT  23.94 36.247 27.522 36.589 ;
     RECT  28.296 36.235 32.397 36.589 ;
     RECT  42.228 36.211 43.197 36.589 ;
     RECT  54.72 35.977 55.566 36.617 ;
     RECT  58.032 36.545 58.05 36.617 ;
     RECT  50.724 36.319 51.57 36.625 ;
     RECT  45.615 36.517 46.782 36.661 ;
     RECT  47.7 36.211 49.014 36.661 ;
     RECT  61.815 36.481 68.094 36.661 ;
     RECT  68.832 36.553 72.954 36.661 ;
     RECT  50.256 36.625 51.57 36.779 ;
     RECT  61.815 36.661 72.954 36.779 ;
     RECT  82.728 36.211 92.898 36.787 ;
     RECT  102.564 36.365 103.194 36.811 ;
     RECT  66.708 36.779 72.954 36.815 ;
     RECT  74.448 35.888 76.518 36.815 ;
     RECT  52.632 36.049 52.866 36.823 ;
     RECT  52.416 36.823 52.866 36.895 ;
     RECT  37.515 34.501 37.998 36.931 ;
     RECT  74.556 36.815 76.518 36.959 ;
     RECT  93.744 35.771 100.89 37.003 ;
     RECT  37.515 36.931 38.43 37.021 ;
     RECT  68.832 36.815 72.954 37.021 ;
     RECT  66.708 36.815 67.986 37.049 ;
     RECT  33.768 36.419 35.478 37.085 ;
     RECT  52.308 36.895 52.866 37.085 ;
     RECT  93.744 37.003 101.466 37.085 ;
     RECT  45.615 36.661 49.014 37.093 ;
     RECT  93.888 37.085 101.466 37.099 ;
     RECT  102.564 36.811 103.266 37.099 ;
     RECT  82.656 36.787 92.898 37.121 ;
     RECT  93.888 37.099 103.266 37.121 ;
     RECT  23.94 36.589 32.397 37.165 ;
     RECT  37.515 37.021 38.574 37.165 ;
     RECT  37.515 37.165 38.61 37.201 ;
     RECT  37.515 37.201 38.646 37.319 ;
     RECT  45.615 37.093 49.662 37.355 ;
     RECT  34.416 37.085 35.478 37.391 ;
     RECT  37.515 37.319 38.61 37.391 ;
     RECT  40.215 2.413 40.497 37.399 ;
     RECT  77.688 36.553 81.846 37.399 ;
     RECT  82.656 37.121 86.778 37.399 ;
     RECT  93.888 37.121 103.23 37.427 ;
     RECT  101.916 37.427 103.23 37.463 ;
     RECT  23.868 37.165 32.397 37.471 ;
     RECT  33.372 37.291 33.678 37.471 ;
     RECT  74.664 36.959 76.518 37.499 ;
     RECT  63.396 36.779 65.826 37.589 ;
     RECT  74.808 37.499 76.518 37.589 ;
     RECT  68.832 37.021 73.206 37.597 ;
     RECT  40.215 37.399 40.554 37.625 ;
     RECT  74.88 37.589 76.518 37.625 ;
     RECT  101.916 37.463 102.654 37.625 ;
     RECT  77.688 37.399 86.778 37.709 ;
     RECT  52.776 37.085 52.866 37.741 ;
     RECT  53.604 34.925 53.997 37.741 ;
     RECT  36.36 34.897 36.378 37.903 ;
     RECT  61.815 36.779 62.478 37.903 ;
     RECT  63.396 37.589 65.79 37.903 ;
     RECT  66.744 37.049 67.986 37.931 ;
     RECT  61.815 37.903 65.79 37.939 ;
     RECT  102.636 37.625 102.654 37.967 ;
     RECT  68.724 37.597 73.206 37.975 ;
     RECT  61.2 37.939 65.79 38.003 ;
     RECT  66.816 37.931 67.986 38.003 ;
     RECT  77.688 37.709 86.67 38.003 ;
     RECT  23.868 37.471 33.678 38.011 ;
     RECT  36.36 37.903 36.486 38.011 ;
     RECT  23.868 38.011 33.822 38.137 ;
     RECT  54.828 36.617 55.566 38.165 ;
     RECT  79.236 38.003 86.67 38.165 ;
     RECT  37.515 37.391 38.574 38.173 ;
     RECT  39.348 37.561 39.366 38.173 ;
     RECT  23.688 38.137 33.822 38.189 ;
     RECT  23.94 38.189 33.822 38.209 ;
     RECT  34.668 37.391 35.478 38.209 ;
     RECT  37.515 38.173 39.366 38.309 ;
     RECT  54.828 38.165 55.494 38.309 ;
     RECT  82.044 38.165 86.67 38.309 ;
     RECT  68.724 37.975 73.314 38.371 ;
     RECT  54.828 38.309 55.35 38.435 ;
     RECT  63.396 38.003 65.79 38.435 ;
     RECT  56.415 36.545 57.294 38.443 ;
     RECT  75.276 37.625 76.518 38.443 ;
     RECT  82.656 38.309 86.67 38.443 ;
     RECT  50.724 36.779 51.57 38.479 ;
     RECT  52.776 37.741 53.997 38.479 ;
     RECT  65.772 38.435 65.79 38.479 ;
     RECT  37.515 38.309 39.258 38.507 ;
     RECT  36.36 38.011 36.522 38.551 ;
     RECT  37.515 38.507 37.998 38.551 ;
     RECT  50.724 38.479 53.997 38.551 ;
     RECT  68.724 38.371 73.638 38.579 ;
     RECT  74.664 38.443 76.518 38.579 ;
     RECT  82.656 38.443 86.742 38.579 ;
     RECT  67.032 38.003 67.986 38.641 ;
     RECT  68.724 38.579 73.566 38.641 ;
     RECT  38.772 38.507 39.258 38.669 ;
     RECT  67.032 38.641 73.566 38.669 ;
     RECT  74.736 38.579 76.518 38.669 ;
     RECT  82.656 38.579 86.397 38.669 ;
     RECT  65.772 38.479 65.826 38.705 ;
     RECT  42.156 36.589 43.197 38.713 ;
     RECT  59.115 36.355 59.994 38.777 ;
     RECT  61.2 38.003 62.478 38.777 ;
     RECT  87.696 37.121 92.898 38.779 ;
     RECT  45.615 37.355 49.194 38.785 ;
     RECT  63.396 38.435 64.797 38.813 ;
     RECT  23.94 38.209 35.478 38.821 ;
     RECT  36.216 38.551 37.998 38.821 ;
     RECT  56.415 38.443 57.942 38.849 ;
     RECT  23.94 38.821 37.998 38.975 ;
     RECT  45.615 38.785 49.518 38.975 ;
     RECT  79.236 38.165 81.198 38.975 ;
     RECT  67.032 38.669 73.53 38.983 ;
     RECT  82.656 38.669 84.582 39.083 ;
     RECT  50.688 38.551 53.997 39.091 ;
     RECT  66.708 38.983 73.53 39.119 ;
     RECT  54.828 38.435 54.99 39.181 ;
     RECT  23.94 38.975 36.522 39.211 ;
     RECT  93.888 37.427 101.178 39.211 ;
     RECT  38.952 38.669 39.258 39.245 ;
     RECT  87.3 38.779 92.898 39.245 ;
     RECT  93.888 39.211 101.682 39.245 ;
     RECT  23.796 39.211 36.522 39.251 ;
     RECT  24.015 39.251 36.522 39.281 ;
     RECT  77.688 38.003 78.297 39.325 ;
     RECT  45.615 38.975 48.597 39.361 ;
     RECT  63.792 38.813 64.797 39.389 ;
     RECT  44.136 39.289 44.154 39.487 ;
     RECT  44.892 39.361 48.597 39.487 ;
     RECT  85.392 38.669 86.397 39.487 ;
     RECT  65.808 38.705 65.826 39.523 ;
     RECT  75.315 38.669 76.518 39.523 ;
     RECT  44.136 39.487 48.597 39.559 ;
     RECT  57.924 38.849 57.942 39.721 ;
     RECT  67.032 39.119 73.53 39.721 ;
     RECT  65.808 39.523 65.934 39.749 ;
     RECT  57.924 39.721 58.05 39.785 ;
     RECT  61.272 38.777 62.478 39.785 ;
     RECT  65.808 39.749 65.826 39.785 ;
     RECT  43.992 39.559 48.597 39.835 ;
     RECT  67.032 39.721 73.746 39.857 ;
     RECT  43.956 39.835 48.597 39.865 ;
     RECT  103.176 39.787 103.194 39.883 ;
     RECT  43.956 39.865 48.726 39.893 ;
     RECT  58.032 39.785 58.05 39.893 ;
     RECT  85.392 39.487 86.994 39.893 ;
     RECT  61.272 39.785 62.406 39.929 ;
     RECT  24.015 39.281 36.234 39.979 ;
     RECT  74.7 39.523 76.518 39.991 ;
     RECT  23.472 39.979 36.234 40.055 ;
     RECT  82.8 39.083 84.582 40.055 ;
     RECT  54.828 39.181 55.674 40.063 ;
     RECT  95.436 39.245 101.682 40.075 ;
     RECT  102.6 39.883 103.194 40.075 ;
     RECT  37.515 38.975 37.998 40.099 ;
     RECT  39.096 39.245 39.258 40.099 ;
     RECT  23.868 40.055 36.234 40.135 ;
     RECT  37.515 40.099 39.258 40.135 ;
     RECT  82.8 40.055 83.697 40.171 ;
     RECT  54.72 40.063 55.674 40.199 ;
     RECT  95.436 40.075 103.194 40.325 ;
     RECT  43.992 39.893 48.726 40.363 ;
     RECT  96.264 40.325 103.194 40.397 ;
     RECT  93.888 39.245 94.497 40.441 ;
     RECT  95.436 40.325 95.454 40.441 ;
     RECT  43.992 40.363 48.762 40.469 ;
     RECT  85.392 39.893 86.67 40.531 ;
     RECT  23.868 40.135 39.258 40.559 ;
     RECT  49.644 39.091 53.997 40.595 ;
     RECT  40.215 37.625 40.497 40.675 ;
     RECT  40.215 40.675 40.698 40.711 ;
     RECT  41.544 38.713 43.197 40.711 ;
     RECT  67.032 39.857 73.71 40.837 ;
     RECT  23.94 40.559 39.258 40.865 ;
     RECT  24.015 40.865 39.258 40.981 ;
     RECT  66.744 40.837 73.71 41.071 ;
     RECT  40.215 40.711 43.197 41.107 ;
     RECT  77.4 39.325 78.297 41.107 ;
     RECT  79.236 38.975 80.997 41.107 ;
     RECT  96.588 40.397 103.194 41.135 ;
     RECT  24.015 40.981 39.402 41.143 ;
     RECT  40.176 41.107 43.197 41.143 ;
     RECT  58.068 40.801 58.086 41.143 ;
     RECT  59.115 38.777 59.922 41.143 ;
     RECT  84.528 40.055 84.582 41.143 ;
     RECT  85.32 40.531 86.67 41.143 ;
     RECT  87.984 39.245 92.898 41.143 ;
     RECT  93.888 40.441 95.454 41.143 ;
     RECT  87.984 41.143 95.454 41.171 ;
     RECT  49.788 40.595 53.997 41.179 ;
     RECT  54.828 40.199 55.674 41.179 ;
     RECT  84.528 41.143 86.67 41.242 ;
     RECT  66.708 41.071 73.71 41.243 ;
     RECT  24.015 41.143 43.197 41.377 ;
     RECT  43.992 40.469 48.726 41.377 ;
     RECT  84.528 41.242 86.706 41.441 ;
     RECT  84.528 41.441 86.562 41.477 ;
     RECT  77.4 41.107 80.997 41.513 ;
     RECT  74.556 39.991 76.518 41.521 ;
     RECT  49.788 41.179 55.674 41.611 ;
     RECT  56.415 38.849 57.114 41.611 ;
     RECT  103.968 39.115 103.986 41.611 ;
     RECT  82.476 40.171 83.697 41.881 ;
     RECT  96.732 41.135 103.194 41.899 ;
     RECT  103.932 41.611 103.986 41.899 ;
     RECT  96.732 41.899 103.986 41.945 ;
     RECT  58.068 41.143 59.922 42.061 ;
     RECT  58.068 42.061 60.102 42.179 ;
     RECT  24.015 41.377 48.726 42.187 ;
     RECT  87.984 41.171 90.738 42.215 ;
     RECT  23.904 42.187 48.726 42.223 ;
     RECT  49.788 41.611 57.114 42.223 ;
     RECT  67.032 41.243 73.71 42.259 ;
     RECT  58.068 42.179 59.994 42.449 ;
     RECT  23.904 42.223 57.114 42.485 ;
     RECT  58.068 42.449 59.778 42.485 ;
     RECT  96.768 41.945 103.986 42.485 ;
     RECT  77.4 41.513 78.297 42.529 ;
     RECT  79.236 41.513 80.997 42.529 ;
     RECT  61.272 39.929 62.097 42.565 ;
     RECT  77.4 42.529 80.997 42.565 ;
     RECT  82.224 41.881 83.697 42.565 ;
     RECT  61.272 42.565 62.262 42.601 ;
     RECT  38.592 42.485 57.114 42.629 ;
     RECT  61.236 42.601 62.262 42.691 ;
     RECT  77.4 42.565 83.697 42.719 ;
     RECT  91.515 41.171 95.454 42.719 ;
     RECT  96.876 42.485 103.986 42.727 ;
     RECT  38.664 42.629 57.114 42.755 ;
     RECT  66.708 42.259 73.71 42.755 ;
     RECT  60.768 42.691 62.262 42.763 ;
     RECT  60.768 42.763 62.298 42.799 ;
     RECT  84.528 41.477 86.454 42.871 ;
     RECT  66.744 42.755 73.71 42.989 ;
     RECT  84.528 42.871 87.138 42.997 ;
     RECT  87.984 42.215 89.478 42.997 ;
     RECT  77.4 42.719 80.997 43.025 ;
     RECT  84.528 42.997 89.478 43.025 ;
     RECT  23.904 42.485 37.854 43.069 ;
     RECT  58.068 42.485 59.67 43.069 ;
     RECT  66.78 42.989 73.71 43.069 ;
     RECT  74.556 41.521 76.662 43.069 ;
     RECT  84.528 43.025 86.634 43.097 ;
     RECT  87.408 43.025 89.478 43.097 ;
     RECT  60.768 42.799 62.766 43.169 ;
     RECT  23.544 43.069 37.854 43.267 ;
     RECT  96.876 42.727 104.058 43.303 ;
     RECT  23.544 43.267 37.926 43.411 ;
     RECT  38.664 42.755 52.938 43.411 ;
     RECT  23.544 43.411 52.938 43.565 ;
     RECT  81.756 42.719 83.697 43.573 ;
     RECT  53.715 42.755 57.114 43.601 ;
     RECT  80.676 43.025 80.997 43.835 ;
     RECT  66.78 43.069 76.662 43.951 ;
     RECT  91.515 42.719 94.662 44.105 ;
     RECT  57.888 43.069 59.67 44.149 ;
     RECT  60.768 43.169 62.097 44.149 ;
     RECT  80.715 43.835 80.997 44.149 ;
     RECT  81.72 43.573 83.697 44.149 ;
     RECT  84.528 43.097 86.454 44.149 ;
     RECT  66.708 43.951 76.662 44.213 ;
     RECT  84.528 44.149 86.67 44.249 ;
     RECT  92.88 44.105 94.662 44.249 ;
     RECT  23.544 43.565 39.006 44.311 ;
     RECT  95.436 42.719 95.454 44.419 ;
     RECT  77.4 43.025 79.758 44.645 ;
     RECT  80.715 44.149 83.697 44.645 ;
     RECT  23.544 44.311 39.114 44.689 ;
     RECT  39.852 43.565 52.938 44.689 ;
     RECT  53.715 43.601 54.702 44.689 ;
     RECT  55.476 43.601 57.114 44.689 ;
     RECT  81.72 44.645 83.697 44.717 ;
     RECT  64.515 39.389 64.797 44.725 ;
     RECT  81.756 44.717 83.697 44.761 ;
     RECT  84.528 44.249 86.454 44.761 ;
     RECT  67.215 44.213 76.662 44.915 ;
     RECT  96.732 43.303 104.058 45.023 ;
     RECT  53.715 44.689 57.114 45.031 ;
     RECT  57.888 44.149 62.097 45.031 ;
     RECT  95.436 44.419 95.742 45.031 ;
     RECT  67.215 44.915 71.154 45.059 ;
     RECT  67.215 45.059 70.578 45.121 ;
     RECT  95.436 45.031 95.958 45.265 ;
     RECT  96.732 45.023 102.726 45.265 ;
     RECT  66.708 45.121 70.578 45.329 ;
     RECT  23.544 44.689 52.938 45.391 ;
     RECT  103.716 45.023 104.058 45.437 ;
     RECT  92.916 44.249 94.662 45.571 ;
     RECT  95.436 45.265 102.726 45.571 ;
     RECT  78.015 44.645 79.758 45.661 ;
     RECT  80.715 44.645 80.997 45.661 ;
     RECT  87.984 43.097 89.478 45.661 ;
     RECT  90.216 42.215 90.738 45.661 ;
     RECT  23.544 45.391 52.974 45.689 ;
     RECT  44.496 45.689 52.974 45.769 ;
     RECT  53.715 45.031 62.097 45.769 ;
     RECT  87.984 45.661 90.738 45.769 ;
     RECT  91.515 44.105 92.142 45.769 ;
     RECT  103.716 45.437 103.95 45.833 ;
     RECT  66.744 45.329 70.578 45.869 ;
     RECT  87.984 45.769 92.142 45.959 ;
     RECT  91.476 45.959 92.142 46.039 ;
     RECT  91.476 46.039 92.178 46.139 ;
     RECT  67.215 45.869 70.578 46.273 ;
     RECT  67.215 46.273 70.722 46.373 ;
     RECT  23.544 45.689 43.614 46.471 ;
     RECT  44.496 45.769 62.097 46.471 ;
     RECT  23.544 46.471 62.097 46.543 ;
     RECT  23.544 46.543 62.73 46.607 ;
     RECT  87.984 45.959 90.738 46.651 ;
     RECT  64.224 44.725 64.797 46.741 ;
     RECT  87.84 46.651 90.738 46.769 ;
     RECT  71.892 44.915 76.662 46.805 ;
     RECT  67.215 46.373 70.326 46.813 ;
     RECT  53.715 46.607 62.73 46.913 ;
     RECT  66.708 46.813 70.326 46.913 ;
     RECT  92.916 45.571 102.726 47.083 ;
     RECT  103.752 45.833 103.95 47.083 ;
     RECT  56.232 46.913 62.73 47.119 ;
     RECT  63.504 46.741 64.797 47.119 ;
     RECT  67.215 46.913 70.326 47.191 ;
     RECT  56.232 47.119 64.797 47.281 ;
     RECT  91.476 46.139 92.106 47.281 ;
     RECT  92.916 47.083 103.95 47.281 ;
     RECT  53.715 46.913 55.386 47.309 ;
     RECT  71.892 46.805 73.602 47.309 ;
     RECT  71.892 47.309 73.494 47.345 ;
     RECT  23.544 46.607 52.974 47.551 ;
     RECT  53.715 47.309 55.026 47.551 ;
     RECT  56.232 47.281 64.854 47.587 ;
     RECT  56.232 47.587 65.394 47.615 ;
     RECT  74.376 46.805 76.662 47.731 ;
     RECT  56.232 47.615 60.318 47.885 ;
     RECT  67.215 47.191 70.974 48.001 ;
     RECT  81.756 44.761 86.454 48.001 ;
     RECT  78.015 45.661 80.997 48.091 ;
     RECT  81.756 48.001 86.67 48.091 ;
     RECT  87.912 46.769 90.738 48.091 ;
     RECT  78.015 48.091 86.67 48.119 ;
     RECT  87.84 48.091 90.738 48.199 ;
     RECT  91.476 47.281 103.95 48.199 ;
     RECT  78.015 48.119 86.454 48.227 ;
     RECT  87.84 48.199 103.95 48.271 ;
     RECT  60.192 47.885 60.318 48.389 ;
     RECT  60.192 48.389 60.246 48.425 ;
     RECT  74.376 47.731 76.914 48.541 ;
     RECT  78.015 48.227 80.997 48.667 ;
     RECT  73.692 48.541 76.914 48.739 ;
     RECT  77.976 48.667 80.997 48.739 ;
     RECT  81.756 48.227 86.454 48.803 ;
     RECT  71.892 47.345 72.897 48.811 ;
     RECT  73.692 48.739 80.997 48.811 ;
     RECT  23.544 47.551 55.026 48.901 ;
     RECT  56.232 47.885 59.397 48.901 ;
     RECT  82.332 48.803 86.454 48.907 ;
     RECT  87.192 48.271 103.95 48.907 ;
     RECT  66.708 48.001 70.974 48.965 ;
     RECT  71.892 48.811 80.997 48.965 ;
     RECT  66.708 48.965 67.497 49.001 ;
     RECT  82.332 48.907 103.95 49.001 ;
     RECT  82.764 49.001 103.95 49.037 ;
     RECT  87.192 49.037 103.95 49.073 ;
     RECT  61.488 47.615 65.394 49.081 ;
     RECT  68.76 48.965 70.974 49.109 ;
     RECT  70.956 49.109 70.974 49.477 ;
     RECT  71.892 48.965 72.954 49.477 ;
     RECT  60.192 48.425 60.21 49.513 ;
     RECT  61.488 49.081 65.934 49.513 ;
     RECT  66.744 49.001 67.497 49.711 ;
     RECT  68.76 49.109 70.197 49.711 ;
     RECT  87.192 49.073 103.914 49.883 ;
     RECT  81.828 49.621 81.846 49.891 ;
     RECT  82.764 49.037 86.454 49.891 ;
     RECT  87.192 49.883 101.754 49.891 ;
     RECT  60.192 49.513 65.934 50.125 ;
     RECT  66.744 49.711 70.197 50.125 ;
     RECT  70.956 49.477 72.954 50.125 ;
     RECT  73.692 48.965 80.997 50.161 ;
     RECT  81.792 49.891 81.846 50.161 ;
     RECT  82.764 49.891 101.754 50.189 ;
     RECT  60.192 50.125 72.954 50.251 ;
     RECT  73.692 50.161 81.918 50.251 ;
     RECT  60.192 50.251 81.918 50.395 ;
     RECT  82.764 50.189 92.106 50.395 ;
     RECT  92.916 50.189 101.754 50.635 ;
     RECT  102.6 49.883 103.914 50.635 ;
     RECT  60.192 50.395 92.106 50.819 ;
     RECT  23.544 48.901 59.397 50.855 ;
     RECT  92.916 50.635 103.914 50.855 ;
     RECT  62.856 50.819 92.106 50.935 ;
     RECT  92.916 50.855 101.538 50.935 ;
     RECT  102.276 50.855 103.914 51.161 ;
     RECT  23.544 50.855 57.438 51.169 ;
     RECT  62.856 50.935 101.538 51.269 ;
     RECT  87.876 51.269 101.538 51.709 ;
     RECT  102.276 51.161 103.194 51.709 ;
     RECT  22.824 51.169 57.438 51.871 ;
     RECT  22.824 51.871 57.51 51.979 ;
     RECT  58.464 50.855 59.397 51.979 ;
     RECT  62.856 51.269 65.646 51.979 ;
     RECT  62.82 51.979 65.646 52.051 ;
     RECT  66.42 51.269 86.922 52.051 ;
     RECT  87.876 51.709 103.194 52.075 ;
     RECT  22.824 51.979 59.397 52.169 ;
     RECT  60.192 50.819 62.097 52.177 ;
     RECT  62.82 52.051 86.922 52.177 ;
     RECT  87.876 52.075 103.23 52.267 ;
     RECT  87.876 52.267 103.266 52.36 ;
     RECT  104.04 52.315 104.058 52.36 ;
     RECT  87.876 52.36 104.058 52.394 ;
     RECT  87.876 52.394 103.986 52.397 ;
     RECT  58.608 52.169 59.397 52.591 ;
     RECT  60.192 52.177 86.922 52.591 ;
     RECT  87.876 52.397 103.302 52.861 ;
     RECT  22.824 52.169 57.87 53.059 ;
     RECT  58.608 52.591 86.922 53.059 ;
     RECT  22.824 53.059 86.922 53.257 ;
     RECT  87.768 52.861 103.302 53.257 ;
     RECT  22.824 53.257 103.302 53.555 ;
     RECT  22.824 53.555 86.958 53.663 ;
     RECT  87.912 53.555 103.302 54.211 ;
     RECT  87.912 54.211 103.338 54.317 ;
     RECT  87.912 54.317 103.302 54.481 ;
     RECT  87.84 54.481 103.302 54.671 ;
     RECT  87.912 54.671 103.302 55.243 ;
     RECT  22.824 53.663 85.23 55.985 ;
     RECT  87.912 55.243 103.986 55.985 ;
     RECT  92.808 55.985 103.986 56.291 ;
     RECT  87.912 55.985 92.07 56.497 ;
     RECT  92.916 56.291 103.986 56.686 ;
     RECT  87.804 56.497 92.07 56.759 ;
     RECT  87.804 56.759 88.002 56.795 ;
     RECT  22.824 55.985 85.122 57.073 ;
     RECT  86.004 53.663 86.958 57.073 ;
     RECT  88.776 56.759 92.07 57.181 ;
     RECT  87.804 56.795 87.93 57.379 ;
     RECT  92.916 56.686 104.022 57.443 ;
     RECT  88.776 57.181 92.106 57.451 ;
     RECT  92.916 57.443 103.05 57.451 ;
     RECT  103.896 57.443 104.022 57.547 ;
     RECT  22.824 57.073 86.958 57.569 ;
     RECT  55.944 57.569 86.958 57.577 ;
     RECT  87.696 57.379 87.93 57.577 ;
     RECT  103.896 57.547 104.058 57.581 ;
     RECT  88.776 57.451 103.05 57.605 ;
     RECT  55.944 57.577 87.93 57.749 ;
     RECT  103.932 57.581 104.058 58.507 ;
     RECT  22.824 57.569 55.17 58.531 ;
     RECT  55.944 57.749 86.958 58.531 ;
     RECT  87.912 57.749 87.93 58.693 ;
     RECT  88.776 57.605 92.07 58.693 ;
     RECT  22.824 58.531 86.958 58.699 ;
     RECT  87.84 58.693 87.93 58.699 ;
     RECT  22.824 58.699 87.93 58.729 ;
     RECT  88.668 58.693 92.07 58.729 ;
     RECT  92.916 57.605 103.05 58.829 ;
     RECT  92.952 58.829 103.05 59.275 ;
     RECT  103.896 58.507 104.058 59.275 ;
     RECT  92.952 59.275 104.058 59.729 ;
     RECT  92.952 59.729 95.058 59.765 ;
     RECT  3.528 59.881 3.546 59.999 ;
     RECT  22.824 58.729 92.07 60.107 ;
     RECT  2.415 2.413 2.697 60.115 ;
     RECT  21.315 2.413 21.597 60.139 ;
     RECT  2.304 60.115 2.697 60.241 ;
     RECT  2.304 60.241 3.402 60.317 ;
     RECT  21.315 60.139 21.69 60.317 ;
     RECT  0.324 60.523 0.342 60.619 ;
     RECT  0.108 60.619 0.342 60.653 ;
     RECT  0.108 60.653 0.234 60.719 ;
     RECT  95.796 59.729 104.058 60.719 ;
     RECT  0.108 60.719 0.162 60.749 ;
     RECT  91.515 60.107 92.07 60.781 ;
     RECT  2.304 60.317 3.366 60.881 ;
     RECT  91.515 60.781 92.178 60.881 ;
     RECT  95.796 60.719 103.05 60.917 ;
     RECT  2.34 60.881 2.862 60.941 ;
     RECT  102.564 60.917 103.05 60.953 ;
     RECT  13.215 2.413 13.497 61.051 ;
     RECT  15.915 2.413 16.197 61.051 ;
     RECT  21.315 60.317 21.597 61.051 ;
     RECT  93.024 59.765 95.058 61.051 ;
     RECT  95.796 60.917 101.826 61.051 ;
     RECT  2.415 60.941 2.862 61.079 ;
     RECT  15.915 61.051 16.506 61.087 ;
     RECT  13.104 61.051 13.497 61.088 ;
     RECT  21.204 61.051 21.597 61.088 ;
     RECT  15.915 61.087 16.722 61.133 ;
     RECT  0.108 60.749 0.126 61.151 ;
     RECT  6.732 61.051 6.858 61.181 ;
     RECT  14.832 61.051 14.85 61.181 ;
     RECT  3.852 61.147 3.87 61.187 ;
     RECT  93.024 61.051 101.826 61.387 ;
     RECT  22.824 60.107 90.774 61.889 ;
     RECT  91.515 60.881 91.797 62.041 ;
     RECT  92.52 61.387 101.826 62.041 ;
     RECT  102.564 60.953 102.87 62.155 ;
     RECT  103.896 60.719 104.058 62.155 ;
     RECT  102.564 62.155 104.058 62.501 ;
     RECT  104.04 62.501 104.058 62.573 ;
     RECT  91.515 62.041 101.826 62.807 ;
     RECT  22.824 61.889 89.946 62.843 ;
     RECT  90.756 61.889 90.774 63.121 ;
     RECT  91.515 62.807 95.058 63.121 ;
     RECT  95.796 62.807 101.826 63.307 ;
     RECT  102.564 62.501 103.266 63.307 ;
     RECT  95.796 63.307 103.266 63.533 ;
     RECT  22.824 62.843 89.874 63.661 ;
     RECT  90.756 63.121 95.058 63.661 ;
     RECT  95.796 63.533 101.826 63.661 ;
     RECT  102.636 63.533 103.266 64.193 ;
     RECT  102.636 64.193 102.726 64.267 ;
     RECT  102.6 64.267 102.726 64.397 ;
     RECT  22.824 63.661 101.826 65.371 ;
     RECT  102.672 65.131 102.69 65.371 ;
     RECT  22.824 65.371 102.69 66.475 ;
     RECT  22.824 66.475 103.194 66.571 ;
     RECT  103.968 66.283 103.986 66.571 ;
     RECT  22.824 66.571 103.986 68.333 ;
     RECT  103.86 68.333 103.986 69.089 ;
     RECT  103.896 69.089 103.986 69.287 ;
     RECT  18.615 2.413 18.897 69.331 ;
     RECT  103.896 69.287 103.914 69.359 ;
     RECT  22.824 68.333 102.726 69.643 ;
     RECT  22.824 69.643 102.762 69.931 ;
     RECT  22.824 69.931 103.23 71.947 ;
     RECT  22.824 71.947 103.266 72.043 ;
     RECT  20.448 69.061 20.466 72.229 ;
     RECT  21.315 61.088 21.597 72.229 ;
     RECT  22.824 72.043 103.302 72.329 ;
     RECT  22.824 72.329 103.266 73.771 ;
     RECT  22.824 73.771 103.986 73.913 ;
     RECT  20.448 72.229 21.597 74.389 ;
     RECT  14.292 71.761 14.31 74.885 ;
     RECT  22.824 73.913 102.906 75.019 ;
     RECT  9.432 72.301 9.45 76.235 ;
     RECT  103.968 73.913 103.986 76.883 ;
     RECT  22.824 75.019 103.194 77.387 ;
     RECT  20.448 74.389 21.906 78.511 ;
     RECT  22.824 77.387 102.87 78.511 ;
     RECT  20.448 78.511 102.87 78.971 ;
     RECT  102.852 78.971 102.87 79.325 ;
     RECT  10.515 2.413 10.797 80.221 ;
     RECT  11.736 77.629 11.754 80.221 ;
     RECT  13.215 61.088 13.497 80.365 ;
     RECT  13.215 80.365 13.59 80.491 ;
     RECT  14.4 75.001 14.418 80.491 ;
     RECT  13.215 80.491 14.418 80.663 ;
     RECT  13.215 80.663 14.13 80.869 ;
     RECT  15.915 61.133 16.197 81.445 ;
     RECT  16.92 79.825 16.938 81.445 ;
     RECT  8.82 76.351 8.838 81.905 ;
     RECT  18.615 69.331 19.314 81.985 ;
     RECT  7.815 2.413 8.097 82.021 ;
     RECT  20.448 78.971 101.79 82.553 ;
     RECT  12.996 80.869 14.13 83.065 ;
     RECT  10.515 80.221 11.754 83.611 ;
     RECT  12.996 83.065 14.778 83.611 ;
     RECT  15.915 81.445 16.938 83.641 ;
     RECT  18.108 81.985 19.314 83.641 ;
     RECT  102.6 83.605 102.618 83.755 ;
     RECT  102.6 83.755 103.194 83.851 ;
     RECT  102.6 83.851 103.23 83.947 ;
     RECT  20.448 82.553 101.682 84.043 ;
     RECT  102.6 83.947 103.266 84.043 ;
     RECT  15.915 83.641 19.314 84.145 ;
     RECT  20.448 84.043 103.266 84.145 ;
     RECT  15.915 84.145 103.266 84.335 ;
     RECT  101.448 84.335 103.266 85.559 ;
     RECT  10.515 83.611 14.778 85.685 ;
     RECT  15.915 84.335 100.638 85.729 ;
     RECT  102.6 85.559 103.266 85.991 ;
     RECT  101.448 85.559 101.718 86.063 ;
     RECT  15.915 85.729 100.674 86.071 ;
     RECT  101.448 86.063 101.682 86.071 ;
     RECT  102.6 85.991 103.194 86.467 ;
     RECT  10.515 85.685 13.77 86.531 ;
     RECT  15.915 86.071 101.682 86.531 ;
     RECT  102.456 86.467 103.194 86.567 ;
     RECT  14.76 85.685 14.778 86.575 ;
     RECT  102.528 86.567 103.194 86.765 ;
     RECT  103.932 86.155 103.95 86.801 ;
     RECT  102.528 86.765 102.618 86.873 ;
     RECT  102.6 86.873 102.618 86.909 ;
     RECT  15.915 86.531 100.35 87.179 ;
     RECT  101.448 86.531 101.682 87.305 ;
     RECT  99.072 87.179 100.35 87.421 ;
     RECT  101.448 87.305 101.466 87.421 ;
     RECT  10.515 86.531 11.538 87.691 ;
     RECT  12.348 86.531 13.77 87.691 ;
     RECT  10.515 87.691 13.77 87.925 ;
     RECT  7.815 82.021 8.154 88.087 ;
     RECT  99.072 87.421 101.466 88.115 ;
     RECT  14.688 86.575 14.778 88.321 ;
     RECT  9.864 87.925 13.77 88.501 ;
     RECT  14.688 88.321 14.85 88.699 ;
     RECT  14.58 88.699 14.85 88.735 ;
     RECT  15.915 87.179 98.334 88.735 ;
     RECT  7.815 88.087 8.55 88.771 ;
     RECT  7.815 88.771 8.586 88.861 ;
     RECT  7.815 88.861 8.766 89.311 ;
     RECT  9.612 88.501 13.77 89.311 ;
     RECT  14.58 88.735 98.334 89.311 ;
     RECT  99.108 88.115 101.466 89.311 ;
     RECT  7.815 89.311 13.77 89.473 ;
     RECT  14.58 89.311 101.466 89.473 ;
     RECT  7.815 89.473 101.466 89.501 ;
     RECT  7.815 89.501 98.334 89.941 ;
     RECT  7.776 89.941 98.334 90.077 ;
     RECT  99.108 89.501 101.466 90.149 ;
     RECT  6.696 87.511 6.714 90.625 ;
     RECT  6.624 90.625 6.714 90.653 ;
     RECT  101.448 90.149 101.466 91.085 ;
     RECT  7.815 90.077 98.334 91.319 ;
     RECT  7.815 91.319 93.006 91.391 ;
     RECT  7.815 91.391 92.898 91.939 ;
     RECT  93.744 91.319 98.334 92.011 ;
     RECT  99.108 90.149 100.278 92.011 ;
     RECT  101.556 91.201 101.574 92.129 ;
     RECT  6.624 90.653 6.642 92.137 ;
     RECT  6.408 92.137 6.642 92.189 ;
     RECT  6.624 92.189 6.642 92.281 ;
     RECT  7.524 91.939 92.898 92.281 ;
     RECT  6.624 92.281 92.97 92.371 ;
     RECT  93.744 92.011 100.278 92.371 ;
     RECT  6.624 92.371 100.278 92.551 ;
     RECT  6.624 92.551 100.458 92.849 ;
     RECT  6.624 92.849 100.278 93.281 ;
     RECT  18.615 93.281 100.278 93.901 ;
     RECT  18.615 93.901 100.962 94.019 ;
     RECT  6.624 93.281 17.766 94.075 ;
     RECT  6.408 94.075 17.766 94.333 ;
     RECT  18.615 94.019 100.314 94.333 ;
     RECT  5.115 2.413 5.397 94.981 ;
     RECT  6.408 94.333 100.314 94.981 ;
     RECT  5.115 94.981 100.314 95.521 ;
     RECT  5.115 95.521 100.782 95.549 ;
     RECT  6.408 95.549 100.782 95.945 ;
     RECT  6.696 95.945 100.782 96.061 ;
     RECT  6.696 96.061 101.214 96.179 ;
     RECT  6.696 96.179 100.854 96.719 ;
     RECT  101.628 96.601 101.646 96.719 ;
     RECT  6.696 96.719 100.71 96.755 ;
     RECT  6.696 96.755 100.278 96.827 ;
     RECT  6.696 96.827 100.242 97.141 ;
     RECT  6.3 97.141 100.242 97.411 ;
     RECT  5.115 95.549 5.397 97.435 ;
     RECT  6.264 97.411 100.242 97.435 ;
     RECT  5.115 97.435 100.242 97.565 ;
     RECT  6.444 97.565 100.242 97.645 ;
     RECT  6.444 97.645 100.638 97.799 ;
     RECT  6.444 97.799 100.206 99.491 ;
     RECT  6.804 99.491 100.206 99.499 ;
     RECT  6.804 99.499 100.314 99.697 ;
     RECT  6.804 99.697 100.386 99.841 ;
     RECT  6.804 99.841 100.458 100.381 ;
     RECT  6.804 100.381 101.07 100.499 ;
     RECT  6.804 100.499 100.602 100.535 ;
     RECT  6.804 100.535 17.478 100.571 ;
     RECT  9.036 100.571 17.478 100.769 ;
     RECT  17.136 100.769 17.478 100.805 ;
     RECT  18.252 100.535 100.602 100.805 ;
     RECT  9.036 100.769 16.254 100.841 ;
     RECT  17.46 100.805 17.478 100.913 ;
     RECT  6.804 100.571 8.097 101.039 ;
     RECT  9.036 100.841 16.197 101.039 ;
     RECT  18.615 100.805 100.602 101.389 ;
     RECT  18.615 101.389 100.926 101.579 ;
     RECT  9.072 101.039 16.197 101.615 ;
     RECT  18.615 101.579 100.746 101.615 ;
     RECT  9.828 101.615 16.197 101.651 ;
     RECT  19.692 101.615 100.746 101.651 ;
     RECT  9.072 101.615 9.09 101.849 ;
     RECT  9.828 101.651 14.85 101.849 ;
     RECT  29.304 101.651 100.746 101.849 ;
     RECT  29.304 101.849 100.674 101.921 ;
     RECT  19.692 101.651 28.458 101.957 ;
     RECT  29.304 101.921 100.242 101.993 ;
     RECT  9.936 101.849 14.85 102.389 ;
     RECT  29.304 101.993 87.102 102.389 ;
     RECT  87.84 101.993 99.897 102.389 ;
     RECT  29.304 102.389 87.03 102.425 ;
     RECT  18.615 101.615 18.897 102.505 ;
     RECT  19.692 101.957 28.314 102.505 ;
     RECT  18.615 102.505 28.314 102.569 ;
     RECT  93.492 102.389 99.897 102.569 ;
     RECT  87.84 102.389 92.754 102.659 ;
     RECT  93.708 102.569 99.897 102.731 ;
     RECT  88.776 102.659 92.754 102.767 ;
     RECT  29.415 102.425 87.03 102.929 ;
     RECT  93.708 102.731 98.046 102.965 ;
     RECT  99.108 102.731 99.897 102.965 ;
     RECT  88.815 102.767 92.754 103.001 ;
     RECT  18.615 102.569 27.774 103.037 ;
     RECT  87.84 102.659 87.858 103.037 ;
     RECT  93.708 102.965 95.094 103.037 ;
     RECT  96.12 102.965 97.902 103.037 ;
     RECT  99.144 102.965 99.897 103.037 ;
     RECT  10.08 102.389 14.85 103.073 ;
     RECT  90.684 103.001 92.574 103.073 ;
     RECT  93.708 103.037 94.986 103.073 ;
     RECT  15.624 101.651 16.197 103.081 ;
     RECT  94.215 103.073 94.986 103.085 ;
     RECT  88.815 103.001 89.838 103.109 ;
     RECT  2.415 61.079 2.697 103.157 ;
     RECT  5.115 97.565 5.397 103.157 ;
     RECT  7.815 101.039 8.097 103.157 ;
     RECT  15.048 103.081 16.197 103.157 ;
     RECT  18.615 103.037 27.09 103.157 ;
     RECT  29.415 102.929 63.774 103.157 ;
     RECT  64.515 102.929 87.03 103.157 ;
     RECT  88.815 103.109 89.19 103.157 ;
     RECT  90.864 103.073 92.574 103.157 ;
     RECT  94.215 103.085 94.497 103.157 ;
     RECT  99.615 103.037 99.897 103.157 ;
     RECT  15.048 103.157 15.21 103.199 ;
     RECT  18.807 103.157 27.09 103.199 ;
     RECT  29.607 103.157 63.774 103.199 ;
     RECT  64.707 103.157 87.03 103.199 ;
     RECT  90.864 103.157 90.882 103.199 ;
     RECT  91.707 103.157 92.574 103.199 ;
     RECT  10.08 103.073 14.274 103.229 ;
     RECT  18.807 103.199 24.678 103.235 ;
     RECT  29.607 103.199 44.586 103.235 ;
     RECT  45.72 103.199 51.786 103.235 ;
     RECT  96.372 103.037 97.197 103.235 ;
     RECT  15.048 103.199 15.066 103.271 ;
     RECT  45.807 103.235 51.786 103.271 ;
     RECT  72.432 103.199 87.03 103.271 ;
     RECT  52.632 103.199 62.442 103.307 ;
     RECT  85.392 103.271 87.03 103.315 ;
     RECT  52.632 103.307 62.226 103.325 ;
     RECT  63.756 103.199 63.774 103.325 ;
     RECT  18.807 103.235 24.606 103.343 ;
     RECT  40.104 103.235 43.866 103.343 ;
     RECT  85.392 103.315 87.138 103.343 ;
     RECT  92.556 103.199 92.574 103.343 ;
     RECT  10.08 103.229 13.842 103.351 ;
     RECT  25.776 103.199 27.09 103.379 ;
     RECT  52.632 103.325 60.246 103.379 ;
     RECT  89.007 103.157 89.19 103.379 ;
     RECT  2.607 103.157 2.697 103.427 ;
     RECT  5.307 103.157 5.397 103.427 ;
     RECT  8.007 103.157 8.097 103.427 ;
     RECT  16.107 103.157 16.197 103.427 ;
     RECT  18.807 103.343 18.897 103.427 ;
     RECT  25.776 103.379 26.997 103.427 ;
     RECT  29.607 103.235 39.114 103.427 ;
     RECT  40.407 103.343 43.866 103.427 ;
     RECT  45.807 103.271 51.297 103.427 ;
     RECT  64.707 103.199 71.55 103.427 ;
     RECT  89.007 103.379 89.097 103.427 ;
     RECT  91.707 103.199 91.797 103.427 ;
     RECT  94.407 103.157 94.497 103.427 ;
     RECT  97.107 103.235 97.197 103.427 ;
     RECT  99.807 103.157 99.897 103.427 ;
     RECT  10.008 103.351 13.842 103.469 ;
     RECT  25.776 103.427 26.586 103.469 ;
     RECT  30.276 103.427 39.114 103.469 ;
     RECT  40.86 103.427 43.866 103.469 ;
     RECT  52.632 103.379 57.546 103.469 ;
     RECT  58.356 103.379 60.246 103.469 ;
     RECT  65.16 103.427 69.894 103.469 ;
     RECT  70.704 103.427 71.55 103.469 ;
     RECT  85.68 103.343 87.138 103.469 ;
     RECT  72.432 103.271 84.654 103.517 ;
     RECT  10.296 103.469 13.842 103.541 ;
     RECT  40.86 103.469 43.614 103.541 ;
     RECT  52.632 103.469 57.078 103.541 ;
     RECT  59.256 103.469 59.85 103.565 ;
     RECT  10.296 103.541 13.23 103.577 ;
     RECT  85.68 103.469 85.698 103.577 ;
     RECT  25.884 103.469 26.586 103.613 ;
     RECT  61.488 103.325 62.226 103.613 ;
     RECT  70.704 103.469 71.118 103.613 ;
     RECT  76.176 103.517 84.654 103.649 ;
     RECT  86.436 103.469 87.138 103.649 ;
     RECT  61.848 103.613 62.226 103.661 ;
     RECT  76.176 103.649 76.59 103.661 ;
     RECT  86.436 103.649 86.454 103.694 ;
     RECT  72.432 103.517 75.15 103.709 ;
     RECT  52.812 103.541 57.078 103.757 ;
     RECT  58.356 103.469 58.374 103.757 ;
     RECT  59.256 103.565 59.634 103.757 ;
     RECT  61.848 103.661 61.866 103.757 ;
     RECT  72.504 103.709 74.106 103.757 ;
     RECT  76.572 103.661 76.59 103.757 ;
     RECT  25.884 103.613 26.226 103.775 ;
     RECT  30.276 103.469 39.078 104.285 ;
     RECT  52.848 103.757 54.954 104.285 ;
     RECT  55.692 103.757 56.322 104.285 ;
     RECT  57.06 103.757 57.078 104.285 ;
     RECT  53.388 104.285 54.954 104.333 ;
     RECT  55.692 104.285 55.71 104.333 ;
     RECT  30.276 104.285 33.534 104.381 ;
     RECT  34.524 104.285 35.406 104.861 ;
     RECT  53.388 104.333 54.918 104.861 ;
     RECT  70.884 103.613 71.118 104.861 ;
     RECT  65.556 103.469 69.894 104.863 ;
     RECT  71.1 104.861 71.118 104.891 ;
     RECT  30.276 104.381 33.498 104.909 ;
     RECT  65.556 104.863 70.002 105.511 ;
     RECT  10.296 103.577 12.51 105.556 ;
     RECT  30.852 104.909 32.094 105.629 ;
     RECT  32.868 104.909 32.886 105.677 ;
     RECT  77.616 103.649 84.654 105.701 ;
     RECT  31.248 105.629 32.094 105.725 ;
     RECT  34.956 104.861 35.406 105.725 ;
     RECT  36.252 104.285 39.078 105.725 ;
     RECT  53.388 104.861 53.406 105.725 ;
     RECT  54.36 104.861 54.63 105.725 ;
     RECT  71.496 105.595 71.514 105.725 ;
     RECT  73.368 103.757 73.674 105.725 ;
     RECT  75.132 103.709 75.15 105.725 ;
     RECT  26.208 103.775 26.226 105.773 ;
     RECT  36.756 105.725 39.078 105.773 ;
     RECT  41.256 103.541 43.614 105.773 ;
     RECT  46.368 103.427 51.174 105.773 ;
     RECT  77.616 105.701 84.582 105.773 ;
     RECT  10.26 105.556 12.51 105.804 ;
     RECT  20.052 103.343 24.606 105.804 ;
     RECT  36.756 105.773 39.006 105.804 ;
     RECT  41.364 105.773 43.614 105.804 ;
     RECT  46.548 105.773 51.102 105.804 ;
     RECT  65.556 105.511 70.11 105.804 ;
     RECT  77.652 105.773 84.51 105.804 ;
    LAYER M4 ;
     RECT  0.06 60.048 0.227 60.936 ;
     RECT  0.227 60.144 0.371 60.936 ;
     RECT  0.371 60.24 2.408 60.936 ;
     RECT  0.325 68.976 2.408 69 ;
     RECT  0.181 83.04 2.408 83.064 ;
     RECT  2.408 2.148 2.512 103.152 ;
     RECT  2.512 2.418 2.6 103.152 ;
     RECT  2.6 2.418 2.704 103.422 ;
     RECT  2.704 60.288 3.841 60.696 ;
     RECT  3.841 60.288 5.108 61.176 ;
     RECT  2.704 68.976 5.108 69 ;
     RECT  2.704 83.04 5.108 83.064 ;
     RECT  5.108 2.148 5.212 103.152 ;
     RECT  5.212 2.418 5.3 103.152 ;
     RECT  5.3 2.418 5.404 103.422 ;
     RECT  5.404 95.52 6.131 95.928 ;
     RECT  5.404 97.44 6.329 97.464 ;
     RECT  6.397 92.16 6.685 92.184 ;
     RECT  6.131 95.904 6.829 95.928 ;
     RECT  6.685 92.16 6.901 92.712 ;
     RECT  6.397 94.08 6.901 94.104 ;
     RECT  6.829 95.904 7.513 96.312 ;
     RECT  7.513 95.904 7.628 96.888 ;
     RECT  6.901 92.16 7.669 94.104 ;
     RECT  5.404 60.288 7.808 61.176 ;
     RECT  5.404 68.976 7.808 69 ;
     RECT  5.404 83.04 7.808 83.064 ;
     RECT  7.765 90.048 7.808 90.072 ;
     RECT  7.669 92.16 7.808 94.344 ;
     RECT  7.628 95.376 7.808 96.888 ;
     RECT  7.513 97.92 7.808 97.944 ;
     RECT  6.793 99.168 7.808 99.192 ;
     RECT  7.808 2.148 7.912 103.152 ;
     RECT  7.912 2.418 8 103.152 ;
     RECT  8 2.418 8.104 103.422 ;
     RECT  8.104 92.16 8.597 99.96 ;
     RECT  8.104 88.608 8.705 90.552 ;
     RECT  8.597 98.592 8.819 99.96 ;
     RECT  8.597 92.16 9.101 97.416 ;
     RECT  9.101 92.16 9.173 93.528 ;
     RECT  8.705 90.528 9.733 90.552 ;
     RECT  9.173 92.16 9.733 93.336 ;
     RECT  9.133 101.136 9.745 101.16 ;
     RECT  8.819 98.592 9.925 98.616 ;
     RECT  10.177 103.008 10.357 103.032 ;
     RECT  9.101 94.848 10.393 97.416 ;
     RECT  10.357 102.912 10.501 103.512 ;
     RECT  10.357 105.744 10.505 105.768 ;
     RECT  8.104 60.288 10.508 61.176 ;
     RECT  8.104 68.976 10.508 69 ;
     RECT  8.104 83.04 10.508 83.064 ;
     RECT  8.705 88.608 10.508 89.544 ;
     RECT  9.733 90.528 10.508 93.336 ;
     RECT  10.393 94.848 10.508 97.608 ;
     RECT  9.925 98.592 10.508 98.904 ;
     RECT  9.745 100.272 10.508 101.16 ;
     RECT  10.501 102.672 10.508 103.512 ;
     RECT  10.508 2.148 10.612 103.512 ;
     RECT  10.612 2.418 10.793 103.512 ;
     RECT  10.793 2.418 10.804 103.422 ;
     RECT  10.804 88.896 10.865 89.784 ;
     RECT  10.804 94.848 10.865 97.608 ;
     RECT  10.804 100.848 11.081 103.08 ;
     RECT  10.865 95.184 11.225 97.608 ;
     RECT  11.081 101.136 11.225 103.08 ;
     RECT  11.225 101.136 11.441 101.88 ;
     RECT  11.225 95.184 12.049 97.416 ;
     RECT  12.049 95.136 12.161 97.416 ;
     RECT  10.804 83.04 12.337 83.064 ;
     RECT  10.865 88.944 12.469 89.784 ;
     RECT  11.441 101.856 12.481 101.88 ;
     RECT  12.469 88.944 12.517 90.408 ;
     RECT  12.481 101.136 12.553 101.88 ;
     RECT  11.225 103.056 12.553 103.08 ;
     RECT  11.797 98.64 13.093 98.664 ;
     RECT  10.804 99.696 13.093 99.72 ;
     RECT  10.804 60.288 13.208 61.08 ;
     RECT  10.804 68.976 13.208 69 ;
     RECT  10.804 80.832 13.208 80.856 ;
     RECT  12.337 83.04 13.208 83.64 ;
     RECT  12.517 88.944 13.208 90.504 ;
     RECT  10.804 91.632 13.208 93.528 ;
     RECT  12.161 95.136 13.208 97.08 ;
     RECT  13.093 98.64 13.208 99.72 ;
     RECT  12.553 101.136 13.208 103.08 ;
     RECT  13.208 2.148 13.312 103.152 ;
     RECT  13.312 2.418 13.4 103.152 ;
     RECT  13.4 2.418 13.504 103.422 ;
     RECT  13.504 88.752 13.667 89.88 ;
     RECT  13.504 94.656 13.745 99.192 ;
     RECT  13.504 100.32 13.781 101.88 ;
     RECT  13.745 94.704 13.889 99.192 ;
     RECT  13.889 97.056 13.955 99.192 ;
     RECT  13.504 91.632 14.285 93.528 ;
     RECT  13.781 100.32 14.285 100.344 ;
     RECT  14.285 92.832 14.291 93.528 ;
     RECT  13.781 101.856 14.485 101.88 ;
     RECT  13.504 103.2 14.531 103.224 ;
     RECT  14.485 101.856 14.572 102.024 ;
     RECT  14.291 93.456 14.749 93.528 ;
     RECT  13.889 94.704 14.749 94.728 ;
     RECT  13.889 95.712 14.753 95.736 ;
     RECT  13.504 60.288 14.821 61.08 ;
     RECT  13.667 89.52 14.893 89.88 ;
     RECT  14.285 91.632 15.037 91.656 ;
     RECT  13.955 97.056 15.068 98.664 ;
     RECT  14.572 101.856 15.073 101.88 ;
     RECT  14.749 93.456 15.109 94.728 ;
     RECT  14.893 89.328 15.157 89.88 ;
     RECT  15.037 90.96 15.253 91.656 ;
     RECT  15.157 88.896 15.505 89.88 ;
     RECT  15.253 90.96 15.505 91.848 ;
     RECT  14.821 60.288 15.908 61.176 ;
     RECT  13.504 68.976 15.908 69 ;
     RECT  13.504 80.832 15.908 80.856 ;
     RECT  13.504 83.04 15.908 83.64 ;
     RECT  15.505 88.896 15.908 91.848 ;
     RECT  15.109 93.456 15.908 94.824 ;
     RECT  15.068 96.672 15.908 98.664 ;
     RECT  15.145 100.08 15.908 100.104 ;
     RECT  15.073 101.616 15.908 101.88 ;
     RECT  15.908 2.148 16.012 103.152 ;
     RECT  16.012 2.418 16.1 103.152 ;
     RECT  16.1 2.418 16.204 103.422 ;
     RECT  16.204 96.144 16.595 98.376 ;
     RECT  16.595 97.056 16.625 98.376 ;
     RECT  16.204 89.472 16.733 90.072 ;
     RECT  16.204 93.744 17.123 94.68 ;
     RECT  16.204 91.632 17.164 92.424 ;
     RECT  17.123 94.128 17.165 94.68 ;
     RECT  16.625 97.056 17.953 97.656 ;
     RECT  16.204 100.08 17.953 100.104 ;
     RECT  17.953 97.056 18.133 100.104 ;
     RECT  18.085 95.472 18.229 95.496 ;
     RECT  18.133 97.056 18.229 100.296 ;
     RECT  16.204 60.288 18.608 61.176 ;
     RECT  16.204 68.976 18.608 69 ;
     RECT  16.204 80.832 18.608 80.856 ;
     RECT  16.204 83.04 18.608 83.64 ;
     RECT  16.733 89.472 18.608 89.496 ;
     RECT  17.164 91.632 18.608 92.328 ;
     RECT  17.165 94.128 18.608 94.152 ;
     RECT  18.229 95.472 18.608 100.296 ;
     RECT  16.204 101.616 18.608 101.88 ;
     RECT  18.608 2.148 18.712 103.152 ;
     RECT  18.712 2.418 18.8 103.152 ;
     RECT  18.8 2.418 18.904 103.422 ;
     RECT  18.904 91.632 18.929 91.752 ;
     RECT  18.904 96.192 20.003 99.192 ;
     RECT  18.904 101.472 20.113 101.88 ;
     RECT  20.113 101.472 20.293 102.696 ;
     RECT  20.293 101.04 20.653 102.696 ;
     RECT  20.653 101.04 20.689 102.792 ;
     RECT  20.003 96.192 20.725 97.464 ;
     RECT  20.689 101.04 21.085 103.128 ;
     RECT  18.904 60.288 21.308 61.128 ;
     RECT  18.904 68.976 21.308 69 ;
     RECT  18.904 80.832 21.308 80.856 ;
     RECT  18.904 83.04 21.308 83.64 ;
     RECT  18.904 85.104 21.308 85.128 ;
     RECT  20.977 88.368 21.308 88.392 ;
     RECT  18.904 89.472 21.308 89.496 ;
     RECT  18.929 91.632 21.308 91.656 ;
     RECT  20.725 95.904 21.308 97.464 ;
     RECT  20.003 98.64 21.308 99.192 ;
     RECT  21.085 100.32 21.308 103.128 ;
     RECT  21.308 2.148 21.409 103.152 ;
     RECT  21.409 2.148 21.412 103.272 ;
     RECT  21.412 2.418 21.5 103.272 ;
     RECT  21.5 2.418 21.604 103.422 ;
     RECT  21.604 102.624 21.665 103.272 ;
     RECT  21.604 91.632 21.923 91.752 ;
     RECT  21.697 105.6 21.949 105.624 ;
     RECT  21.949 105.6 22.097 105.768 ;
     RECT  21.923 91.728 22.115 91.752 ;
     RECT  22.097 105.696 22.169 105.768 ;
     RECT  22.169 105.696 22.241 105.72 ;
     RECT  21.604 100.032 22.669 101.064 ;
     RECT  21.665 102.624 22.669 102.696 ;
     RECT  22.669 100.032 22.705 102.696 ;
     RECT  22.705 99.792 22.817 102.696 ;
     RECT  21.604 60.144 22.849 61.128 ;
     RECT  21.604 80.832 22.849 80.856 ;
     RECT  22.849 80.64 22.889 80.856 ;
     RECT  22.817 100.368 22.925 102.696 ;
     RECT  22.925 101.04 22.993 102.696 ;
     RECT  21.604 83.04 23.029 83.64 ;
     RECT  21.604 88.368 23.029 88.968 ;
     RECT  21.604 96.192 23.029 97.56 ;
     RECT  23.029 96 23.209 97.56 ;
     RECT  23.209 96 23.564 97.848 ;
     RECT  23.029 83.04 23.597 83.784 ;
     RECT  23.564 95.52 23.641 97.848 ;
     RECT  23.461 39.984 23.756 40.008 ;
     RECT  23.756 39.216 23.797 40.008 ;
     RECT  23.677 38.16 23.857 38.184 ;
     RECT  22.849 60.048 23.893 61.128 ;
     RECT  22.993 101.04 23.893 102.792 ;
     RECT  23.893 34.752 24.008 34.776 ;
     RECT  23.857 37.872 24.008 38.184 ;
     RECT  23.797 39.216 24.008 40.44 ;
     RECT  23.893 42.192 24.008 42.744 ;
     RECT  23.893 60.048 24.008 61.176 ;
     RECT  21.604 68.976 24.008 69 ;
     RECT  23.605 77.952 24.008 77.976 ;
     RECT  22.889 80.64 24.008 80.664 ;
     RECT  23.597 82.896 24.008 83.784 ;
     RECT  21.604 85.104 24.008 85.128 ;
     RECT  23.605 86.304 24.008 86.328 ;
     RECT  23.029 88.368 24.008 89.208 ;
     RECT  23.641 95.52 24.008 97.944 ;
     RECT  23.965 99.792 24.008 99.816 ;
     RECT  23.893 100.848 24.008 102.792 ;
     RECT  24.008 2.148 24.073 103.152 ;
     RECT  24.073 2.148 24.112 103.224 ;
     RECT  24.112 2.418 24.2 103.224 ;
     RECT  24.2 2.418 24.304 103.422 ;
     RECT  24.304 40.032 24.365 42.744 ;
     RECT  24.253 105.744 24.473 105.768 ;
     RECT  24.304 34.128 24.515 34.776 ;
     RECT  24.304 95.712 24.515 98.088 ;
     RECT  24.515 95.712 24.581 96.312 ;
     RECT  24.581 95.76 24.689 96.312 ;
     RECT  24.304 35.904 24.797 36.12 ;
     RECT  24.304 37.44 24.905 38.664 ;
     RECT  24.304 99.696 24.977 99.816 ;
     RECT  24.304 80.544 25.121 80.664 ;
     RECT  24.689 96 25.121 96.312 ;
     RECT  24.515 97.584 25.121 98.088 ;
     RECT  24.905 38.64 25.139 38.664 ;
     RECT  24.304 100.848 25.157 103.224 ;
     RECT  24.905 37.44 25.297 37.464 ;
     RECT  24.304 44.448 25.297 44.472 ;
     RECT  25.121 80.544 25.333 80.568 ;
     RECT  24.304 89.184 25.333 89.208 ;
     RECT  25.297 44.448 25.337 45.048 ;
     RECT  24.304 86.448 25.379 86.472 ;
     RECT  24.304 46.752 25.513 46.776 ;
     RECT  24.304 77.952 25.513 77.976 ;
     RECT  24.365 40.032 25.729 42.456 ;
     RECT  25.157 101.04 25.733 103.224 ;
     RECT  25.513 77.952 25.801 78.024 ;
     RECT  25.337 45.024 25.945 45.048 ;
     RECT  24.304 75.36 25.945 75.384 ;
     RECT  24.977 99.792 26.089 99.816 ;
     RECT  25.801 77.568 26.101 78.024 ;
     RECT  25.121 96 26.108 96.264 ;
     RECT  24.304 79.2 26.125 79.224 ;
     RECT  25.333 80.4 26.125 80.568 ;
     RECT  24.515 34.752 26.161 34.776 ;
     RECT  25.729 38.736 26.197 42.456 ;
     RECT  25.405 43.584 26.197 43.608 ;
     RECT  25.513 46.512 26.197 46.776 ;
     RECT  25.945 74.688 26.269 75.384 ;
     RECT  26.101 76.704 26.269 78.024 ;
     RECT  26.125 79.2 26.269 80.568 ;
     RECT  25.333 89.184 26.377 89.496 ;
     RECT  26.269 74.688 26.389 80.568 ;
     RECT  25.945 72.432 26.701 72.456 ;
     RECT  26.161 34.752 26.708 34.824 ;
     RECT  24.797 35.904 26.708 35.928 ;
     RECT  25.297 36.912 26.708 37.464 ;
     RECT  26.197 38.736 26.708 43.608 ;
     RECT  25.945 45.024 26.708 45.192 ;
     RECT  26.197 46.224 26.708 46.776 ;
     RECT  25.801 49.008 26.708 49.032 ;
     RECT  26.593 54.144 26.708 54.168 ;
     RECT  24.304 60.048 26.708 61.176 ;
     RECT  26.449 62.976 26.708 63 ;
     RECT  24.304 68.976 26.708 69 ;
     RECT  26.701 72.192 26.708 72.456 ;
     RECT  26.389 74.688 26.708 81.144 ;
     RECT  24.304 83.04 26.708 83.64 ;
     RECT  24.304 85.104 26.708 85.128 ;
     RECT  26.377 88.368 26.708 89.496 ;
     RECT  26.108 95.712 26.708 96.264 ;
     RECT  25.121 97.728 26.708 98.088 ;
     RECT  26.089 99.792 26.708 100.056 ;
     RECT  25.733 101.04 26.708 101.064 ;
     RECT  25.733 102.672 26.708 103.224 ;
     RECT  26.708 2.148 26.812 103.224 ;
     RECT  26.812 2.418 26.9 103.224 ;
     RECT  26.9 2.418 27.004 103.422 ;
     RECT  27.004 42.048 27.065 46.248 ;
     RECT  27.004 102.672 27.065 102.696 ;
     RECT  27.004 34.752 27.155 40.584 ;
     RECT  27.004 54.144 27.155 54.168 ;
     RECT  27.004 52.848 27.196 52.872 ;
     RECT  27.004 75.744 27.605 75.816 ;
     RECT  27.004 77.568 27.605 78.888 ;
     RECT  27.004 95.904 27.683 96.408 ;
     RECT  27.065 43.344 27.749 46.248 ;
     RECT  27.605 78.048 27.821 78.888 ;
     RECT  27.155 34.752 27.929 35.688 ;
     RECT  27.004 70.032 27.971 70.728 ;
     RECT  27.004 61.056 28.012 63.048 ;
     RECT  27.004 80.352 28.069 81.144 ;
     RECT  27.155 37.44 28.141 37.608 ;
     RECT  27.155 38.64 28.141 39.336 ;
     RECT  27.004 68.976 28.172 69 ;
     RECT  27.971 70.032 28.172 70.056 ;
     RECT  27.065 42.048 28.177 42.072 ;
     RECT  27.749 43.344 28.177 43.848 ;
     RECT  27.004 48.816 28.177 50.52 ;
     RECT  27.004 51.504 28.177 51.528 ;
     RECT  28.177 42.048 28.213 43.848 ;
     RECT  28.141 37.44 28.217 39.336 ;
     RECT  28.012 63.024 28.253 63.048 ;
     RECT  27.749 45.024 28.321 46.248 ;
     RECT  28.069 80.064 28.393 81.144 ;
     RECT  28.217 39.216 28.397 39.336 ;
     RECT  28.172 68.976 28.465 70.056 ;
     RECT  27.004 72.144 28.465 72.936 ;
     RECT  28.217 37.44 28.501 37.8 ;
     RECT  28.177 48.816 28.537 51.528 ;
     RECT  28.508 56.736 28.549 56.76 ;
     RECT  27.605 75.744 28.604 75.768 ;
     RECT  27.821 78.048 28.604 78.072 ;
     RECT  28.393 79.968 28.604 81.144 ;
     RECT  28.465 72.144 28.645 73.128 ;
     RECT  28.321 45.024 28.717 46.536 ;
     RECT  28.645 72.144 28.741 73.368 ;
     RECT  28.604 74.4 28.741 74.424 ;
     RECT  27.004 60.048 28.825 60.072 ;
     RECT  28.012 61.056 28.825 61.656 ;
     RECT  28.604 79.152 28.825 81.144 ;
     RECT  27.004 55.68 28.897 55.704 ;
     RECT  28.549 56.736 28.897 57.048 ;
     RECT  28.213 41.472 29.041 43.848 ;
     RECT  27.929 35.328 29.077 35.688 ;
     RECT  28.825 60.048 29.077 61.656 ;
     RECT  28.741 72.144 29.077 74.568 ;
     RECT  28.604 75.744 29.077 75.816 ;
     RECT  29.077 72.144 29.125 75.816 ;
     RECT  29.125 72.144 29.149 76.152 ;
     RECT  28.604 77.28 29.149 78.072 ;
     RECT  27.004 83.04 29.185 83.544 ;
     RECT  29.041 41.136 29.269 43.848 ;
     RECT  28.717 45.024 29.269 46.728 ;
     RECT  29.077 59.76 29.269 61.656 ;
     RECT  29.149 72.144 29.269 78.072 ;
     RECT  28.825 79.152 29.269 81.72 ;
     RECT  29.077 35.328 29.408 36.024 ;
     RECT  28.501 37.104 29.408 37.8 ;
     RECT  28.397 39.216 29.408 39.288 ;
     RECT  29.269 41.136 29.408 46.728 ;
     RECT  28.537 48.816 29.408 52.488 ;
     RECT  29.228 54.288 29.408 54.312 ;
     RECT  28.897 55.68 29.408 57.048 ;
     RECT  29.269 59.76 29.408 62.808 ;
     RECT  29.365 64.944 29.408 64.968 ;
     RECT  28.465 68.64 29.408 70.056 ;
     RECT  29.269 72.144 29.408 81.72 ;
     RECT  29.185 83.04 29.408 83.64 ;
     RECT  27.004 85.104 29.408 85.128 ;
     RECT  28.933 87.264 29.408 87.288 ;
     RECT  27.004 88.896 29.408 89.496 ;
     RECT  29.257 90.624 29.408 90.648 ;
     RECT  28.997 94.608 29.408 94.632 ;
     RECT  27.683 95.904 29.408 96.264 ;
     RECT  27.004 98.064 29.408 98.088 ;
     RECT  27.004 100.032 29.408 100.056 ;
     RECT  27.004 101.04 29.408 101.064 ;
     RECT  29.408 2.148 29.512 103.152 ;
     RECT  29.512 2.418 29.6 103.152 ;
     RECT  29.6 2.418 29.704 103.422 ;
     RECT  29.704 41.136 29.765 41.16 ;
     RECT  29.704 74.352 29.765 76.968 ;
     RECT  29.704 36 29.843 37.176 ;
     RECT  29.704 67.776 29.843 70.584 ;
     RECT  29.704 92.304 29.843 93.24 ;
     RECT  29.704 42.48 29.873 44.472 ;
     RECT  29.704 55.008 29.881 57.576 ;
     RECT  29.704 45.696 29.987 48.36 ;
     RECT  29.987 45.696 29.989 48.264 ;
     RECT  29.873 42.48 30.035 43.416 ;
     RECT  29.704 99.696 30.083 102.024 ;
     RECT  29.881 55.008 30.161 57.432 ;
     RECT  29.704 61.104 30.233 62.712 ;
     RECT  29.843 92.448 30.233 92.952 ;
     RECT  30.035 42.48 30.269 42.504 ;
     RECT  30.265 104.88 30.301 104.904 ;
     RECT  29.704 38.688 30.377 39.384 ;
     RECT  29.704 63.792 30.377 64.968 ;
     RECT  29.989 45.696 30.413 46.536 ;
     RECT  29.704 49.488 30.449 51.192 ;
     RECT  29.704 66.48 30.521 66.696 ;
     RECT  30.377 63.792 30.665 64.392 ;
     RECT  30.521 66.48 30.668 66.504 ;
     RECT  29.704 71.616 30.7 73.368 ;
     RECT  29.704 52.464 30.709 52.488 ;
     RECT  29.704 53.952 30.709 53.976 ;
     RECT  30.233 62.688 30.733 62.712 ;
     RECT  30.301 104.256 30.733 104.904 ;
     RECT  30.449 49.488 30.755 50.28 ;
     RECT  30.668 51.312 30.755 51.336 ;
     RECT  30.709 52.464 30.755 53.976 ;
     RECT  30.733 103.776 30.757 104.904 ;
     RECT  29.704 94.608 30.773 94.632 ;
     RECT  29.704 59.28 30.805 60.072 ;
     RECT  30.233 61.104 30.805 61.656 ;
     RECT  29.765 76.368 30.805 76.968 ;
     RECT  29.704 79.632 30.805 88.92 ;
     RECT  30.805 76.368 30.841 77.064 ;
     RECT  30.757 103.776 30.841 105.528 ;
     RECT  29.989 47.568 30.845 48.264 ;
     RECT  30.668 66.096 30.845 66.504 ;
     RECT  30.7 71.952 30.845 73.368 ;
     RECT  30.083 100.752 30.845 102.024 ;
     RECT  30.755 49.488 30.889 50.136 ;
     RECT  30.805 79.056 30.913 88.92 ;
     RECT  30.377 38.688 30.917 39.336 ;
     RECT  30.841 103.776 30.949 105.624 ;
     RECT  30.889 49.488 30.953 50.088 ;
     RECT  30.949 103.728 31.021 105.624 ;
     RECT  29.843 36.24 31.061 37.176 ;
     RECT  30.161 55.008 31.061 56.52 ;
     RECT  29.843 67.776 31.061 70.536 ;
     RECT  31.061 36.384 31.091 37.176 ;
     RECT  30.805 59.28 31.093 61.656 ;
     RECT  31.091 37.056 31.129 37.176 ;
     RECT  30.083 99.696 31.129 99.72 ;
     RECT  31.129 57.696 31.141 57.72 ;
     RECT  31.093 59.04 31.141 61.656 ;
     RECT  31.021 103.248 31.141 105.624 ;
     RECT  29.704 96.24 31.165 97.8 ;
     RECT  31.141 103.248 31.165 105.72 ;
     RECT  31.061 55.008 31.189 56.136 ;
     RECT  31.141 57.696 31.196 61.656 ;
     RECT  30.733 62.688 31.196 63.384 ;
     RECT  30.413 45.744 31.201 46.536 ;
     RECT  30.845 47.568 31.201 48.168 ;
     RECT  30.841 76.368 31.237 77.544 ;
     RECT  30.913 78.912 31.237 88.92 ;
     RECT  30.697 40.848 31.273 40.872 ;
     RECT  30.913 42.144 31.273 42.168 ;
     RECT  29.765 74.352 31.273 75.192 ;
     RECT  31.237 76.368 31.273 88.92 ;
     RECT  30.755 52.896 31.417 53.976 ;
     RECT  31.189 54.96 31.417 56.136 ;
     RECT  31.273 40.848 31.525 42.168 ;
     RECT  30.845 101.04 31.669 102.024 ;
     RECT  31.165 103.2 31.669 105.72 ;
     RECT  31.525 40.848 31.705 42.6 ;
     RECT  30.917 38.736 31.777 39.336 ;
     RECT  31.705 65.76 31.813 65.784 ;
     RECT  31.273 74.352 31.82 88.92 ;
     RECT  29.704 90 31.82 91.224 ;
     RECT  31.201 45.744 31.868 48.168 ;
     RECT  31.777 38.736 31.909 39.768 ;
     RECT  31.705 40.848 31.909 43.128 ;
     RECT  31.868 45.552 31.909 48.168 ;
     RECT  30.233 92.928 31.921 92.952 ;
     RECT  31.345 94.08 31.921 94.104 ;
     RECT  31.165 96.24 31.957 97.896 ;
     RECT  31.813 65.76 32.029 65.976 ;
     RECT  31.669 101.04 32.105 105.72 ;
     RECT  31.129 37.056 32.108 37.656 ;
     RECT  31.909 38.736 32.108 43.128 ;
     RECT  31.909 44.736 32.108 48.168 ;
     RECT  30.953 49.536 32.108 50.088 ;
     RECT  31.765 51.408 32.108 51.432 ;
     RECT  31.417 52.896 32.108 56.136 ;
     RECT  31.196 57.696 32.108 63.384 ;
     RECT  30.665 64.368 32.108 64.392 ;
     RECT  32.029 65.76 32.108 66.744 ;
     RECT  31.061 67.776 32.108 69 ;
     RECT  31.061 70.368 32.108 70.536 ;
     RECT  30.845 72.144 32.108 73.368 ;
     RECT  31.82 74.352 32.108 91.224 ;
     RECT  31.921 92.928 32.108 94.104 ;
     RECT  31.957 95.472 32.108 97.896 ;
     RECT  31.129 99.072 32.108 99.72 ;
     RECT  32.105 101.04 32.108 105.672 ;
     RECT  32.108 2.148 32.212 105.672 ;
     RECT  32.212 2.418 32.404 105.672 ;
     RECT  32.404 101.856 32.435 105.672 ;
     RECT  32.404 90.624 32.465 90.648 ;
     RECT  32.404 95.04 32.537 96.504 ;
     RECT  32.404 37.632 32.723 40.392 ;
     RECT  32.404 54.96 32.753 56.472 ;
     RECT  32.404 71.664 32.789 77.304 ;
     RECT  32.404 41.616 32.825 43.368 ;
     RECT  32.789 71.664 32.825 76.536 ;
     RECT  32.435 105.648 32.897 105.672 ;
     RECT  32.404 61.104 32.933 69.576 ;
     RECT  32.537 95.04 32.933 96.12 ;
     RECT  32.404 44.736 33.005 45.72 ;
     RECT  32.825 41.616 33.041 42.168 ;
     RECT  32.404 98.592 33.049 100.872 ;
     RECT  32.404 57.552 33.077 60.072 ;
     RECT  33.005 44.736 33.221 45.192 ;
     RECT  33.077 57.552 33.221 59.064 ;
     RECT  33.049 98.592 33.221 100.344 ;
     RECT  32.404 78.624 33.347 89.496 ;
     RECT  33.221 44.736 33.365 45 ;
     RECT  33.347 78.624 33.388 88.92 ;
     RECT  32.825 71.664 33.397 71.688 ;
     RECT  32.404 49.536 33.433 50.088 ;
     RECT  32.404 51.408 33.433 51.96 ;
     RECT  32.404 97.584 33.437 97.608 ;
     RECT  32.435 101.856 33.469 104.328 ;
     RECT  32.404 93.504 33.493 93.528 ;
     RECT  33.493 93.504 33.539 93.72 ;
     RECT  32.404 47.28 33.577 48.216 ;
     RECT  33.433 49.536 33.577 51.96 ;
     RECT  32.404 53.04 33.577 53.88 ;
     RECT  32.933 65.04 33.577 69.576 ;
     RECT  33.539 93.696 33.58 93.72 ;
     RECT  33.493 91.728 33.581 91.752 ;
     RECT  33.469 101.856 33.587 104.904 ;
     RECT  33.577 65.04 33.589 69.816 ;
     RECT  33.397 71.28 33.589 71.688 ;
     RECT  32.723 37.632 33.689 40.344 ;
     RECT  33.689 38.784 33.733 40.344 ;
     RECT  33.041 41.616 33.733 41.64 ;
     RECT  33.221 57.552 33.757 59.016 ;
     RECT  33.733 38.784 33.779 41.64 ;
     RECT  33.689 37.632 33.827 37.656 ;
     RECT  33.077 60.048 33.829 60.072 ;
     RECT  32.933 61.104 33.829 63.768 ;
     RECT  32.825 72.72 33.829 74.472 ;
     RECT  32.825 75.456 33.829 76.536 ;
     RECT  32.933 95.184 33.865 96.12 ;
     RECT  33.757 57.456 33.901 59.016 ;
     RECT  33.577 46.848 33.932 48.216 ;
     RECT  33.577 49.536 33.932 53.88 ;
     RECT  32.825 43.296 34.009 43.368 ;
     RECT  33.829 60.048 34.117 63.768 ;
     RECT  32.753 54.96 34.124 55.8 ;
     RECT  33.932 46.848 34.153 53.88 ;
     RECT  33.589 65.04 34.153 71.688 ;
     RECT  33.829 72.72 34.153 76.536 ;
     RECT  33.388 78.624 34.153 88.824 ;
     RECT  34.124 54.912 34.165 55.8 ;
     RECT  33.901 57.024 34.165 59.016 ;
     RECT  33.973 93.792 34.165 94.104 ;
     RECT  33.865 95.184 34.165 96.936 ;
     RECT  34.117 60 34.189 63.768 ;
     RECT  34.153 65.04 34.309 76.536 ;
     RECT  33.221 100.32 34.333 100.344 ;
     RECT  34.009 43.104 34.405 43.368 ;
     RECT  34.333 100.32 34.405 100.632 ;
     RECT  34.153 78.096 34.441 88.824 ;
     RECT  34.045 90.288 34.441 90.312 ;
     RECT  34.153 46.128 34.477 53.88 ;
     RECT  34.309 65.04 34.549 77.016 ;
     RECT  34.441 78.096 34.549 90.312 ;
     RECT  33.587 101.856 34.553 104.856 ;
     RECT  34.553 101.856 34.585 104.28 ;
     RECT  33.221 98.592 34.597 99.192 ;
     RECT  34.405 100.272 34.597 100.632 ;
     RECT  34.165 54.912 34.693 59.016 ;
     RECT  34.189 60 34.693 63.816 ;
     RECT  34.405 43.056 34.729 43.368 ;
     RECT  33.779 38.784 34.808 41.496 ;
     RECT  34.729 42.816 34.808 43.368 ;
     RECT  33.365 44.736 34.808 44.76 ;
     RECT  34.477 45.984 34.808 53.88 ;
     RECT  34.693 54.912 34.808 63.816 ;
     RECT  34.549 65.04 34.808 90.312 ;
     RECT  34.297 92.304 34.808 92.328 ;
     RECT  34.165 93.792 34.808 96.936 ;
     RECT  34.597 98.592 34.808 100.632 ;
     RECT  34.585 101.616 34.808 104.28 ;
     RECT  34.808 2.148 34.912 104.28 ;
     RECT  34.912 2.418 35.104 104.28 ;
     RECT  35.104 39.84 35.165 43.608 ;
     RECT  34.789 105.408 35.219 105.72 ;
     RECT  35.104 73.488 35.273 76.728 ;
     RECT  35.165 40.704 35.309 43.608 ;
     RECT  35.104 50.016 35.309 51.96 ;
     RECT  35.219 105.504 35.309 105.72 ;
     RECT  35.309 105.6 35.315 105.72 ;
     RECT  35.309 50.016 35.363 51.72 ;
     RECT  35.273 73.488 35.452 75.24 ;
     RECT  35.104 61.344 35.453 61.896 ;
     RECT  35.104 95.472 35.453 96.936 ;
     RECT  35.363 50.112 35.489 51.72 ;
     RECT  35.104 66.24 35.489 66.264 ;
     RECT  35.104 56.496 35.633 57.72 ;
     RECT  35.104 70.272 35.699 72.072 ;
     RECT  35.104 45.984 35.705 48.168 ;
     RECT  35.452 73.488 35.705 74.856 ;
     RECT  35.705 73.92 35.74 74.856 ;
     RECT  35.74 74.064 35.843 74.856 ;
     RECT  35.705 46.224 35.891 48.168 ;
     RECT  35.453 95.664 35.987 96.936 ;
     RECT  35.987 96.72 35.993 96.936 ;
     RECT  35.699 70.272 36.029 71.688 ;
     RECT  35.987 95.664 36.173 95.688 ;
     RECT  35.273 76.272 36.205 76.728 ;
     RECT  35.104 77.808 36.205 91.992 ;
     RECT  35.104 101.856 36.275 104.28 ;
     RECT  35.315 105.648 36.281 105.72 ;
     RECT  35.104 67.584 36.313 69 ;
     RECT  35.104 98.592 36.421 100.632 ;
     RECT  36.275 101.856 36.421 103.752 ;
     RECT  36.313 66.672 36.457 69 ;
     RECT  35.891 46.848 36.461 48.168 ;
     RECT  36.457 66.288 36.461 69 ;
     RECT  35.453 61.632 36.469 61.896 ;
     RECT  35.104 63.504 36.469 63.528 ;
     RECT  35.489 51.408 36.493 51.72 ;
     RECT  36.461 67.584 36.493 69 ;
     RECT  36.281 105.648 36.497 105.672 ;
     RECT  36.421 98.544 36.508 100.632 ;
     RECT  36.205 76.272 36.533 91.992 ;
     RECT  35.104 93.744 36.533 94.296 ;
     RECT  35.309 40.704 36.601 40.728 ;
     RECT  35.309 42.144 36.601 43.608 ;
     RECT  35.633 56.496 36.601 57.624 ;
     RECT  36.469 61.632 36.601 63.528 ;
     RECT  36.421 101.616 36.641 103.752 ;
     RECT  36.601 40.704 36.673 43.608 ;
     RECT  35.104 44.736 36.673 44.76 ;
     RECT  35.489 50.112 36.709 50.136 ;
     RECT  36.533 76.272 36.781 81.48 ;
     RECT  35.104 58.752 36.812 60.36 ;
     RECT  36.601 61.584 36.812 63.528 ;
     RECT  36.709 49.872 36.889 50.136 ;
     RECT  36.493 51.216 36.889 51.72 ;
     RECT  35.104 54.96 36.961 55.272 ;
     RECT  36.601 56.352 36.961 57.624 ;
     RECT  36.673 40.704 36.997 44.808 ;
     RECT  36.889 49.488 37.033 51.72 ;
     RECT  36.812 58.752 37.033 63.528 ;
     RECT  36.508 98.592 37.033 100.632 ;
     RECT  36.641 101.616 37.033 103.704 ;
     RECT  36.781 76.032 37.069 81.48 ;
     RECT  36.029 70.608 37.141 71.688 ;
     RECT  35.843 74.4 37.189 74.856 ;
     RECT  36.533 94.272 37.213 94.296 ;
     RECT  37.189 74.064 37.237 74.856 ;
     RECT  37.033 49.392 37.249 51.72 ;
     RECT  36.493 67.584 37.285 69.336 ;
     RECT  37.141 70.608 37.285 71.784 ;
     RECT  36.997 40.704 37.321 45.576 ;
     RECT  36.461 46.848 37.321 46.968 ;
     RECT  37.237 74.064 37.333 74.952 ;
     RECT  37.033 98.592 37.361 103.704 ;
     RECT  37.333 73.584 37.381 74.952 ;
     RECT  37.249 49.392 37.429 51.96 ;
     RECT  35.104 52.992 37.429 53.88 ;
     RECT  36.461 47.952 37.465 48.168 ;
     RECT  37.285 67.584 37.465 71.784 ;
     RECT  37.321 40.704 37.508 46.968 ;
     RECT  37.465 47.952 37.508 48.264 ;
     RECT  37.429 49.392 37.508 53.88 ;
     RECT  36.961 54.96 37.508 57.624 ;
     RECT  37.033 58.752 37.508 63.624 ;
     RECT  36.997 64.896 37.508 64.92 ;
     RECT  36.461 66.288 37.508 66.312 ;
     RECT  37.465 67.344 37.508 71.784 ;
     RECT  37.381 72.816 37.508 74.952 ;
     RECT  37.069 75.936 37.508 81.48 ;
     RECT  36.533 82.752 37.508 91.992 ;
     RECT  37.237 93.168 37.508 93.192 ;
     RECT  37.213 94.272 37.508 94.68 ;
     RECT  35.993 96.72 37.508 96.744 ;
     RECT  37.361 98.592 37.508 103.422 ;
     RECT  37.508 2.148 37.612 103.422 ;
     RECT  37.612 2.418 37.804 103.422 ;
     RECT  37.465 104.832 37.897 104.856 ;
     RECT  37.897 104.832 37.901 105.768 ;
     RECT  37.804 71.424 37.955 74.376 ;
     RECT  37.804 102.624 37.973 102.648 ;
     RECT  37.804 54.864 38.045 61.992 ;
     RECT  37.804 77.616 38.045 79.56 ;
     RECT  37.901 105.744 38.045 105.768 ;
     RECT  37.804 44.976 38.14 46.872 ;
     RECT  37.804 63.264 38.147 70.296 ;
     RECT  37.804 88.464 38.189 92.472 ;
     RECT  38.189 91.536 38.38 92.472 ;
     RECT  37.955 71.424 38.405 71.64 ;
     RECT  37.804 75.936 38.477 76.584 ;
     RECT  38.14 45.552 38.513 46.872 ;
     RECT  38.045 56.016 38.621 61.992 ;
     RECT  38.38 92.352 38.721 92.472 ;
     RECT  37.955 72.816 38.873 74.376 ;
     RECT  37.804 49.488 38.941 50.136 ;
     RECT  37.804 51.216 38.941 53.88 ;
     RECT  37.804 47.904 38.945 48.264 ;
     RECT  37.804 80.592 39.013 87.288 ;
     RECT  38.189 88.464 39.013 90.312 ;
     RECT  37.804 93.744 39.013 93.768 ;
     RECT  38.147 63.6 39.049 70.296 ;
     RECT  38.405 71.424 39.049 71.448 ;
     RECT  37.804 99.168 39.049 101.64 ;
     RECT  38.797 103.2 39.049 103.224 ;
     RECT  38.833 41.856 39.121 41.88 ;
     RECT  39.121 41.76 39.157 41.88 ;
     RECT  39.049 99.168 39.157 103.224 ;
     RECT  39.157 98.592 39.197 103.224 ;
     RECT  39.013 93.552 39.229 93.768 ;
     RECT  37.804 43.536 39.301 43.608 ;
     RECT  38.477 76.272 39.301 76.584 ;
     RECT  38.045 77.616 39.301 77.64 ;
     RECT  38.621 61.536 39.337 61.992 ;
     RECT  39.229 93.504 39.337 93.768 ;
     RECT  39.085 95.136 39.337 95.16 ;
     RECT  38.513 46.176 39.409 46.872 ;
     RECT  38.945 47.952 39.445 48.264 ;
     RECT  38.941 49.488 39.445 53.88 ;
     RECT  39.445 47.952 39.692 53.88 ;
     RECT  38.045 54.864 39.692 54.888 ;
     RECT  39.013 80.592 39.733 90.312 ;
     RECT  38.045 78.624 39.805 79.56 ;
     RECT  39.733 80.544 39.805 90.312 ;
     RECT  38.721 92.448 39.841 92.472 ;
     RECT  39.337 93.504 39.841 95.16 ;
     RECT  38.873 72.816 39.877 73.896 ;
     RECT  39.836 75.12 39.877 75.144 ;
     RECT  39.805 78.624 39.877 90.312 ;
     RECT  39.157 41.76 39.949 42.312 ;
     RECT  39.301 43.392 39.949 43.608 ;
     RECT  39.409 46.176 39.949 46.92 ;
     RECT  39.692 47.952 39.949 54.888 ;
     RECT  38.621 56.016 39.949 60.312 ;
     RECT  39.337 61.536 39.949 62.136 ;
     RECT  39.877 72.816 39.985 75.144 ;
     RECT  39.949 46.176 40.057 54.888 ;
     RECT  39.949 56.016 40.057 62.136 ;
     RECT  39.841 92.448 40.165 95.16 ;
     RECT  39.949 41.76 40.208 43.608 ;
     RECT  39.805 44.928 40.208 44.952 ;
     RECT  40.057 46.176 40.208 62.184 ;
     RECT  39.049 63.6 40.208 71.448 ;
     RECT  39.985 72.768 40.208 75.144 ;
     RECT  39.301 76.272 40.208 77.64 ;
     RECT  39.877 78.624 40.208 90.648 ;
     RECT  40.165 92.448 40.208 95.208 ;
     RECT  40.129 96.576 40.208 96.6 ;
     RECT  39.197 98.592 40.208 100.584 ;
     RECT  39.197 101.616 40.208 103.224 ;
     RECT  40.208 2.148 40.312 103.224 ;
     RECT  40.312 2.418 40.4 103.224 ;
     RECT  40.4 2.418 40.504 103.422 ;
     RECT  40.504 101.568 40.565 102.456 ;
     RECT  40.504 80.016 40.601 87.624 ;
     RECT  40.504 49.296 40.673 57.144 ;
     RECT  40.504 58.128 40.835 62.184 ;
     RECT  40.504 92.064 40.889 95.208 ;
     RECT  40.673 49.872 40.979 57.144 ;
     RECT  40.979 49.872 41.033 51.864 ;
     RECT  40.504 71.088 41.105 72.84 ;
     RECT  40.889 92.064 41.123 92.808 ;
     RECT  40.889 94.32 41.141 95.208 ;
     RECT  41.141 94.32 41.315 95.16 ;
     RECT  40.504 96.192 41.356 96.984 ;
     RECT  41.123 92.352 41.357 92.808 ;
     RECT  40.979 52.992 41.411 57.144 ;
     RECT  41.105 71.088 41.429 71.208 ;
     RECT  40.601 87.264 41.497 87.624 ;
     RECT  40.504 88.752 41.497 88.92 ;
     RECT  40.601 80.016 41.501 86.28 ;
     RECT  40.835 58.656 41.507 62.184 ;
     RECT  40.504 44.928 41.557 48.216 ;
     RECT  40.504 90 41.569 90.984 ;
     RECT  40.504 64.944 41.573 69.864 ;
     RECT  41.033 50.88 41.609 51.864 ;
     RECT  41.507 58.656 41.609 60.984 ;
     RECT  41.501 84.096 41.641 86.28 ;
     RECT  41.497 87.264 41.641 88.92 ;
     RECT  41.557 44.928 41.645 48.888 ;
     RECT  40.504 98.064 41.645 98.088 ;
     RECT  41.507 62.064 41.677 62.184 ;
     RECT  40.504 63.456 41.677 63.768 ;
     RECT  41.429 71.088 41.677 71.112 ;
     RECT  40.565 101.568 41.681 101.88 ;
     RECT  41.105 72.336 41.701 72.84 ;
     RECT  40.504 73.92 41.701 74.712 ;
     RECT  41.569 89.952 41.713 90.984 ;
     RECT  41.411 54.864 41.788 57.144 ;
     RECT  41.645 47.904 41.933 48.888 ;
     RECT  40.504 42.144 41.965 43.848 ;
     RECT  41.965 42 42.001 43.848 ;
     RECT  41.645 44.928 42.001 46.92 ;
     RECT  41.501 80.016 42.073 83.064 ;
     RECT  41.681 101.856 42.073 101.88 ;
     RECT  40.504 76.272 42.109 77.64 ;
     RECT  42.073 79.296 42.253 83.064 ;
     RECT  42.217 99.696 42.289 99.72 ;
     RECT  41.713 89.952 42.332 91.32 ;
     RECT  41.357 92.352 42.332 92.616 ;
     RECT  42.289 99.696 42.361 100.152 ;
     RECT  42.073 101.856 42.397 102.312 ;
     RECT  41.411 52.992 42.469 53.88 ;
     RECT  41.788 54.864 42.469 54.888 ;
     RECT  41.033 49.872 42.505 49.896 ;
     RECT  41.641 84.096 42.505 88.92 ;
     RECT  42.332 89.952 42.505 92.616 ;
     RECT  42.397 101.856 42.577 102.408 ;
     RECT  41.315 94.32 42.613 94.584 ;
     RECT  42.469 52.992 42.62 54.888 ;
     RECT  41.609 50.88 42.649 51.816 ;
     RECT  42.62 52.896 42.649 54.888 ;
     RECT  42.253 79.008 42.649 83.064 ;
     RECT  41.701 72.336 42.661 74.712 ;
     RECT  42.661 72.24 42.685 74.712 ;
     RECT  42.109 75.744 42.685 77.64 ;
     RECT  42.577 101.856 42.696 102.792 ;
     RECT  42.361 99.696 42.757 100.296 ;
     RECT  42.696 101.472 42.757 102.792 ;
     RECT  42.649 78.624 42.793 83.064 ;
     RECT  42.505 84.096 42.793 92.616 ;
     RECT  42.001 42 42.908 46.92 ;
     RECT  41.933 47.904 42.908 48.456 ;
     RECT  42.505 49.584 42.908 49.896 ;
     RECT  42.649 50.88 42.908 54.888 ;
     RECT  41.788 55.872 42.908 57.144 ;
     RECT  41.609 58.656 42.908 60.792 ;
     RECT  41.677 62.064 42.908 63.768 ;
     RECT  41.573 64.944 42.908 69.576 ;
     RECT  41.677 70.896 42.908 71.112 ;
     RECT  42.685 72.24 42.908 77.64 ;
     RECT  42.793 78.624 42.908 92.616 ;
     RECT  42.613 94.032 42.908 94.584 ;
     RECT  41.356 96.192 42.908 96.888 ;
     RECT  42.757 99.696 42.908 102.792 ;
     RECT  42.908 2.148 43.012 103.152 ;
     RECT  43.012 2.418 43.1 103.152 ;
     RECT  42.865 105.6 43.153 105.624 ;
     RECT  43.1 2.418 43.189 103.422 ;
     RECT  43.153 105.6 43.189 105.672 ;
     RECT  43.189 2.418 43.204 103.512 ;
     RECT  43.189 105.6 43.265 105.768 ;
     RECT  43.204 50.928 43.301 63.624 ;
     RECT  43.204 101.856 43.331 103.512 ;
     RECT  43.265 105.648 43.337 105.768 ;
     RECT  43.204 70.608 43.345 77.64 ;
     RECT  43.204 99.744 43.373 100.824 ;
     RECT  43.301 50.928 43.379 63.432 ;
     RECT  43.204 47.904 43.409 49.896 ;
     RECT  43.379 61.728 43.409 63.432 ;
     RECT  43.204 65.232 43.517 69.528 ;
     RECT  43.373 99.744 43.517 100.632 ;
     RECT  43.409 47.952 43.589 49.896 ;
     RECT  43.204 78.624 43.697 89.784 ;
     RECT  43.697 81.072 43.715 89.784 ;
     RECT  43.589 49.488 43.733 49.896 ;
     RECT  43.697 78.624 43.805 80.088 ;
     RECT  43.379 50.928 43.907 60.6 ;
     RECT  43.204 40.992 43.955 46.872 ;
     RECT  43.907 55.92 44.057 60.6 ;
     RECT  43.955 42.288 44.099 46.872 ;
     RECT  43.715 81.312 44.165 89.784 ;
     RECT  43.409 61.728 44.201 62.04 ;
     RECT  43.733 49.488 44.237 49.512 ;
     RECT  43.204 39.84 44.305 39.864 ;
     RECT  43.955 40.992 44.305 41.16 ;
     RECT  43.345 70.848 44.305 77.64 ;
     RECT  43.805 78.624 44.305 79.512 ;
     RECT  44.305 91.056 44.377 91.08 ;
     RECT  43.204 97.392 44.389 98.376 ;
     RECT  43.517 99.744 44.389 99.768 ;
     RECT  43.409 63.408 44.413 63.432 ;
     RECT  43.204 94.992 44.444 96.216 ;
     RECT  43.589 47.952 44.453 48.456 ;
     RECT  44.165 81.312 44.453 88.92 ;
     RECT  44.389 97.392 44.476 99.768 ;
     RECT  44.099 42.288 44.489 45.576 ;
     RECT  44.444 94.992 44.531 96.36 ;
     RECT  44.305 70.848 44.557 79.512 ;
     RECT  44.305 39.84 44.561 41.16 ;
     RECT  44.557 70.8 44.579 79.512 ;
     RECT  43.907 50.928 44.597 54.888 ;
     RECT  44.489 43.536 44.633 45.576 ;
     RECT  44.579 70.8 44.633 75.576 ;
     RECT  44.597 50.928 44.773 51.528 ;
     RECT  44.579 76.56 44.809 79.512 ;
     RECT  44.531 94.992 44.881 95.736 ;
     RECT  44.597 53.328 45.025 54.888 ;
     RECT  44.057 56.016 45.025 60.6 ;
     RECT  44.809 76.56 45.025 80.04 ;
     RECT  44.099 46.56 45.041 46.872 ;
     RECT  45.025 53.328 45.097 60.6 ;
     RECT  44.201 61.728 45.097 61.752 ;
     RECT  44.773 50.784 45.133 51.528 ;
     RECT  45.041 46.56 45.169 46.92 ;
     RECT  44.476 99.504 45.253 99.768 ;
     RECT  44.413 63.408 45.313 64.104 ;
     RECT  43.517 65.232 45.313 69.48 ;
     RECT  44.561 40.272 45.385 41.16 ;
     RECT  44.489 42.288 45.385 42.552 ;
     RECT  45.313 63.408 45.452 69.48 ;
     RECT  44.633 70.8 45.452 75.432 ;
     RECT  45.452 63.408 45.493 69.528 ;
     RECT  45.452 70.704 45.493 75.432 ;
     RECT  45.493 39.216 45.565 39.24 ;
     RECT  45.385 40.272 45.565 42.552 ;
     RECT  44.377 90.048 45.565 91.08 ;
     RECT  43.204 92.448 45.565 92.472 ;
     RECT  45.565 39.216 45.608 42.552 ;
     RECT  44.633 43.536 45.608 45.144 ;
     RECT  45.169 46.32 45.608 46.92 ;
     RECT  44.453 47.952 45.608 48.264 ;
     RECT  45.133 50.304 45.608 51.528 ;
     RECT  45.097 53.328 45.608 61.752 ;
     RECT  45.493 63.408 45.608 75.432 ;
     RECT  45.025 76.56 45.608 80.28 ;
     RECT  44.453 81.312 45.608 87.288 ;
     RECT  44.453 88.368 45.608 88.92 ;
     RECT  45.565 90.048 45.608 92.712 ;
     RECT  44.881 94.944 45.608 95.736 ;
     RECT  44.476 97.392 45.608 98.376 ;
     RECT  45.253 99.504 45.608 100.488 ;
     RECT  43.331 101.856 45.608 103.224 ;
     RECT  45.608 2.148 45.712 103.224 ;
     RECT  45.712 2.418 45.8 103.224 ;
     RECT  45.8 2.418 45.904 103.422 ;
     RECT  45.904 50.016 46.325 81.48 ;
     RECT  45.904 96.768 46.325 100.488 ;
     RECT  45.904 38.736 46.499 46.92 ;
     RECT  45.904 91.872 46.541 94.968 ;
     RECT  45.904 90.576 46.685 90.6 ;
     RECT  46.325 98.352 46.685 100.488 ;
     RECT  46.325 50.016 46.739 77.688 ;
     RECT  46.645 105.648 46.741 105.672 ;
     RECT  46.739 50.016 46.757 61.56 ;
     RECT  46.757 61.536 46.793 61.56 ;
     RECT  45.904 82.464 46.793 88.872 ;
     RECT  46.741 105.648 46.829 105.768 ;
     RECT  46.499 38.736 46.865 40.632 ;
     RECT  46.757 50.016 46.937 60.408 ;
     RECT  46.793 82.464 46.937 87.432 ;
     RECT  46.541 91.872 46.969 94.632 ;
     RECT  46.865 39.168 46.973 40.632 ;
     RECT  46.937 82.464 46.973 87.288 ;
     RECT  46.685 98.688 47.005 100.488 ;
     RECT  45.904 101.712 47.005 102.936 ;
     RECT  46.969 91.584 47.009 94.632 ;
     RECT  46.499 41.664 47.045 46.92 ;
     RECT  46.829 105.648 47.113 105.72 ;
     RECT  46.937 50.016 47.153 54.888 ;
     RECT  46.739 62.544 47.153 77.688 ;
     RECT  46.973 39.168 47.189 40.44 ;
     RECT  47.113 105.6 47.197 105.72 ;
     RECT  47.197 105.696 47.212 105.72 ;
     RECT  47.045 42.288 47.269 46.92 ;
     RECT  45.904 47.952 47.269 48.936 ;
     RECT  47.153 75.792 47.317 77.688 ;
     RECT  47.189 40.368 47.333 40.44 ;
     RECT  46.325 79.248 47.437 81.48 ;
     RECT  46.973 82.464 47.437 84.168 ;
     RECT  47.005 98.688 47.437 102.936 ;
     RECT  47.317 75.792 47.581 78.072 ;
     RECT  47.581 75.792 47.617 78.216 ;
     RECT  47.437 79.248 47.617 84.168 ;
     RECT  47.269 42.288 47.761 48.936 ;
     RECT  47.153 50.016 47.761 53.88 ;
     RECT  47.153 62.544 47.797 74.712 ;
     RECT  47.437 98.688 47.797 103.224 ;
     RECT  46.325 96.768 47.869 96.792 ;
     RECT  47.797 98.064 47.941 103.224 ;
     RECT  46.793 88.848 48.085 88.872 ;
     RECT  47.581 90.432 48.085 90.456 ;
     RECT  47.009 91.584 48.085 94.104 ;
     RECT  48.085 90.432 48.121 94.104 ;
     RECT  46.937 56.016 48.149 60.408 ;
     RECT  46.973 85.152 48.149 87.288 ;
     RECT  47.189 39.168 48.157 39.288 ;
     RECT  47.333 40.368 48.157 40.392 ;
     RECT  48.085 88.416 48.181 88.872 ;
     RECT  48.121 90 48.181 94.104 ;
     RECT  47.617 75.792 48.229 84.168 ;
     RECT  48.149 85.152 48.229 87.432 ;
     RECT  48.157 39.168 48.308 40.392 ;
     RECT  47.761 42.288 48.308 53.88 ;
     RECT  47.153 54.864 48.308 54.888 ;
     RECT  48.149 56.016 48.308 60.84 ;
     RECT  47.797 62.448 48.308 74.712 ;
     RECT  48.229 75.792 48.308 87.432 ;
     RECT  48.181 88.416 48.308 94.104 ;
     RECT  47.869 95.904 48.308 96.792 ;
     RECT  47.941 97.92 48.308 103.224 ;
     RECT  48.308 2.148 48.412 103.224 ;
     RECT  48.412 2.418 48.5 103.224 ;
     RECT  48.5 2.418 48.604 103.422 ;
     RECT  48.604 42.288 48.665 48.984 ;
     RECT  48.604 97.536 48.665 100.248 ;
     RECT  48.665 97.536 48.701 99.768 ;
     RECT  48.604 40.368 48.773 40.392 ;
     RECT  48.701 97.536 48.796 99.576 ;
     RECT  48.604 53.856 48.809 61.512 ;
     RECT  48.604 88.368 48.809 90.072 ;
     RECT  48.604 52.704 48.989 52.824 ;
     RECT  48.604 62.544 49.025 76.584 ;
     RECT  49.025 62.688 49.097 76.584 ;
     RECT  48.809 88.368 49.097 89.88 ;
     RECT  48.809 53.856 49.139 58.2 ;
     RECT  49.097 62.688 49.277 74.616 ;
     RECT  48.665 42.288 49.283 48.648 ;
     RECT  48.604 77.616 49.313 87.096 ;
     RECT  49.283 42.288 49.349 45.192 ;
     RECT  49.349 43.104 49.529 45.192 ;
     RECT  49.277 62.784 49.529 74.616 ;
     RECT  48.604 50.016 49.633 51.672 ;
     RECT  48.604 91.968 49.667 94.392 ;
     RECT  49.633 50.016 49.669 51.72 ;
     RECT  48.989 52.704 49.669 52.728 ;
     RECT  49.667 91.968 49.708 94.056 ;
     RECT  48.809 59.472 49.777 61.512 ;
     RECT  49.097 88.416 49.781 89.88 ;
     RECT  48.604 101.424 49.817 102.888 ;
     RECT  48.604 95.904 49.849 95.928 ;
     RECT  49.708 91.968 49.885 93.96 ;
     RECT  49.283 46.56 49.889 48.648 ;
     RECT  49.097 75.792 49.921 76.584 ;
     RECT  49.313 77.616 49.921 86.808 ;
     RECT  49.885 105.744 50.033 105.768 ;
     RECT  49.669 50.016 50.065 52.728 ;
     RECT  49.139 53.856 50.065 54.744 ;
     RECT  48.796 97.92 50.065 99.576 ;
     RECT  49.849 95.904 50.101 96.312 ;
     RECT  49.817 101.424 50.101 102.696 ;
     RECT  49.529 62.832 50.129 74.616 ;
     RECT  49.921 75.792 50.129 86.808 ;
     RECT  49.781 88.416 50.173 88.488 ;
     RECT  49.885 91.776 50.293 93.96 ;
     RECT  50.129 62.832 50.317 86.808 ;
     RECT  50.173 88.08 50.317 88.488 ;
     RECT  49.781 89.52 50.348 89.88 ;
     RECT  49.889 46.56 50.461 47.688 ;
     RECT  50.101 95.568 50.461 96.312 ;
     RECT  50.065 97.92 50.461 100.296 ;
     RECT  50.101 101.328 50.461 102.696 ;
     RECT  50.293 91.056 50.497 93.96 ;
     RECT  50.461 95.568 50.533 96.744 ;
     RECT  50.461 97.92 50.533 102.696 ;
     RECT  49.777 59.472 50.605 61.656 ;
     RECT  50.317 62.832 50.605 88.488 ;
     RECT  50.348 89.52 50.605 89.928 ;
     RECT  50.497 90.912 50.605 93.96 ;
     RECT  50.065 50.016 50.641 54.744 ;
     RECT  50.605 59.472 50.749 88.488 ;
     RECT  50.605 89.52 50.749 93.96 ;
     RECT  50.641 49.2 50.869 54.744 ;
     RECT  49.529 43.104 51.008 44.424 ;
     RECT  50.461 45.6 51.008 47.688 ;
     RECT  50.869 48.816 51.008 54.744 ;
     RECT  49.139 56.016 51.008 58.2 ;
     RECT  50.749 59.472 51.008 93.96 ;
     RECT  50.533 95.568 51.008 102.696 ;
     RECT  51.008 2.148 51.112 103.152 ;
     RECT  51.112 2.418 51.2 103.152 ;
     RECT  51.2 2.418 51.304 103.422 ;
     RECT  51.304 46.608 51.365 47.4 ;
     RECT  51.304 65.472 51.401 89.832 ;
     RECT  51.304 43.104 51.443 43.896 ;
     RECT  51.304 91.056 51.617 91.08 ;
     RECT  51.304 92.16 51.653 99 ;
     RECT  51.304 59.472 51.761 64.44 ;
     RECT  51.653 98.976 51.869 99 ;
     RECT  51.653 92.16 51.923 97.656 ;
     RECT  51.304 101.712 52.013 102.696 ;
     RECT  51.923 95.568 52.121 97.656 ;
     RECT  52.013 102.48 52.121 102.696 ;
     RECT  51.923 92.16 52.157 94.584 ;
     RECT  52.157 92.16 52.193 94.344 ;
     RECT  51.761 59.472 52.333 60.696 ;
     RECT  51.304 48.96 52.477 58.2 ;
     RECT  51.304 100.608 52.517 100.632 ;
     RECT  52.477 48.48 52.549 58.2 ;
     RECT  52.333 59.28 52.549 60.696 ;
     RECT  51.365 46.8 52.621 47.4 ;
     RECT  52.549 48.48 52.621 60.696 ;
     RECT  51.401 65.472 52.621 89.544 ;
     RECT  51.761 61.728 52.657 64.44 ;
     RECT  52.621 65.472 52.657 90.072 ;
     RECT  52.121 97.008 52.697 97.656 ;
     RECT  52.621 46.8 52.729 60.696 ;
     RECT  52.657 61.728 52.729 90.072 ;
     RECT  52.741 104.256 52.796 104.28 ;
     RECT  52.193 92.16 52.873 92.184 ;
     RECT  52.121 102.672 53.089 102.696 ;
     RECT  52.796 103.728 53.089 104.28 ;
     RECT  52.193 93.6 53.269 94.344 ;
     RECT  52.121 95.568 53.269 95.832 ;
     RECT  53.089 102.672 53.317 104.28 ;
     RECT  53.029 105.696 53.317 105.72 ;
     RECT  52.729 46.8 53.509 90.072 ;
     RECT  53.125 101.52 53.557 101.544 ;
     RECT  53.269 93.264 53.629 95.832 ;
     RECT  52.697 97.008 53.629 97.56 ;
     RECT  53.557 100.848 53.665 101.544 ;
     RECT  53.317 102.672 53.665 105.72 ;
     RECT  51.443 43.104 53.708 43.128 ;
     RECT  53.509 46.8 53.708 90.264 ;
     RECT  52.873 91.344 53.708 92.184 ;
     RECT  53.629 93.264 53.708 97.56 ;
     RECT  53.413 99.744 53.708 99.768 ;
     RECT  53.665 100.848 53.708 105.72 ;
     RECT  53.708 2.148 53.812 105.72 ;
     RECT  53.812 2.418 54.004 105.72 ;
     RECT  54.004 51.792 54.065 52.728 ;
     RECT  54.004 95.664 54.101 97.56 ;
     RECT  54.004 99.168 54.131 101.064 ;
     RECT  54.004 48.672 54.137 48.696 ;
     RECT  54.131 99.168 54.173 100.968 ;
     RECT  54.004 53.856 54.209 57.912 ;
     RECT  54.209 53.856 54.497 57.816 ;
     RECT  54.004 90.72 54.533 94.632 ;
     RECT  54.004 59.04 54.605 89.496 ;
     RECT  54.101 96.48 54.605 97.56 ;
     RECT  54.004 102.768 54.641 105.72 ;
     RECT  54.605 96.864 54.707 97.56 ;
     RECT  54.065 51.792 54.713 52.2 ;
     RECT  54.173 99.168 54.748 100.872 ;
     RECT  54.004 43.104 54.749 43.272 ;
     RECT  54.533 91.824 54.857 94.632 ;
     RECT  54.707 96.912 54.893 97.56 ;
     RECT  54.641 102.768 54.929 104.856 ;
     RECT  54.605 59.232 55.105 89.496 ;
     RECT  54.857 92.16 55.145 94.632 ;
     RECT  55.105 59.232 55.361 89.592 ;
     RECT  54.497 53.856 55.397 57.432 ;
     RECT  54.748 99.6 55.429 100.872 ;
     RECT  54.713 51.792 55.433 51.912 ;
     RECT  55.361 75.168 55.433 89.592 ;
     RECT  55.397 53.856 55.501 53.88 ;
     RECT  55.145 94.272 55.628 94.632 ;
     RECT  54.533 90.72 55.645 90.792 ;
     RECT  54.893 96.912 55.669 97.368 ;
     RECT  55.429 99.6 55.669 101.352 ;
     RECT  54.929 102.768 55.721 104.328 ;
     RECT  55.645 90.624 55.753 90.792 ;
     RECT  55.669 99.6 55.813 101.496 ;
     RECT  55.501 53.232 55.933 53.88 ;
     RECT  55.813 99.024 55.969 101.496 ;
     RECT  55.721 102.768 55.969 104.28 ;
     RECT  55.969 99.024 56.077 104.28 ;
     RECT  55.753 90.624 56.101 91.128 ;
     RECT  55.145 92.16 56.101 93.048 ;
     RECT  56.077 98.928 56.245 104.28 ;
     RECT  55.433 82.464 56.365 89.592 ;
     RECT  56.101 90.624 56.365 93.048 ;
     RECT  54.749 43.104 56.408 43.128 ;
     RECT  54.004 46.8 56.408 46.824 ;
     RECT  55.433 51.792 56.408 51.816 ;
     RECT  55.933 52.8 56.408 53.88 ;
     RECT  55.397 55.536 56.408 57.432 ;
     RECT  55.361 59.232 56.408 73.896 ;
     RECT  55.433 75.168 56.408 81.48 ;
     RECT  56.365 82.464 56.408 93.048 ;
     RECT  55.628 94.272 56.408 95.16 ;
     RECT  55.669 96.336 56.408 97.368 ;
     RECT  56.245 98.496 56.408 104.28 ;
     RECT  56.408 2.148 56.512 104.28 ;
     RECT  56.245 105.648 56.533 105.672 ;
     RECT  56.512 2.418 56.704 104.28 ;
     RECT  56.704 80.64 56.729 81.48 ;
     RECT  56.533 105.552 56.773 105.672 ;
     RECT  56.704 98.448 56.819 104.28 ;
     RECT  56.704 36.864 56.837 37.608 ;
     RECT  56.704 82.464 56.909 91.128 ;
     RECT  56.704 96.192 56.945 97.08 ;
     RECT  56.773 105.456 56.963 105.672 ;
     RECT  56.704 51.888 56.981 66.552 ;
     RECT  56.909 82.464 57.011 90.168 ;
     RECT  56.963 105.456 57.011 105.576 ;
     RECT  56.819 98.64 57.017 104.28 ;
     RECT  56.981 51.888 57.125 54.696 ;
     RECT  57.017 104.256 57.133 104.28 ;
     RECT  56.981 56.016 57.269 66.552 ;
     RECT  57.269 56.016 57.305 57.384 ;
     RECT  56.704 93.984 57.341 94.056 ;
     RECT  57.125 51.888 57.377 51.912 ;
     RECT  57.017 98.64 57.413 103.224 ;
     RECT  56.945 96.192 57.637 96.36 ;
     RECT  57.269 58.416 57.697 66.552 ;
     RECT  56.704 67.584 57.697 68.136 ;
     RECT  57.011 89.472 57.701 90.168 ;
     RECT  56.704 95.136 57.731 95.16 ;
     RECT  56.729 80.832 57.769 81.48 ;
     RECT  57.011 82.464 57.769 88.2 ;
     RECT  57.697 58.416 57.809 68.136 ;
     RECT  57.341 94.032 57.809 94.056 ;
     RECT  56.704 92.16 57.884 92.712 ;
     RECT  57.637 96.192 58.025 96.312 ;
     RECT  57.809 63.216 58.057 68.136 ;
     RECT  56.704 69.216 58.057 74.328 ;
     RECT  56.704 75.408 58.085 79.56 ;
     RECT  57.769 80.64 58.085 88.2 ;
     RECT  58.085 75.408 58.165 88.2 ;
     RECT  57.701 89.472 58.165 90.072 ;
     RECT  57.884 91.728 58.165 92.712 ;
     RECT  57.413 101.376 58.213 103.224 ;
     RECT  57.305 56.352 58.237 57.384 ;
     RECT  57.809 58.416 58.237 62.04 ;
     RECT  58.057 63.216 58.273 74.328 ;
     RECT  58.165 75.408 58.273 90.072 ;
     RECT  57.125 53.328 58.549 54.696 ;
     RECT  58.549 53.328 58.669 55.272 ;
     RECT  58.237 56.352 58.669 62.04 ;
     RECT  58.273 63.216 58.669 90.072 ;
     RECT  58.165 91.152 58.669 92.712 ;
     RECT  57.413 98.64 58.813 100.344 ;
     RECT  58.213 101.376 58.813 103.752 ;
     RECT  58.669 53.328 58.921 62.04 ;
     RECT  58.669 63.216 58.921 92.712 ;
     RECT  58.837 105.648 58.933 105.672 ;
     RECT  57.841 94.512 58.981 94.824 ;
     RECT  56.837 36.864 59.108 36.888 ;
     RECT  56.704 43.104 59.108 43.128 ;
     RECT  58.921 53.328 59.108 92.712 ;
     RECT  58.981 94.032 59.108 94.824 ;
     RECT  58.025 96.192 59.108 96.216 ;
     RECT  58.813 98.64 59.108 103.752 ;
     RECT  58.933 105.6 59.123 105.672 ;
     RECT  59.108 2.148 59.212 103.752 ;
     RECT  59.123 105.6 59.219 105.624 ;
     RECT  59.212 2.418 59.404 103.752 ;
     RECT  59.404 55.296 59.555 71.832 ;
     RECT  59.555 55.872 59.573 71.832 ;
     RECT  59.404 93.408 59.645 95.784 ;
     RECT  59.404 90.576 60.149 92.328 ;
     RECT  59.404 53.328 60.293 54.072 ;
     RECT  59.404 80.304 60.421 84.072 ;
     RECT  59.404 85.68 60.421 89.592 ;
     RECT  60.421 80.304 60.473 89.592 ;
     RECT  60.149 90.576 60.473 91.8 ;
     RECT  59.573 55.872 60.613 66.888 ;
     RECT  59.573 67.872 60.613 71.832 ;
     RECT  59.404 72.816 60.617 79.272 ;
     RECT  60.541 97.104 60.649 97.128 ;
     RECT  60.613 55.872 60.709 71.832 ;
     RECT  60.617 72.816 60.709 77.112 ;
     RECT  59.404 98.4 60.725 103.752 ;
     RECT  60.293 53.856 60.86 54.072 ;
     RECT  60.617 78.096 60.901 79.272 ;
     RECT  60.473 80.304 60.901 89.304 ;
     RECT  59.645 93.408 61.117 94.776 ;
     RECT  60.86 53.856 61.405 54.456 ;
     RECT  61.405 53.856 61.441 54.696 ;
     RECT  61.513 52.272 61.585 52.296 ;
     RECT  61.441 53.568 61.585 54.696 ;
     RECT  60.725 98.4 61.801 98.472 ;
     RECT  59.404 36.864 61.808 36.888 ;
     RECT  59.404 43.104 61.808 43.128 ;
     RECT  61.585 52.272 61.808 54.696 ;
     RECT  60.709 55.872 61.808 77.112 ;
     RECT  60.901 78.096 61.808 89.304 ;
     RECT  60.805 90.48 61.808 90.504 ;
     RECT  61.765 91.968 61.808 91.992 ;
     RECT  61.117 93.312 61.808 94.776 ;
     RECT  59.645 95.76 61.808 95.784 ;
     RECT  60.649 96.816 61.808 97.128 ;
     RECT  61.801 98.352 61.808 98.472 ;
     RECT  60.725 99.552 61.808 103.752 ;
     RECT  61.808 2.148 61.877 103.752 ;
     RECT  61.877 2.148 61.912 103.656 ;
     RECT  61.912 2.418 62.104 103.656 ;
     RECT  62.104 100.512 62.237 103.656 ;
     RECT  62.104 55.776 62.243 57.432 ;
     RECT  62.104 93.312 62.453 93.912 ;
     RECT  62.104 52.272 62.476 54.696 ;
     RECT  62.104 91.968 62.489 91.992 ;
     RECT  62.104 96.48 62.579 98.664 ;
     RECT  62.579 97.248 62.62 98.664 ;
     RECT  62.104 78.192 62.849 90.552 ;
     RECT  62.104 95.472 62.849 95.496 ;
     RECT  62.243 55.776 62.885 57.384 ;
     RECT  62.62 98.208 62.957 98.664 ;
     RECT  62.957 98.208 62.993 98.472 ;
     RECT  62.104 51.216 63.097 51.24 ;
     RECT  62.237 100.512 63.109 103.32 ;
     RECT  63.109 100.32 63.137 103.32 ;
     RECT  63.137 100.32 63.155 101.592 ;
     RECT  62.993 98.208 63.209 98.424 ;
     RECT  62.885 57.12 63.421 57.384 ;
     RECT  62.104 58.416 63.421 77.064 ;
     RECT  63.155 100.32 63.425 100.872 ;
     RECT  63.421 57.12 63.461 77.064 ;
     RECT  62.885 55.776 63.637 56.088 ;
     RECT  62.849 78.672 63.644 90.552 ;
     RECT  63.601 91.776 63.644 91.8 ;
     RECT  63.097 50.688 63.673 51.24 ;
     RECT  62.453 93.888 63.685 93.912 ;
     RECT  63.637 55.68 63.745 56.088 ;
     RECT  63.673 50.352 63.781 51.24 ;
     RECT  63.745 96.96 63.817 96.984 ;
     RECT  63.685 93.84 63.889 93.912 ;
     RECT  63.817 96.96 63.997 97.032 ;
     RECT  63.997 96.144 64.069 97.032 ;
     RECT  63.745 55.488 64.249 56.088 ;
     RECT  63.461 57.12 64.249 77.016 ;
     RECT  63.644 78.672 64.321 91.8 ;
     RECT  64.321 78.432 64.357 91.8 ;
     RECT  62.104 36.864 64.508 36.888 ;
     RECT  63.781 50.352 64.508 51.288 ;
     RECT  62.476 52.272 64.508 54.456 ;
     RECT  64.249 55.488 64.508 77.016 ;
     RECT  64.357 78.096 64.508 91.8 ;
     RECT  63.889 93.84 64.508 94.584 ;
     RECT  64.069 96.144 64.508 97.08 ;
     RECT  63.209 98.208 64.508 98.232 ;
     RECT  63.425 100.32 64.508 100.344 ;
     RECT  63.137 102.672 64.508 103.32 ;
     RECT  64.508 2.148 64.612 103.32 ;
     RECT  64.612 2.418 64.7 103.32 ;
     RECT  64.7 2.418 64.804 103.422 ;
     RECT  64.804 98.544 65.189 98.616 ;
     RECT  64.804 57.936 65.225 59.496 ;
     RECT  65.189 98.592 65.297 98.616 ;
     RECT  64.804 60.912 65.621 90.072 ;
     RECT  64.804 52.224 65.657 52.488 ;
     RECT  64.804 50.64 66.013 50.664 ;
     RECT  64.804 54.096 66.089 56.808 ;
     RECT  64.804 91.056 66.131 97.56 ;
     RECT  66.013 50.544 66.157 50.664 ;
     RECT  66.131 91.056 66.233 95.4 ;
     RECT  65.225 58.224 66.373 59.496 ;
     RECT  66.089 54.768 66.469 56.808 ;
     RECT  66.373 57.792 66.469 59.496 ;
     RECT  66.469 54.768 66.661 59.496 ;
     RECT  64.804 36.864 66.733 36.888 ;
     RECT  66.661 54.768 66.853 59.784 ;
     RECT  65.621 60.912 66.853 70.392 ;
     RECT  66.733 104.832 66.877 104.856 ;
     RECT  65.657 52.272 66.913 52.488 ;
     RECT  65.621 71.424 66.913 90.072 ;
     RECT  66.233 91.056 66.913 94.584 ;
     RECT  66.877 104.832 67.025 105.768 ;
     RECT  64.804 100.512 67.093 103.272 ;
     RECT  67.025 104.832 67.205 104.856 ;
     RECT  66.733 36.624 67.208 36.888 ;
     RECT  66.157 50.496 67.208 50.664 ;
     RECT  66.913 52.272 67.208 52.776 ;
     RECT  66.853 54.768 67.208 70.392 ;
     RECT  66.913 71.424 67.208 94.584 ;
     RECT  66.131 96.96 67.208 96.984 ;
     RECT  67.093 98.592 67.208 98.616 ;
     RECT  67.093 99.792 67.208 103.272 ;
     RECT  67.208 2.148 67.312 103.272 ;
     RECT  67.312 2.418 67.4 103.272 ;
     RECT  67.4 2.418 67.504 103.422 ;
     RECT  67.504 50.016 67.737 53.448 ;
     RECT  67.504 99.216 67.763 99.768 ;
     RECT  67.504 92.16 68.213 95.112 ;
     RECT  67.737 50.016 68.501 51 ;
     RECT  67.737 52.32 68.533 53.448 ;
     RECT  67.504 54.432 68.533 56.376 ;
     RECT  67.763 99.216 68.569 99.24 ;
     RECT  67.504 57.696 68.677 90.264 ;
     RECT  68.533 52.32 68.713 56.376 ;
     RECT  68.677 57.408 68.713 90.264 ;
     RECT  68.569 98.64 68.749 99.24 ;
     RECT  67.504 100.848 68.749 103.272 ;
     RECT  68.785 96.912 68.857 96.936 ;
     RECT  68.713 52.32 68.861 90.264 ;
     RECT  68.749 100.8 68.893 103.272 ;
     RECT  68.749 98.64 68.929 99.768 ;
     RECT  68.929 98.4 68.957 99.768 ;
     RECT  68.893 100.752 68.957 103.272 ;
     RECT  68.213 92.208 68.965 95.112 ;
     RECT  68.861 52.32 69.001 90.072 ;
     RECT  68.965 105.696 69.061 105.72 ;
     RECT  68.965 92.208 69.217 95.208 ;
     RECT  68.957 98.4 69.217 103.272 ;
     RECT  69.061 105.648 69.217 105.72 ;
     RECT  69.217 104.88 69.289 105.72 ;
     RECT  69.289 104.88 69.301 105.768 ;
     RECT  67.504 36.624 69.433 36.648 ;
     RECT  69.301 104.784 69.437 105.768 ;
     RECT  69.217 98.16 69.528 103.272 ;
     RECT  68.857 96.912 69.637 97.032 ;
     RECT  69.528 98.064 69.637 103.272 ;
     RECT  69.217 91.584 69.721 95.208 ;
     RECT  69.437 104.784 69.733 105.72 ;
     RECT  69.733 104.64 69.869 105.72 ;
     RECT  69.433 36.624 69.908 36.888 ;
     RECT  68.501 50.016 69.908 50.664 ;
     RECT  69.001 52.224 69.908 90.072 ;
     RECT  69.721 91.104 69.908 95.208 ;
     RECT  69.637 96.912 69.908 103.272 ;
     RECT  69.869 104.64 69.971 105.672 ;
     RECT  69.908 2.148 70.012 103.272 ;
     RECT  70.012 2.418 70.1 103.272 ;
     RECT  70.1 2.418 70.204 103.422 ;
     RECT  70.204 36.624 70.229 36.984 ;
     RECT  70.204 51.792 70.451 93.624 ;
     RECT  70.451 51.84 70.697 93.624 ;
     RECT  70.697 51.84 70.805 93.528 ;
     RECT  70.229 36.768 70.877 36.984 ;
     RECT  69.971 104.832 70.913 105.672 ;
     RECT  70.805 92.304 71.093 93.528 ;
     RECT  70.204 96.816 71.173 103.272 ;
     RECT  70.805 51.84 71.201 90.792 ;
     RECT  71.173 96.816 71.237 103.512 ;
     RECT  70.913 105.6 71.269 105.672 ;
     RECT  70.204 50.208 71.305 50.808 ;
     RECT  70.877 36.864 71.449 36.984 ;
     RECT  71.201 51.84 71.453 89.208 ;
     RECT  71.453 52.368 71.459 89.208 ;
     RECT  71.269 105.6 71.558 105.72 ;
     RECT  71.305 49.536 71.745 50.808 ;
     RECT  71.881 94.704 71.909 94.728 ;
     RECT  71.201 90.768 72.061 90.792 ;
     RECT  71.237 97.728 72.373 103.512 ;
     RECT  71.745 49.536 72.421 51.384 ;
     RECT  71.459 52.368 72.421 53.592 ;
     RECT  72.061 90.768 72.421 91.08 ;
     RECT  71.093 92.304 72.421 93.336 ;
     RECT  72.373 97.44 72.421 103.512 ;
     RECT  71.459 54.576 72.469 89.208 ;
     RECT  72.421 90.768 72.469 93.336 ;
     RECT  72.421 97.44 72.517 103.752 ;
     RECT  72.529 34.752 72.608 34.776 ;
     RECT  71.449 36.864 72.608 37.512 ;
     RECT  72.421 49.536 72.608 53.592 ;
     RECT  72.469 54.576 72.608 93.336 ;
     RECT  71.909 94.704 72.608 95.208 ;
     RECT  72.517 97.44 72.608 103.8 ;
     RECT  72.608 2.148 72.659 103.8 ;
     RECT  71.558 105.648 72.659 105.672 ;
     RECT  72.659 2.148 72.712 103.752 ;
     RECT  72.712 2.418 72.904 103.752 ;
     RECT  72.904 97.824 72.929 103.752 ;
     RECT  72.904 62.448 72.965 90.072 ;
     RECT  72.904 50.352 73.001 61.464 ;
     RECT  72.904 91.056 73.091 95.256 ;
     RECT  73.091 91.056 73.217 93.096 ;
     RECT  73.001 52.032 73.541 61.464 ;
     RECT  73.189 105.696 73.729 105.72 ;
     RECT  73.001 50.352 73.829 50.664 ;
     RECT  72.965 62.448 73.865 90.024 ;
     RECT  73.865 69.984 73.933 90.024 ;
     RECT  72.904 96.576 73.933 96.6 ;
     RECT  73.933 96.576 73.957 96.648 ;
     RECT  73.957 96.432 74.101 96.648 ;
     RECT  72.929 97.824 74.101 97.848 ;
     RECT  72.929 99.12 74.153 103.752 ;
     RECT  73.091 94.224 74.225 95.256 ;
     RECT  74.101 96.432 74.257 97.848 ;
     RECT  73.217 91.152 74.293 93.096 ;
     RECT  74.225 94.224 74.293 95.016 ;
     RECT  73.933 69.984 74.545 90.072 ;
     RECT  74.293 91.152 74.545 95.016 ;
     RECT  73.541 52.032 74.617 61.176 ;
     RECT  74.617 52.032 74.653 61.224 ;
     RECT  73.865 62.448 75.013 68.712 ;
     RECT  74.545 69.984 75.013 95.016 ;
     RECT  74.821 105.696 75.161 105.72 ;
     RECT  72.904 36.864 75.308 36.936 ;
     RECT  74.869 49.536 75.308 49.56 ;
     RECT  73.829 50.64 75.308 50.664 ;
     RECT  74.653 52.032 75.308 61.464 ;
     RECT  75.013 62.448 75.308 95.016 ;
     RECT  74.257 96.432 75.308 97.896 ;
     RECT  74.153 99.6 75.308 103.752 ;
     RECT  75.308 2.148 75.412 103.752 ;
     RECT  75.412 2.418 75.604 103.752 ;
     RECT  75.604 49.536 75.731 91.704 ;
     RECT  75.731 62.496 75.953 91.704 ;
     RECT  75.953 62.688 76.061 91.704 ;
     RECT  75.604 96.576 76.156 98.664 ;
     RECT  76.156 97.824 76.169 98.664 ;
     RECT  75.731 49.536 76.205 61.464 ;
     RECT  75.604 35.856 76.565 35.88 ;
     RECT  75.604 33.024 76.601 33.048 ;
     RECT  75.604 100.512 76.601 103.752 ;
     RECT  76.061 62.832 76.673 91.704 ;
     RECT  75.604 92.784 76.673 95.4 ;
     RECT  76.169 97.824 76.709 98.088 ;
     RECT  76.673 62.832 76.745 91.608 ;
     RECT  76.601 100.512 76.745 103.32 ;
     RECT  76.205 50.352 76.849 61.464 ;
     RECT  76.673 92.784 76.925 93.768 ;
     RECT  76.925 92.88 76.972 93.768 ;
     RECT  76.745 62.832 76.997 91.56 ;
     RECT  76.972 92.88 76.997 93.336 ;
     RECT  76.849 50.352 77.245 61.512 ;
     RECT  76.997 62.832 77.245 91.224 ;
     RECT  77.245 50.352 77.569 91.224 ;
     RECT  77.569 50.112 77.708 91.224 ;
     RECT  75.604 36.864 78.008 36.936 ;
     RECT  77.708 49.92 78.008 91.224 ;
     RECT  76.997 93.024 78.008 93.336 ;
     RECT  76.673 94.848 78.008 95.4 ;
     RECT  76.156 96.576 78.008 96.6 ;
     RECT  76.709 97.824 78.008 97.896 ;
     RECT  76.745 100.512 78.008 101.928 ;
     RECT  76.745 103.296 78.008 103.32 ;
     RECT  78.008 2.148 78.112 103.32 ;
     RECT  78.112 2.418 78.2 103.32 ;
     RECT  78.2 2.418 78.304 103.422 ;
     RECT  77.605 105.744 78.617 105.768 ;
     RECT  78.304 36.768 78.725 36.936 ;
     RECT  78.304 49.536 78.899 97.896 ;
     RECT  78.899 93.024 79.085 97.896 ;
     RECT  78.304 98.88 79.139 103.32 ;
     RECT  79.085 93.264 79.333 97.896 ;
     RECT  79.139 98.88 79.333 101.928 ;
     RECT  78.899 49.536 79.553 91.752 ;
     RECT  79.333 93.264 80.252 101.928 ;
     RECT  80.252 92.4 80.305 101.928 ;
     RECT  79.139 103.2 80.305 103.32 ;
     RECT  80.449 105.648 80.633 105.672 ;
     RECT  78.725 36.864 80.708 36.936 ;
     RECT  79.837 42.72 80.708 42.744 ;
     RECT  79.553 49.536 80.708 91.224 ;
     RECT  80.305 92.4 80.708 103.32 ;
     RECT  80.708 2.148 80.812 103.32 ;
     RECT  80.812 2.418 80.9 103.32 ;
     RECT  80.9 2.418 81.004 103.422 ;
     RECT  81.004 93.264 81.065 95.688 ;
     RECT  81.004 50.4 81.137 88.728 ;
     RECT  81.004 89.712 81.173 90.936 ;
     RECT  81.173 89.712 81.425 90.888 ;
     RECT  81.137 51.168 81.497 88.728 ;
     RECT  81.004 97.008 81.857 103.32 ;
     RECT  81.857 97.872 81.875 103.32 ;
     RECT  81.497 51.168 82.067 88.68 ;
     RECT  82.067 53.232 82.109 88.68 ;
     RECT  82.109 54.144 82.181 88.68 ;
     RECT  82.067 51.168 82.217 52.2 ;
     RECT  82.181 54.144 82.217 87.528 ;
     RECT  81.065 93.264 82.249 95.256 ;
     RECT  82.141 96.48 82.249 96.504 ;
     RECT  82.217 54.432 82.289 87.528 ;
     RECT  81.875 98.064 82.433 103.32 ;
     RECT  82.181 88.656 82.501 88.68 ;
     RECT  81.425 89.712 82.501 90.552 ;
     RECT  81.004 36.864 82.645 36.936 ;
     RECT  82.217 51.168 82.681 52.056 ;
     RECT  82.645 91.728 82.681 91.752 ;
     RECT  82.501 88.656 82.933 90.552 ;
     RECT  82.933 88.656 83.041 90.6 ;
     RECT  83.041 88.656 83.077 90.696 ;
     RECT  82.681 91.728 83.077 92.184 ;
     RECT  82.249 93.264 83.173 96.504 ;
     RECT  83.077 88.656 83.257 92.184 ;
     RECT  83.257 88.416 83.269 92.184 ;
     RECT  83.173 93.264 83.269 97.128 ;
     RECT  83.269 88.416 83.401 97.128 ;
     RECT  82.645 36.864 83.408 37.752 ;
     RECT  82.249 42.72 83.408 42.744 ;
     RECT  83.293 48.672 83.408 48.696 ;
     RECT  82.681 50.592 83.408 52.056 ;
     RECT  82.289 54.432 83.408 87.384 ;
     RECT  83.401 88.368 83.408 97.128 ;
     RECT  82.433 98.352 83.408 103.32 ;
     RECT  83.408 2.148 83.512 103.32 ;
     RECT  82.357 105.744 83.585 105.768 ;
     RECT  83.512 2.418 83.6 103.32 ;
     RECT  83.6 2.418 83.704 103.422 ;
     RECT  83.704 94.416 83.873 95.496 ;
     RECT  83.873 94.416 83.981 95.256 ;
     RECT  84.013 104.832 84.377 104.856 ;
     RECT  83.704 99.168 84.485 103.32 ;
     RECT  83.704 36.864 84.733 36.936 ;
     RECT  84.485 99.984 84.803 103.32 ;
     RECT  83.704 55.2 84.985 88.92 ;
     RECT  83.981 94.56 85.103 95.256 ;
     RECT  83.704 96.816 85.103 97.128 ;
     RECT  84.985 55.2 85.129 88.968 ;
     RECT  83.704 90.096 85.129 93.288 ;
     RECT  84.733 36.864 85.417 37.704 ;
     RECT  85.103 94.56 85.705 97.128 ;
     RECT  85.453 33.552 85.921 33.576 ;
     RECT  85.909 35.424 85.957 35.448 ;
     RECT  85.921 33.12 86.029 33.576 ;
     RECT  85.129 55.2 86.065 93.288 ;
     RECT  85.705 94.56 86.065 97.368 ;
     RECT  86.029 33.12 86.108 33.672 ;
     RECT  85.957 35.232 86.108 35.448 ;
     RECT  85.417 36.864 86.108 37.992 ;
     RECT  86.101 38.976 86.108 39 ;
     RECT  83.704 48.672 86.108 49.032 ;
     RECT  83.704 51.408 86.108 51.432 ;
     RECT  86.065 55.2 86.108 97.368 ;
     RECT  84.803 99.984 86.108 103.032 ;
     RECT  86.108 2.148 86.212 103.152 ;
     RECT  86.212 2.418 86.3 103.152 ;
     RECT  86.3 2.418 86.404 103.422 ;
     RECT  86.404 48.672 86.501 49.032 ;
     RECT  86.404 38.784 86.531 39 ;
     RECT  86.404 30.24 86.627 30.264 ;
     RECT  86.404 102.432 86.645 103.032 ;
     RECT  86.404 100.08 86.681 101.208 ;
     RECT  86.681 100.32 86.717 101.208 ;
     RECT  86.404 34.896 86.789 37.704 ;
     RECT  86.645 103.008 86.789 103.032 ;
     RECT  86.717 100.992 86.861 101.208 ;
     RECT  86.404 55.2 86.933 97.944 ;
     RECT  86.861 100.992 86.933 101.16 ;
     RECT  86.933 100.992 87.113 101.016 ;
     RECT  86.404 33.12 87.505 33.672 ;
     RECT  86.789 34.896 87.505 37.608 ;
     RECT  86.404 24.144 87.541 25.464 ;
     RECT  87.505 33.12 87.577 37.608 ;
     RECT  87.541 30.384 87.637 30.408 ;
     RECT  87.637 30.384 87.649 30.6 ;
     RECT  87.577 32.832 87.689 37.608 ;
     RECT  86.404 27.312 87.733 27.336 ;
     RECT  87.649 30.24 87.779 30.6 ;
     RECT  86.531 38.784 87.779 38.808 ;
     RECT  86.404 51.408 87.829 51.432 ;
     RECT  87.779 30.384 87.865 30.6 ;
     RECT  87.829 51.216 87.865 51.432 ;
     RECT  86.501 48.672 87.877 48.936 ;
     RECT  87.689 32.832 88.045 36.312 ;
     RECT  87.733 27.312 88.069 27.912 ;
     RECT  87.541 23.904 88.153 25.464 ;
     RECT  87.689 37.392 88.261 37.608 ;
     RECT  86.933 55.2 88.309 97.608 ;
     RECT  88.153 23.568 88.405 25.464 ;
     RECT  87.865 51.216 88.405 51.912 ;
     RECT  88.069 27.312 88.585 28.248 ;
     RECT  88.585 27.312 88.693 28.536 ;
     RECT  87.877 48.672 88.693 48.984 ;
     RECT  88.441 98.88 88.729 98.904 ;
     RECT  88.405 23.568 88.808 25.512 ;
     RECT  88.693 27.072 88.808 28.536 ;
     RECT  87.865 30.384 88.808 31.368 ;
     RECT  88.045 32.496 88.808 36.312 ;
     RECT  88.261 37.392 88.808 38.232 ;
     RECT  88.513 46.032 88.808 46.056 ;
     RECT  88.693 48.384 88.808 48.984 ;
     RECT  88.405 50.736 88.808 51.912 ;
     RECT  86.404 53.904 88.808 53.928 ;
     RECT  88.309 55.2 88.808 97.896 ;
     RECT  88.729 98.88 88.808 98.952 ;
     RECT  87.937 100.32 88.808 100.344 ;
     RECT  88.808 2.148 88.912 103.152 ;
     RECT  88.912 2.418 89 103.152 ;
     RECT  89 2.418 89.104 103.422 ;
     RECT  89.104 55.488 89.201 97.032 ;
     RECT  89.104 51.216 89.345 51.432 ;
     RECT  89.201 55.488 89.345 94.584 ;
     RECT  89.345 66.144 89.489 94.584 ;
     RECT  89.489 66.144 89.525 94.152 ;
     RECT  89.525 88.464 89.741 94.152 ;
     RECT  89.104 31.92 89.957 36.312 ;
     RECT  89.104 40.464 90.001 40.488 ;
     RECT  89.104 52.464 90.029 52.488 ;
     RECT  89.957 32.496 90.035 36.312 ;
     RECT  89.104 46.032 90.097 46.296 ;
     RECT  89.104 27.072 90.101 30.744 ;
     RECT  89.104 99.744 90.173 102.264 ;
     RECT  89.201 95.616 90.205 97.032 ;
     RECT  90.205 95.424 90.241 97.032 ;
     RECT  89.104 98.064 90.241 98.088 ;
     RECT  89.345 51.408 90.245 51.432 ;
     RECT  89.104 37.392 90.277 37.896 ;
     RECT  90.241 41.04 90.325 41.064 ;
     RECT  90.173 99.744 90.349 101.496 ;
     RECT  90.241 95.424 90.385 98.088 ;
     RECT  90.349 99.168 90.385 101.496 ;
     RECT  89.345 55.488 90.517 64.968 ;
     RECT  90.517 55.488 90.565 65.016 ;
     RECT  89.525 66.144 90.565 87.288 ;
     RECT  90.565 55.488 90.601 87.288 ;
     RECT  89.104 48.384 90.637 48.984 ;
     RECT  89.741 88.896 90.637 94.152 ;
     RECT  90.601 55.392 91.381 87.288 ;
     RECT  90.853 102.768 91.465 102.792 ;
     RECT  89.104 23.424 91.508 25.8 ;
     RECT  90.101 27.072 91.508 30.6 ;
     RECT  90.035 32.832 91.508 36.312 ;
     RECT  90.277 37.392 91.508 38.136 ;
     RECT  90.097 46.032 91.508 46.92 ;
     RECT  90.637 48.384 91.508 49.032 ;
     RECT  89.104 53.904 91.508 53.928 ;
     RECT  91.381 55.392 91.508 87.336 ;
     RECT  90.637 88.896 91.508 94.44 ;
     RECT  90.385 95.424 91.508 101.496 ;
     RECT  91.465 102.48 91.508 102.792 ;
     RECT  91.508 2.148 91.612 103.152 ;
     RECT  91.612 2.418 91.7 103.152 ;
     RECT  91.7 2.418 91.804 103.422 ;
     RECT  91.804 80.784 92.225 88.776 ;
     RECT  92.225 80.784 92.297 82.488 ;
     RECT  91.804 39.36 92.377 39.384 ;
     RECT  91.804 92.64 92.483 102.792 ;
     RECT  91.804 91.344 92.657 91.368 ;
     RECT  92.483 92.64 92.657 102.648 ;
     RECT  92.657 92.64 92.693 102.408 ;
     RECT  92.225 83.76 92.729 88.776 ;
     RECT  91.804 52.464 92.765 52.584 ;
     RECT  91.804 26.88 92.941 31.464 ;
     RECT  91.804 55.488 92.945 65.784 ;
     RECT  92.941 26.832 93.017 31.464 ;
     RECT  92.729 83.808 93.017 88.776 ;
     RECT  92.693 92.64 93.053 95.544 ;
     RECT  91.804 66.768 93.085 79.8 ;
     RECT  92.297 80.784 93.085 82.44 ;
     RECT  91.804 89.808 93.157 90.36 ;
     RECT  92.693 96.72 93.161 102.408 ;
     RECT  93.157 89.76 93.233 90.36 ;
     RECT  93.017 88.368 93.445 88.776 ;
     RECT  93.233 89.76 93.445 90.312 ;
     RECT  93.409 51.12 93.733 51.144 ;
     RECT  93.053 92.64 93.733 93.576 ;
     RECT  93.161 102.144 93.733 102.408 ;
     RECT  93.085 66.768 94.129 82.44 ;
     RECT  91.804 23.568 94.208 25.8 ;
     RECT  93.017 26.832 94.208 30.6 ;
     RECT  91.804 32.832 94.208 36.312 ;
     RECT  91.804 37.296 94.208 37.992 ;
     RECT  91.804 46.032 94.208 46.92 ;
     RECT  91.804 48.384 94.208 49.032 ;
     RECT  93.733 50.928 94.208 51.144 ;
     RECT  92.765 52.464 94.208 52.488 ;
     RECT  91.804 53.904 94.208 53.928 ;
     RECT  92.945 55.488 94.208 61.464 ;
     RECT  92.945 62.544 94.208 65.784 ;
     RECT  94.129 66.768 94.208 82.776 ;
     RECT  93.017 83.808 94.208 87.288 ;
     RECT  93.445 88.368 94.208 90.312 ;
     RECT  93.733 91.872 94.208 93.576 ;
     RECT  93.053 94.608 94.208 95.544 ;
     RECT  93.161 96.72 94.208 100.776 ;
     RECT  93.733 102.144 94.208 102.696 ;
     RECT  94.208 2.148 94.312 103.152 ;
     RECT  94.312 2.418 94.4 103.152 ;
     RECT  94.4 2.418 94.504 103.422 ;
     RECT  94.504 45.936 94.565 47.352 ;
     RECT  94.504 88.896 94.673 93.576 ;
     RECT  94.504 50.784 94.853 51.144 ;
     RECT  94.853 51.12 94.925 51.144 ;
     RECT  94.504 102.432 94.997 103.08 ;
     RECT  94.673 88.944 95.027 93.576 ;
     RECT  95.027 88.944 95.177 89.016 ;
     RECT  95.027 90.624 95.177 93.576 ;
     RECT  94.504 96.864 95.285 98.904 ;
     RECT  95.285 96.864 95.537 98.712 ;
     RECT  94.504 52.752 95.557 53.928 ;
     RECT  94.504 55.296 95.557 61.464 ;
     RECT  95.557 52.752 95.605 61.464 ;
     RECT  94.504 94.608 95.609 95.64 ;
     RECT  94.504 100.224 95.612 101.16 ;
     RECT  94.997 102.432 95.612 102.6 ;
     RECT  95.605 52.56 95.645 61.464 ;
     RECT  95.612 100.224 95.645 102.6 ;
     RECT  94.504 32.208 95.699 38.136 ;
     RECT  95.645 100.224 95.699 102.408 ;
     RECT  95.645 52.56 95.701 56.52 ;
     RECT  94.504 26.784 95.713 30.6 ;
     RECT  95.699 32.208 95.747 34.92 ;
     RECT  95.701 52.224 95.747 56.52 ;
     RECT  95.747 56.016 95.753 56.52 ;
     RECT  95.645 57.6 95.753 61.464 ;
     RECT  94.504 63.024 95.785 87.864 ;
     RECT  95.177 91.152 95.808 93.576 ;
     RECT  95.753 56.496 95.861 56.52 ;
     RECT  95.753 57.84 95.861 61.464 ;
     RECT  94.565 45.936 95.893 46.92 ;
     RECT  94.504 23.424 95.989 25.8 ;
     RECT  95.713 26.784 95.989 30.648 ;
     RECT  95.893 45.936 95.989 47.064 ;
     RECT  95.989 23.424 96.085 30.648 ;
     RECT  95.537 96.864 96.109 97.944 ;
     RECT  96.085 23.376 96.181 30.648 ;
     RECT  95.989 45.264 96.253 47.064 ;
     RECT  94.504 48.384 96.253 48.984 ;
     RECT  95.785 63.024 96.361 88.92 ;
     RECT  95.699 100.224 96.721 100.872 ;
     RECT  95.609 94.608 96.793 94.632 ;
     RECT  96.109 95.76 96.793 97.944 ;
     RECT  95.808 91.152 96.829 92.136 ;
     RECT  95.808 93.456 96.829 93.576 ;
     RECT  96.829 91.152 96.865 93.576 ;
     RECT  96.793 94.608 96.865 97.944 ;
     RECT  96.181 23.088 96.908 30.648 ;
     RECT  95.747 32.208 96.908 34.728 ;
     RECT  95.699 35.904 96.908 38.136 ;
     RECT  96.229 41.952 96.908 41.976 ;
     RECT  96.757 43.008 96.908 43.032 ;
     RECT  96.253 45.264 96.908 48.984 ;
     RECT  95.747 52.224 96.908 54.408 ;
     RECT  95.861 58.224 96.908 61.464 ;
     RECT  96.361 63.024 96.908 89.448 ;
     RECT  96.865 91.152 96.908 97.944 ;
     RECT  96.721 99.264 96.908 100.872 ;
     RECT  95.699 102.24 96.908 102.408 ;
     RECT  96.908 2.148 97.012 103.152 ;
     RECT  97.012 2.418 97.1 103.152 ;
     RECT  97.1 2.418 97.204 103.422 ;
     RECT  97.204 44.88 97.331 48.696 ;
     RECT  97.204 37.344 97.427 37.752 ;
     RECT  97.427 37.344 97.475 37.656 ;
     RECT  97.204 82.704 97.481 87.576 ;
     RECT  97.204 69.744 97.517 81.624 ;
     RECT  97.204 91.776 97.553 96.504 ;
     RECT  97.481 85.968 97.661 87.576 ;
     RECT  97.661 86.736 97.697 87.576 ;
     RECT  97.204 89.424 97.733 89.448 ;
     RECT  97.517 69.744 97.805 81.384 ;
     RECT  97.204 99.216 97.877 100.344 ;
     RECT  97.805 69.744 97.913 81.24 ;
     RECT  97.913 69.744 98.129 70.92 ;
     RECT  97.553 91.776 98.147 92.424 ;
     RECT  97.697 86.736 98.165 86.76 ;
     RECT  97.204 97.632 98.189 97.848 ;
     RECT  97.877 99.216 98.189 100.296 ;
     RECT  97.204 36.24 98.197 36.264 ;
     RECT  97.475 37.344 98.197 37.608 ;
     RECT  97.553 93.408 98.309 96.504 ;
     RECT  98.309 95.568 98.339 96.504 ;
     RECT  98.189 97.632 98.345 100.296 ;
     RECT  97.204 58.224 98.377 68.664 ;
     RECT  98.129 69.744 98.377 70.584 ;
     RECT  97.913 72.24 98.381 81.24 ;
     RECT  98.309 93.408 98.417 94.44 ;
     RECT  97.204 52.32 98.449 54.408 ;
     RECT  97.481 82.704 98.489 84.888 ;
     RECT  97.204 101.424 98.521 101.448 ;
     RECT  97.331 45.264 98.525 48.696 ;
     RECT  98.449 51.744 98.557 54.408 ;
     RECT  97.204 22.992 98.593 30.792 ;
     RECT  97.204 42.048 98.593 43.032 ;
     RECT  98.197 36.24 98.627 37.608 ;
     RECT  98.417 93.408 98.633 93.432 ;
     RECT  98.593 41.952 98.737 43.032 ;
     RECT  98.593 22.848 98.773 30.792 ;
     RECT  97.204 32.064 98.773 35.208 ;
     RECT  98.525 45.264 98.773 48.072 ;
     RECT  98.773 44.88 98.953 48.072 ;
     RECT  98.381 72.24 99.097 79.848 ;
     RECT  98.737 41.952 99.157 43.128 ;
     RECT  98.953 44.448 99.157 48.072 ;
     RECT  98.377 58.224 99.397 70.584 ;
     RECT  99.097 71.952 99.397 79.848 ;
     RECT  99.397 58.224 99.421 79.848 ;
     RECT  98.147 92.4 99.493 92.424 ;
     RECT  98.917 21.456 99.608 21.48 ;
     RECT  98.773 22.848 99.608 35.208 ;
     RECT  98.627 36.24 99.608 36.264 ;
     RECT  98.627 37.584 99.608 37.608 ;
     RECT  99.157 41.952 99.608 48.072 ;
     RECT  98.557 51.504 99.608 54.408 ;
     RECT  99.493 56.256 99.608 56.28 ;
     RECT  99.421 57.6 99.608 79.848 ;
     RECT  98.381 81.216 99.608 81.24 ;
     RECT  98.489 82.704 99.608 84.6 ;
     RECT  99.493 92.4 99.608 92.712 ;
     RECT  98.417 94.416 99.608 94.44 ;
     RECT  98.339 96.48 99.608 96.504 ;
     RECT  98.345 97.632 99.608 98.616 ;
     RECT  98.345 99.696 99.608 100.296 ;
     RECT  98.521 101.424 99.608 102.024 ;
     RECT  99.608 2.148 99.712 103.152 ;
     RECT  99.712 2.418 99.8 103.152 ;
     RECT  99.8 2.418 99.904 103.422 ;
     RECT  99.904 22.848 99.965 37.608 ;
     RECT  99.904 40.992 99.965 80.856 ;
     RECT  99.904 92.784 99.965 92.808 ;
     RECT  99.965 80.832 100.289 80.856 ;
     RECT  99.904 96.336 100.289 96.504 ;
     RECT  99.904 100.896 100.613 100.92 ;
     RECT  100.289 96.336 100.721 96.36 ;
     RECT  99.904 21.36 100.969 21.864 ;
     RECT  99.965 22.848 100.969 37.32 ;
     RECT  100.969 21.36 101.149 37.32 ;
     RECT  99.965 40.992 101.257 79.32 ;
     RECT  101.149 21.072 101.413 37.512 ;
     RECT  99.904 39.312 101.413 39.72 ;
     RECT  101.257 40.944 101.413 79.32 ;
     RECT  101.413 20.688 101.473 37.512 ;
     RECT  99.904 86.352 101.545 86.376 ;
     RECT  101.413 39.312 101.653 79.32 ;
     RECT  101.545 86.352 101.689 86.568 ;
     RECT  101.653 39.216 101.693 79.32 ;
     RECT  101.473 20.208 101.725 37.512 ;
     RECT  101.693 78.096 101.891 78.216 ;
     RECT  101.693 39.216 101.939 77.016 ;
     RECT  101.689 85.68 101.977 86.568 ;
     RECT  101.891 78.096 101.987 78.12 ;
     RECT  99.904 83.664 102.013 84.36 ;
     RECT  101.977 85.392 102.013 86.568 ;
     RECT  101.939 39.216 102.035 76.968 ;
     RECT  102.013 83.664 102.589 86.568 ;
     RECT  101.693 79.296 102.881 79.32 ;
     RECT  101.725 20.016 103.957 37.512 ;
     RECT  102.035 39.216 103.957 76.68 ;
     RECT  103.957 19.92 104.028 37.512 ;
     RECT  103.957 39.12 104.028 76.68 ;
     RECT  102.589 83.664 104.028 86.664 ;
     RECT  104.028 45.408 104.069 45.432 ;
     RECT  104.028 52.32 104.069 52.344 ;
     RECT  104.028 57.552 104.069 57.576 ;
    LAYER M5 ;
     RECT  2.4 2.137 2.52 2.151 ;
     RECT  5.1 2.137 5.22 2.151 ;
     RECT  7.8 2.137 7.92 2.151 ;
     RECT  10.5 2.137 10.62 2.151 ;
     RECT  13.2 2.137 13.32 2.151 ;
     RECT  15.9 2.137 16.02 2.151 ;
     RECT  18.6 2.137 18.72 2.151 ;
     RECT  21.3 2.137 21.42 2.151 ;
     RECT  24 2.137 24.12 2.151 ;
     RECT  26.7 2.137 26.82 2.151 ;
     RECT  29.4 2.137 29.52 2.151 ;
     RECT  32.1 2.137 32.22 2.151 ;
     RECT  34.8 2.137 34.92 2.151 ;
     RECT  37.5 2.137 37.62 2.151 ;
     RECT  40.2 2.137 40.32 2.151 ;
     RECT  42.9 2.137 43.02 2.151 ;
     RECT  45.6 2.137 45.72 2.151 ;
     RECT  48.3 2.137 48.42 2.151 ;
     RECT  51 2.137 51.12 2.151 ;
     RECT  53.7 2.137 53.82 2.151 ;
     RECT  56.4 2.137 56.52 2.151 ;
     RECT  59.1 2.137 59.22 2.151 ;
     RECT  61.8 2.137 61.92 2.151 ;
     RECT  64.5 2.137 64.62 2.151 ;
     RECT  67.2 2.137 67.32 2.151 ;
     RECT  69.9 2.137 70.02 2.151 ;
     RECT  72.6 2.137 72.72 2.151 ;
     RECT  75.3 2.137 75.42 2.151 ;
     RECT  78 2.137 78.12 2.151 ;
     RECT  80.7 2.137 80.82 2.151 ;
     RECT  83.4 2.137 83.52 2.151 ;
     RECT  86.1 2.137 86.22 2.151 ;
     RECT  88.8 2.137 88.92 2.151 ;
     RECT  91.5 2.137 91.62 2.151 ;
     RECT  94.2 2.137 94.32 2.151 ;
     RECT  96.9 2.137 97.02 2.151 ;
     RECT  99.6 2.137 99.72 2.151 ;
     RECT  102 20.485 102.024 20.581 ;
     RECT  101.952 20.581 102.024 20.677 ;
     RECT  101.424 20.677 102.024 21.733 ;
     RECT  101.376 21.733 102.024 22.117 ;
     RECT  101.184 22.117 102.024 22.405 ;
     RECT  101.04 22.405 102.216 22.547 ;
     RECT  101.04 22.547 101.928 22.835 ;
     RECT  101.04 22.835 101.88 22.931 ;
     RECT  96.9 2.151 97.212 23.077 ;
     RECT  96.192 23.077 97.416 23.365 ;
     RECT  99.6 2.151 99.912 23.701 ;
     RECT  101.04 22.931 101.736 23.701 ;
     RECT  96.096 23.365 97.416 23.941 ;
     RECT  99.6 23.701 101.736 24.037 ;
     RECT  99.6 24.037 101.928 24.227 ;
     RECT  99.6 24.227 101.64 25.139 ;
     RECT  101.136 25.139 101.496 25.859 ;
     RECT  101.184 25.859 101.496 25.955 ;
     RECT  101.328 25.955 101.496 26.339 ;
     RECT  101.376 26.339 101.496 26.677 ;
     RECT  95.712 23.941 97.416 26.819 ;
     RECT  88.8 2.151 89.112 27.061 ;
     RECT  88.704 27.061 89.112 27.109 ;
     RECT  86.1 2.151 86.412 27.301 ;
     RECT  88.704 27.109 89.448 27.397 ;
     RECT  88.704 27.397 89.976 27.445 ;
     RECT  88.32 27.445 89.976 27.637 ;
     RECT  101.376 26.677 101.64 27.637 ;
     RECT  95.904 26.819 97.416 27.685 ;
     RECT  101.184 27.637 101.64 27.685 ;
     RECT  87.888 27.637 89.976 27.877 ;
     RECT  100.944 27.685 101.64 27.923 ;
     RECT  87.744 27.877 89.976 28.165 ;
     RECT  95.904 27.685 97.464 28.211 ;
     RECT  87.744 28.165 90.024 28.405 ;
     RECT  99.6 25.139 99.912 28.405 ;
     RECT  100.944 27.923 101.448 28.405 ;
     RECT  95.904 28.211 97.368 28.739 ;
     RECT  99.6 28.405 101.448 29.555 ;
     RECT  87.744 28.405 90.072 29.699 ;
     RECT  86.1 27.301 86.616 30.275 ;
     RECT  95.904 28.739 97.212 30.275 ;
     RECT  96 30.275 97.212 30.371 ;
     RECT  87.744 29.699 90.024 30.373 ;
     RECT  99.6 29.555 101.4 31.093 ;
     RECT  99.168 31.093 101.4 31.429 ;
     RECT  99.168 31.429 101.448 31.717 ;
     RECT  99.168 31.717 102.024 31.955 ;
     RECT  94.2 2.151 94.512 32.197 ;
     RECT  94.2 32.197 95.16 32.437 ;
     RECT  87.552 30.373 90.024 32.531 ;
     RECT  99.6 31.955 102.024 32.579 ;
     RECT  94.2 32.437 95.64 32.581 ;
     RECT  88.8 32.531 89.976 32.915 ;
     RECT  99.6 32.579 101.928 33.347 ;
     RECT  94.2 32.581 95.736 33.877 ;
     RECT  96.9 30.371 97.212 33.877 ;
     RECT  24 2.151 24.312 34.117 ;
     RECT  99.6 33.347 100.872 34.259 ;
     RECT  101.904 33.347 101.928 34.693 ;
     RECT  101.904 34.693 102.024 34.739 ;
     RECT  26.7 2.151 27.012 34.741 ;
     RECT  24 34.117 24.504 34.787 ;
     RECT  87.552 32.531 87.672 34.835 ;
     RECT  102 34.739 102.024 34.835 ;
     RECT  86.1 30.275 86.412 34.885 ;
     RECT  94.2 33.877 97.212 35.029 ;
     RECT  86.1 34.885 87.192 35.221 ;
     RECT  94.2 35.029 97.464 35.411 ;
     RECT  85.968 35.221 87.192 35.413 ;
     RECT  26.7 34.741 27.912 35.699 ;
     RECT  95.568 35.411 97.464 35.939 ;
     RECT  29.4 2.151 29.712 35.989 ;
     RECT  88.8 32.915 89.112 36.277 ;
     RECT  85.92 35.413 87.192 36.515 ;
     RECT  29.4 35.989 29.832 37.043 ;
     RECT  31.056 36.373 31.08 37.091 ;
     RECT  85.92 36.515 86.616 37.091 ;
     RECT  95.568 35.939 95.736 37.091 ;
     RECT  98.592 35.125 98.616 37.091 ;
     RECT  91.5 2.151 91.812 37.333 ;
     RECT  88.32 36.277 89.112 37.381 ;
     RECT  24 34.787 24.312 37.429 ;
     RECT  26.7 35.699 27.144 37.429 ;
     RECT  96.9 35.939 97.464 37.667 ;
     RECT  85.92 37.091 86.52 37.763 ;
     RECT  96.9 37.667 97.416 37.763 ;
     RECT  87.744 37.381 89.112 37.861 ;
     RECT  87.744 37.861 89.976 38.101 ;
     RECT  24 37.429 25.128 38.149 ;
     RECT  87.744 38.101 90.312 38.243 ;
     RECT  29.4 37.043 29.712 38.677 ;
     RECT  23.808 38.149 25.128 38.725 ;
     RECT  26.7 37.429 27.72 38.725 ;
     RECT  32.1 2.151 32.412 38.725 ;
     RECT  33.792 37.621 33.816 38.773 ;
     RECT  34.8 2.151 35.112 38.773 ;
     RECT  23.808 38.725 27.72 38.819 ;
     RECT  87.744 38.243 87.768 38.819 ;
     RECT  86.1 37.763 86.52 39.011 ;
     RECT  31.92 38.725 32.412 39.205 ;
     RECT  45.6 2.151 45.912 39.205 ;
     RECT  31.92 39.205 32.712 39.253 ;
     RECT  33.792 38.773 35.112 39.253 ;
     RECT  99.6 34.259 99.912 39.301 ;
     RECT  23.808 38.819 27.144 39.347 ;
     RECT  29.4 38.677 30.312 39.395 ;
     RECT  91.5 37.333 92.328 39.395 ;
     RECT  99.6 39.301 100.44 39.493 ;
     RECT  45.504 39.205 45.912 39.589 ;
     RECT  31.92 39.253 35.112 40.019 ;
     RECT  99.6 39.493 101.304 40.261 ;
     RECT  23.808 39.347 25.128 40.451 ;
     RECT  88.8 38.243 90.312 40.499 ;
     RECT  26.7 39.347 27.144 40.595 ;
     RECT  32.1 40.019 35.112 40.979 ;
     RECT  42.9 2.151 43.212 40.981 ;
     RECT  90.288 40.499 90.312 41.075 ;
     RECT  99.6 40.261 102.024 41.075 ;
     RECT  24 40.451 25.128 41.317 ;
     RECT  26.7 40.595 27.012 41.317 ;
     RECT  34.8 40.979 35.112 41.509 ;
     RECT  32.1 40.979 33.768 41.651 ;
     RECT  42.9 40.981 43.944 41.651 ;
     RECT  99.6 41.075 101.976 41.651 ;
     RECT  45.504 39.589 46.488 41.699 ;
     RECT  95.712 37.091 95.736 41.941 ;
     RECT  96.9 37.763 97.212 41.941 ;
     RECT  99.6 41.651 101.592 41.989 ;
     RECT  24 41.317 27.012 42.227 ;
     RECT  45.6 41.699 46.488 42.227 ;
     RECT  48.3 2.151 48.612 42.421 ;
     RECT  95.712 41.941 97.212 42.421 ;
     RECT  24 42.227 25.128 42.467 ;
     RECT  29.4 39.395 29.712 42.469 ;
     RECT  48.192 42.421 48.612 42.709 ;
     RECT  99.408 41.989 101.592 42.757 ;
     RECT  99.312 42.757 102.024 42.803 ;
     RECT  48.144 42.709 48.612 43.093 ;
     RECT  47.568 43.093 48.612 43.237 ;
     RECT  29.4 42.469 30.024 43.333 ;
     RECT  34.8 41.509 35.256 43.333 ;
     RECT  32.1 41.651 33.288 43.379 ;
     RECT  101.424 42.803 102.024 43.427 ;
     RECT  99.312 42.803 100.296 43.571 ;
     RECT  26.7 42.227 27.012 43.573 ;
     RECT  99.312 43.571 99.912 43.573 ;
     RECT  40.2 2.151 40.512 43.621 ;
     RECT  41.616 43.141 41.64 43.621 ;
     RECT  47.568 43.237 48.936 43.667 ;
     RECT  101.52 43.427 102.024 43.667 ;
     RECT  51 2.151 51.312 43.861 ;
     RECT  29.28 43.333 30.024 44.195 ;
     RECT  51 43.861 51.432 44.389 ;
     RECT  99.168 43.573 99.912 44.483 ;
     RECT  42.9 41.651 43.212 44.581 ;
     RECT  32.1 43.379 32.712 44.725 ;
     RECT  40.2 43.621 41.64 44.773 ;
     RECT  42.9 44.581 44.088 44.773 ;
     RECT  101.52 43.667 101.976 44.773 ;
     RECT  95.712 42.421 97.32 44.915 ;
     RECT  37.5 2.151 37.812 44.965 ;
     RECT  99.312 44.483 99.912 45.107 ;
     RECT  37.5 44.965 38.088 45.541 ;
     RECT  26.7 43.573 27.144 45.589 ;
     RECT  40.2 44.773 44.088 45.635 ;
     RECT  50.736 44.389 51.432 45.635 ;
     RECT  99.408 45.107 99.912 45.635 ;
     RECT  101.52 44.773 102.024 45.635 ;
     RECT  42.144 45.635 44.088 45.683 ;
     RECT  47.568 43.667 48.744 46.117 ;
     RECT  37.008 45.541 38.088 46.211 ;
     RECT  42.144 45.683 43.512 46.211 ;
     RECT  101.52 45.635 101.544 46.211 ;
     RECT  26.7 45.589 27.528 46.213 ;
     RECT  34.8 43.333 35.352 46.213 ;
     RECT  40.2 45.635 40.92 46.693 ;
     RECT  42.9 46.211 43.512 46.739 ;
     RECT  34.8 46.213 35.88 46.741 ;
     RECT  26.208 46.213 27.528 46.787 ;
     RECT  47.568 46.117 49.272 47.269 ;
     RECT  99.6 45.635 99.912 47.317 ;
     RECT  47.28 47.269 49.272 47.363 ;
     RECT  34.32 46.741 35.88 47.747 ;
     RECT  40.08 46.693 40.92 47.845 ;
     RECT  99.168 47.317 99.912 47.845 ;
     RECT  42.9 46.739 43.212 47.893 ;
     RECT  95.712 44.915 97.212 47.893 ;
     RECT  31.92 44.725 32.712 47.939 ;
     RECT  99.168 47.845 100.392 48.083 ;
     RECT  40.08 47.845 41.592 48.085 ;
     RECT  88.8 40.499 89.112 48.373 ;
     RECT  34.32 47.747 35.352 48.421 ;
     RECT  47.28 47.363 48.744 48.421 ;
     RECT  95.712 47.893 97.704 48.467 ;
     RECT  46.896 48.421 48.744 48.515 ;
     RECT  95.712 48.467 97.212 48.515 ;
     RECT  34.032 48.421 35.352 48.805 ;
     RECT  51 45.635 51.432 48.805 ;
     RECT  39.504 48.085 41.592 48.899 ;
     RECT  45.6 42.227 45.912 48.901 ;
     RECT  46.896 48.515 47.304 48.901 ;
     RECT  99.6 48.083 100.392 48.901 ;
     RECT  26.7 46.787 27.528 48.949 ;
     RECT  88.704 48.373 89.112 48.949 ;
     RECT  99.6 48.901 100.872 48.949 ;
     RECT  99.6 48.949 101.304 48.997 ;
     RECT  50.88 48.805 51.432 49.235 ;
     RECT  29.4 44.195 30.024 49.477 ;
     RECT  99.6 48.997 101.448 49.477 ;
     RECT  72.6 2.151 72.912 49.525 ;
     RECT  80.7 2.151 81.012 49.525 ;
     RECT  42.768 47.893 43.212 49.619 ;
     RECT  32.1 47.939 32.712 49.811 ;
     RECT  37.008 46.211 37.812 49.861 ;
     RECT  78 2.151 78.312 49.909 ;
     RECT  51 49.235 51.432 50.005 ;
     RECT  67.2 2.151 67.512 50.005 ;
     RECT  32.1 49.811 32.412 50.053 ;
     RECT  75.3 2.151 75.612 50.053 ;
     RECT  29.4 49.477 30.744 50.101 ;
     RECT  48.3 48.515 48.744 50.245 ;
     RECT  72.336 49.525 72.912 50.245 ;
     RECT  80.016 49.525 81.012 50.291 ;
     RECT  45.6 48.901 47.304 50.339 ;
     RECT  33.984 48.805 35.352 50.677 ;
     RECT  39.504 48.899 40.92 50.677 ;
     RECT  75.3 50.053 76.152 50.677 ;
     RECT  33.648 50.677 35.352 50.771 ;
     RECT  26.7 48.949 28.248 50.819 ;
     RECT  46.896 50.339 47.304 50.869 ;
     RECT  48.3 50.245 49.032 50.869 ;
     RECT  61.8 2.151 62.112 51.205 ;
     RECT  61.8 51.205 63.096 51.253 ;
     RECT  64.5 2.151 64.812 51.253 ;
     RECT  46.896 50.869 49.032 51.299 ;
     RECT  48.3 51.299 49.032 51.347 ;
     RECT  71.856 50.245 72.912 51.349 ;
     RECT  29.4 50.101 30.84 51.397 ;
     RECT  31.824 50.053 32.412 51.397 ;
     RECT  26.7 50.819 27.528 51.539 ;
     RECT  67.2 50.005 67.704 51.539 ;
     RECT  45.6 50.339 45.912 51.541 ;
     RECT  46.896 51.299 47.304 51.541 ;
     RECT  39.072 50.677 40.92 51.781 ;
     RECT  42.9 49.619 43.212 51.781 ;
     RECT  69.9 2.151 70.212 51.781 ;
     RECT  29.4 51.397 32.412 51.829 ;
     RECT  33.648 50.771 35.112 51.829 ;
     RECT  69.9 51.781 70.44 51.829 ;
     RECT  71.808 51.349 72.912 51.829 ;
     RECT  87.888 48.949 89.112 51.923 ;
     RECT  69.9 51.829 72.912 52.403 ;
     RECT  75.3 50.677 76.68 52.405 ;
     RECT  77.76 49.909 78.312 52.405 ;
     RECT  29.4 51.829 35.112 52.453 ;
     RECT  51 50.005 51.912 52.499 ;
     RECT  95.712 52.213 95.736 52.549 ;
     RECT  61.8 51.253 64.812 52.595 ;
     RECT  80.064 50.291 81.012 52.691 ;
     RECT  94.2 35.411 94.512 52.741 ;
     RECT  95.616 52.549 95.736 52.741 ;
     RECT  26.7 51.539 27.012 52.837 ;
     RECT  39.072 51.781 41.4 52.979 ;
     RECT  80.7 52.691 81.012 52.981 ;
     RECT  82.032 52.405 82.056 52.981 ;
     RECT  42.432 51.781 43.212 53.027 ;
     RECT  75.3 52.405 78.312 53.219 ;
     RECT  80.7 52.981 82.056 53.267 ;
     RECT  67.2 51.539 67.608 53.317 ;
     RECT  59.1 2.151 59.412 53.557 ;
     RECT  61.8 52.595 62.112 53.557 ;
     RECT  69.9 52.403 70.968 53.557 ;
     RECT  99.6 49.477 102.024 53.747 ;
     RECT  29.28 52.453 35.112 53.891 ;
     RECT  61.536 53.557 62.112 53.893 ;
     RECT  63.792 52.595 64.812 54.085 ;
     RECT  80.7 53.267 81.768 54.085 ;
     RECT  42.672 53.027 43.212 54.131 ;
     RECT  26.7 52.837 27.144 54.179 ;
     RECT  99.6 53.747 101.976 54.179 ;
     RECT  69.744 53.557 70.968 54.181 ;
     RECT  29.28 53.891 30.024 54.323 ;
     RECT  61.536 53.893 62.424 54.421 ;
     RECT  79.92 54.085 81.768 54.517 ;
     RECT  75.3 53.219 75.612 54.565 ;
     RECT  51 52.499 51.432 54.613 ;
     RECT  69.744 54.181 71.448 54.661 ;
     RECT  72.6 52.403 72.912 54.661 ;
     RECT  60.912 54.421 62.424 54.707 ;
     RECT  67.2 53.317 67.8 54.755 ;
     RECT  53.7 2.151 54.012 54.805 ;
     RECT  31.776 53.891 35.112 54.949 ;
     RECT  29.4 54.323 30.024 54.997 ;
     RECT  31.2 54.949 35.112 54.997 ;
     RECT  76.656 53.219 78.312 55.189 ;
     RECT  39.504 52.979 41.4 55.237 ;
     RECT  42.9 54.131 43.212 55.237 ;
     RECT  48.3 51.347 48.612 55.237 ;
     RECT  59.1 53.557 59.544 55.237 ;
     RECT  79.92 54.517 81.96 55.237 ;
     RECT  83.4 2.151 83.712 55.237 ;
     RECT  75.168 54.565 75.612 55.285 ;
     RECT  76.656 55.189 78.408 55.285 ;
     RECT  94.2 52.741 95.736 55.331 ;
     RECT  99.6 54.179 101.448 55.333 ;
     RECT  99.6 55.333 101.688 55.429 ;
     RECT  53.568 54.805 54.012 55.475 ;
     RECT  86.1 39.011 86.412 55.477 ;
     RECT  29.4 54.997 35.112 55.669 ;
     RECT  68.784 54.661 72.912 55.669 ;
     RECT  60.912 54.707 62.112 55.765 ;
     RECT  68.784 55.669 73.608 55.811 ;
     RECT  53.7 55.475 54.012 55.813 ;
     RECT  56.4 2.151 56.712 55.813 ;
     RECT  75.168 55.285 78.408 55.813 ;
     RECT  63.792 54.085 65.592 55.859 ;
     RECT  58.56 55.237 59.544 55.861 ;
     RECT  60.912 55.765 62.376 55.861 ;
     RECT  39.504 55.237 41.736 55.907 ;
     RECT  68.784 55.811 72.912 55.907 ;
     RECT  79.92 55.237 83.712 55.907 ;
     RECT  28.56 55.669 35.112 55.955 ;
     RECT  86.1 55.477 87.192 55.957 ;
     RECT  75.072 55.813 78.408 56.101 ;
     RECT  99.6 55.429 102.024 56.245 ;
     RECT  58.56 55.861 62.376 56.341 ;
     RECT  79.92 55.907 81.768 56.483 ;
     RECT  94.2 55.331 95.688 56.483 ;
     RECT  85.488 55.957 87.192 56.485 ;
     RECT  30.72 55.955 35.112 56.531 ;
     RECT  42.9 55.237 43.896 56.723 ;
     RECT  51 54.613 52.344 56.725 ;
     RECT  53.7 55.813 54.216 56.771 ;
     RECT  50.736 56.725 52.344 56.867 ;
     RECT  36.72 49.861 37.812 56.965 ;
     RECT  39.504 55.907 40.872 56.965 ;
     RECT  67.2 54.755 67.512 56.965 ;
     RECT  75.072 56.101 78.648 56.965 ;
     RECT  80.7 56.483 81.768 56.965 ;
     RECT  82.8 55.907 83.712 56.965 ;
     RECT  28.56 55.955 29.712 57.059 ;
     RECT  56.304 55.813 56.712 57.059 ;
     RECT  58.128 56.341 62.376 57.059 ;
     RECT  74.208 56.965 78.648 57.059 ;
     RECT  94.2 56.483 95.592 57.059 ;
     RECT  68.784 55.907 70.212 57.061 ;
     RECT  71.616 55.907 72.912 57.061 ;
     RECT  51 56.867 52.344 57.299 ;
     RECT  51 57.299 52.104 57.443 ;
     RECT  29.4 57.059 29.712 57.541 ;
     RECT  95.568 57.059 95.592 57.635 ;
     RECT  99.504 56.245 102.024 57.635 ;
     RECT  80.7 56.965 83.712 57.827 ;
     RECT  66.48 56.965 67.512 57.875 ;
     RECT  56.4 57.059 56.712 58.021 ;
     RECT  63.792 55.859 64.812 58.117 ;
     RECT  36.72 56.965 40.872 58.163 ;
     RECT  75.3 57.059 78.648 58.163 ;
     RECT  94.2 57.059 94.512 58.213 ;
     RECT  77.136 58.163 78.648 58.355 ;
     RECT  91.5 39.395 91.812 58.405 ;
     RECT  99.6 57.635 102.024 58.499 ;
     RECT  31.152 56.531 35.112 58.547 ;
     RECT  67.2 57.875 67.512 58.645 ;
     RECT  68.784 57.061 72.912 58.645 ;
     RECT  80.7 57.827 81.816 58.645 ;
     RECT  85.488 56.485 87.768 58.645 ;
     RECT  91.5 58.405 92.472 58.693 ;
     RECT  93.456 58.213 94.512 58.693 ;
     RECT  59.1 57.059 62.376 58.741 ;
     RECT  56.4 58.021 57.048 58.787 ;
     RECT  77.28 58.355 78.648 58.979 ;
     RECT  67.2 58.645 72.912 59.027 ;
     RECT  39.36 58.163 40.872 59.075 ;
     RECT  53.7 56.771 54.12 59.173 ;
     RECT  77.52 58.979 78.648 59.173 ;
     RECT  42.9 56.723 43.212 59.221 ;
     RECT  29.4 57.541 29.832 59.315 ;
     RECT  84.816 58.645 87.768 59.315 ;
     RECT  99.6 58.499 101.832 59.315 ;
     RECT  84.816 59.315 87.336 59.363 ;
     RECT  58.704 58.741 62.376 59.605 ;
     RECT  63.504 58.117 64.812 59.605 ;
     RECT  29.4 59.315 29.712 59.749 ;
     RECT  45.6 51.541 47.304 59.797 ;
     RECT  48.3 55.237 49.128 59.797 ;
     RECT  52.56 58.645 52.584 59.893 ;
     RECT  39.504 59.075 40.872 59.989 ;
     RECT  51 57.443 51.432 59.989 ;
     RECT  67.2 59.027 67.8 59.989 ;
     RECT  68.784 59.027 72.912 59.989 ;
     RECT  52.56 59.893 52.68 60.035 ;
     RECT  75.3 58.163 76.008 60.085 ;
     RECT  77.52 59.173 78.84 60.085 ;
     RECT  0.192 60.037 0.216 60.133 ;
     RECT  36.72 58.163 37.812 60.181 ;
     RECT  15.9 2.151 16.212 60.277 ;
     RECT  67.2 59.989 72.912 60.277 ;
     RECT  74.208 57.059 74.232 60.277 ;
     RECT  75.3 60.085 78.84 60.277 ;
     RECT  74.208 60.277 78.84 60.323 ;
     RECT  51 59.989 51.576 60.325 ;
     RECT  56.4 58.787 56.712 60.373 ;
     RECT  58.704 59.605 64.812 60.419 ;
     RECT  99.6 59.315 101.688 60.421 ;
     RECT  85.728 59.363 87.336 60.467 ;
     RECT  50.784 60.325 51.576 60.515 ;
     RECT  66.864 60.277 72.912 60.613 ;
     RECT  80.496 58.645 81.816 60.803 ;
     RECT  53.7 59.173 54.504 60.805 ;
     RECT  45.6 59.797 49.128 60.851 ;
     RECT  31.2 58.547 35.112 60.997 ;
     RECT  99.6 60.421 101.784 60.997 ;
     RECT  29.088 59.749 29.712 61.043 ;
     RECT  86.1 60.467 87.336 61.043 ;
     RECT  24 42.467 24.312 61.045 ;
     RECT  15.9 60.277 16.536 61.091 ;
     RECT  23.904 61.045 24.312 61.187 ;
     RECT  96.9 48.515 97.212 61.477 ;
     RECT  36.384 60.181 37.812 61.525 ;
     RECT  39.504 59.989 41.064 61.525 ;
     RECT  59.1 60.419 64.812 61.619 ;
     RECT  36.384 61.525 38.136 61.717 ;
     RECT  66.864 60.613 73.032 61.765 ;
     RECT  86.1 61.043 86.412 61.765 ;
     RECT  36.384 61.717 38.328 61.859 ;
     RECT  42.9 59.221 43.368 61.907 ;
     RECT  56.4 60.373 57.624 61.907 ;
     RECT  88.8 51.923 89.112 61.909 ;
     RECT  53.7 60.805 54.84 61.955 ;
     RECT  80.7 60.803 81.816 61.957 ;
     RECT  82.8 57.827 83.712 61.957 ;
     RECT  99.6 60.997 102.024 62.053 ;
     RECT  39.504 61.525 41.496 62.101 ;
     RECT  39.36 62.101 41.496 62.195 ;
     RECT  26.7 54.179 27.012 62.341 ;
     RECT  74.208 60.323 76.008 62.437 ;
     RECT  80.7 61.957 83.712 62.485 ;
     RECT  80.544 62.485 83.712 62.533 ;
     RECT  50.784 60.515 51.312 62.579 ;
     RECT  85.68 61.765 86.412 62.579 ;
     RECT  36.48 61.859 38.328 62.675 ;
     RECT  66.192 61.765 73.032 62.723 ;
     RECT  99.312 62.053 102.024 62.723 ;
     RECT  26.7 62.341 27.96 62.771 ;
     RECT  29.28 61.043 29.712 62.819 ;
     RECT  74.064 62.437 76.008 62.867 ;
     RECT  59.1 61.619 62.112 62.963 ;
     RECT  91.5 58.693 94.512 63.013 ;
     RECT  45.6 60.851 47.304 63.205 ;
     RECT  48.3 60.851 49.128 63.205 ;
     RECT  75.3 62.867 76.008 63.205 ;
     RECT  99.6 62.723 102.024 63.299 ;
     RECT  86.1 62.579 86.412 63.301 ;
     RECT  75.3 63.205 76.392 63.349 ;
     RECT  77.52 60.323 78.84 63.349 ;
     RECT  53.7 61.955 54.012 63.493 ;
     RECT  86.1 63.301 86.856 63.493 ;
     RECT  87.936 61.909 89.112 63.493 ;
     RECT  90.576 63.013 94.512 63.493 ;
     RECT  84.912 63.349 84.936 63.539 ;
     RECT  65.808 63.301 65.832 63.587 ;
     RECT  75.3 63.349 78.84 63.587 ;
     RECT  77.52 63.587 78.84 63.781 ;
     RECT  80.4 62.533 83.712 63.781 ;
     RECT  86.1 63.493 89.112 63.781 ;
     RECT  75.3 63.587 76.392 63.827 ;
     RECT  98.592 63.253 98.616 63.829 ;
     RECT  99.6 63.299 101.736 63.829 ;
     RECT  85.488 63.781 89.112 63.875 ;
     RECT  98.592 63.829 101.736 63.971 ;
     RECT  74.064 62.867 74.232 64.019 ;
     RECT  77.52 63.781 83.712 64.019 ;
     RECT  45.6 63.205 49.128 64.069 ;
     RECT  53.7 63.493 54.504 64.355 ;
     RECT  51 62.579 51.312 64.357 ;
     RECT  56.4 61.907 56.712 64.357 ;
     RECT  61.68 62.963 62.112 64.357 ;
     RECT  90.528 63.493 94.512 64.451 ;
     RECT  93.408 64.451 94.512 64.547 ;
     RECT  90.528 64.451 91.812 64.597 ;
     RECT  61.68 64.357 62.28 64.643 ;
     RECT  95.568 64.597 95.592 64.645 ;
     RECT  94.2 64.547 94.512 64.693 ;
     RECT  95.568 64.645 95.736 64.693 ;
     RECT  78 64.019 83.712 64.741 ;
     RECT  78 64.741 84.216 64.789 ;
     RECT  85.488 63.875 87.768 64.789 ;
     RECT  45.6 64.069 49.272 64.931 ;
     RECT  78 64.789 87.768 64.931 ;
     RECT  98.592 63.971 101.64 64.979 ;
     RECT  85.488 64.931 86.856 65.027 ;
     RECT  55.344 64.933 55.368 65.075 ;
     RECT  99.12 64.979 101.64 65.171 ;
     RECT  74.208 64.019 74.232 65.173 ;
     RECT  96.9 61.477 97.464 65.365 ;
     RECT  39.36 62.195 40.512 65.509 ;
     RECT  78 64.931 84.12 65.603 ;
     RECT  36.72 62.675 38.328 65.653 ;
     RECT  39.36 65.509 40.632 65.653 ;
     RECT  50.256 64.357 51.312 65.699 ;
     RECT  53.7 64.355 54.012 65.845 ;
     RECT  59.1 62.963 60.696 65.845 ;
     RECT  53.7 65.845 54.12 65.989 ;
     RECT  94.2 64.693 95.736 65.989 ;
     RECT  31.008 60.997 35.112 66.085 ;
     RECT  78 65.603 78.84 66.085 ;
     RECT  75.3 63.827 76.2 66.179 ;
     RECT  80.4 65.603 84.12 66.179 ;
     RECT  96.9 65.365 98.04 66.179 ;
     RECT  63.456 61.619 64.812 66.277 ;
     RECT  86.1 65.027 86.856 66.325 ;
     RECT  56.4 64.357 57.624 66.371 ;
     RECT  50.592 65.699 51.312 66.515 ;
     RECT  74.112 65.173 74.232 66.517 ;
     RECT  75.3 66.179 76.008 66.517 ;
     RECT  63.456 66.277 64.92 66.563 ;
     RECT  74.112 66.517 76.008 66.563 ;
     RECT  29.4 62.819 29.712 66.661 ;
     RECT  30.72 66.085 35.112 66.661 ;
     RECT  53.7 65.989 54.216 66.707 ;
     RECT  99.6 65.171 101.64 66.709 ;
     RECT  96.9 66.179 97.464 66.755 ;
     RECT  96.9 66.755 97.32 66.803 ;
     RECT  36.72 65.653 40.632 66.899 ;
     RECT  80.7 66.179 84.12 67.043 ;
     RECT  58.704 65.845 60.696 67.045 ;
     RECT  61.68 64.643 62.112 67.045 ;
     RECT  80.7 67.043 83.832 67.235 ;
     RECT  55.296 65.845 55.32 67.283 ;
     RECT  74.208 66.563 76.008 67.283 ;
     RECT  77.184 66.085 78.84 67.475 ;
     RECT  53.7 66.707 54.12 67.477 ;
     RECT  94.2 65.989 95.784 67.573 ;
     RECT  96.9 66.803 97.212 67.573 ;
     RECT  58.704 67.045 62.112 67.765 ;
     RECT  66.864 62.723 73.032 67.765 ;
     RECT  74.208 67.283 74.28 67.765 ;
     RECT  99.6 66.709 101.736 67.813 ;
     RECT  45.6 64.931 49.128 67.909 ;
     RECT  53.568 67.477 54.12 67.909 ;
     RECT  88.8 63.875 89.112 68.245 ;
     RECT  90.48 64.597 91.812 68.245 ;
     RECT  44.208 67.477 44.232 68.291 ;
     RECT  41.664 68.197 41.688 68.341 ;
     RECT  42.9 61.907 43.212 68.341 ;
     RECT  66.864 67.765 74.28 68.387 ;
     RECT  41.664 68.341 43.212 68.389 ;
     RECT  66.864 68.387 74.232 68.435 ;
     RECT  88.32 68.245 89.112 68.437 ;
     RECT  90.192 68.245 91.812 68.437 ;
     RECT  99.6 67.813 102.024 68.485 ;
     RECT  36.72 66.899 40.512 68.531 ;
     RECT  99.6 68.485 102.216 68.627 ;
     RECT  84.96 68.101 84.984 68.629 ;
     RECT  86.1 66.325 87.192 68.629 ;
     RECT  94.2 67.573 97.212 68.629 ;
     RECT  92.88 68.485 92.904 68.675 ;
     RECT  66.864 68.435 67.8 68.725 ;
     RECT  80.7 67.235 83.712 68.771 ;
     RECT  84.96 68.629 87.192 68.771 ;
     RECT  36.72 68.531 38.328 68.869 ;
     RECT  0.192 60.133 0.36 69.011 ;
     RECT  94.2 68.629 98.04 69.011 ;
     RECT  39.36 68.531 40.512 69.107 ;
     RECT  41.664 68.389 43.32 69.107 ;
     RECT  66.24 68.725 67.8 69.155 ;
     RECT  75.3 67.283 76.008 69.301 ;
     RECT  85.104 68.771 87.192 69.301 ;
     RECT  88.32 68.437 91.812 69.301 ;
     RECT  99.6 68.627 102.024 69.301 ;
     RECT  58.128 67.765 62.112 69.443 ;
     RECT  45.6 67.909 49.176 69.493 ;
     RECT  75.3 69.301 76.296 69.493 ;
     RECT  45.504 69.493 49.176 69.539 ;
     RECT  42.576 69.107 43.32 69.587 ;
     RECT  95.76 69.011 98.04 69.587 ;
     RECT  85.104 69.301 91.944 69.635 ;
     RECT  63.456 66.563 64.812 69.685 ;
     RECT  91.392 69.635 91.944 69.685 ;
     RECT  53.568 67.909 54.264 69.779 ;
     RECT  91.392 69.685 92.28 69.827 ;
     RECT  94.2 69.011 94.512 69.829 ;
     RECT  39.456 69.107 40.512 70.019 ;
     RECT  85.104 69.635 90.36 70.019 ;
     RECT  26.7 62.771 27.012 70.021 ;
     RECT  28.224 69.301 28.248 70.021 ;
     RECT  26.7 70.021 28.248 70.067 ;
     RECT  66.24 69.155 67.752 70.069 ;
     RECT  83.136 68.771 83.712 70.069 ;
     RECT  85.104 70.019 89.208 70.069 ;
     RECT  90.336 70.019 90.36 70.115 ;
     RECT  46.896 69.539 49.176 70.163 ;
     RECT  99.456 69.301 102.024 70.163 ;
     RECT  58.656 69.443 62.112 70.357 ;
     RECT  63.456 69.685 65.016 70.357 ;
     RECT  78 67.475 78.84 70.405 ;
     RECT  45.504 69.539 45.912 70.549 ;
     RECT  46.896 70.163 47.304 70.549 ;
     RECT  58.656 70.357 65.016 70.549 ;
     RECT  66 70.069 67.752 70.549 ;
     RECT  91.392 69.827 91.812 70.597 ;
     RECT  36.48 68.869 38.328 70.643 ;
     RECT  42.9 69.587 43.32 70.643 ;
     RECT  55.296 69.733 55.32 70.645 ;
     RECT  99.456 70.163 101.976 70.645 ;
     RECT  26.7 70.067 27.96 70.739 ;
     RECT  45.504 70.549 47.304 70.739 ;
     RECT  96.9 69.587 98.04 70.739 ;
     RECT  94.08 69.829 94.512 70.741 ;
     RECT  94.032 70.741 94.512 70.837 ;
     RECT  56.4 66.371 56.712 70.885 ;
     RECT  99.408 70.645 101.976 70.931 ;
     RECT  94.032 70.837 94.632 70.933 ;
     RECT  94.032 70.933 95.064 71.027 ;
     RECT  56.4 70.885 57.288 71.077 ;
     RECT  58.656 70.549 67.752 71.077 ;
     RECT  83.136 70.069 89.208 71.123 ;
     RECT  75.3 69.493 76.632 71.173 ;
     RECT  77.904 70.405 78.84 71.173 ;
     RECT  52.416 70.021 52.44 71.315 ;
     RECT  94.08 71.027 95.064 71.315 ;
     RECT  99.408 70.931 101.928 71.315 ;
     RECT  99.408 71.315 101.832 71.411 ;
     RECT  99.408 71.411 101.64 71.507 ;
     RECT  55.056 70.645 55.32 71.555 ;
     RECT  55.296 71.555 55.32 71.651 ;
     RECT  56.4 71.077 67.752 71.651 ;
     RECT  80.7 68.771 81.864 71.653 ;
     RECT  51 66.515 51.312 71.701 ;
     RECT  75.3 71.173 78.84 71.749 ;
     RECT  80.592 71.653 81.864 71.749 ;
     RECT  90.576 70.597 91.812 71.941 ;
     RECT  42.9 70.643 43.212 71.989 ;
     RECT  29.4 66.661 35.112 72.037 ;
     RECT  50.688 71.701 51.312 72.037 ;
     RECT  64.128 71.651 67.752 72.133 ;
     RECT  29.4 72.037 35.688 72.181 ;
     RECT  42.9 71.989 43.8 72.229 ;
     RECT  45.6 70.739 47.304 72.229 ;
     RECT  48.3 70.163 49.128 72.229 ;
     RECT  42.672 72.229 43.8 72.325 ;
     RECT  94.2 71.315 95.064 72.565 ;
     RECT  75.3 71.749 81.864 72.611 ;
     RECT  94.08 72.565 95.064 72.611 ;
     RECT  83.136 71.123 89.112 72.661 ;
     RECT  53.568 69.779 54.012 72.805 ;
     RECT  99.6 71.507 101.64 72.805 ;
     RECT  96.9 70.739 97.212 72.853 ;
     RECT  39.504 70.019 40.512 72.901 ;
     RECT  99.6 72.805 102.024 72.901 ;
     RECT  64.128 72.133 67.8 72.947 ;
     RECT  45.6 72.229 49.128 72.949 ;
     RECT  50.688 72.037 51.864 72.949 ;
     RECT  28.752 72.181 35.688 72.995 ;
     RECT  83.136 72.661 89.4 72.995 ;
     RECT  77.424 72.611 81.864 72.997 ;
     RECT  83.136 72.995 86.412 72.997 ;
     RECT  87.456 72.995 89.4 72.997 ;
     RECT  28.752 72.995 29.712 73.093 ;
     RECT  87.456 72.997 89.448 73.139 ;
     RECT  77.424 72.997 86.412 73.187 ;
     RECT  87.456 73.139 89.304 73.235 ;
     RECT  87.984 73.235 89.304 73.379 ;
     RECT  45.6 72.949 51.864 73.381 ;
     RECT  99.168 72.901 102.024 73.381 ;
     RECT  90.528 71.941 91.812 73.427 ;
     RECT  96.48 72.853 97.212 73.429 ;
     RECT  56.4 71.651 63.048 73.523 ;
     RECT  94.08 72.611 94.632 73.573 ;
     RECT  64.128 72.947 64.92 73.667 ;
     RECT  96.48 73.429 97.416 73.715 ;
     RECT  58.128 73.523 63.048 73.811 ;
     RECT  39.36 72.901 40.512 73.907 ;
     RECT  90.576 73.427 91.812 74.051 ;
     RECT  31.2 72.995 35.688 74.053 ;
     RECT  36.72 70.643 38.328 74.053 ;
     RECT  66 72.947 67.8 74.053 ;
     RECT  68.784 68.435 74.232 74.053 ;
     RECT  96.576 73.715 97.416 74.053 ;
     RECT  98.448 73.381 102.024 74.147 ;
     RECT  77.424 73.187 81.864 74.195 ;
     RECT  87.984 73.379 89.112 74.291 ;
     RECT  45.072 73.381 51.864 74.339 ;
     RECT  90.864 74.051 91.812 74.339 ;
     RECT  98.448 74.147 101.976 74.339 ;
     RECT  41.712 72.325 43.8 74.483 ;
     RECT  50.16 74.339 51.864 74.579 ;
     RECT  53.568 72.805 54.744 74.579 ;
     RECT  80.7 74.195 81.864 74.581 ;
     RECT  87.696 74.341 87.72 74.581 ;
     RECT  39.504 73.907 40.512 74.629 ;
     RECT  83.232 73.187 86.412 74.629 ;
     RECT  87.456 74.581 87.72 74.629 ;
     RECT  45.072 74.339 49.128 74.675 ;
     RECT  83.232 74.629 87.72 74.675 ;
     RECT  94.08 73.573 95.064 74.771 ;
     RECT  66 74.053 74.232 74.821 ;
     RECT  75.3 72.611 76.296 74.821 ;
     RECT  99.168 74.339 101.976 74.915 ;
     RECT  58.656 73.811 63.048 75.205 ;
     RECT  64.128 73.667 64.812 75.205 ;
     RECT  83.232 74.675 83.712 75.253 ;
     RECT  94.2 74.771 95.064 75.253 ;
     RECT  96.576 74.053 97.464 75.253 ;
     RECT  53.568 74.579 54.12 75.299 ;
     RECT  99.6 74.915 101.976 75.301 ;
     RECT  92.928 74.629 92.952 75.347 ;
     RECT  26.7 70.739 27.012 75.349 ;
     RECT  84.768 74.675 87.72 75.349 ;
     RECT  88.8 74.291 89.112 75.349 ;
     RECT  91.5 74.339 91.812 75.397 ;
     RECT  94.2 75.253 97.464 75.443 ;
     RECT  77.424 74.195 78.84 75.445 ;
     RECT  42.672 74.483 43.8 75.541 ;
     RECT  56.4 73.523 56.712 75.541 ;
     RECT  77.424 75.445 79.128 75.731 ;
     RECT  50.16 74.579 51.312 75.733 ;
     RECT  58.656 75.205 64.812 75.733 ;
     RECT  94.2 75.443 95.688 75.733 ;
     RECT  96.9 75.443 97.464 75.733 ;
     RECT  98.544 75.445 98.568 75.733 ;
     RECT  42.672 75.541 44.472 75.781 ;
     RECT  80.7 74.581 82.056 75.781 ;
     RECT  58.656 75.733 64.92 75.827 ;
     RECT  77.424 75.731 78.84 75.875 ;
     RECT  84.768 75.349 89.112 75.877 ;
     RECT  96.9 75.733 98.568 75.925 ;
     RECT  84.768 75.877 89.208 76.019 ;
     RECT  66 74.821 76.296 76.163 ;
     RECT  96.9 75.925 98.616 76.213 ;
     RECT  99.6 75.301 102.024 76.213 ;
     RECT  58.656 75.827 63.048 76.357 ;
     RECT  80.592 75.781 82.056 76.451 ;
     RECT  26.112 75.349 27.012 76.739 ;
     RECT  39.504 74.629 41.352 76.787 ;
     RECT  80.7 76.451 82.056 76.789 ;
     RECT  83.184 75.253 83.712 76.789 ;
     RECT  31.2 74.053 38.328 76.837 ;
     RECT  50.16 75.733 51.912 76.885 ;
     RECT  94.08 75.733 95.688 76.931 ;
     RECT  30.72 76.837 38.328 76.979 ;
     RECT  45.6 74.675 49.128 76.979 ;
     RECT  50.112 76.885 51.912 76.979 ;
     RECT  53.568 75.299 54.012 76.979 ;
     RECT  55.728 75.541 56.712 76.979 ;
     RECT  96.9 76.213 102.024 76.979 ;
     RECT  80.7 76.789 83.712 77.027 ;
     RECT  50.112 76.979 51.312 77.411 ;
     RECT  42.672 75.781 44.568 77.413 ;
     RECT  45.6 76.979 45.912 77.413 ;
     RECT  96.9 76.979 101.976 77.459 ;
     RECT  83.184 77.027 83.712 77.555 ;
     RECT  91.152 75.397 91.812 77.555 ;
     RECT  98.592 77.459 101.976 77.555 ;
     RECT  80.7 77.027 82.056 77.699 ;
     RECT  94.08 76.931 95.064 77.845 ;
     RECT  24 61.187 24.312 77.941 ;
     RECT  96.9 77.459 97.212 77.941 ;
     RECT  93.408 77.845 95.064 77.987 ;
     RECT  26.7 76.739 27.012 78.037 ;
     RECT  28.656 73.093 29.712 78.037 ;
     RECT  84.768 76.019 89.112 78.037 ;
     RECT  58.128 76.357 63.048 78.131 ;
     RECT  99.12 77.555 101.976 78.131 ;
     RECT  56.4 76.979 56.712 78.133 ;
     RECT  58.128 78.131 59.412 78.133 ;
     RECT  99.12 78.131 101.88 78.227 ;
     RECT  56.4 78.133 59.412 78.275 ;
     RECT  99.12 78.227 99.912 78.323 ;
     RECT  64.128 75.827 64.92 78.565 ;
     RECT  31.2 76.979 38.328 78.613 ;
     RECT  39.504 76.787 40.512 78.613 ;
     RECT  91.5 77.555 91.812 78.661 ;
     RECT  60.72 78.131 63.048 78.707 ;
     RECT  26.7 78.037 29.712 78.899 ;
     RECT  42.672 77.413 45.912 78.899 ;
     RECT  84.768 78.037 90.072 78.899 ;
     RECT  91.5 78.661 92.184 78.901 ;
     RECT  64.128 78.565 64.968 78.947 ;
     RECT  31.2 78.613 40.512 79.045 ;
     RECT  66 76.163 74.232 79.237 ;
     RECT  75.3 76.163 76.296 79.237 ;
     RECT  101.376 78.227 101.4 79.283 ;
     RECT  64.128 78.947 64.92 79.331 ;
     RECT  30.816 79.045 40.512 79.427 ;
     RECT  99.36 78.323 99.912 79.475 ;
     RECT  45.6 78.899 45.912 79.573 ;
     RECT  46.896 76.979 49.128 79.573 ;
     RECT  66 79.237 76.296 79.717 ;
     RECT  45.6 79.573 49.128 79.765 ;
     RECT  50.544 77.411 51.312 79.765 ;
     RECT  80.7 77.699 81.864 79.765 ;
     RECT  83.4 77.555 83.712 79.765 ;
     RECT  58.128 78.275 59.412 79.859 ;
     RECT  66 79.717 76.584 80.243 ;
     RECT  28.656 78.899 29.712 80.291 ;
     RECT  45.6 79.765 51.312 80.291 ;
     RECT  80.7 79.765 83.712 80.291 ;
     RECT  29.28 80.291 29.712 80.293 ;
     RECT  30.816 79.427 38.328 80.293 ;
     RECT  94.08 77.987 95.064 80.293 ;
     RECT  84.768 78.899 89.304 80.387 ;
     RECT  60.864 78.707 63.048 80.389 ;
     RECT  29.28 80.293 38.328 80.435 ;
     RECT  88.032 80.387 89.304 80.435 ;
     RECT  75.3 80.243 76.584 80.579 ;
     RECT  94.08 80.293 95.112 80.627 ;
     RECT  26.7 78.899 27.012 80.629 ;
     RECT  46.896 80.291 51.312 80.629 ;
     RECT  29.4 80.435 38.328 80.675 ;
     RECT  91.5 78.901 92.52 80.773 ;
     RECT  94.2 80.627 95.112 80.821 ;
     RECT  53.7 76.979 54.012 80.869 ;
     RECT  94.2 80.821 95.16 80.869 ;
     RECT  96.528 77.941 97.212 80.869 ;
     RECT  83.28 80.291 83.712 80.917 ;
     RECT  84.768 80.387 86.952 80.917 ;
     RECT  26.7 80.629 27.96 80.963 ;
     RECT  29.4 80.675 29.976 80.963 ;
     RECT  91.5 80.773 92.952 80.963 ;
     RECT  80.7 80.291 82.104 81.059 ;
     RECT  64.128 79.331 64.812 81.107 ;
     RECT  26.7 80.963 27.012 81.109 ;
     RECT  94.2 80.869 97.212 81.395 ;
     RECT  42.672 78.899 44.472 81.445 ;
     RECT  45.6 80.291 45.912 81.445 ;
     RECT  60.864 80.389 63.144 81.445 ;
     RECT  77.712 75.875 78.84 81.445 ;
     RECT  46.896 80.629 52.296 81.539 ;
     RECT  83.28 80.917 86.952 81.539 ;
     RECT  83.4 81.539 86.952 81.589 ;
     RECT  88.032 80.435 89.112 81.589 ;
     RECT  91.5 80.963 92.52 81.635 ;
     RECT  46.896 81.539 51.312 81.875 ;
     RECT  31.2 80.675 38.328 82.019 ;
     RECT  39.504 79.427 40.512 82.021 ;
     RECT  80.7 81.059 81.864 82.021 ;
     RECT  41.616 80.101 41.64 82.067 ;
     RECT  96.288 81.395 97.212 82.115 ;
     RECT  83.4 81.589 89.112 82.307 ;
     RECT  53.28 80.869 54.012 82.453 ;
     RECT  55.248 82.021 55.272 82.453 ;
     RECT  59.1 79.859 59.412 82.501 ;
     RECT  53.28 82.453 55.272 82.643 ;
     RECT  55.248 82.643 55.272 82.691 ;
     RECT  75.3 80.579 76.296 82.789 ;
     RECT  77.712 81.445 79.56 82.789 ;
     RECT  42.672 81.445 45.912 82.931 ;
     RECT  75.3 82.789 79.56 82.931 ;
     RECT  29.4 80.963 29.712 82.933 ;
     RECT  31.2 82.019 32.412 82.933 ;
     RECT  39.456 82.021 40.512 82.933 ;
     RECT  64.5 81.107 64.812 82.981 ;
     RECT  64.5 82.981 64.92 83.029 ;
     RECT  66 80.243 74.232 83.029 ;
     RECT  0.192 69.011 0.216 83.075 ;
     RECT  91.5 81.635 91.812 83.077 ;
     RECT  58.608 82.501 59.412 83.125 ;
     RECT  60.432 81.445 63.144 83.171 ;
     RECT  46.896 81.875 49.128 83.173 ;
     RECT  50.304 81.875 51.312 83.173 ;
     RECT  53.28 82.643 54.012 83.173 ;
     RECT  84.768 82.307 89.112 83.267 ;
     RECT  21.3 2.151 21.612 83.269 ;
     RECT  77.712 82.931 79.56 83.365 ;
     RECT  80.7 82.021 81.912 83.365 ;
     RECT  77.712 83.365 81.912 83.461 ;
     RECT  33.552 82.019 38.328 83.557 ;
     RECT  39.456 82.933 41.4 83.557 ;
     RECT  77.712 83.461 82.392 83.651 ;
     RECT  23.616 77.941 24.312 83.749 ;
     RECT  56.4 78.275 56.712 83.749 ;
     RECT  64.5 83.029 74.232 83.749 ;
     RECT  75.3 82.931 76.296 83.749 ;
     RECT  77.712 83.651 81.864 83.843 ;
     RECT  60.72 83.171 63.144 83.845 ;
     RECT  83.4 82.307 83.712 83.989 ;
     RECT  33.552 83.557 41.4 84.035 ;
     RECT  60.72 83.845 63.48 84.083 ;
     RECT  92.928 84.133 92.952 84.275 ;
     RECT  60.72 84.083 63.24 84.325 ;
     RECT  83.088 83.989 83.712 84.515 ;
     RECT  83.4 84.515 83.712 84.517 ;
     RECT  84.768 83.267 86.952 84.517 ;
     RECT  64.5 83.749 76.296 84.565 ;
     RECT  83.4 84.517 86.952 84.707 ;
     RECT  90.624 83.077 91.812 84.803 ;
     RECT  36.432 84.035 40.512 84.851 ;
     RECT  60.432 84.325 63.24 84.947 ;
     RECT  29.4 82.933 32.412 84.949 ;
     RECT  33.552 84.035 35.112 84.949 ;
     RECT  94.2 81.395 95.16 84.949 ;
     RECT  96.9 82.115 97.212 84.949 ;
     RECT  91.5 84.803 91.812 85.093 ;
     RECT  29.4 84.949 35.112 85.139 ;
     RECT  52.464 83.173 54.012 85.189 ;
     RECT  56.208 83.749 56.712 85.235 ;
     RECT  29.4 85.139 32.412 85.379 ;
     RECT  60.432 84.947 63 85.379 ;
     RECT  36.432 84.851 38.328 85.427 ;
     RECT  83.4 84.707 83.712 85.477 ;
     RECT  94.2 84.949 95.736 85.477 ;
     RECT  96.768 84.949 97.212 85.477 ;
     RECT  52.464 85.189 54.456 85.811 ;
     RECT  77.904 83.843 81.864 85.907 ;
     RECT  57.744 83.125 59.412 85.957 ;
     RECT  60.432 85.379 62.712 85.957 ;
     RECT  82.992 85.477 83.712 86.005 ;
     RECT  84.768 84.707 86.952 86.005 ;
     RECT  88.032 83.267 89.112 86.005 ;
     RECT  57.744 85.957 62.712 86.099 ;
     RECT  33.552 85.139 35.112 86.149 ;
     RECT  64.5 84.565 76.68 86.243 ;
     RECT  42.672 82.931 44.472 86.339 ;
     RECT  88.032 86.005 89.4 86.435 ;
     RECT  91.5 85.093 92.28 86.435 ;
     RECT  91.5 86.435 91.812 86.485 ;
     RECT  36.72 85.427 38.328 86.629 ;
     RECT  39.504 84.851 40.512 86.629 ;
     RECT  94.2 85.477 97.212 86.675 ;
     RECT  96.336 86.675 97.212 86.723 ;
     RECT  57.744 86.099 62.232 86.771 ;
     RECT  57.744 86.771 59.688 86.867 ;
     RECT  56.4 85.235 56.712 87.013 ;
     RECT  63.456 86.917 63.48 87.107 ;
     RECT  45.6 82.931 45.912 87.109 ;
     RECT  82.992 86.005 86.952 87.155 ;
     RECT  33.552 86.149 35.208 87.157 ;
     RECT  36.72 86.629 40.512 87.157 ;
     RECT  60.864 86.771 62.232 87.157 ;
     RECT  60.864 87.157 63.192 87.395 ;
     RECT  77.904 85.907 79.56 87.635 ;
     RECT  42.672 86.339 43.8 87.685 ;
     RECT  33.552 87.157 40.512 87.827 ;
     RECT  56.016 87.013 56.712 87.827 ;
     RECT  53.568 85.811 54.456 88.067 ;
     RECT  78 87.635 79.56 88.069 ;
     RECT  80.7 85.907 81.864 88.069 ;
     RECT  58.128 86.867 59.412 88.115 ;
     RECT  31.2 85.379 32.412 88.309 ;
     RECT  75.3 86.243 76.68 88.357 ;
     RECT  26.4 81.109 27.012 88.403 ;
     RECT  60.864 87.395 62.232 88.453 ;
     RECT  83.4 87.155 86.952 88.597 ;
     RECT  88.032 86.435 89.112 88.597 ;
     RECT  75.3 88.357 76.728 88.693 ;
     RECT  78 88.069 81.864 88.693 ;
     RECT  13.2 2.151 13.512 88.741 ;
     RECT  41.856 87.685 43.8 88.787 ;
     RECT  15.9 61.091 16.212 88.885 ;
     RECT  31.104 88.309 32.412 88.885 ;
     RECT  33.552 87.827 38.328 88.885 ;
     RECT  45.504 87.109 45.912 88.885 ;
     RECT  56.4 87.827 56.712 88.885 ;
     RECT  91.392 86.485 91.812 88.931 ;
     RECT  21.3 83.269 21.912 88.933 ;
     RECT  23.04 83.749 24.312 88.933 ;
     RECT  58.224 88.115 59.412 88.979 ;
     RECT  94.2 86.675 94.776 89.029 ;
     RECT  31.104 88.885 38.328 89.171 ;
     RECT  53.7 88.067 54.456 89.173 ;
     RECT  21.3 88.933 24.312 89.219 ;
     RECT  52.464 85.811 52.488 89.221 ;
     RECT  53.52 89.173 54.456 89.221 ;
     RECT  52.464 89.221 54.456 89.267 ;
     RECT  59.1 88.979 59.412 89.269 ;
     RECT  60.816 88.453 62.232 89.269 ;
     RECT  29.4 85.379 29.712 89.461 ;
     RECT  83.4 88.597 89.112 89.461 ;
     RECT  94.2 89.029 94.872 89.461 ;
     RECT  25.344 80.389 25.368 89.507 ;
     RECT  31.104 89.171 35.64 89.507 ;
     RECT  15.168 88.885 16.212 89.555 ;
     RECT  39.36 87.827 40.512 89.699 ;
     RECT  42.672 88.787 43.8 89.749 ;
     RECT  44.784 88.885 45.912 89.749 ;
     RECT  59.1 89.269 62.232 89.845 ;
     RECT  56.4 88.885 57 89.987 ;
     RECT  59.1 89.845 62.856 89.989 ;
     RECT  64.5 86.243 74.232 89.989 ;
     RECT  83.28 89.461 89.112 90.323 ;
     RECT  13.2 88.741 13.656 90.373 ;
     RECT  75.3 88.693 81.864 90.421 ;
     RECT  83.28 90.323 87.096 90.421 ;
     RECT  41.52 88.885 41.544 90.515 ;
     RECT  75.3 90.421 87.096 90.515 ;
     RECT  9.456 89.461 9.48 90.517 ;
     RECT  10.5 2.151 10.812 90.517 ;
     RECT  42.672 89.749 45.912 90.517 ;
     RECT  59.1 89.989 74.232 90.563 ;
     RECT  56.4 89.987 56.712 90.613 ;
     RECT  29.28 89.461 29.712 90.659 ;
     RECT  42.384 90.517 45.912 90.659 ;
     RECT  94.2 89.461 95.016 90.659 ;
     RECT  88.8 90.323 89.112 91.141 ;
     RECT  90.096 90.565 90.12 91.141 ;
     RECT  52.992 89.267 54.456 91.235 ;
     RECT  75.3 90.515 86.412 91.235 ;
     RECT  56.112 90.613 56.712 91.331 ;
     RECT  15.696 89.555 16.212 91.669 ;
     RECT  9.456 90.517 10.812 91.717 ;
     RECT  33.552 89.507 35.64 91.717 ;
     RECT  84.768 91.235 86.412 91.765 ;
     RECT  96.9 86.723 97.212 91.765 ;
     RECT  15.696 91.669 17.112 91.859 ;
     RECT  39.504 89.699 40.512 92.053 ;
     RECT  63.696 90.563 74.232 92.053 ;
     RECT  75.3 91.235 76.68 92.053 ;
     RECT  12.48 90.373 13.656 92.099 ;
     RECT  88.8 91.141 90.12 92.101 ;
     RECT  91.5 88.931 91.812 92.101 ;
     RECT  94.2 90.659 94.872 92.101 ;
     RECT  88.8 92.101 91.812 92.147 ;
     RECT  18.6 2.151 18.912 92.293 ;
     RECT  29.4 90.659 29.712 92.293 ;
     RECT  56.4 91.331 56.712 92.293 ;
     RECT  57.936 91.717 57.96 92.293 ;
     RECT  36.72 89.171 38.328 92.341 ;
     RECT  39.504 92.053 41.112 92.341 ;
     RECT  9.456 91.717 11.352 92.435 ;
     RECT  46.896 83.173 51.312 92.483 ;
     RECT  42.384 90.659 43.848 92.627 ;
     RECT  56.4 92.293 57.96 92.723 ;
     RECT  52.992 91.235 54.012 92.725 ;
     RECT  36.72 92.341 41.112 92.819 ;
     RECT  13.2 92.099 13.656 92.821 ;
     RECT  63.696 92.053 76.68 92.869 ;
     RECT  91.056 92.147 91.812 92.915 ;
     RECT  84.768 91.765 87.24 92.963 ;
     RECT  94.2 92.101 95.736 92.963 ;
     RECT  88.8 92.147 89.88 93.061 ;
     RECT  88.416 93.061 89.88 93.155 ;
     RECT  29.4 92.293 29.832 93.251 ;
     RECT  84.768 92.963 86.412 93.299 ;
     RECT  7.8 2.151 8.112 93.349 ;
     RECT  45.6 90.659 45.912 93.349 ;
     RECT  46.896 92.483 49.128 93.349 ;
     RECT  88.416 93.155 89.112 93.397 ;
     RECT  13.2 92.821 14.28 93.491 ;
     RECT  13.2 93.491 13.656 93.539 ;
     RECT  59.1 90.563 62.232 93.539 ;
     RECT  94.2 92.963 94.872 93.587 ;
     RECT  33.504 91.717 35.64 93.731 ;
     RECT  15.9 91.859 17.112 93.779 ;
     RECT  63.696 92.869 76.92 93.779 ;
     RECT  63.696 93.779 76.68 93.875 ;
     RECT  50.16 92.483 51.312 93.925 ;
     RECT  45.6 93.349 49.128 94.021 ;
     RECT  50.112 93.925 51.312 94.021 ;
     RECT  56.4 92.723 57.336 94.021 ;
     RECT  59.1 93.539 59.592 94.021 ;
     RECT  6.912 93.349 8.112 94.115 ;
     RECT  45.6 94.021 51.312 94.115 ;
     RECT  46.896 94.115 51.312 94.403 ;
     RECT  52.992 92.725 54.12 94.451 ;
     RECT  15.9 93.779 16.584 94.549 ;
     RECT  84.768 93.299 84.792 94.549 ;
     RECT  86.1 93.299 86.412 94.549 ;
     RECT  29.4 93.251 29.712 94.597 ;
     RECT  58.992 94.021 59.592 94.691 ;
     RECT  59.1 94.691 59.592 94.787 ;
     RECT  64.08 93.875 76.68 94.931 ;
     RECT  10.32 92.435 11.352 95.125 ;
     RECT  13.2 93.539 13.512 95.125 ;
     RECT  36.72 92.819 40.512 95.125 ;
     RECT  42.672 92.627 43.848 95.125 ;
     RECT  50.112 94.403 51.312 95.125 ;
     RECT  56.4 94.021 57.72 95.125 ;
     RECT  87.888 93.397 89.112 95.125 ;
     RECT  55.68 95.125 57.72 95.171 ;
     RECT  5.1 2.151 5.412 95.509 ;
     RECT  24 89.219 24.312 95.509 ;
     RECT  96.9 91.765 98.136 95.557 ;
     RECT  50.112 95.125 51.912 95.603 ;
     RECT  23.616 95.509 24.312 95.701 ;
     RECT  26.7 88.403 27.012 95.701 ;
     RECT  12.96 95.125 13.512 95.747 ;
     RECT  23.616 95.701 24.408 95.749 ;
     RECT  87.744 95.125 89.112 95.795 ;
     RECT  52.992 94.451 54.012 95.843 ;
     RECT  26.16 95.701 27.012 95.893 ;
     RECT  29.04 94.597 29.712 95.939 ;
     RECT  84.768 94.549 86.412 95.987 ;
     RECT  21.3 89.219 22.488 95.989 ;
     RECT  23.616 95.749 24.504 95.989 ;
     RECT  26.16 95.893 27.672 96.035 ;
     RECT  33.552 93.731 35.64 96.181 ;
     RECT  36.72 95.125 41.304 96.181 ;
     RECT  91.5 92.915 91.812 96.181 ;
     RECT  31.104 89.507 32.412 96.275 ;
     RECT  50.16 95.603 51.912 96.323 ;
     RECT  96.9 95.557 98.328 96.325 ;
     RECT  9.696 95.125 11.352 96.371 ;
     RECT  42.672 95.125 44.52 96.371 ;
     RECT  55.68 95.171 57.624 96.371 ;
     RECT  26.7 96.035 27.672 96.419 ;
     RECT  21.3 95.989 24.504 96.467 ;
     RECT  60.864 93.539 62.232 96.469 ;
     RECT  96.384 96.325 98.328 96.515 ;
     RECT  15.12 94.549 16.584 96.707 ;
     RECT  18.096 92.293 18.912 96.805 ;
     RECT  10.32 96.371 11.352 96.851 ;
     RECT  53.7 95.843 54.012 96.853 ;
     RECT  7.68 94.115 8.112 96.899 ;
     RECT  10.32 96.851 10.92 96.947 ;
     RECT  33.552 96.181 41.304 96.947 ;
     RECT  36.72 96.947 41.304 96.995 ;
     RECT  53.7 96.853 54.696 96.995 ;
     RECT  91.5 96.181 92.184 96.995 ;
     RECT  96.384 96.515 97.752 96.995 ;
     RECT  87.888 95.795 89.112 96.997 ;
     RECT  91.5 96.995 91.812 96.997 ;
     RECT  24 96.467 24.504 97.043 ;
     RECT  64.08 94.931 74.232 97.043 ;
     RECT  21.3 96.467 22.488 97.091 ;
     RECT  64.08 97.043 64.812 97.091 ;
     RECT  15.9 96.707 16.584 97.235 ;
     RECT  18.096 96.805 19.032 97.285 ;
     RECT  10.368 96.947 10.92 97.331 ;
     RECT  21.3 97.091 22.44 97.427 ;
     RECT  5.1 95.509 6.12 97.475 ;
     RECT  18.096 97.285 19.992 97.523 ;
     RECT  87.888 96.997 90.072 97.523 ;
     RECT  10.5 97.331 10.92 97.571 ;
     RECT  21.3 97.427 22.248 97.571 ;
     RECT  88.08 97.523 90.072 97.619 ;
     RECT  18.096 97.523 18.912 97.667 ;
     RECT  19.968 97.523 19.992 97.907 ;
     RECT  88.32 97.619 90.072 97.957 ;
     RECT  91.248 96.997 91.812 97.957 ;
     RECT  13.2 95.747 13.512 98.005 ;
     RECT  24 97.043 24.408 98.099 ;
     RECT  60.864 96.469 62.568 98.245 ;
     RECT  60.864 98.245 62.664 98.387 ;
     RECT  56.4 96.371 57.336 98.485 ;
     RECT  33.552 96.947 35.64 98.533 ;
     RECT  36.72 96.995 40.512 98.533 ;
     RECT  7.8 96.899 8.112 98.581 ;
     RECT  31.2 96.275 32.412 98.581 ;
     RECT  33.552 98.533 40.512 98.581 ;
     RECT  96.9 96.995 97.752 98.581 ;
     RECT  56.256 98.485 57.336 98.629 ;
     RECT  46.896 94.403 49.128 98.675 ;
     RECT  59.1 94.787 59.412 98.725 ;
     RECT  46.896 98.675 48.984 98.963 ;
     RECT  58.848 98.725 59.412 98.965 ;
     RECT  56.256 98.629 57.672 99.013 ;
     RECT  55.824 99.013 57.672 99.061 ;
     RECT  58.704 98.965 59.412 99.061 ;
     RECT  88.32 97.957 91.812 99.107 ;
     RECT  42.672 96.371 43.8 99.157 ;
     RECT  53.7 96.995 54.012 99.157 ;
     RECT  13.2 98.005 13.944 99.203 ;
     RECT  42.672 99.157 44.424 99.493 ;
     RECT  45.6 94.115 45.912 99.493 ;
     RECT  55.824 99.061 59.412 99.541 ;
     RECT  60.864 98.387 62.232 99.541 ;
     RECT  31.2 98.581 40.512 99.587 ;
     RECT  66 97.043 74.232 99.589 ;
     RECT  75.3 94.931 76.68 99.589 ;
     RECT  29.4 95.939 29.712 99.685 ;
     RECT  53.7 99.157 54.696 99.733 ;
     RECT  55.824 99.541 62.232 99.733 ;
     RECT  91.5 99.107 91.812 99.733 ;
     RECT  42.672 99.493 45.912 99.779 ;
     RECT  96.9 98.581 98.232 99.779 ;
     RECT  88.32 99.107 90.072 99.923 ;
     RECT  7.8 98.581 8.808 99.971 ;
     RECT  29.4 99.685 30.072 100.067 ;
     RECT  98.208 99.779 98.232 100.307 ;
     RECT  53.424 99.733 62.232 100.309 ;
     RECT  13.2 99.203 13.704 100.355 ;
     RECT  46.896 98.963 48.612 100.355 ;
     RECT  88.32 99.923 89.112 100.355 ;
     RECT  45.264 99.779 45.912 100.499 ;
     RECT  47.136 100.355 48.612 100.499 ;
     RECT  78 91.235 83.712 100.595 ;
     RECT  10.5 97.571 10.812 100.837 ;
     RECT  21.3 97.571 21.612 100.885 ;
     RECT  78 100.595 81.576 100.931 ;
     RECT  21.3 100.885 22.2 101.027 ;
     RECT  82.752 100.595 83.712 101.027 ;
     RECT  78 100.931 81.48 101.123 ;
     RECT  10.5 100.837 11.064 101.171 ;
     RECT  64.5 97.091 64.812 101.317 ;
     RECT  66 99.589 76.68 101.317 ;
     RECT  31.2 99.587 38.664 101.365 ;
     RECT  84.768 95.987 84.792 101.461 ;
     RECT  47.808 100.499 48.612 101.507 ;
     RECT  80.208 101.123 81.48 101.507 ;
     RECT  95.664 100.261 95.688 101.555 ;
     RECT  53.424 100.309 63.144 101.603 ;
     RECT  84.768 101.461 84.936 101.603 ;
     RECT  31.056 101.365 38.664 101.651 ;
     RECT  64.5 101.317 76.68 101.651 ;
     RECT  47.904 101.507 48.612 101.747 ;
     RECT  20.304 101.029 20.328 101.845 ;
     RECT  21.3 101.027 21.612 101.845 ;
     RECT  20.304 101.845 21.612 102.083 ;
     RECT  42.672 99.779 43.8 102.083 ;
     RECT  45.312 100.499 45.912 102.083 ;
     RECT  50.16 96.323 51.312 102.083 ;
     RECT  53.424 101.603 62.232 102.083 ;
     RECT  21.12 102.083 21.612 102.371 ;
     RECT  31.056 101.651 37.944 102.659 ;
     RECT  64.5 101.651 76.296 102.659 ;
     RECT  78 101.123 79.128 102.659 ;
     RECT  64.5 102.659 67.512 102.707 ;
     RECT  42.672 102.083 43.32 102.803 ;
     RECT  91.5 99.733 92.472 102.803 ;
     RECT  10.5 101.171 10.812 102.901 ;
     RECT  66.096 102.707 67.512 103.091 ;
     RECT  14.496 101.989 14.52 103.235 ;
     RECT  66.864 103.091 67.512 103.235 ;
     RECT  82.8 101.027 83.712 103.235 ;
     RECT  68.88 102.659 76.296 103.283 ;
     RECT  84.768 101.603 84.792 103.331 ;
     RECT  2.4 2.151 2.712 103.419 ;
     RECT  5.1 97.475 5.412 103.419 ;
     RECT  7.8 99.971 8.112 103.419 ;
     RECT  13.2 100.355 13.512 103.419 ;
     RECT  15.9 97.235 16.212 103.419 ;
     RECT  18.6 97.667 18.912 103.419 ;
     RECT  21.3 102.371 21.612 103.419 ;
     RECT  24 98.099 24.312 103.419 ;
     RECT  26.7 96.419 27.012 103.419 ;
     RECT  29.4 100.067 29.712 103.419 ;
     RECT  31.056 102.659 37.812 103.419 ;
     RECT  40.2 99.587 40.512 103.419 ;
     RECT  42.9 102.803 43.32 103.419 ;
     RECT  45.6 102.083 45.912 103.419 ;
     RECT  48.3 101.747 48.612 103.419 ;
     RECT  51 102.083 51.312 103.419 ;
     RECT  64.5 102.707 64.812 103.419 ;
     RECT  67.2 103.235 67.512 103.419 ;
     RECT  78 102.659 78.312 103.419 ;
     RECT  80.7 101.507 81.012 103.419 ;
     RECT  83.4 103.235 83.712 103.419 ;
     RECT  86.1 95.987 86.412 103.419 ;
     RECT  88.8 100.355 89.112 103.419 ;
     RECT  91.5 102.803 91.812 103.419 ;
     RECT  94.2 93.587 94.512 103.419 ;
     RECT  96.9 99.779 97.212 103.419 ;
     RECT  99.6 79.475 99.912 103.419 ;
     RECT  2.592 103.419 2.712 103.433 ;
     RECT  5.292 103.419 5.412 103.433 ;
     RECT  7.992 103.419 8.112 103.433 ;
     RECT  10.368 102.901 10.812 103.433 ;
     RECT  13.392 103.419 13.512 103.433 ;
     RECT  16.092 103.419 16.212 103.433 ;
     RECT  18.792 103.419 18.912 103.433 ;
     RECT  21.492 103.419 21.612 103.433 ;
     RECT  24.192 103.419 24.312 103.433 ;
     RECT  26.892 103.419 27.012 103.433 ;
     RECT  29.592 103.419 29.712 103.433 ;
     RECT  37.692 103.419 37.812 103.433 ;
     RECT  40.392 103.419 40.512 103.433 ;
     RECT  43.092 103.419 43.32 103.433 ;
     RECT  45.792 103.419 45.912 103.433 ;
     RECT  48.492 103.419 48.612 103.433 ;
     RECT  51.192 103.419 51.312 103.433 ;
     RECT  53.424 102.083 62.112 103.433 ;
     RECT  64.692 103.419 64.812 103.433 ;
     RECT  67.392 103.419 67.512 103.433 ;
     RECT  68.88 103.283 75.612 103.433 ;
     RECT  78.192 103.419 78.312 103.433 ;
     RECT  80.892 103.419 81.012 103.433 ;
     RECT  83.592 103.419 83.712 103.433 ;
     RECT  86.292 103.419 86.412 103.433 ;
     RECT  88.992 103.419 89.112 103.433 ;
     RECT  91.692 103.419 91.812 103.433 ;
     RECT  94.392 103.419 94.512 103.433 ;
     RECT  97.092 103.419 97.212 103.433 ;
     RECT  99.792 103.419 99.912 103.433 ;
     RECT  53.424 103.433 61.896 103.477 ;
     RECT  10.368 103.433 10.392 103.523 ;
     RECT  43.296 103.433 43.32 103.523 ;
     RECT  31.056 103.419 36.552 103.717 ;
     RECT  53.232 103.477 61.896 103.717 ;
     RECT  30.96 103.717 36.552 103.765 ;
     RECT  30.864 103.765 36.552 104.245 ;
     RECT  52.848 103.717 61.896 104.245 ;
     RECT  47.136 105.589 47.16 105.637 ;
     RECT  46.752 105.637 47.16 105.731 ;
     RECT  30.48 104.245 36.552 105.744 ;
     RECT  52.752 104.245 61.896 105.744 ;
     RECT  68.88 103.433 74.952 105.744 ;
     RECT  46.752 105.731 46.776 105.779 ;
  END
END qfd_landh0_600_EN_104x106
END LIBRARY
